VERSION 5.8 ;
BUSBITCHARS "[]" ;
DIVIDERCHAR "/" ;
UNITS
    DATABASE MICRONS 1000 ;
END UNITS

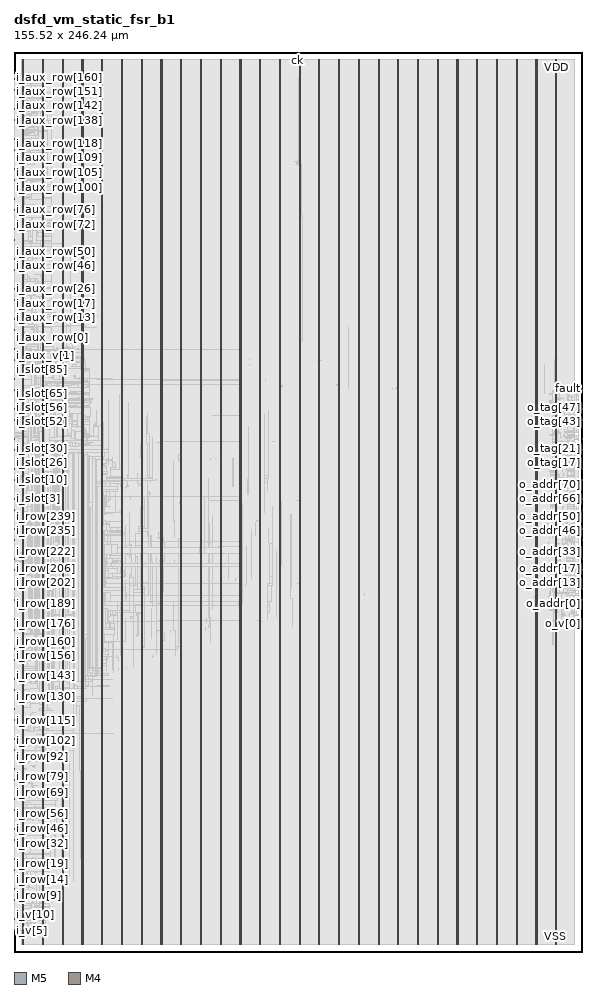
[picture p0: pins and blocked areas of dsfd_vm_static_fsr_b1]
MACRO dsfd_vm_static_fsr_b1
  FOREIGN dsfd_vm_static_fsr_b1 0 0 ;
  CLASS BLOCK ;
  SIZE 155.52 BY 246.24 ;
  PIN ck
    DIRECTION INPUT ;
    USE SIGNAL ;
    PORT
      LAYER M5 ;
        RECT  77.52 246.156 77.544 246.24 ;
    END
  END ck
  PIN fault
    DIRECTION OUTPUT ;
    USE SIGNAL ;
    PORT
      LAYER M4 ;
        RECT  155.436 154.176 155.52 154.2 ;
    END
  END fault
  PIN i_aux_row[0]
    DIRECTION INPUT ;
    USE SIGNAL ;
    PORT
      LAYER M4 ;
        RECT  0 168 0.084 168.024 ;
    END
  END i_aux_row[0]
  PIN i_aux_row[100]
    DIRECTION INPUT ;
    USE SIGNAL ;
    PORT
      LAYER M4 ;
        RECT  0 211.2 0.084 211.224 ;
    END
  END i_aux_row[100]
  PIN i_aux_row[101]
    DIRECTION INPUT ;
    USE SIGNAL ;
    PORT
      LAYER M4 ;
        RECT  0 211.632 0.084 211.656 ;
    END
  END i_aux_row[101]
  PIN i_aux_row[102]
    DIRECTION INPUT ;
    USE SIGNAL ;
    PORT
      LAYER M4 ;
        RECT  0 212.064 0.084 212.088 ;
    END
  END i_aux_row[102]
  PIN i_aux_row[103]
    DIRECTION INPUT ;
    USE SIGNAL ;
    PORT
      LAYER M4 ;
        RECT  0 212.496 0.084 212.52 ;
    END
  END i_aux_row[103]
  PIN i_aux_row[104]
    DIRECTION INPUT ;
    USE SIGNAL ;
    PORT
      LAYER M4 ;
        RECT  0 212.928 0.084 212.952 ;
    END
  END i_aux_row[104]
  PIN i_aux_row[105]
    DIRECTION INPUT ;
    USE SIGNAL ;
    PORT
      LAYER M4 ;
        RECT  0 213.36 0.084 213.384 ;
    END
  END i_aux_row[105]
  PIN i_aux_row[106]
    DIRECTION INPUT ;
    USE SIGNAL ;
    PORT
      LAYER M4 ;
        RECT  0 213.792 0.084 213.816 ;
    END
  END i_aux_row[106]
  PIN i_aux_row[107]
    DIRECTION INPUT ;
    USE SIGNAL ;
    PORT
      LAYER M4 ;
        RECT  0 214.224 0.084 214.248 ;
    END
  END i_aux_row[107]
  PIN i_aux_row[108]
    DIRECTION INPUT ;
    USE SIGNAL ;
    PORT
      LAYER M4 ;
        RECT  0 214.656 0.084 214.68 ;
    END
  END i_aux_row[108]
  PIN i_aux_row[109]
    DIRECTION INPUT ;
    USE SIGNAL ;
    PORT
      LAYER M4 ;
        RECT  0 215.088 0.084 215.112 ;
    END
  END i_aux_row[109]
  PIN i_aux_row[10]
    DIRECTION INPUT ;
    USE SIGNAL ;
    PORT
      LAYER M4 ;
        RECT  0 172.32 0.084 172.344 ;
    END
  END i_aux_row[10]
  PIN i_aux_row[110]
    DIRECTION INPUT ;
    USE SIGNAL ;
    PORT
      LAYER M4 ;
        RECT  0 215.52 0.084 215.544 ;
    END
  END i_aux_row[110]
  PIN i_aux_row[111]
    DIRECTION INPUT ;
    USE SIGNAL ;
    PORT
      LAYER M4 ;
        RECT  0 215.952 0.084 215.976 ;
    END
  END i_aux_row[111]
  PIN i_aux_row[112]
    DIRECTION INPUT ;
    USE SIGNAL ;
    PORT
      LAYER M4 ;
        RECT  0 216.384 0.084 216.408 ;
    END
  END i_aux_row[112]
  PIN i_aux_row[113]
    DIRECTION INPUT ;
    USE SIGNAL ;
    PORT
      LAYER M4 ;
        RECT  0 216.816 0.084 216.84 ;
    END
  END i_aux_row[113]
  PIN i_aux_row[114]
    DIRECTION INPUT ;
    USE SIGNAL ;
    PORT
      LAYER M4 ;
        RECT  0 217.248 0.084 217.272 ;
    END
  END i_aux_row[114]
  PIN i_aux_row[115]
    DIRECTION INPUT ;
    USE SIGNAL ;
    PORT
      LAYER M4 ;
        RECT  0 217.68 0.084 217.704 ;
    END
  END i_aux_row[115]
  PIN i_aux_row[116]
    DIRECTION INPUT ;
    USE SIGNAL ;
    PORT
      LAYER M4 ;
        RECT  0 218.112 0.084 218.136 ;
    END
  END i_aux_row[116]
  PIN i_aux_row[117]
    DIRECTION INPUT ;
    USE SIGNAL ;
    PORT
      LAYER M4 ;
        RECT  0 218.544 0.084 218.568 ;
    END
  END i_aux_row[117]
  PIN i_aux_row[118]
    DIRECTION INPUT ;
    USE SIGNAL ;
    PORT
      LAYER M4 ;
        RECT  0 218.976 0.084 219 ;
    END
  END i_aux_row[118]
  PIN i_aux_row[119]
    DIRECTION INPUT ;
    USE SIGNAL ;
    PORT
      LAYER M4 ;
        RECT  0 219.408 0.084 219.432 ;
    END
  END i_aux_row[119]
  PIN i_aux_row[11]
    DIRECTION INPUT ;
    USE SIGNAL ;
    PORT
      LAYER M4 ;
        RECT  0 172.752 0.084 172.776 ;
    END
  END i_aux_row[11]
  PIN i_aux_row[120]
    DIRECTION INPUT ;
    USE SIGNAL ;
    PORT
      LAYER M4 ;
        RECT  0 219.84 0.084 219.864 ;
    END
  END i_aux_row[120]
  PIN i_aux_row[121]
    DIRECTION INPUT ;
    USE SIGNAL ;
    PORT
      LAYER M4 ;
        RECT  0 220.272 0.084 220.296 ;
    END
  END i_aux_row[121]
  PIN i_aux_row[122]
    DIRECTION INPUT ;
    USE SIGNAL ;
    PORT
      LAYER M4 ;
        RECT  0 220.704 0.084 220.728 ;
    END
  END i_aux_row[122]
  PIN i_aux_row[123]
    DIRECTION INPUT ;
    USE SIGNAL ;
    PORT
      LAYER M4 ;
        RECT  0 221.136 0.084 221.16 ;
    END
  END i_aux_row[123]
  PIN i_aux_row[124]
    DIRECTION INPUT ;
    USE SIGNAL ;
    PORT
      LAYER M4 ;
        RECT  0 221.568 0.084 221.592 ;
    END
  END i_aux_row[124]
  PIN i_aux_row[125]
    DIRECTION INPUT ;
    USE SIGNAL ;
    PORT
      LAYER M4 ;
        RECT  0 222 0.084 222.024 ;
    END
  END i_aux_row[125]
  PIN i_aux_row[126]
    DIRECTION INPUT ;
    USE SIGNAL ;
    PORT
      LAYER M4 ;
        RECT  0 222.432 0.084 222.456 ;
    END
  END i_aux_row[126]
  PIN i_aux_row[127]
    DIRECTION INPUT ;
    USE SIGNAL ;
    PORT
      LAYER M4 ;
        RECT  0 222.864 0.084 222.888 ;
    END
  END i_aux_row[127]
  PIN i_aux_row[128]
    DIRECTION INPUT ;
    USE SIGNAL ;
    PORT
      LAYER M4 ;
        RECT  0 223.296 0.084 223.32 ;
    END
  END i_aux_row[128]
  PIN i_aux_row[129]
    DIRECTION INPUT ;
    USE SIGNAL ;
    PORT
      LAYER M4 ;
        RECT  0 223.728 0.084 223.752 ;
    END
  END i_aux_row[129]
  PIN i_aux_row[12]
    DIRECTION INPUT ;
    USE SIGNAL ;
    PORT
      LAYER M4 ;
        RECT  0 173.184 0.084 173.208 ;
    END
  END i_aux_row[12]
  PIN i_aux_row[130]
    DIRECTION INPUT ;
    USE SIGNAL ;
    PORT
      LAYER M4 ;
        RECT  0 224.16 0.084 224.184 ;
    END
  END i_aux_row[130]
  PIN i_aux_row[131]
    DIRECTION INPUT ;
    USE SIGNAL ;
    PORT
      LAYER M4 ;
        RECT  0 224.592 0.084 224.616 ;
    END
  END i_aux_row[131]
  PIN i_aux_row[132]
    DIRECTION INPUT ;
    USE SIGNAL ;
    PORT
      LAYER M4 ;
        RECT  0 225.024 0.084 225.048 ;
    END
  END i_aux_row[132]
  PIN i_aux_row[133]
    DIRECTION INPUT ;
    USE SIGNAL ;
    PORT
      LAYER M4 ;
        RECT  0 225.456 0.084 225.48 ;
    END
  END i_aux_row[133]
  PIN i_aux_row[134]
    DIRECTION INPUT ;
    USE SIGNAL ;
    PORT
      LAYER M4 ;
        RECT  0 225.888 0.084 225.912 ;
    END
  END i_aux_row[134]
  PIN i_aux_row[135]
    DIRECTION INPUT ;
    USE SIGNAL ;
    PORT
      LAYER M4 ;
        RECT  0 226.32 0.084 226.344 ;
    END
  END i_aux_row[135]
  PIN i_aux_row[136]
    DIRECTION INPUT ;
    USE SIGNAL ;
    PORT
      LAYER M4 ;
        RECT  0 226.752 0.084 226.776 ;
    END
  END i_aux_row[136]
  PIN i_aux_row[137]
    DIRECTION INPUT ;
    USE SIGNAL ;
    PORT
      LAYER M4 ;
        RECT  0 227.184 0.084 227.208 ;
    END
  END i_aux_row[137]
  PIN i_aux_row[138]
    DIRECTION INPUT ;
    USE SIGNAL ;
    PORT
      LAYER M4 ;
        RECT  0 227.616 0.084 227.64 ;
    END
  END i_aux_row[138]
  PIN i_aux_row[139]
    DIRECTION INPUT ;
    USE SIGNAL ;
    PORT
      LAYER M4 ;
        RECT  0 228.048 0.084 228.072 ;
    END
  END i_aux_row[139]
  PIN i_aux_row[13]
    DIRECTION INPUT ;
    USE SIGNAL ;
    PORT
      LAYER M4 ;
        RECT  0 173.616 0.084 173.64 ;
    END
  END i_aux_row[13]
  PIN i_aux_row[140]
    DIRECTION INPUT ;
    USE SIGNAL ;
    PORT
      LAYER M4 ;
        RECT  0 228.48 0.084 228.504 ;
    END
  END i_aux_row[140]
  PIN i_aux_row[141]
    DIRECTION INPUT ;
    USE SIGNAL ;
    PORT
      LAYER M4 ;
        RECT  0 228.912 0.084 228.936 ;
    END
  END i_aux_row[141]
  PIN i_aux_row[142]
    DIRECTION INPUT ;
    USE SIGNAL ;
    PORT
      LAYER M4 ;
        RECT  0 229.344 0.084 229.368 ;
    END
  END i_aux_row[142]
  PIN i_aux_row[143]
    DIRECTION INPUT ;
    USE SIGNAL ;
    PORT
      LAYER M4 ;
        RECT  0 229.776 0.084 229.8 ;
    END
  END i_aux_row[143]
  PIN i_aux_row[144]
    DIRECTION INPUT ;
    USE SIGNAL ;
    PORT
      LAYER M4 ;
        RECT  0 230.208 0.084 230.232 ;
    END
  END i_aux_row[144]
  PIN i_aux_row[145]
    DIRECTION INPUT ;
    USE SIGNAL ;
    PORT
      LAYER M4 ;
        RECT  0 230.64 0.084 230.664 ;
    END
  END i_aux_row[145]
  PIN i_aux_row[146]
    DIRECTION INPUT ;
    USE SIGNAL ;
    PORT
      LAYER M4 ;
        RECT  0 231.072 0.084 231.096 ;
    END
  END i_aux_row[146]
  PIN i_aux_row[147]
    DIRECTION INPUT ;
    USE SIGNAL ;
    PORT
      LAYER M4 ;
        RECT  0 231.504 0.084 231.528 ;
    END
  END i_aux_row[147]
  PIN i_aux_row[148]
    DIRECTION INPUT ;
    USE SIGNAL ;
    PORT
      LAYER M4 ;
        RECT  0 231.936 0.084 231.96 ;
    END
  END i_aux_row[148]
  PIN i_aux_row[149]
    DIRECTION INPUT ;
    USE SIGNAL ;
    PORT
      LAYER M4 ;
        RECT  0 232.368 0.084 232.392 ;
    END
  END i_aux_row[149]
  PIN i_aux_row[14]
    DIRECTION INPUT ;
    USE SIGNAL ;
    PORT
      LAYER M4 ;
        RECT  0 174.048 0.084 174.072 ;
    END
  END i_aux_row[14]
  PIN i_aux_row[150]
    DIRECTION INPUT ;
    USE SIGNAL ;
    PORT
      LAYER M4 ;
        RECT  0 232.8 0.084 232.824 ;
    END
  END i_aux_row[150]
  PIN i_aux_row[151]
    DIRECTION INPUT ;
    USE SIGNAL ;
    PORT
      LAYER M4 ;
        RECT  0 233.232 0.084 233.256 ;
    END
  END i_aux_row[151]
  PIN i_aux_row[152]
    DIRECTION INPUT ;
    USE SIGNAL ;
    PORT
      LAYER M4 ;
        RECT  0 233.664 0.084 233.688 ;
    END
  END i_aux_row[152]
  PIN i_aux_row[153]
    DIRECTION INPUT ;
    USE SIGNAL ;
    PORT
      LAYER M4 ;
        RECT  0 234.096 0.084 234.12 ;
    END
  END i_aux_row[153]
  PIN i_aux_row[154]
    DIRECTION INPUT ;
    USE SIGNAL ;
    PORT
      LAYER M4 ;
        RECT  0 234.528 0.084 234.552 ;
    END
  END i_aux_row[154]
  PIN i_aux_row[155]
    DIRECTION INPUT ;
    USE SIGNAL ;
    PORT
      LAYER M4 ;
        RECT  0 234.96 0.084 234.984 ;
    END
  END i_aux_row[155]
  PIN i_aux_row[156]
    DIRECTION INPUT ;
    USE SIGNAL ;
    PORT
      LAYER M4 ;
        RECT  0 235.392 0.084 235.416 ;
    END
  END i_aux_row[156]
  PIN i_aux_row[157]
    DIRECTION INPUT ;
    USE SIGNAL ;
    PORT
      LAYER M4 ;
        RECT  0 235.824 0.084 235.848 ;
    END
  END i_aux_row[157]
  PIN i_aux_row[158]
    DIRECTION INPUT ;
    USE SIGNAL ;
    PORT
      LAYER M4 ;
        RECT  0 236.256 0.084 236.28 ;
    END
  END i_aux_row[158]
  PIN i_aux_row[159]
    DIRECTION INPUT ;
    USE SIGNAL ;
    PORT
      LAYER M4 ;
        RECT  0 236.688 0.084 236.712 ;
    END
  END i_aux_row[159]
  PIN i_aux_row[15]
    DIRECTION INPUT ;
    USE SIGNAL ;
    PORT
      LAYER M4 ;
        RECT  0 174.48 0.084 174.504 ;
    END
  END i_aux_row[15]
  PIN i_aux_row[160]
    DIRECTION INPUT ;
    USE SIGNAL ;
    PORT
      LAYER M4 ;
        RECT  0 237.12 0.084 237.144 ;
    END
  END i_aux_row[160]
  PIN i_aux_row[161]
    DIRECTION INPUT ;
    USE SIGNAL ;
    PORT
      LAYER M4 ;
        RECT  0 237.552 0.084 237.576 ;
    END
  END i_aux_row[161]
  PIN i_aux_row[162]
    DIRECTION INPUT ;
    USE SIGNAL ;
    PORT
      LAYER M4 ;
        RECT  0 237.984 0.084 238.008 ;
    END
  END i_aux_row[162]
  PIN i_aux_row[163]
    DIRECTION INPUT ;
    USE SIGNAL ;
    PORT
      LAYER M4 ;
        RECT  0 238.416 0.084 238.44 ;
    END
  END i_aux_row[163]
  PIN i_aux_row[164]
    DIRECTION INPUT ;
    USE SIGNAL ;
    PORT
      LAYER M4 ;
        RECT  0 238.848 0.084 238.872 ;
    END
  END i_aux_row[164]
  PIN i_aux_row[165]
    DIRECTION INPUT ;
    USE SIGNAL ;
    PORT
      LAYER M4 ;
        RECT  0 239.28 0.084 239.304 ;
    END
  END i_aux_row[165]
  PIN i_aux_row[166]
    DIRECTION INPUT ;
    USE SIGNAL ;
    PORT
      LAYER M4 ;
        RECT  0 239.712 0.084 239.736 ;
    END
  END i_aux_row[166]
  PIN i_aux_row[167]
    DIRECTION INPUT ;
    USE SIGNAL ;
    PORT
      LAYER M4 ;
        RECT  0 240.144 0.084 240.168 ;
    END
  END i_aux_row[167]
  PIN i_aux_row[16]
    DIRECTION INPUT ;
    USE SIGNAL ;
    PORT
      LAYER M4 ;
        RECT  0 174.912 0.084 174.936 ;
    END
  END i_aux_row[16]
  PIN i_aux_row[17]
    DIRECTION INPUT ;
    USE SIGNAL ;
    PORT
      LAYER M4 ;
        RECT  0 175.344 0.084 175.368 ;
    END
  END i_aux_row[17]
  PIN i_aux_row[18]
    DIRECTION INPUT ;
    USE SIGNAL ;
    PORT
      LAYER M4 ;
        RECT  0 175.776 0.084 175.8 ;
    END
  END i_aux_row[18]
  PIN i_aux_row[19]
    DIRECTION INPUT ;
    USE SIGNAL ;
    PORT
      LAYER M4 ;
        RECT  0 176.208 0.084 176.232 ;
    END
  END i_aux_row[19]
  PIN i_aux_row[1]
    DIRECTION INPUT ;
    USE SIGNAL ;
    PORT
      LAYER M4 ;
        RECT  0 168.432 0.084 168.456 ;
    END
  END i_aux_row[1]
  PIN i_aux_row[20]
    DIRECTION INPUT ;
    USE SIGNAL ;
    PORT
      LAYER M4 ;
        RECT  0 176.64 0.084 176.664 ;
    END
  END i_aux_row[20]
  PIN i_aux_row[21]
    DIRECTION INPUT ;
    USE SIGNAL ;
    PORT
      LAYER M4 ;
        RECT  0 177.072 0.084 177.096 ;
    END
  END i_aux_row[21]
  PIN i_aux_row[22]
    DIRECTION INPUT ;
    USE SIGNAL ;
    PORT
      LAYER M4 ;
        RECT  0 177.504 0.084 177.528 ;
    END
  END i_aux_row[22]
  PIN i_aux_row[23]
    DIRECTION INPUT ;
    USE SIGNAL ;
    PORT
      LAYER M4 ;
        RECT  0 177.936 0.084 177.96 ;
    END
  END i_aux_row[23]
  PIN i_aux_row[24]
    DIRECTION INPUT ;
    USE SIGNAL ;
    PORT
      LAYER M4 ;
        RECT  0 178.368 0.084 178.392 ;
    END
  END i_aux_row[24]
  PIN i_aux_row[25]
    DIRECTION INPUT ;
    USE SIGNAL ;
    PORT
      LAYER M4 ;
        RECT  0 178.8 0.084 178.824 ;
    END
  END i_aux_row[25]
  PIN i_aux_row[26]
    DIRECTION INPUT ;
    USE SIGNAL ;
    PORT
      LAYER M4 ;
        RECT  0 179.232 0.084 179.256 ;
    END
  END i_aux_row[26]
  PIN i_aux_row[27]
    DIRECTION INPUT ;
    USE SIGNAL ;
    PORT
      LAYER M4 ;
        RECT  0 179.664 0.084 179.688 ;
    END
  END i_aux_row[27]
  PIN i_aux_row[28]
    DIRECTION INPUT ;
    USE SIGNAL ;
    PORT
      LAYER M4 ;
        RECT  0 180.096 0.084 180.12 ;
    END
  END i_aux_row[28]
  PIN i_aux_row[29]
    DIRECTION INPUT ;
    USE SIGNAL ;
    PORT
      LAYER M4 ;
        RECT  0 180.528 0.084 180.552 ;
    END
  END i_aux_row[29]
  PIN i_aux_row[2]
    DIRECTION INPUT ;
    USE SIGNAL ;
    PORT
      LAYER M4 ;
        RECT  0 168.864 0.084 168.888 ;
    END
  END i_aux_row[2]
  PIN i_aux_row[30]
    DIRECTION INPUT ;
    USE SIGNAL ;
    PORT
      LAYER M4 ;
        RECT  0 180.96 0.084 180.984 ;
    END
  END i_aux_row[30]
  PIN i_aux_row[31]
    DIRECTION INPUT ;
    USE SIGNAL ;
    PORT
      LAYER M4 ;
        RECT  0 181.392 0.084 181.416 ;
    END
  END i_aux_row[31]
  PIN i_aux_row[32]
    DIRECTION INPUT ;
    USE SIGNAL ;
    PORT
      LAYER M4 ;
        RECT  0 181.824 0.084 181.848 ;
    END
  END i_aux_row[32]
  PIN i_aux_row[33]
    DIRECTION INPUT ;
    USE SIGNAL ;
    PORT
      LAYER M4 ;
        RECT  0 182.256 0.084 182.28 ;
    END
  END i_aux_row[33]
  PIN i_aux_row[34]
    DIRECTION INPUT ;
    USE SIGNAL ;
    PORT
      LAYER M4 ;
        RECT  0 182.688 0.084 182.712 ;
    END
  END i_aux_row[34]
  PIN i_aux_row[35]
    DIRECTION INPUT ;
    USE SIGNAL ;
    PORT
      LAYER M4 ;
        RECT  0 183.12 0.084 183.144 ;
    END
  END i_aux_row[35]
  PIN i_aux_row[36]
    DIRECTION INPUT ;
    USE SIGNAL ;
    PORT
      LAYER M4 ;
        RECT  0 183.552 0.084 183.576 ;
    END
  END i_aux_row[36]
  PIN i_aux_row[37]
    DIRECTION INPUT ;
    USE SIGNAL ;
    PORT
      LAYER M4 ;
        RECT  0 183.984 0.084 184.008 ;
    END
  END i_aux_row[37]
  PIN i_aux_row[38]
    DIRECTION INPUT ;
    USE SIGNAL ;
    PORT
      LAYER M4 ;
        RECT  0 184.416 0.084 184.44 ;
    END
  END i_aux_row[38]
  PIN i_aux_row[39]
    DIRECTION INPUT ;
    USE SIGNAL ;
    PORT
      LAYER M4 ;
        RECT  0 184.848 0.084 184.872 ;
    END
  END i_aux_row[39]
  PIN i_aux_row[3]
    DIRECTION INPUT ;
    USE SIGNAL ;
    PORT
      LAYER M4 ;
        RECT  0 169.296 0.084 169.32 ;
    END
  END i_aux_row[3]
  PIN i_aux_row[40]
    DIRECTION INPUT ;
    USE SIGNAL ;
    PORT
      LAYER M4 ;
        RECT  0 185.28 0.084 185.304 ;
    END
  END i_aux_row[40]
  PIN i_aux_row[41]
    DIRECTION INPUT ;
    USE SIGNAL ;
    PORT
      LAYER M4 ;
        RECT  0 185.712 0.084 185.736 ;
    END
  END i_aux_row[41]
  PIN i_aux_row[42]
    DIRECTION INPUT ;
    USE SIGNAL ;
    PORT
      LAYER M4 ;
        RECT  0 186.144 0.084 186.168 ;
    END
  END i_aux_row[42]
  PIN i_aux_row[43]
    DIRECTION INPUT ;
    USE SIGNAL ;
    PORT
      LAYER M4 ;
        RECT  0 186.576 0.084 186.6 ;
    END
  END i_aux_row[43]
  PIN i_aux_row[44]
    DIRECTION INPUT ;
    USE SIGNAL ;
    PORT
      LAYER M4 ;
        RECT  0 187.008 0.084 187.032 ;
    END
  END i_aux_row[44]
  PIN i_aux_row[45]
    DIRECTION INPUT ;
    USE SIGNAL ;
    PORT
      LAYER M4 ;
        RECT  0 187.44 0.084 187.464 ;
    END
  END i_aux_row[45]
  PIN i_aux_row[46]
    DIRECTION INPUT ;
    USE SIGNAL ;
    PORT
      LAYER M4 ;
        RECT  0 187.872 0.084 187.896 ;
    END
  END i_aux_row[46]
  PIN i_aux_row[47]
    DIRECTION INPUT ;
    USE SIGNAL ;
    PORT
      LAYER M4 ;
        RECT  0 188.304 0.084 188.328 ;
    END
  END i_aux_row[47]
  PIN i_aux_row[48]
    DIRECTION INPUT ;
    USE SIGNAL ;
    PORT
      LAYER M4 ;
        RECT  0 188.736 0.084 188.76 ;
    END
  END i_aux_row[48]
  PIN i_aux_row[49]
    DIRECTION INPUT ;
    USE SIGNAL ;
    PORT
      LAYER M4 ;
        RECT  0 189.168 0.084 189.192 ;
    END
  END i_aux_row[49]
  PIN i_aux_row[4]
    DIRECTION INPUT ;
    USE SIGNAL ;
    PORT
      LAYER M4 ;
        RECT  0 169.728 0.084 169.752 ;
    END
  END i_aux_row[4]
  PIN i_aux_row[50]
    DIRECTION INPUT ;
    USE SIGNAL ;
    PORT
      LAYER M4 ;
        RECT  0 189.6 0.084 189.624 ;
    END
  END i_aux_row[50]
  PIN i_aux_row[51]
    DIRECTION INPUT ;
    USE SIGNAL ;
    PORT
      LAYER M4 ;
        RECT  0 190.032 0.084 190.056 ;
    END
  END i_aux_row[51]
  PIN i_aux_row[52]
    DIRECTION INPUT ;
    USE SIGNAL ;
    PORT
      LAYER M4 ;
        RECT  0 190.464 0.084 190.488 ;
    END
  END i_aux_row[52]
  PIN i_aux_row[53]
    DIRECTION INPUT ;
    USE SIGNAL ;
    PORT
      LAYER M4 ;
        RECT  0 190.896 0.084 190.92 ;
    END
  END i_aux_row[53]
  PIN i_aux_row[54]
    DIRECTION INPUT ;
    USE SIGNAL ;
    PORT
      LAYER M4 ;
        RECT  0 191.328 0.084 191.352 ;
    END
  END i_aux_row[54]
  PIN i_aux_row[55]
    DIRECTION INPUT ;
    USE SIGNAL ;
    PORT
      LAYER M4 ;
        RECT  0 191.76 0.084 191.784 ;
    END
  END i_aux_row[55]
  PIN i_aux_row[56]
    DIRECTION INPUT ;
    USE SIGNAL ;
    PORT
      LAYER M4 ;
        RECT  0 192.192 0.084 192.216 ;
    END
  END i_aux_row[56]
  PIN i_aux_row[57]
    DIRECTION INPUT ;
    USE SIGNAL ;
    PORT
      LAYER M4 ;
        RECT  0 192.624 0.084 192.648 ;
    END
  END i_aux_row[57]
  PIN i_aux_row[58]
    DIRECTION INPUT ;
    USE SIGNAL ;
    PORT
      LAYER M4 ;
        RECT  0 193.056 0.084 193.08 ;
    END
  END i_aux_row[58]
  PIN i_aux_row[59]
    DIRECTION INPUT ;
    USE SIGNAL ;
    PORT
      LAYER M4 ;
        RECT  0 193.488 0.084 193.512 ;
    END
  END i_aux_row[59]
  PIN i_aux_row[5]
    DIRECTION INPUT ;
    USE SIGNAL ;
    PORT
      LAYER M4 ;
        RECT  0 170.16 0.084 170.184 ;
    END
  END i_aux_row[5]
  PIN i_aux_row[60]
    DIRECTION INPUT ;
    USE SIGNAL ;
    PORT
      LAYER M4 ;
        RECT  0 193.92 0.084 193.944 ;
    END
  END i_aux_row[60]
  PIN i_aux_row[61]
    DIRECTION INPUT ;
    USE SIGNAL ;
    PORT
      LAYER M4 ;
        RECT  0 194.352 0.084 194.376 ;
    END
  END i_aux_row[61]
  PIN i_aux_row[62]
    DIRECTION INPUT ;
    USE SIGNAL ;
    PORT
      LAYER M4 ;
        RECT  0 194.784 0.084 194.808 ;
    END
  END i_aux_row[62]
  PIN i_aux_row[63]
    DIRECTION INPUT ;
    USE SIGNAL ;
    PORT
      LAYER M4 ;
        RECT  0 195.216 0.084 195.24 ;
    END
  END i_aux_row[63]
  PIN i_aux_row[64]
    DIRECTION INPUT ;
    USE SIGNAL ;
    PORT
      LAYER M4 ;
        RECT  0 195.648 0.084 195.672 ;
    END
  END i_aux_row[64]
  PIN i_aux_row[65]
    DIRECTION INPUT ;
    USE SIGNAL ;
    PORT
      LAYER M4 ;
        RECT  0 196.08 0.084 196.104 ;
    END
  END i_aux_row[65]
  PIN i_aux_row[66]
    DIRECTION INPUT ;
    USE SIGNAL ;
    PORT
      LAYER M4 ;
        RECT  0 196.512 0.084 196.536 ;
    END
  END i_aux_row[66]
  PIN i_aux_row[67]
    DIRECTION INPUT ;
    USE SIGNAL ;
    PORT
      LAYER M4 ;
        RECT  0 196.944 0.084 196.968 ;
    END
  END i_aux_row[67]
  PIN i_aux_row[68]
    DIRECTION INPUT ;
    USE SIGNAL ;
    PORT
      LAYER M4 ;
        RECT  0 197.376 0.084 197.4 ;
    END
  END i_aux_row[68]
  PIN i_aux_row[69]
    DIRECTION INPUT ;
    USE SIGNAL ;
    PORT
      LAYER M4 ;
        RECT  0 197.808 0.084 197.832 ;
    END
  END i_aux_row[69]
  PIN i_aux_row[6]
    DIRECTION INPUT ;
    USE SIGNAL ;
    PORT
      LAYER M4 ;
        RECT  0 170.592 0.084 170.616 ;
    END
  END i_aux_row[6]
  PIN i_aux_row[70]
    DIRECTION INPUT ;
    USE SIGNAL ;
    PORT
      LAYER M4 ;
        RECT  0 198.24 0.084 198.264 ;
    END
  END i_aux_row[70]
  PIN i_aux_row[71]
    DIRECTION INPUT ;
    USE SIGNAL ;
    PORT
      LAYER M4 ;
        RECT  0 198.672 0.084 198.696 ;
    END
  END i_aux_row[71]
  PIN i_aux_row[72]
    DIRECTION INPUT ;
    USE SIGNAL ;
    PORT
      LAYER M4 ;
        RECT  0 199.104 0.084 199.128 ;
    END
  END i_aux_row[72]
  PIN i_aux_row[73]
    DIRECTION INPUT ;
    USE SIGNAL ;
    PORT
      LAYER M4 ;
        RECT  0 199.536 0.084 199.56 ;
    END
  END i_aux_row[73]
  PIN i_aux_row[74]
    DIRECTION INPUT ;
    USE SIGNAL ;
    PORT
      LAYER M4 ;
        RECT  0 199.968 0.084 199.992 ;
    END
  END i_aux_row[74]
  PIN i_aux_row[75]
    DIRECTION INPUT ;
    USE SIGNAL ;
    PORT
      LAYER M4 ;
        RECT  0 200.4 0.084 200.424 ;
    END
  END i_aux_row[75]
  PIN i_aux_row[76]
    DIRECTION INPUT ;
    USE SIGNAL ;
    PORT
      LAYER M4 ;
        RECT  0 200.832 0.084 200.856 ;
    END
  END i_aux_row[76]
  PIN i_aux_row[77]
    DIRECTION INPUT ;
    USE SIGNAL ;
    PORT
      LAYER M4 ;
        RECT  0 201.264 0.084 201.288 ;
    END
  END i_aux_row[77]
  PIN i_aux_row[78]
    DIRECTION INPUT ;
    USE SIGNAL ;
    PORT
      LAYER M4 ;
        RECT  0 201.696 0.084 201.72 ;
    END
  END i_aux_row[78]
  PIN i_aux_row[79]
    DIRECTION INPUT ;
    USE SIGNAL ;
    PORT
      LAYER M4 ;
        RECT  0 202.128 0.084 202.152 ;
    END
  END i_aux_row[79]
  PIN i_aux_row[7]
    DIRECTION INPUT ;
    USE SIGNAL ;
    PORT
      LAYER M4 ;
        RECT  0 171.024 0.084 171.048 ;
    END
  END i_aux_row[7]
  PIN i_aux_row[80]
    DIRECTION INPUT ;
    USE SIGNAL ;
    PORT
      LAYER M4 ;
        RECT  0 202.56 0.084 202.584 ;
    END
  END i_aux_row[80]
  PIN i_aux_row[81]
    DIRECTION INPUT ;
    USE SIGNAL ;
    PORT
      LAYER M4 ;
        RECT  0 202.992 0.084 203.016 ;
    END
  END i_aux_row[81]
  PIN i_aux_row[82]
    DIRECTION INPUT ;
    USE SIGNAL ;
    PORT
      LAYER M4 ;
        RECT  0 203.424 0.084 203.448 ;
    END
  END i_aux_row[82]
  PIN i_aux_row[83]
    DIRECTION INPUT ;
    USE SIGNAL ;
    PORT
      LAYER M4 ;
        RECT  0 203.856 0.084 203.88 ;
    END
  END i_aux_row[83]
  PIN i_aux_row[84]
    DIRECTION INPUT ;
    USE SIGNAL ;
    PORT
      LAYER M4 ;
        RECT  0 204.288 0.084 204.312 ;
    END
  END i_aux_row[84]
  PIN i_aux_row[85]
    DIRECTION INPUT ;
    USE SIGNAL ;
    PORT
      LAYER M4 ;
        RECT  0 204.72 0.084 204.744 ;
    END
  END i_aux_row[85]
  PIN i_aux_row[86]
    DIRECTION INPUT ;
    USE SIGNAL ;
    PORT
      LAYER M4 ;
        RECT  0 205.152 0.084 205.176 ;
    END
  END i_aux_row[86]
  PIN i_aux_row[87]
    DIRECTION INPUT ;
    USE SIGNAL ;
    PORT
      LAYER M4 ;
        RECT  0 205.584 0.084 205.608 ;
    END
  END i_aux_row[87]
  PIN i_aux_row[88]
    DIRECTION INPUT ;
    USE SIGNAL ;
    PORT
      LAYER M4 ;
        RECT  0 206.016 0.084 206.04 ;
    END
  END i_aux_row[88]
  PIN i_aux_row[89]
    DIRECTION INPUT ;
    USE SIGNAL ;
    PORT
      LAYER M4 ;
        RECT  0 206.448 0.084 206.472 ;
    END
  END i_aux_row[89]
  PIN i_aux_row[8]
    DIRECTION INPUT ;
    USE SIGNAL ;
    PORT
      LAYER M4 ;
        RECT  0 171.456 0.084 171.48 ;
    END
  END i_aux_row[8]
  PIN i_aux_row[90]
    DIRECTION INPUT ;
    USE SIGNAL ;
    PORT
      LAYER M4 ;
        RECT  0 206.88 0.084 206.904 ;
    END
  END i_aux_row[90]
  PIN i_aux_row[91]
    DIRECTION INPUT ;
    USE SIGNAL ;
    PORT
      LAYER M4 ;
        RECT  0 207.312 0.084 207.336 ;
    END
  END i_aux_row[91]
  PIN i_aux_row[92]
    DIRECTION INPUT ;
    USE SIGNAL ;
    PORT
      LAYER M4 ;
        RECT  0 207.744 0.084 207.768 ;
    END
  END i_aux_row[92]
  PIN i_aux_row[93]
    DIRECTION INPUT ;
    USE SIGNAL ;
    PORT
      LAYER M4 ;
        RECT  0 208.176 0.084 208.2 ;
    END
  END i_aux_row[93]
  PIN i_aux_row[94]
    DIRECTION INPUT ;
    USE SIGNAL ;
    PORT
      LAYER M4 ;
        RECT  0 208.608 0.084 208.632 ;
    END
  END i_aux_row[94]
  PIN i_aux_row[95]
    DIRECTION INPUT ;
    USE SIGNAL ;
    PORT
      LAYER M4 ;
        RECT  0 209.04 0.084 209.064 ;
    END
  END i_aux_row[95]
  PIN i_aux_row[96]
    DIRECTION INPUT ;
    USE SIGNAL ;
    PORT
      LAYER M4 ;
        RECT  0 209.472 0.084 209.496 ;
    END
  END i_aux_row[96]
  PIN i_aux_row[97]
    DIRECTION INPUT ;
    USE SIGNAL ;
    PORT
      LAYER M4 ;
        RECT  0 209.904 0.084 209.928 ;
    END
  END i_aux_row[97]
  PIN i_aux_row[98]
    DIRECTION INPUT ;
    USE SIGNAL ;
    PORT
      LAYER M4 ;
        RECT  0 210.336 0.084 210.36 ;
    END
  END i_aux_row[98]
  PIN i_aux_row[99]
    DIRECTION INPUT ;
    USE SIGNAL ;
    PORT
      LAYER M4 ;
        RECT  0 210.768 0.084 210.792 ;
    END
  END i_aux_row[99]
  PIN i_aux_row[9]
    DIRECTION INPUT ;
    USE SIGNAL ;
    PORT
      LAYER M4 ;
        RECT  0 171.888 0.084 171.912 ;
    END
  END i_aux_row[9]
  PIN i_aux_v[0]
    DIRECTION INPUT ;
    USE SIGNAL ;
    PORT
      LAYER M4 ;
        RECT  0 162.816 0.084 162.84 ;
    END
  END i_aux_v[0]
  PIN i_aux_v[10]
    DIRECTION INPUT ;
    USE SIGNAL ;
    PORT
      LAYER M4 ;
        RECT  0 167.136 0.084 167.16 ;
    END
  END i_aux_v[10]
  PIN i_aux_v[11]
    DIRECTION INPUT ;
    USE SIGNAL ;
    PORT
      LAYER M4 ;
        RECT  0 167.568 0.084 167.592 ;
    END
  END i_aux_v[11]
  PIN i_aux_v[1]
    DIRECTION INPUT ;
    USE SIGNAL ;
    PORT
      LAYER M4 ;
        RECT  0 163.248 0.084 163.272 ;
    END
  END i_aux_v[1]
  PIN i_aux_v[2]
    DIRECTION INPUT ;
    USE SIGNAL ;
    PORT
      LAYER M4 ;
        RECT  0 163.68 0.084 163.704 ;
    END
  END i_aux_v[2]
  PIN i_aux_v[3]
    DIRECTION INPUT ;
    USE SIGNAL ;
    PORT
      LAYER M4 ;
        RECT  0 164.112 0.084 164.136 ;
    END
  END i_aux_v[3]
  PIN i_aux_v[4]
    DIRECTION INPUT ;
    USE SIGNAL ;
    PORT
      LAYER M4 ;
        RECT  0 164.544 0.084 164.568 ;
    END
  END i_aux_v[4]
  PIN i_aux_v[5]
    DIRECTION INPUT ;
    USE SIGNAL ;
    PORT
      LAYER M4 ;
        RECT  0 164.976 0.084 165 ;
    END
  END i_aux_v[5]
  PIN i_aux_v[6]
    DIRECTION INPUT ;
    USE SIGNAL ;
    PORT
      LAYER M4 ;
        RECT  0 165.408 0.084 165.432 ;
    END
  END i_aux_v[6]
  PIN i_aux_v[7]
    DIRECTION INPUT ;
    USE SIGNAL ;
    PORT
      LAYER M4 ;
        RECT  0 165.84 0.084 165.864 ;
    END
  END i_aux_v[7]
  PIN i_aux_v[8]
    DIRECTION INPUT ;
    USE SIGNAL ;
    PORT
      LAYER M4 ;
        RECT  0 166.272 0.084 166.296 ;
    END
  END i_aux_v[8]
  PIN i_aux_v[9]
    DIRECTION INPUT ;
    USE SIGNAL ;
    PORT
      LAYER M4 ;
        RECT  0 166.704 0.084 166.728 ;
    END
  END i_aux_v[9]
  PIN i_group[0]
    DIRECTION INPUT ;
    USE SIGNAL ;
    PORT
      LAYER M4 ;
        RECT  0 161.52 0.084 161.544 ;
    END
  END i_group[0]
  PIN i_group[1]
    DIRECTION INPUT ;
    USE SIGNAL ;
    PORT
      LAYER M4 ;
        RECT  0 161.952 0.084 161.976 ;
    END
  END i_group[1]
  PIN i_group[2]
    DIRECTION INPUT ;
    USE SIGNAL ;
    PORT
      LAYER M4 ;
        RECT  0 162.384 0.084 162.408 ;
    END
  END i_group[2]
  PIN i_row[0]
    DIRECTION INPUT ;
    USE SIGNAL ;
    PORT
      LAYER M4 ;
        RECT  0 13.776 0.084 13.8 ;
    END
  END i_row[0]
  PIN i_row[100]
    DIRECTION INPUT ;
    USE SIGNAL ;
    PORT
      LAYER M4 ;
        RECT  0 56.976 0.084 57 ;
    END
  END i_row[100]
  PIN i_row[101]
    DIRECTION INPUT ;
    USE SIGNAL ;
    PORT
      LAYER M4 ;
        RECT  0 57.408 0.084 57.432 ;
    END
  END i_row[101]
  PIN i_row[102]
    DIRECTION INPUT ;
    USE SIGNAL ;
    PORT
      LAYER M4 ;
        RECT  0 57.84 0.084 57.864 ;
    END
  END i_row[102]
  PIN i_row[103]
    DIRECTION INPUT ;
    USE SIGNAL ;
    PORT
      LAYER M4 ;
        RECT  0 58.272 0.084 58.296 ;
    END
  END i_row[103]
  PIN i_row[104]
    DIRECTION INPUT ;
    USE SIGNAL ;
    PORT
      LAYER M4 ;
        RECT  0 58.704 0.084 58.728 ;
    END
  END i_row[104]
  PIN i_row[105]
    DIRECTION INPUT ;
    USE SIGNAL ;
    PORT
      LAYER M4 ;
        RECT  0 59.136 0.084 59.16 ;
    END
  END i_row[105]
  PIN i_row[106]
    DIRECTION INPUT ;
    USE SIGNAL ;
    PORT
      LAYER M4 ;
        RECT  0 59.568 0.084 59.592 ;
    END
  END i_row[106]
  PIN i_row[107]
    DIRECTION INPUT ;
    USE SIGNAL ;
    PORT
      LAYER M4 ;
        RECT  0 60 0.084 60.024 ;
    END
  END i_row[107]
  PIN i_row[108]
    DIRECTION INPUT ;
    USE SIGNAL ;
    PORT
      LAYER M4 ;
        RECT  0 60.432 0.084 60.456 ;
    END
  END i_row[108]
  PIN i_row[109]
    DIRECTION INPUT ;
    USE SIGNAL ;
    PORT
      LAYER M4 ;
        RECT  0 60.864 0.084 60.888 ;
    END
  END i_row[109]
  PIN i_row[10]
    DIRECTION INPUT ;
    USE SIGNAL ;
    PORT
      LAYER M4 ;
        RECT  0 18.096 0.084 18.12 ;
    END
  END i_row[10]
  PIN i_row[110]
    DIRECTION INPUT ;
    USE SIGNAL ;
    PORT
      LAYER M4 ;
        RECT  0 61.296 0.084 61.32 ;
    END
  END i_row[110]
  PIN i_row[111]
    DIRECTION INPUT ;
    USE SIGNAL ;
    PORT
      LAYER M4 ;
        RECT  0 61.728 0.084 61.752 ;
    END
  END i_row[111]
  PIN i_row[112]
    DIRECTION INPUT ;
    USE SIGNAL ;
    PORT
      LAYER M4 ;
        RECT  0 62.16 0.084 62.184 ;
    END
  END i_row[112]
  PIN i_row[113]
    DIRECTION INPUT ;
    USE SIGNAL ;
    PORT
      LAYER M4 ;
        RECT  0 62.592 0.084 62.616 ;
    END
  END i_row[113]
  PIN i_row[114]
    DIRECTION INPUT ;
    USE SIGNAL ;
    PORT
      LAYER M4 ;
        RECT  0 63.024 0.084 63.048 ;
    END
  END i_row[114]
  PIN i_row[115]
    DIRECTION INPUT ;
    USE SIGNAL ;
    PORT
      LAYER M4 ;
        RECT  0 63.456 0.084 63.48 ;
    END
  END i_row[115]
  PIN i_row[116]
    DIRECTION INPUT ;
    USE SIGNAL ;
    PORT
      LAYER M4 ;
        RECT  0 63.888 0.084 63.912 ;
    END
  END i_row[116]
  PIN i_row[117]
    DIRECTION INPUT ;
    USE SIGNAL ;
    PORT
      LAYER M4 ;
        RECT  0 64.32 0.084 64.344 ;
    END
  END i_row[117]
  PIN i_row[118]
    DIRECTION INPUT ;
    USE SIGNAL ;
    PORT
      LAYER M4 ;
        RECT  0 64.752 0.084 64.776 ;
    END
  END i_row[118]
  PIN i_row[119]
    DIRECTION INPUT ;
    USE SIGNAL ;
    PORT
      LAYER M4 ;
        RECT  0 65.184 0.084 65.208 ;
    END
  END i_row[119]
  PIN i_row[11]
    DIRECTION INPUT ;
    USE SIGNAL ;
    PORT
      LAYER M4 ;
        RECT  0 18.528 0.084 18.552 ;
    END
  END i_row[11]
  PIN i_row[120]
    DIRECTION INPUT ;
    USE SIGNAL ;
    PORT
      LAYER M4 ;
        RECT  0 65.616 0.084 65.64 ;
    END
  END i_row[120]
  PIN i_row[121]
    DIRECTION INPUT ;
    USE SIGNAL ;
    PORT
      LAYER M4 ;
        RECT  0 66.048 0.084 66.072 ;
    END
  END i_row[121]
  PIN i_row[122]
    DIRECTION INPUT ;
    USE SIGNAL ;
    PORT
      LAYER M4 ;
        RECT  0 66.48 0.084 66.504 ;
    END
  END i_row[122]
  PIN i_row[123]
    DIRECTION INPUT ;
    USE SIGNAL ;
    PORT
      LAYER M4 ;
        RECT  0 66.912 0.084 66.936 ;
    END
  END i_row[123]
  PIN i_row[124]
    DIRECTION INPUT ;
    USE SIGNAL ;
    PORT
      LAYER M4 ;
        RECT  0 67.344 0.084 67.368 ;
    END
  END i_row[124]
  PIN i_row[125]
    DIRECTION INPUT ;
    USE SIGNAL ;
    PORT
      LAYER M4 ;
        RECT  0 67.776 0.084 67.8 ;
    END
  END i_row[125]
  PIN i_row[126]
    DIRECTION INPUT ;
    USE SIGNAL ;
    PORT
      LAYER M4 ;
        RECT  0 68.208 0.084 68.232 ;
    END
  END i_row[126]
  PIN i_row[127]
    DIRECTION INPUT ;
    USE SIGNAL ;
    PORT
      LAYER M4 ;
        RECT  0 68.64 0.084 68.664 ;
    END
  END i_row[127]
  PIN i_row[128]
    DIRECTION INPUT ;
    USE SIGNAL ;
    PORT
      LAYER M4 ;
        RECT  0 69.072 0.084 69.096 ;
    END
  END i_row[128]
  PIN i_row[129]
    DIRECTION INPUT ;
    USE SIGNAL ;
    PORT
      LAYER M4 ;
        RECT  0 69.504 0.084 69.528 ;
    END
  END i_row[129]
  PIN i_row[12]
    DIRECTION INPUT ;
    USE SIGNAL ;
    PORT
      LAYER M4 ;
        RECT  0 18.96 0.084 18.984 ;
    END
  END i_row[12]
  PIN i_row[130]
    DIRECTION INPUT ;
    USE SIGNAL ;
    PORT
      LAYER M4 ;
        RECT  0 69.936 0.084 69.96 ;
    END
  END i_row[130]
  PIN i_row[131]
    DIRECTION INPUT ;
    USE SIGNAL ;
    PORT
      LAYER M4 ;
        RECT  0 70.368 0.084 70.392 ;
    END
  END i_row[131]
  PIN i_row[132]
    DIRECTION INPUT ;
    USE SIGNAL ;
    PORT
      LAYER M4 ;
        RECT  0 70.8 0.084 70.824 ;
    END
  END i_row[132]
  PIN i_row[133]
    DIRECTION INPUT ;
    USE SIGNAL ;
    PORT
      LAYER M4 ;
        RECT  0 71.232 0.084 71.256 ;
    END
  END i_row[133]
  PIN i_row[134]
    DIRECTION INPUT ;
    USE SIGNAL ;
    PORT
      LAYER M4 ;
        RECT  0 71.664 0.084 71.688 ;
    END
  END i_row[134]
  PIN i_row[135]
    DIRECTION INPUT ;
    USE SIGNAL ;
    PORT
      LAYER M4 ;
        RECT  0 72.096 0.084 72.12 ;
    END
  END i_row[135]
  PIN i_row[136]
    DIRECTION INPUT ;
    USE SIGNAL ;
    PORT
      LAYER M4 ;
        RECT  0 72.528 0.084 72.552 ;
    END
  END i_row[136]
  PIN i_row[137]
    DIRECTION INPUT ;
    USE SIGNAL ;
    PORT
      LAYER M4 ;
        RECT  0 72.96 0.084 72.984 ;
    END
  END i_row[137]
  PIN i_row[138]
    DIRECTION INPUT ;
    USE SIGNAL ;
    PORT
      LAYER M4 ;
        RECT  0 73.392 0.084 73.416 ;
    END
  END i_row[138]
  PIN i_row[139]
    DIRECTION INPUT ;
    USE SIGNAL ;
    PORT
      LAYER M4 ;
        RECT  0 73.824 0.084 73.848 ;
    END
  END i_row[139]
  PIN i_row[13]
    DIRECTION INPUT ;
    USE SIGNAL ;
    PORT
      LAYER M4 ;
        RECT  0 19.392 0.084 19.416 ;
    END
  END i_row[13]
  PIN i_row[140]
    DIRECTION INPUT ;
    USE SIGNAL ;
    PORT
      LAYER M4 ;
        RECT  0 74.256 0.084 74.28 ;
    END
  END i_row[140]
  PIN i_row[141]
    DIRECTION INPUT ;
    USE SIGNAL ;
    PORT
      LAYER M4 ;
        RECT  0 74.688 0.084 74.712 ;
    END
  END i_row[141]
  PIN i_row[142]
    DIRECTION INPUT ;
    USE SIGNAL ;
    PORT
      LAYER M4 ;
        RECT  0 75.12 0.084 75.144 ;
    END
  END i_row[142]
  PIN i_row[143]
    DIRECTION INPUT ;
    USE SIGNAL ;
    PORT
      LAYER M4 ;
        RECT  0 75.552 0.084 75.576 ;
    END
  END i_row[143]
  PIN i_row[144]
    DIRECTION INPUT ;
    USE SIGNAL ;
    PORT
      LAYER M4 ;
        RECT  0 75.984 0.084 76.008 ;
    END
  END i_row[144]
  PIN i_row[145]
    DIRECTION INPUT ;
    USE SIGNAL ;
    PORT
      LAYER M4 ;
        RECT  0 76.416 0.084 76.44 ;
    END
  END i_row[145]
  PIN i_row[146]
    DIRECTION INPUT ;
    USE SIGNAL ;
    PORT
      LAYER M4 ;
        RECT  0 76.848 0.084 76.872 ;
    END
  END i_row[146]
  PIN i_row[147]
    DIRECTION INPUT ;
    USE SIGNAL ;
    PORT
      LAYER M4 ;
        RECT  0 77.28 0.084 77.304 ;
    END
  END i_row[147]
  PIN i_row[148]
    DIRECTION INPUT ;
    USE SIGNAL ;
    PORT
      LAYER M4 ;
        RECT  0 77.712 0.084 77.736 ;
    END
  END i_row[148]
  PIN i_row[149]
    DIRECTION INPUT ;
    USE SIGNAL ;
    PORT
      LAYER M4 ;
        RECT  0 78.144 0.084 78.168 ;
    END
  END i_row[149]
  PIN i_row[14]
    DIRECTION INPUT ;
    USE SIGNAL ;
    PORT
      LAYER M4 ;
        RECT  0 19.824 0.084 19.848 ;
    END
  END i_row[14]
  PIN i_row[150]
    DIRECTION INPUT ;
    USE SIGNAL ;
    PORT
      LAYER M4 ;
        RECT  0 78.576 0.084 78.6 ;
    END
  END i_row[150]
  PIN i_row[151]
    DIRECTION INPUT ;
    USE SIGNAL ;
    PORT
      LAYER M4 ;
        RECT  0 79.008 0.084 79.032 ;
    END
  END i_row[151]
  PIN i_row[152]
    DIRECTION INPUT ;
    USE SIGNAL ;
    PORT
      LAYER M4 ;
        RECT  0 79.44 0.084 79.464 ;
    END
  END i_row[152]
  PIN i_row[153]
    DIRECTION INPUT ;
    USE SIGNAL ;
    PORT
      LAYER M4 ;
        RECT  0 79.872 0.084 79.896 ;
    END
  END i_row[153]
  PIN i_row[154]
    DIRECTION INPUT ;
    USE SIGNAL ;
    PORT
      LAYER M4 ;
        RECT  0 80.304 0.084 80.328 ;
    END
  END i_row[154]
  PIN i_row[155]
    DIRECTION INPUT ;
    USE SIGNAL ;
    PORT
      LAYER M4 ;
        RECT  0 80.736 0.084 80.76 ;
    END
  END i_row[155]
  PIN i_row[156]
    DIRECTION INPUT ;
    USE SIGNAL ;
    PORT
      LAYER M4 ;
        RECT  0 81.168 0.084 81.192 ;
    END
  END i_row[156]
  PIN i_row[157]
    DIRECTION INPUT ;
    USE SIGNAL ;
    PORT
      LAYER M4 ;
        RECT  0 81.6 0.084 81.624 ;
    END
  END i_row[157]
  PIN i_row[158]
    DIRECTION INPUT ;
    USE SIGNAL ;
    PORT
      LAYER M4 ;
        RECT  0 82.032 0.084 82.056 ;
    END
  END i_row[158]
  PIN i_row[159]
    DIRECTION INPUT ;
    USE SIGNAL ;
    PORT
      LAYER M4 ;
        RECT  0 82.464 0.084 82.488 ;
    END
  END i_row[159]
  PIN i_row[15]
    DIRECTION INPUT ;
    USE SIGNAL ;
    PORT
      LAYER M4 ;
        RECT  0 20.256 0.084 20.28 ;
    END
  END i_row[15]
  PIN i_row[160]
    DIRECTION INPUT ;
    USE SIGNAL ;
    PORT
      LAYER M4 ;
        RECT  0 82.896 0.084 82.92 ;
    END
  END i_row[160]
  PIN i_row[161]
    DIRECTION INPUT ;
    USE SIGNAL ;
    PORT
      LAYER M4 ;
        RECT  0 83.328 0.084 83.352 ;
    END
  END i_row[161]
  PIN i_row[162]
    DIRECTION INPUT ;
    USE SIGNAL ;
    PORT
      LAYER M4 ;
        RECT  0 83.76 0.084 83.784 ;
    END
  END i_row[162]
  PIN i_row[163]
    DIRECTION INPUT ;
    USE SIGNAL ;
    PORT
      LAYER M4 ;
        RECT  0 84.192 0.084 84.216 ;
    END
  END i_row[163]
  PIN i_row[164]
    DIRECTION INPUT ;
    USE SIGNAL ;
    PORT
      LAYER M4 ;
        RECT  0 84.624 0.084 84.648 ;
    END
  END i_row[164]
  PIN i_row[165]
    DIRECTION INPUT ;
    USE SIGNAL ;
    PORT
      LAYER M4 ;
        RECT  0 85.056 0.084 85.08 ;
    END
  END i_row[165]
  PIN i_row[166]
    DIRECTION INPUT ;
    USE SIGNAL ;
    PORT
      LAYER M4 ;
        RECT  0 85.488 0.084 85.512 ;
    END
  END i_row[166]
  PIN i_row[167]
    DIRECTION INPUT ;
    USE SIGNAL ;
    PORT
      LAYER M4 ;
        RECT  0 85.92 0.084 85.944 ;
    END
  END i_row[167]
  PIN i_row[168]
    DIRECTION INPUT ;
    USE SIGNAL ;
    PORT
      LAYER M4 ;
        RECT  0 86.352 0.084 86.376 ;
    END
  END i_row[168]
  PIN i_row[169]
    DIRECTION INPUT ;
    USE SIGNAL ;
    PORT
      LAYER M4 ;
        RECT  0 86.784 0.084 86.808 ;
    END
  END i_row[169]
  PIN i_row[16]
    DIRECTION INPUT ;
    USE SIGNAL ;
    PORT
      LAYER M4 ;
        RECT  0 20.688 0.084 20.712 ;
    END
  END i_row[16]
  PIN i_row[170]
    DIRECTION INPUT ;
    USE SIGNAL ;
    PORT
      LAYER M4 ;
        RECT  0 87.216 0.084 87.24 ;
    END
  END i_row[170]
  PIN i_row[171]
    DIRECTION INPUT ;
    USE SIGNAL ;
    PORT
      LAYER M4 ;
        RECT  0 87.648 0.084 87.672 ;
    END
  END i_row[171]
  PIN i_row[172]
    DIRECTION INPUT ;
    USE SIGNAL ;
    PORT
      LAYER M4 ;
        RECT  0 88.08 0.084 88.104 ;
    END
  END i_row[172]
  PIN i_row[173]
    DIRECTION INPUT ;
    USE SIGNAL ;
    PORT
      LAYER M4 ;
        RECT  0 88.512 0.084 88.536 ;
    END
  END i_row[173]
  PIN i_row[174]
    DIRECTION INPUT ;
    USE SIGNAL ;
    PORT
      LAYER M4 ;
        RECT  0 88.944 0.084 88.968 ;
    END
  END i_row[174]
  PIN i_row[175]
    DIRECTION INPUT ;
    USE SIGNAL ;
    PORT
      LAYER M4 ;
        RECT  0 89.376 0.084 89.4 ;
    END
  END i_row[175]
  PIN i_row[176]
    DIRECTION INPUT ;
    USE SIGNAL ;
    PORT
      LAYER M4 ;
        RECT  0 89.808 0.084 89.832 ;
    END
  END i_row[176]
  PIN i_row[177]
    DIRECTION INPUT ;
    USE SIGNAL ;
    PORT
      LAYER M4 ;
        RECT  0 90.24 0.084 90.264 ;
    END
  END i_row[177]
  PIN i_row[178]
    DIRECTION INPUT ;
    USE SIGNAL ;
    PORT
      LAYER M4 ;
        RECT  0 90.672 0.084 90.696 ;
    END
  END i_row[178]
  PIN i_row[179]
    DIRECTION INPUT ;
    USE SIGNAL ;
    PORT
      LAYER M4 ;
        RECT  0 91.104 0.084 91.128 ;
    END
  END i_row[179]
  PIN i_row[17]
    DIRECTION INPUT ;
    USE SIGNAL ;
    PORT
      LAYER M4 ;
        RECT  0 21.12 0.084 21.144 ;
    END
  END i_row[17]
  PIN i_row[180]
    DIRECTION INPUT ;
    USE SIGNAL ;
    PORT
      LAYER M4 ;
        RECT  0 91.536 0.084 91.56 ;
    END
  END i_row[180]
  PIN i_row[181]
    DIRECTION INPUT ;
    USE SIGNAL ;
    PORT
      LAYER M4 ;
        RECT  0 91.968 0.084 91.992 ;
    END
  END i_row[181]
  PIN i_row[182]
    DIRECTION INPUT ;
    USE SIGNAL ;
    PORT
      LAYER M4 ;
        RECT  0 92.4 0.084 92.424 ;
    END
  END i_row[182]
  PIN i_row[183]
    DIRECTION INPUT ;
    USE SIGNAL ;
    PORT
      LAYER M4 ;
        RECT  0 92.832 0.084 92.856 ;
    END
  END i_row[183]
  PIN i_row[184]
    DIRECTION INPUT ;
    USE SIGNAL ;
    PORT
      LAYER M4 ;
        RECT  0 93.264 0.084 93.288 ;
    END
  END i_row[184]
  PIN i_row[185]
    DIRECTION INPUT ;
    USE SIGNAL ;
    PORT
      LAYER M4 ;
        RECT  0 93.696 0.084 93.72 ;
    END
  END i_row[185]
  PIN i_row[186]
    DIRECTION INPUT ;
    USE SIGNAL ;
    PORT
      LAYER M4 ;
        RECT  0 94.128 0.084 94.152 ;
    END
  END i_row[186]
  PIN i_row[187]
    DIRECTION INPUT ;
    USE SIGNAL ;
    PORT
      LAYER M4 ;
        RECT  0 94.56 0.084 94.584 ;
    END
  END i_row[187]
  PIN i_row[188]
    DIRECTION INPUT ;
    USE SIGNAL ;
    PORT
      LAYER M4 ;
        RECT  0 94.992 0.084 95.016 ;
    END
  END i_row[188]
  PIN i_row[189]
    DIRECTION INPUT ;
    USE SIGNAL ;
    PORT
      LAYER M4 ;
        RECT  0 95.424 0.084 95.448 ;
    END
  END i_row[189]
  PIN i_row[18]
    DIRECTION INPUT ;
    USE SIGNAL ;
    PORT
      LAYER M4 ;
        RECT  0 21.552 0.084 21.576 ;
    END
  END i_row[18]
  PIN i_row[190]
    DIRECTION INPUT ;
    USE SIGNAL ;
    PORT
      LAYER M4 ;
        RECT  0 95.856 0.084 95.88 ;
    END
  END i_row[190]
  PIN i_row[191]
    DIRECTION INPUT ;
    USE SIGNAL ;
    PORT
      LAYER M4 ;
        RECT  0 96.288 0.084 96.312 ;
    END
  END i_row[191]
  PIN i_row[192]
    DIRECTION INPUT ;
    USE SIGNAL ;
    PORT
      LAYER M4 ;
        RECT  0 96.72 0.084 96.744 ;
    END
  END i_row[192]
  PIN i_row[193]
    DIRECTION INPUT ;
    USE SIGNAL ;
    PORT
      LAYER M4 ;
        RECT  0 97.152 0.084 97.176 ;
    END
  END i_row[193]
  PIN i_row[194]
    DIRECTION INPUT ;
    USE SIGNAL ;
    PORT
      LAYER M4 ;
        RECT  0 97.584 0.084 97.608 ;
    END
  END i_row[194]
  PIN i_row[195]
    DIRECTION INPUT ;
    USE SIGNAL ;
    PORT
      LAYER M4 ;
        RECT  0 98.016 0.084 98.04 ;
    END
  END i_row[195]
  PIN i_row[196]
    DIRECTION INPUT ;
    USE SIGNAL ;
    PORT
      LAYER M4 ;
        RECT  0 98.448 0.084 98.472 ;
    END
  END i_row[196]
  PIN i_row[197]
    DIRECTION INPUT ;
    USE SIGNAL ;
    PORT
      LAYER M4 ;
        RECT  0 98.88 0.084 98.904 ;
    END
  END i_row[197]
  PIN i_row[198]
    DIRECTION INPUT ;
    USE SIGNAL ;
    PORT
      LAYER M4 ;
        RECT  0 99.312 0.084 99.336 ;
    END
  END i_row[198]
  PIN i_row[199]
    DIRECTION INPUT ;
    USE SIGNAL ;
    PORT
      LAYER M4 ;
        RECT  0 99.744 0.084 99.768 ;
    END
  END i_row[199]
  PIN i_row[19]
    DIRECTION INPUT ;
    USE SIGNAL ;
    PORT
      LAYER M4 ;
        RECT  0 21.984 0.084 22.008 ;
    END
  END i_row[19]
  PIN i_row[1]
    DIRECTION INPUT ;
    USE SIGNAL ;
    PORT
      LAYER M4 ;
        RECT  0 14.208 0.084 14.232 ;
    END
  END i_row[1]
  PIN i_row[200]
    DIRECTION INPUT ;
    USE SIGNAL ;
    PORT
      LAYER M4 ;
        RECT  0 100.176 0.084 100.2 ;
    END
  END i_row[200]
  PIN i_row[201]
    DIRECTION INPUT ;
    USE SIGNAL ;
    PORT
      LAYER M4 ;
        RECT  0 100.608 0.084 100.632 ;
    END
  END i_row[201]
  PIN i_row[202]
    DIRECTION INPUT ;
    USE SIGNAL ;
    PORT
      LAYER M4 ;
        RECT  0 101.04 0.084 101.064 ;
    END
  END i_row[202]
  PIN i_row[203]
    DIRECTION INPUT ;
    USE SIGNAL ;
    PORT
      LAYER M4 ;
        RECT  0 101.472 0.084 101.496 ;
    END
  END i_row[203]
  PIN i_row[204]
    DIRECTION INPUT ;
    USE SIGNAL ;
    PORT
      LAYER M4 ;
        RECT  0 101.904 0.084 101.928 ;
    END
  END i_row[204]
  PIN i_row[205]
    DIRECTION INPUT ;
    USE SIGNAL ;
    PORT
      LAYER M4 ;
        RECT  0 102.336 0.084 102.36 ;
    END
  END i_row[205]
  PIN i_row[206]
    DIRECTION INPUT ;
    USE SIGNAL ;
    PORT
      LAYER M4 ;
        RECT  0 102.768 0.084 102.792 ;
    END
  END i_row[206]
  PIN i_row[207]
    DIRECTION INPUT ;
    USE SIGNAL ;
    PORT
      LAYER M4 ;
        RECT  0 103.2 0.084 103.224 ;
    END
  END i_row[207]
  PIN i_row[208]
    DIRECTION INPUT ;
    USE SIGNAL ;
    PORT
      LAYER M4 ;
        RECT  0 103.632 0.084 103.656 ;
    END
  END i_row[208]
  PIN i_row[209]
    DIRECTION INPUT ;
    USE SIGNAL ;
    PORT
      LAYER M4 ;
        RECT  0 104.064 0.084 104.088 ;
    END
  END i_row[209]
  PIN i_row[20]
    DIRECTION INPUT ;
    USE SIGNAL ;
    PORT
      LAYER M4 ;
        RECT  0 22.416 0.084 22.44 ;
    END
  END i_row[20]
  PIN i_row[210]
    DIRECTION INPUT ;
    USE SIGNAL ;
    PORT
      LAYER M4 ;
        RECT  0 104.496 0.084 104.52 ;
    END
  END i_row[210]
  PIN i_row[211]
    DIRECTION INPUT ;
    USE SIGNAL ;
    PORT
      LAYER M4 ;
        RECT  0 104.928 0.084 104.952 ;
    END
  END i_row[211]
  PIN i_row[212]
    DIRECTION INPUT ;
    USE SIGNAL ;
    PORT
      LAYER M4 ;
        RECT  0 105.36 0.084 105.384 ;
    END
  END i_row[212]
  PIN i_row[213]
    DIRECTION INPUT ;
    USE SIGNAL ;
    PORT
      LAYER M4 ;
        RECT  0 105.792 0.084 105.816 ;
    END
  END i_row[213]
  PIN i_row[214]
    DIRECTION INPUT ;
    USE SIGNAL ;
    PORT
      LAYER M4 ;
        RECT  0 106.224 0.084 106.248 ;
    END
  END i_row[214]
  PIN i_row[215]
    DIRECTION INPUT ;
    USE SIGNAL ;
    PORT
      LAYER M4 ;
        RECT  0 106.656 0.084 106.68 ;
    END
  END i_row[215]
  PIN i_row[216]
    DIRECTION INPUT ;
    USE SIGNAL ;
    PORT
      LAYER M4 ;
        RECT  0 107.088 0.084 107.112 ;
    END
  END i_row[216]
  PIN i_row[217]
    DIRECTION INPUT ;
    USE SIGNAL ;
    PORT
      LAYER M4 ;
        RECT  0 107.52 0.084 107.544 ;
    END
  END i_row[217]
  PIN i_row[218]
    DIRECTION INPUT ;
    USE SIGNAL ;
    PORT
      LAYER M4 ;
        RECT  0 107.952 0.084 107.976 ;
    END
  END i_row[218]
  PIN i_row[219]
    DIRECTION INPUT ;
    USE SIGNAL ;
    PORT
      LAYER M4 ;
        RECT  0 108.384 0.084 108.408 ;
    END
  END i_row[219]
  PIN i_row[21]
    DIRECTION INPUT ;
    USE SIGNAL ;
    PORT
      LAYER M4 ;
        RECT  0 22.848 0.084 22.872 ;
    END
  END i_row[21]
  PIN i_row[220]
    DIRECTION INPUT ;
    USE SIGNAL ;
    PORT
      LAYER M4 ;
        RECT  0 108.816 0.084 108.84 ;
    END
  END i_row[220]
  PIN i_row[221]
    DIRECTION INPUT ;
    USE SIGNAL ;
    PORT
      LAYER M4 ;
        RECT  0 109.248 0.084 109.272 ;
    END
  END i_row[221]
  PIN i_row[222]
    DIRECTION INPUT ;
    USE SIGNAL ;
    PORT
      LAYER M4 ;
        RECT  0 109.68 0.084 109.704 ;
    END
  END i_row[222]
  PIN i_row[223]
    DIRECTION INPUT ;
    USE SIGNAL ;
    PORT
      LAYER M4 ;
        RECT  0 110.112 0.084 110.136 ;
    END
  END i_row[223]
  PIN i_row[224]
    DIRECTION INPUT ;
    USE SIGNAL ;
    PORT
      LAYER M4 ;
        RECT  0 110.544 0.084 110.568 ;
    END
  END i_row[224]
  PIN i_row[225]
    DIRECTION INPUT ;
    USE SIGNAL ;
    PORT
      LAYER M4 ;
        RECT  0 110.976 0.084 111 ;
    END
  END i_row[225]
  PIN i_row[226]
    DIRECTION INPUT ;
    USE SIGNAL ;
    PORT
      LAYER M4 ;
        RECT  0 111.408 0.084 111.432 ;
    END
  END i_row[226]
  PIN i_row[227]
    DIRECTION INPUT ;
    USE SIGNAL ;
    PORT
      LAYER M4 ;
        RECT  0 111.84 0.084 111.864 ;
    END
  END i_row[227]
  PIN i_row[228]
    DIRECTION INPUT ;
    USE SIGNAL ;
    PORT
      LAYER M4 ;
        RECT  0 112.272 0.084 112.296 ;
    END
  END i_row[228]
  PIN i_row[229]
    DIRECTION INPUT ;
    USE SIGNAL ;
    PORT
      LAYER M4 ;
        RECT  0 112.704 0.084 112.728 ;
    END
  END i_row[229]
  PIN i_row[22]
    DIRECTION INPUT ;
    USE SIGNAL ;
    PORT
      LAYER M4 ;
        RECT  0 23.28 0.084 23.304 ;
    END
  END i_row[22]
  PIN i_row[230]
    DIRECTION INPUT ;
    USE SIGNAL ;
    PORT
      LAYER M4 ;
        RECT  0 113.136 0.084 113.16 ;
    END
  END i_row[230]
  PIN i_row[231]
    DIRECTION INPUT ;
    USE SIGNAL ;
    PORT
      LAYER M4 ;
        RECT  0 113.568 0.084 113.592 ;
    END
  END i_row[231]
  PIN i_row[232]
    DIRECTION INPUT ;
    USE SIGNAL ;
    PORT
      LAYER M4 ;
        RECT  0 114 0.084 114.024 ;
    END
  END i_row[232]
  PIN i_row[233]
    DIRECTION INPUT ;
    USE SIGNAL ;
    PORT
      LAYER M4 ;
        RECT  0 114.432 0.084 114.456 ;
    END
  END i_row[233]
  PIN i_row[234]
    DIRECTION INPUT ;
    USE SIGNAL ;
    PORT
      LAYER M4 ;
        RECT  0 114.864 0.084 114.888 ;
    END
  END i_row[234]
  PIN i_row[235]
    DIRECTION INPUT ;
    USE SIGNAL ;
    PORT
      LAYER M4 ;
        RECT  0 115.296 0.084 115.32 ;
    END
  END i_row[235]
  PIN i_row[236]
    DIRECTION INPUT ;
    USE SIGNAL ;
    PORT
      LAYER M4 ;
        RECT  0 115.728 0.084 115.752 ;
    END
  END i_row[236]
  PIN i_row[237]
    DIRECTION INPUT ;
    USE SIGNAL ;
    PORT
      LAYER M4 ;
        RECT  0 116.16 0.084 116.184 ;
    END
  END i_row[237]
  PIN i_row[238]
    DIRECTION INPUT ;
    USE SIGNAL ;
    PORT
      LAYER M4 ;
        RECT  0 116.592 0.084 116.616 ;
    END
  END i_row[238]
  PIN i_row[239]
    DIRECTION INPUT ;
    USE SIGNAL ;
    PORT
      LAYER M4 ;
        RECT  0 117.024 0.084 117.048 ;
    END
  END i_row[239]
  PIN i_row[23]
    DIRECTION INPUT ;
    USE SIGNAL ;
    PORT
      LAYER M4 ;
        RECT  0 23.712 0.084 23.736 ;
    END
  END i_row[23]
  PIN i_row[240]
    DIRECTION INPUT ;
    USE SIGNAL ;
    PORT
      LAYER M4 ;
        RECT  0 117.456 0.084 117.48 ;
    END
  END i_row[240]
  PIN i_row[241]
    DIRECTION INPUT ;
    USE SIGNAL ;
    PORT
      LAYER M4 ;
        RECT  0 117.888 0.084 117.912 ;
    END
  END i_row[241]
  PIN i_row[242]
    DIRECTION INPUT ;
    USE SIGNAL ;
    PORT
      LAYER M4 ;
        RECT  0 118.32 0.084 118.344 ;
    END
  END i_row[242]
  PIN i_row[243]
    DIRECTION INPUT ;
    USE SIGNAL ;
    PORT
      LAYER M4 ;
        RECT  0 118.752 0.084 118.776 ;
    END
  END i_row[243]
  PIN i_row[244]
    DIRECTION INPUT ;
    USE SIGNAL ;
    PORT
      LAYER M4 ;
        RECT  0 119.184 0.084 119.208 ;
    END
  END i_row[244]
  PIN i_row[245]
    DIRECTION INPUT ;
    USE SIGNAL ;
    PORT
      LAYER M4 ;
        RECT  0 119.616 0.084 119.64 ;
    END
  END i_row[245]
  PIN i_row[246]
    DIRECTION INPUT ;
    USE SIGNAL ;
    PORT
      LAYER M4 ;
        RECT  0 120.048 0.084 120.072 ;
    END
  END i_row[246]
  PIN i_row[247]
    DIRECTION INPUT ;
    USE SIGNAL ;
    PORT
      LAYER M4 ;
        RECT  0 120.48 0.084 120.504 ;
    END
  END i_row[247]
  PIN i_row[248]
    DIRECTION INPUT ;
    USE SIGNAL ;
    PORT
      LAYER M4 ;
        RECT  0 120.912 0.084 120.936 ;
    END
  END i_row[248]
  PIN i_row[249]
    DIRECTION INPUT ;
    USE SIGNAL ;
    PORT
      LAYER M4 ;
        RECT  0 121.344 0.084 121.368 ;
    END
  END i_row[249]
  PIN i_row[24]
    DIRECTION INPUT ;
    USE SIGNAL ;
    PORT
      LAYER M4 ;
        RECT  0 24.144 0.084 24.168 ;
    END
  END i_row[24]
  PIN i_row[250]
    DIRECTION INPUT ;
    USE SIGNAL ;
    PORT
      LAYER M4 ;
        RECT  0 121.776 0.084 121.8 ;
    END
  END i_row[250]
  PIN i_row[251]
    DIRECTION INPUT ;
    USE SIGNAL ;
    PORT
      LAYER M4 ;
        RECT  0 122.208 0.084 122.232 ;
    END
  END i_row[251]
  PIN i_row[25]
    DIRECTION INPUT ;
    USE SIGNAL ;
    PORT
      LAYER M4 ;
        RECT  0 24.576 0.084 24.6 ;
    END
  END i_row[25]
  PIN i_row[26]
    DIRECTION INPUT ;
    USE SIGNAL ;
    PORT
      LAYER M4 ;
        RECT  0 25.008 0.084 25.032 ;
    END
  END i_row[26]
  PIN i_row[27]
    DIRECTION INPUT ;
    USE SIGNAL ;
    PORT
      LAYER M4 ;
        RECT  0 25.44 0.084 25.464 ;
    END
  END i_row[27]
  PIN i_row[28]
    DIRECTION INPUT ;
    USE SIGNAL ;
    PORT
      LAYER M4 ;
        RECT  0 25.872 0.084 25.896 ;
    END
  END i_row[28]
  PIN i_row[29]
    DIRECTION INPUT ;
    USE SIGNAL ;
    PORT
      LAYER M4 ;
        RECT  0 26.304 0.084 26.328 ;
    END
  END i_row[29]
  PIN i_row[2]
    DIRECTION INPUT ;
    USE SIGNAL ;
    PORT
      LAYER M4 ;
        RECT  0 14.64 0.084 14.664 ;
    END
  END i_row[2]
  PIN i_row[30]
    DIRECTION INPUT ;
    USE SIGNAL ;
    PORT
      LAYER M4 ;
        RECT  0 26.736 0.084 26.76 ;
    END
  END i_row[30]
  PIN i_row[31]
    DIRECTION INPUT ;
    USE SIGNAL ;
    PORT
      LAYER M4 ;
        RECT  0 27.168 0.084 27.192 ;
    END
  END i_row[31]
  PIN i_row[32]
    DIRECTION INPUT ;
    USE SIGNAL ;
    PORT
      LAYER M4 ;
        RECT  0 27.6 0.084 27.624 ;
    END
  END i_row[32]
  PIN i_row[33]
    DIRECTION INPUT ;
    USE SIGNAL ;
    PORT
      LAYER M4 ;
        RECT  0 28.032 0.084 28.056 ;
    END
  END i_row[33]
  PIN i_row[34]
    DIRECTION INPUT ;
    USE SIGNAL ;
    PORT
      LAYER M4 ;
        RECT  0 28.464 0.084 28.488 ;
    END
  END i_row[34]
  PIN i_row[35]
    DIRECTION INPUT ;
    USE SIGNAL ;
    PORT
      LAYER M4 ;
        RECT  0 28.896 0.084 28.92 ;
    END
  END i_row[35]
  PIN i_row[36]
    DIRECTION INPUT ;
    USE SIGNAL ;
    PORT
      LAYER M4 ;
        RECT  0 29.328 0.084 29.352 ;
    END
  END i_row[36]
  PIN i_row[37]
    DIRECTION INPUT ;
    USE SIGNAL ;
    PORT
      LAYER M4 ;
        RECT  0 29.76 0.084 29.784 ;
    END
  END i_row[37]
  PIN i_row[38]
    DIRECTION INPUT ;
    USE SIGNAL ;
    PORT
      LAYER M4 ;
        RECT  0 30.192 0.084 30.216 ;
    END
  END i_row[38]
  PIN i_row[39]
    DIRECTION INPUT ;
    USE SIGNAL ;
    PORT
      LAYER M4 ;
        RECT  0 30.624 0.084 30.648 ;
    END
  END i_row[39]
  PIN i_row[3]
    DIRECTION INPUT ;
    USE SIGNAL ;
    PORT
      LAYER M4 ;
        RECT  0 15.072 0.084 15.096 ;
    END
  END i_row[3]
  PIN i_row[40]
    DIRECTION INPUT ;
    USE SIGNAL ;
    PORT
      LAYER M4 ;
        RECT  0 31.056 0.084 31.08 ;
    END
  END i_row[40]
  PIN i_row[41]
    DIRECTION INPUT ;
    USE SIGNAL ;
    PORT
      LAYER M4 ;
        RECT  0 31.488 0.084 31.512 ;
    END
  END i_row[41]
  PIN i_row[42]
    DIRECTION INPUT ;
    USE SIGNAL ;
    PORT
      LAYER M4 ;
        RECT  0 31.92 0.084 31.944 ;
    END
  END i_row[42]
  PIN i_row[43]
    DIRECTION INPUT ;
    USE SIGNAL ;
    PORT
      LAYER M4 ;
        RECT  0 32.352 0.084 32.376 ;
    END
  END i_row[43]
  PIN i_row[44]
    DIRECTION INPUT ;
    USE SIGNAL ;
    PORT
      LAYER M4 ;
        RECT  0 32.784 0.084 32.808 ;
    END
  END i_row[44]
  PIN i_row[45]
    DIRECTION INPUT ;
    USE SIGNAL ;
    PORT
      LAYER M4 ;
        RECT  0 33.216 0.084 33.24 ;
    END
  END i_row[45]
  PIN i_row[46]
    DIRECTION INPUT ;
    USE SIGNAL ;
    PORT
      LAYER M4 ;
        RECT  0 33.648 0.084 33.672 ;
    END
  END i_row[46]
  PIN i_row[47]
    DIRECTION INPUT ;
    USE SIGNAL ;
    PORT
      LAYER M4 ;
        RECT  0 34.08 0.084 34.104 ;
    END
  END i_row[47]
  PIN i_row[48]
    DIRECTION INPUT ;
    USE SIGNAL ;
    PORT
      LAYER M4 ;
        RECT  0 34.512 0.084 34.536 ;
    END
  END i_row[48]
  PIN i_row[49]
    DIRECTION INPUT ;
    USE SIGNAL ;
    PORT
      LAYER M4 ;
        RECT  0 34.944 0.084 34.968 ;
    END
  END i_row[49]
  PIN i_row[4]
    DIRECTION INPUT ;
    USE SIGNAL ;
    PORT
      LAYER M4 ;
        RECT  0 15.504 0.084 15.528 ;
    END
  END i_row[4]
  PIN i_row[50]
    DIRECTION INPUT ;
    USE SIGNAL ;
    PORT
      LAYER M4 ;
        RECT  0 35.376 0.084 35.4 ;
    END
  END i_row[50]
  PIN i_row[51]
    DIRECTION INPUT ;
    USE SIGNAL ;
    PORT
      LAYER M4 ;
        RECT  0 35.808 0.084 35.832 ;
    END
  END i_row[51]
  PIN i_row[52]
    DIRECTION INPUT ;
    USE SIGNAL ;
    PORT
      LAYER M4 ;
        RECT  0 36.24 0.084 36.264 ;
    END
  END i_row[52]
  PIN i_row[53]
    DIRECTION INPUT ;
    USE SIGNAL ;
    PORT
      LAYER M4 ;
        RECT  0 36.672 0.084 36.696 ;
    END
  END i_row[53]
  PIN i_row[54]
    DIRECTION INPUT ;
    USE SIGNAL ;
    PORT
      LAYER M4 ;
        RECT  0 37.104 0.084 37.128 ;
    END
  END i_row[54]
  PIN i_row[55]
    DIRECTION INPUT ;
    USE SIGNAL ;
    PORT
      LAYER M4 ;
        RECT  0 37.536 0.084 37.56 ;
    END
  END i_row[55]
  PIN i_row[56]
    DIRECTION INPUT ;
    USE SIGNAL ;
    PORT
      LAYER M4 ;
        RECT  0 37.968 0.084 37.992 ;
    END
  END i_row[56]
  PIN i_row[57]
    DIRECTION INPUT ;
    USE SIGNAL ;
    PORT
      LAYER M4 ;
        RECT  0 38.4 0.084 38.424 ;
    END
  END i_row[57]
  PIN i_row[58]
    DIRECTION INPUT ;
    USE SIGNAL ;
    PORT
      LAYER M4 ;
        RECT  0 38.832 0.084 38.856 ;
    END
  END i_row[58]
  PIN i_row[59]
    DIRECTION INPUT ;
    USE SIGNAL ;
    PORT
      LAYER M4 ;
        RECT  0 39.264 0.084 39.288 ;
    END
  END i_row[59]
  PIN i_row[5]
    DIRECTION INPUT ;
    USE SIGNAL ;
    PORT
      LAYER M4 ;
        RECT  0 15.936 0.084 15.96 ;
    END
  END i_row[5]
  PIN i_row[60]
    DIRECTION INPUT ;
    USE SIGNAL ;
    PORT
      LAYER M4 ;
        RECT  0 39.696 0.084 39.72 ;
    END
  END i_row[60]
  PIN i_row[61]
    DIRECTION INPUT ;
    USE SIGNAL ;
    PORT
      LAYER M4 ;
        RECT  0 40.128 0.084 40.152 ;
    END
  END i_row[61]
  PIN i_row[62]
    DIRECTION INPUT ;
    USE SIGNAL ;
    PORT
      LAYER M4 ;
        RECT  0 40.56 0.084 40.584 ;
    END
  END i_row[62]
  PIN i_row[63]
    DIRECTION INPUT ;
    USE SIGNAL ;
    PORT
      LAYER M4 ;
        RECT  0 40.992 0.084 41.016 ;
    END
  END i_row[63]
  PIN i_row[64]
    DIRECTION INPUT ;
    USE SIGNAL ;
    PORT
      LAYER M4 ;
        RECT  0 41.424 0.084 41.448 ;
    END
  END i_row[64]
  PIN i_row[65]
    DIRECTION INPUT ;
    USE SIGNAL ;
    PORT
      LAYER M4 ;
        RECT  0 41.856 0.084 41.88 ;
    END
  END i_row[65]
  PIN i_row[66]
    DIRECTION INPUT ;
    USE SIGNAL ;
    PORT
      LAYER M4 ;
        RECT  0 42.288 0.084 42.312 ;
    END
  END i_row[66]
  PIN i_row[67]
    DIRECTION INPUT ;
    USE SIGNAL ;
    PORT
      LAYER M4 ;
        RECT  0 42.72 0.084 42.744 ;
    END
  END i_row[67]
  PIN i_row[68]
    DIRECTION INPUT ;
    USE SIGNAL ;
    PORT
      LAYER M4 ;
        RECT  0 43.152 0.084 43.176 ;
    END
  END i_row[68]
  PIN i_row[69]
    DIRECTION INPUT ;
    USE SIGNAL ;
    PORT
      LAYER M4 ;
        RECT  0 43.584 0.084 43.608 ;
    END
  END i_row[69]
  PIN i_row[6]
    DIRECTION INPUT ;
    USE SIGNAL ;
    PORT
      LAYER M4 ;
        RECT  0 16.368 0.084 16.392 ;
    END
  END i_row[6]
  PIN i_row[70]
    DIRECTION INPUT ;
    USE SIGNAL ;
    PORT
      LAYER M4 ;
        RECT  0 44.016 0.084 44.04 ;
    END
  END i_row[70]
  PIN i_row[71]
    DIRECTION INPUT ;
    USE SIGNAL ;
    PORT
      LAYER M4 ;
        RECT  0 44.448 0.084 44.472 ;
    END
  END i_row[71]
  PIN i_row[72]
    DIRECTION INPUT ;
    USE SIGNAL ;
    PORT
      LAYER M4 ;
        RECT  0 44.88 0.084 44.904 ;
    END
  END i_row[72]
  PIN i_row[73]
    DIRECTION INPUT ;
    USE SIGNAL ;
    PORT
      LAYER M4 ;
        RECT  0 45.312 0.084 45.336 ;
    END
  END i_row[73]
  PIN i_row[74]
    DIRECTION INPUT ;
    USE SIGNAL ;
    PORT
      LAYER M4 ;
        RECT  0 45.744 0.084 45.768 ;
    END
  END i_row[74]
  PIN i_row[75]
    DIRECTION INPUT ;
    USE SIGNAL ;
    PORT
      LAYER M4 ;
        RECT  0 46.176 0.084 46.2 ;
    END
  END i_row[75]
  PIN i_row[76]
    DIRECTION INPUT ;
    USE SIGNAL ;
    PORT
      LAYER M4 ;
        RECT  0 46.608 0.084 46.632 ;
    END
  END i_row[76]
  PIN i_row[77]
    DIRECTION INPUT ;
    USE SIGNAL ;
    PORT
      LAYER M4 ;
        RECT  0 47.04 0.084 47.064 ;
    END
  END i_row[77]
  PIN i_row[78]
    DIRECTION INPUT ;
    USE SIGNAL ;
    PORT
      LAYER M4 ;
        RECT  0 47.472 0.084 47.496 ;
    END
  END i_row[78]
  PIN i_row[79]
    DIRECTION INPUT ;
    USE SIGNAL ;
    PORT
      LAYER M4 ;
        RECT  0 47.904 0.084 47.928 ;
    END
  END i_row[79]
  PIN i_row[7]
    DIRECTION INPUT ;
    USE SIGNAL ;
    PORT
      LAYER M4 ;
        RECT  0 16.8 0.084 16.824 ;
    END
  END i_row[7]
  PIN i_row[80]
    DIRECTION INPUT ;
    USE SIGNAL ;
    PORT
      LAYER M4 ;
        RECT  0 48.336 0.084 48.36 ;
    END
  END i_row[80]
  PIN i_row[81]
    DIRECTION INPUT ;
    USE SIGNAL ;
    PORT
      LAYER M4 ;
        RECT  0 48.768 0.084 48.792 ;
    END
  END i_row[81]
  PIN i_row[82]
    DIRECTION INPUT ;
    USE SIGNAL ;
    PORT
      LAYER M4 ;
        RECT  0 49.2 0.084 49.224 ;
    END
  END i_row[82]
  PIN i_row[83]
    DIRECTION INPUT ;
    USE SIGNAL ;
    PORT
      LAYER M4 ;
        RECT  0 49.632 0.084 49.656 ;
    END
  END i_row[83]
  PIN i_row[84]
    DIRECTION INPUT ;
    USE SIGNAL ;
    PORT
      LAYER M4 ;
        RECT  0 50.064 0.084 50.088 ;
    END
  END i_row[84]
  PIN i_row[85]
    DIRECTION INPUT ;
    USE SIGNAL ;
    PORT
      LAYER M4 ;
        RECT  0 50.496 0.084 50.52 ;
    END
  END i_row[85]
  PIN i_row[86]
    DIRECTION INPUT ;
    USE SIGNAL ;
    PORT
      LAYER M4 ;
        RECT  0 50.928 0.084 50.952 ;
    END
  END i_row[86]
  PIN i_row[87]
    DIRECTION INPUT ;
    USE SIGNAL ;
    PORT
      LAYER M4 ;
        RECT  0 51.36 0.084 51.384 ;
    END
  END i_row[87]
  PIN i_row[88]
    DIRECTION INPUT ;
    USE SIGNAL ;
    PORT
      LAYER M4 ;
        RECT  0 51.792 0.084 51.816 ;
    END
  END i_row[88]
  PIN i_row[89]
    DIRECTION INPUT ;
    USE SIGNAL ;
    PORT
      LAYER M4 ;
        RECT  0 52.224 0.084 52.248 ;
    END
  END i_row[89]
  PIN i_row[8]
    DIRECTION INPUT ;
    USE SIGNAL ;
    PORT
      LAYER M4 ;
        RECT  0 17.232 0.084 17.256 ;
    END
  END i_row[8]
  PIN i_row[90]
    DIRECTION INPUT ;
    USE SIGNAL ;
    PORT
      LAYER M4 ;
        RECT  0 52.656 0.084 52.68 ;
    END
  END i_row[90]
  PIN i_row[91]
    DIRECTION INPUT ;
    USE SIGNAL ;
    PORT
      LAYER M4 ;
        RECT  0 53.088 0.084 53.112 ;
    END
  END i_row[91]
  PIN i_row[92]
    DIRECTION INPUT ;
    USE SIGNAL ;
    PORT
      LAYER M4 ;
        RECT  0 53.52 0.084 53.544 ;
    END
  END i_row[92]
  PIN i_row[93]
    DIRECTION INPUT ;
    USE SIGNAL ;
    PORT
      LAYER M4 ;
        RECT  0 53.952 0.084 53.976 ;
    END
  END i_row[93]
  PIN i_row[94]
    DIRECTION INPUT ;
    USE SIGNAL ;
    PORT
      LAYER M4 ;
        RECT  0 54.384 0.084 54.408 ;
    END
  END i_row[94]
  PIN i_row[95]
    DIRECTION INPUT ;
    USE SIGNAL ;
    PORT
      LAYER M4 ;
        RECT  0 54.816 0.084 54.84 ;
    END
  END i_row[95]
  PIN i_row[96]
    DIRECTION INPUT ;
    USE SIGNAL ;
    PORT
      LAYER M4 ;
        RECT  0 55.248 0.084 55.272 ;
    END
  END i_row[96]
  PIN i_row[97]
    DIRECTION INPUT ;
    USE SIGNAL ;
    PORT
      LAYER M4 ;
        RECT  0 55.68 0.084 55.704 ;
    END
  END i_row[97]
  PIN i_row[98]
    DIRECTION INPUT ;
    USE SIGNAL ;
    PORT
      LAYER M4 ;
        RECT  0 56.112 0.084 56.136 ;
    END
  END i_row[98]
  PIN i_row[99]
    DIRECTION INPUT ;
    USE SIGNAL ;
    PORT
      LAYER M4 ;
        RECT  0 56.544 0.084 56.568 ;
    END
  END i_row[99]
  PIN i_row[9]
    DIRECTION INPUT ;
    USE SIGNAL ;
    PORT
      LAYER M4 ;
        RECT  0 17.664 0.084 17.688 ;
    END
  END i_row[9]
  PIN i_slot[0]
    DIRECTION INPUT ;
    USE SIGNAL ;
    PORT
      LAYER M4 ;
        RECT  0 122.64 0.084 122.664 ;
    END
  END i_slot[0]
  PIN i_slot[10]
    DIRECTION INPUT ;
    USE SIGNAL ;
    PORT
      LAYER M4 ;
        RECT  0 126.96 0.084 126.984 ;
    END
  END i_slot[10]
  PIN i_slot[11]
    DIRECTION INPUT ;
    USE SIGNAL ;
    PORT
      LAYER M4 ;
        RECT  0 127.392 0.084 127.416 ;
    END
  END i_slot[11]
  PIN i_slot[12]
    DIRECTION INPUT ;
    USE SIGNAL ;
    PORT
      LAYER M4 ;
        RECT  0 127.824 0.084 127.848 ;
    END
  END i_slot[12]
  PIN i_slot[13]
    DIRECTION INPUT ;
    USE SIGNAL ;
    PORT
      LAYER M4 ;
        RECT  0 128.256 0.084 128.28 ;
    END
  END i_slot[13]
  PIN i_slot[14]
    DIRECTION INPUT ;
    USE SIGNAL ;
    PORT
      LAYER M4 ;
        RECT  0 128.688 0.084 128.712 ;
    END
  END i_slot[14]
  PIN i_slot[15]
    DIRECTION INPUT ;
    USE SIGNAL ;
    PORT
      LAYER M4 ;
        RECT  0 129.12 0.084 129.144 ;
    END
  END i_slot[15]
  PIN i_slot[16]
    DIRECTION INPUT ;
    USE SIGNAL ;
    PORT
      LAYER M4 ;
        RECT  0 129.552 0.084 129.576 ;
    END
  END i_slot[16]
  PIN i_slot[17]
    DIRECTION INPUT ;
    USE SIGNAL ;
    PORT
      LAYER M4 ;
        RECT  0 129.984 0.084 130.008 ;
    END
  END i_slot[17]
  PIN i_slot[18]
    DIRECTION INPUT ;
    USE SIGNAL ;
    PORT
      LAYER M4 ;
        RECT  0 130.416 0.084 130.44 ;
    END
  END i_slot[18]
  PIN i_slot[19]
    DIRECTION INPUT ;
    USE SIGNAL ;
    PORT
      LAYER M4 ;
        RECT  0 130.848 0.084 130.872 ;
    END
  END i_slot[19]
  PIN i_slot[1]
    DIRECTION INPUT ;
    USE SIGNAL ;
    PORT
      LAYER M4 ;
        RECT  0 123.072 0.084 123.096 ;
    END
  END i_slot[1]
  PIN i_slot[20]
    DIRECTION INPUT ;
    USE SIGNAL ;
    PORT
      LAYER M4 ;
        RECT  0 131.28 0.084 131.304 ;
    END
  END i_slot[20]
  PIN i_slot[21]
    DIRECTION INPUT ;
    USE SIGNAL ;
    PORT
      LAYER M4 ;
        RECT  0 131.712 0.084 131.736 ;
    END
  END i_slot[21]
  PIN i_slot[22]
    DIRECTION INPUT ;
    USE SIGNAL ;
    PORT
      LAYER M4 ;
        RECT  0 132.144 0.084 132.168 ;
    END
  END i_slot[22]
  PIN i_slot[23]
    DIRECTION INPUT ;
    USE SIGNAL ;
    PORT
      LAYER M4 ;
        RECT  0 132.576 0.084 132.6 ;
    END
  END i_slot[23]
  PIN i_slot[24]
    DIRECTION INPUT ;
    USE SIGNAL ;
    PORT
      LAYER M4 ;
        RECT  0 133.008 0.084 133.032 ;
    END
  END i_slot[24]
  PIN i_slot[25]
    DIRECTION INPUT ;
    USE SIGNAL ;
    PORT
      LAYER M4 ;
        RECT  0 133.44 0.084 133.464 ;
    END
  END i_slot[25]
  PIN i_slot[26]
    DIRECTION INPUT ;
    USE SIGNAL ;
    PORT
      LAYER M4 ;
        RECT  0 133.872 0.084 133.896 ;
    END
  END i_slot[26]
  PIN i_slot[27]
    DIRECTION INPUT ;
    USE SIGNAL ;
    PORT
      LAYER M4 ;
        RECT  0 134.304 0.084 134.328 ;
    END
  END i_slot[27]
  PIN i_slot[28]
    DIRECTION INPUT ;
    USE SIGNAL ;
    PORT
      LAYER M4 ;
        RECT  0 134.736 0.084 134.76 ;
    END
  END i_slot[28]
  PIN i_slot[29]
    DIRECTION INPUT ;
    USE SIGNAL ;
    PORT
      LAYER M4 ;
        RECT  0 135.168 0.084 135.192 ;
    END
  END i_slot[29]
  PIN i_slot[2]
    DIRECTION INPUT ;
    USE SIGNAL ;
    PORT
      LAYER M4 ;
        RECT  0 123.504 0.084 123.528 ;
    END
  END i_slot[2]
  PIN i_slot[30]
    DIRECTION INPUT ;
    USE SIGNAL ;
    PORT
      LAYER M4 ;
        RECT  0 135.6 0.084 135.624 ;
    END
  END i_slot[30]
  PIN i_slot[31]
    DIRECTION INPUT ;
    USE SIGNAL ;
    PORT
      LAYER M4 ;
        RECT  0 136.032 0.084 136.056 ;
    END
  END i_slot[31]
  PIN i_slot[32]
    DIRECTION INPUT ;
    USE SIGNAL ;
    PORT
      LAYER M4 ;
        RECT  0 136.464 0.084 136.488 ;
    END
  END i_slot[32]
  PIN i_slot[33]
    DIRECTION INPUT ;
    USE SIGNAL ;
    PORT
      LAYER M4 ;
        RECT  0 136.896 0.084 136.92 ;
    END
  END i_slot[33]
  PIN i_slot[34]
    DIRECTION INPUT ;
    USE SIGNAL ;
    PORT
      LAYER M4 ;
        RECT  0 137.328 0.084 137.352 ;
    END
  END i_slot[34]
  PIN i_slot[35]
    DIRECTION INPUT ;
    USE SIGNAL ;
    PORT
      LAYER M4 ;
        RECT  0 137.76 0.084 137.784 ;
    END
  END i_slot[35]
  PIN i_slot[36]
    DIRECTION INPUT ;
    USE SIGNAL ;
    PORT
      LAYER M4 ;
        RECT  0 138.192 0.084 138.216 ;
    END
  END i_slot[36]
  PIN i_slot[37]
    DIRECTION INPUT ;
    USE SIGNAL ;
    PORT
      LAYER M4 ;
        RECT  0 138.624 0.084 138.648 ;
    END
  END i_slot[37]
  PIN i_slot[38]
    DIRECTION INPUT ;
    USE SIGNAL ;
    PORT
      LAYER M4 ;
        RECT  0 139.056 0.084 139.08 ;
    END
  END i_slot[38]
  PIN i_slot[39]
    DIRECTION INPUT ;
    USE SIGNAL ;
    PORT
      LAYER M4 ;
        RECT  0 139.488 0.084 139.512 ;
    END
  END i_slot[39]
  PIN i_slot[3]
    DIRECTION INPUT ;
    USE SIGNAL ;
    PORT
      LAYER M4 ;
        RECT  0 123.936 0.084 123.96 ;
    END
  END i_slot[3]
  PIN i_slot[40]
    DIRECTION INPUT ;
    USE SIGNAL ;
    PORT
      LAYER M4 ;
        RECT  0 139.92 0.084 139.944 ;
    END
  END i_slot[40]
  PIN i_slot[41]
    DIRECTION INPUT ;
    USE SIGNAL ;
    PORT
      LAYER M4 ;
        RECT  0 140.352 0.084 140.376 ;
    END
  END i_slot[41]
  PIN i_slot[42]
    DIRECTION INPUT ;
    USE SIGNAL ;
    PORT
      LAYER M4 ;
        RECT  0 140.784 0.084 140.808 ;
    END
  END i_slot[42]
  PIN i_slot[43]
    DIRECTION INPUT ;
    USE SIGNAL ;
    PORT
      LAYER M4 ;
        RECT  0 141.216 0.084 141.24 ;
    END
  END i_slot[43]
  PIN i_slot[44]
    DIRECTION INPUT ;
    USE SIGNAL ;
    PORT
      LAYER M4 ;
        RECT  0 141.648 0.084 141.672 ;
    END
  END i_slot[44]
  PIN i_slot[45]
    DIRECTION INPUT ;
    USE SIGNAL ;
    PORT
      LAYER M4 ;
        RECT  0 142.08 0.084 142.104 ;
    END
  END i_slot[45]
  PIN i_slot[46]
    DIRECTION INPUT ;
    USE SIGNAL ;
    PORT
      LAYER M4 ;
        RECT  0 142.512 0.084 142.536 ;
    END
  END i_slot[46]
  PIN i_slot[47]
    DIRECTION INPUT ;
    USE SIGNAL ;
    PORT
      LAYER M4 ;
        RECT  0 142.944 0.084 142.968 ;
    END
  END i_slot[47]
  PIN i_slot[48]
    DIRECTION INPUT ;
    USE SIGNAL ;
    PORT
      LAYER M4 ;
        RECT  0 143.376 0.084 143.4 ;
    END
  END i_slot[48]
  PIN i_slot[49]
    DIRECTION INPUT ;
    USE SIGNAL ;
    PORT
      LAYER M4 ;
        RECT  0 143.808 0.084 143.832 ;
    END
  END i_slot[49]
  PIN i_slot[4]
    DIRECTION INPUT ;
    USE SIGNAL ;
    PORT
      LAYER M4 ;
        RECT  0 124.368 0.084 124.392 ;
    END
  END i_slot[4]
  PIN i_slot[50]
    DIRECTION INPUT ;
    USE SIGNAL ;
    PORT
      LAYER M4 ;
        RECT  0 144.24 0.084 144.264 ;
    END
  END i_slot[50]
  PIN i_slot[51]
    DIRECTION INPUT ;
    USE SIGNAL ;
    PORT
      LAYER M4 ;
        RECT  0 144.672 0.084 144.696 ;
    END
  END i_slot[51]
  PIN i_slot[52]
    DIRECTION INPUT ;
    USE SIGNAL ;
    PORT
      LAYER M4 ;
        RECT  0 145.104 0.084 145.128 ;
    END
  END i_slot[52]
  PIN i_slot[53]
    DIRECTION INPUT ;
    USE SIGNAL ;
    PORT
      LAYER M4 ;
        RECT  0 145.536 0.084 145.56 ;
    END
  END i_slot[53]
  PIN i_slot[54]
    DIRECTION INPUT ;
    USE SIGNAL ;
    PORT
      LAYER M4 ;
        RECT  0 145.968 0.084 145.992 ;
    END
  END i_slot[54]
  PIN i_slot[55]
    DIRECTION INPUT ;
    USE SIGNAL ;
    PORT
      LAYER M4 ;
        RECT  0 146.4 0.084 146.424 ;
    END
  END i_slot[55]
  PIN i_slot[56]
    DIRECTION INPUT ;
    USE SIGNAL ;
    PORT
      LAYER M4 ;
        RECT  0 146.832 0.084 146.856 ;
    END
  END i_slot[56]
  PIN i_slot[57]
    DIRECTION INPUT ;
    USE SIGNAL ;
    PORT
      LAYER M4 ;
        RECT  0 147.264 0.084 147.288 ;
    END
  END i_slot[57]
  PIN i_slot[58]
    DIRECTION INPUT ;
    USE SIGNAL ;
    PORT
      LAYER M4 ;
        RECT  0 147.696 0.084 147.72 ;
    END
  END i_slot[58]
  PIN i_slot[59]
    DIRECTION INPUT ;
    USE SIGNAL ;
    PORT
      LAYER M4 ;
        RECT  0 148.128 0.084 148.152 ;
    END
  END i_slot[59]
  PIN i_slot[5]
    DIRECTION INPUT ;
    USE SIGNAL ;
    PORT
      LAYER M4 ;
        RECT  0 124.8 0.084 124.824 ;
    END
  END i_slot[5]
  PIN i_slot[60]
    DIRECTION INPUT ;
    USE SIGNAL ;
    PORT
      LAYER M4 ;
        RECT  0 148.56 0.084 148.584 ;
    END
  END i_slot[60]
  PIN i_slot[61]
    DIRECTION INPUT ;
    USE SIGNAL ;
    PORT
      LAYER M4 ;
        RECT  0 148.992 0.084 149.016 ;
    END
  END i_slot[61]
  PIN i_slot[62]
    DIRECTION INPUT ;
    USE SIGNAL ;
    PORT
      LAYER M4 ;
        RECT  0 149.424 0.084 149.448 ;
    END
  END i_slot[62]
  PIN i_slot[63]
    DIRECTION INPUT ;
    USE SIGNAL ;
    PORT
      LAYER M4 ;
        RECT  0 149.856 0.084 149.88 ;
    END
  END i_slot[63]
  PIN i_slot[64]
    DIRECTION INPUT ;
    USE SIGNAL ;
    PORT
      LAYER M4 ;
        RECT  0 150.288 0.084 150.312 ;
    END
  END i_slot[64]
  PIN i_slot[65]
    DIRECTION INPUT ;
    USE SIGNAL ;
    PORT
      LAYER M4 ;
        RECT  0 150.72 0.084 150.744 ;
    END
  END i_slot[65]
  PIN i_slot[66]
    DIRECTION INPUT ;
    USE SIGNAL ;
    PORT
      LAYER M4 ;
        RECT  0 151.152 0.084 151.176 ;
    END
  END i_slot[66]
  PIN i_slot[67]
    DIRECTION INPUT ;
    USE SIGNAL ;
    PORT
      LAYER M4 ;
        RECT  0 151.584 0.084 151.608 ;
    END
  END i_slot[67]
  PIN i_slot[68]
    DIRECTION INPUT ;
    USE SIGNAL ;
    PORT
      LAYER M4 ;
        RECT  0 152.016 0.084 152.04 ;
    END
  END i_slot[68]
  PIN i_slot[69]
    DIRECTION INPUT ;
    USE SIGNAL ;
    PORT
      LAYER M4 ;
        RECT  0 152.448 0.084 152.472 ;
    END
  END i_slot[69]
  PIN i_slot[6]
    DIRECTION INPUT ;
    USE SIGNAL ;
    PORT
      LAYER M4 ;
        RECT  0 125.232 0.084 125.256 ;
    END
  END i_slot[6]
  PIN i_slot[70]
    DIRECTION INPUT ;
    USE SIGNAL ;
    PORT
      LAYER M4 ;
        RECT  0 152.88 0.084 152.904 ;
    END
  END i_slot[70]
  PIN i_slot[71]
    DIRECTION INPUT ;
    USE SIGNAL ;
    PORT
      LAYER M4 ;
        RECT  0 153.312 0.084 153.336 ;
    END
  END i_slot[71]
  PIN i_slot[72]
    DIRECTION INPUT ;
    USE SIGNAL ;
    PORT
      LAYER M4 ;
        RECT  0 153.744 0.084 153.768 ;
    END
  END i_slot[72]
  PIN i_slot[73]
    DIRECTION INPUT ;
    USE SIGNAL ;
    PORT
      LAYER M4 ;
        RECT  0 154.176 0.084 154.2 ;
    END
  END i_slot[73]
  PIN i_slot[74]
    DIRECTION INPUT ;
    USE SIGNAL ;
    PORT
      LAYER M4 ;
        RECT  0 154.608 0.084 154.632 ;
    END
  END i_slot[74]
  PIN i_slot[75]
    DIRECTION INPUT ;
    USE SIGNAL ;
    PORT
      LAYER M4 ;
        RECT  0 155.04 0.084 155.064 ;
    END
  END i_slot[75]
  PIN i_slot[76]
    DIRECTION INPUT ;
    USE SIGNAL ;
    PORT
      LAYER M4 ;
        RECT  0 155.472 0.084 155.496 ;
    END
  END i_slot[76]
  PIN i_slot[77]
    DIRECTION INPUT ;
    USE SIGNAL ;
    PORT
      LAYER M4 ;
        RECT  0 155.904 0.084 155.928 ;
    END
  END i_slot[77]
  PIN i_slot[78]
    DIRECTION INPUT ;
    USE SIGNAL ;
    PORT
      LAYER M4 ;
        RECT  0 156.336 0.084 156.36 ;
    END
  END i_slot[78]
  PIN i_slot[79]
    DIRECTION INPUT ;
    USE SIGNAL ;
    PORT
      LAYER M4 ;
        RECT  0 156.768 0.084 156.792 ;
    END
  END i_slot[79]
  PIN i_slot[7]
    DIRECTION INPUT ;
    USE SIGNAL ;
    PORT
      LAYER M4 ;
        RECT  0 125.664 0.084 125.688 ;
    END
  END i_slot[7]
  PIN i_slot[80]
    DIRECTION INPUT ;
    USE SIGNAL ;
    PORT
      LAYER M4 ;
        RECT  0 157.2 0.084 157.224 ;
    END
  END i_slot[80]
  PIN i_slot[81]
    DIRECTION INPUT ;
    USE SIGNAL ;
    PORT
      LAYER M4 ;
        RECT  0 157.632 0.084 157.656 ;
    END
  END i_slot[81]
  PIN i_slot[82]
    DIRECTION INPUT ;
    USE SIGNAL ;
    PORT
      LAYER M4 ;
        RECT  0 158.064 0.084 158.088 ;
    END
  END i_slot[82]
  PIN i_slot[83]
    DIRECTION INPUT ;
    USE SIGNAL ;
    PORT
      LAYER M4 ;
        RECT  0 158.496 0.084 158.52 ;
    END
  END i_slot[83]
  PIN i_slot[84]
    DIRECTION INPUT ;
    USE SIGNAL ;
    PORT
      LAYER M4 ;
        RECT  0 158.928 0.084 158.952 ;
    END
  END i_slot[84]
  PIN i_slot[85]
    DIRECTION INPUT ;
    USE SIGNAL ;
    PORT
      LAYER M4 ;
        RECT  0 159.36 0.084 159.384 ;
    END
  END i_slot[85]
  PIN i_slot[86]
    DIRECTION INPUT ;
    USE SIGNAL ;
    PORT
      LAYER M4 ;
        RECT  0 159.792 0.084 159.816 ;
    END
  END i_slot[86]
  PIN i_slot[87]
    DIRECTION INPUT ;
    USE SIGNAL ;
    PORT
      LAYER M4 ;
        RECT  0 160.224 0.084 160.248 ;
    END
  END i_slot[87]
  PIN i_slot[88]
    DIRECTION INPUT ;
    USE SIGNAL ;
    PORT
      LAYER M4 ;
        RECT  0 160.656 0.084 160.68 ;
    END
  END i_slot[88]
  PIN i_slot[89]
    DIRECTION INPUT ;
    USE SIGNAL ;
    PORT
      LAYER M4 ;
        RECT  0 161.088 0.084 161.112 ;
    END
  END i_slot[89]
  PIN i_slot[8]
    DIRECTION INPUT ;
    USE SIGNAL ;
    PORT
      LAYER M4 ;
        RECT  0 126.096 0.084 126.12 ;
    END
  END i_slot[8]
  PIN i_slot[9]
    DIRECTION INPUT ;
    USE SIGNAL ;
    PORT
      LAYER M4 ;
        RECT  0 126.528 0.084 126.552 ;
    END
  END i_slot[9]
  PIN i_v[0]
    DIRECTION INPUT ;
    USE SIGNAL ;
    PORT
      LAYER M4 ;
        RECT  0 6 0.084 6.024 ;
    END
  END i_v[0]
  PIN i_v[10]
    DIRECTION INPUT ;
    USE SIGNAL ;
    PORT
      LAYER M4 ;
        RECT  0 10.32 0.084 10.344 ;
    END
  END i_v[10]
  PIN i_v[11]
    DIRECTION INPUT ;
    USE SIGNAL ;
    PORT
      LAYER M4 ;
        RECT  0 10.752 0.084 10.776 ;
    END
  END i_v[11]
  PIN i_v[12]
    DIRECTION INPUT ;
    USE SIGNAL ;
    PORT
      LAYER M4 ;
        RECT  0 11.184 0.084 11.208 ;
    END
  END i_v[12]
  PIN i_v[13]
    DIRECTION INPUT ;
    USE SIGNAL ;
    PORT
      LAYER M4 ;
        RECT  0 11.616 0.084 11.64 ;
    END
  END i_v[13]
  PIN i_v[14]
    DIRECTION INPUT ;
    USE SIGNAL ;
    PORT
      LAYER M4 ;
        RECT  0 12.048 0.084 12.072 ;
    END
  END i_v[14]
  PIN i_v[15]
    DIRECTION INPUT ;
    USE SIGNAL ;
    PORT
      LAYER M4 ;
        RECT  0 12.48 0.084 12.504 ;
    END
  END i_v[15]
  PIN i_v[16]
    DIRECTION INPUT ;
    USE SIGNAL ;
    PORT
      LAYER M4 ;
        RECT  0 12.912 0.084 12.936 ;
    END
  END i_v[16]
  PIN i_v[17]
    DIRECTION INPUT ;
    USE SIGNAL ;
    PORT
      LAYER M4 ;
        RECT  0 13.344 0.084 13.368 ;
    END
  END i_v[17]
  PIN i_v[1]
    DIRECTION INPUT ;
    USE SIGNAL ;
    PORT
      LAYER M4 ;
        RECT  0 6.432 0.084 6.456 ;
    END
  END i_v[1]
  PIN i_v[2]
    DIRECTION INPUT ;
    USE SIGNAL ;
    PORT
      LAYER M4 ;
        RECT  0 6.864 0.084 6.888 ;
    END
  END i_v[2]
  PIN i_v[3]
    DIRECTION INPUT ;
    USE SIGNAL ;
    PORT
      LAYER M4 ;
        RECT  0 7.296 0.084 7.32 ;
    END
  END i_v[3]
  PIN i_v[4]
    DIRECTION INPUT ;
    USE SIGNAL ;
    PORT
      LAYER M4 ;
        RECT  0 7.728 0.084 7.752 ;
    END
  END i_v[4]
  PIN i_v[5]
    DIRECTION INPUT ;
    USE SIGNAL ;
    PORT
      LAYER M4 ;
        RECT  0 8.16 0.084 8.184 ;
    END
  END i_v[5]
  PIN i_v[6]
    DIRECTION INPUT ;
    USE SIGNAL ;
    PORT
      LAYER M4 ;
        RECT  0 8.592 0.084 8.616 ;
    END
  END i_v[6]
  PIN i_v[7]
    DIRECTION INPUT ;
    USE SIGNAL ;
    PORT
      LAYER M4 ;
        RECT  0 9.024 0.084 9.048 ;
    END
  END i_v[7]
  PIN i_v[8]
    DIRECTION INPUT ;
    USE SIGNAL ;
    PORT
      LAYER M4 ;
        RECT  0 9.456 0.084 9.48 ;
    END
  END i_v[8]
  PIN i_v[9]
    DIRECTION INPUT ;
    USE SIGNAL ;
    PORT
      LAYER M4 ;
        RECT  0 9.888 0.084 9.912 ;
    END
  END i_v[9]
  PIN o_addr[0]
    DIRECTION OUTPUT ;
    USE SIGNAL ;
    PORT
      LAYER M4 ;
        RECT  155.436 95.424 155.52 95.448 ;
    END
  END o_addr[0]
  PIN o_addr[10]
    DIRECTION OUTPUT ;
    USE SIGNAL ;
    PORT
      LAYER M4 ;
        RECT  155.436 99.744 155.52 99.768 ;
    END
  END o_addr[10]
  PIN o_addr[11]
    DIRECTION OUTPUT ;
    USE SIGNAL ;
    PORT
      LAYER M4 ;
        RECT  155.436 100.176 155.52 100.2 ;
    END
  END o_addr[11]
  PIN o_addr[12]
    DIRECTION OUTPUT ;
    USE SIGNAL ;
    PORT
      LAYER M4 ;
        RECT  155.436 100.608 155.52 100.632 ;
    END
  END o_addr[12]
  PIN o_addr[13]
    DIRECTION OUTPUT ;
    USE SIGNAL ;
    PORT
      LAYER M4 ;
        RECT  155.436 101.04 155.52 101.064 ;
    END
  END o_addr[13]
  PIN o_addr[14]
    DIRECTION OUTPUT ;
    USE SIGNAL ;
    PORT
      LAYER M4 ;
        RECT  155.436 101.472 155.52 101.496 ;
    END
  END o_addr[14]
  PIN o_addr[15]
    DIRECTION OUTPUT ;
    USE SIGNAL ;
    PORT
      LAYER M4 ;
        RECT  155.436 101.904 155.52 101.928 ;
    END
  END o_addr[15]
  PIN o_addr[16]
    DIRECTION OUTPUT ;
    USE SIGNAL ;
    PORT
      LAYER M4 ;
        RECT  155.436 102.336 155.52 102.36 ;
    END
  END o_addr[16]
  PIN o_addr[17]
    DIRECTION OUTPUT ;
    USE SIGNAL ;
    PORT
      LAYER M4 ;
        RECT  155.436 102.768 155.52 102.792 ;
    END
  END o_addr[17]
  PIN o_addr[18]
    DIRECTION OUTPUT ;
    USE SIGNAL ;
    PORT
      LAYER M4 ;
        RECT  155.436 103.2 155.52 103.224 ;
    END
  END o_addr[18]
  PIN o_addr[19]
    DIRECTION OUTPUT ;
    USE SIGNAL ;
    PORT
      LAYER M4 ;
        RECT  155.436 103.632 155.52 103.656 ;
    END
  END o_addr[19]
  PIN o_addr[1]
    DIRECTION OUTPUT ;
    USE SIGNAL ;
    PORT
      LAYER M4 ;
        RECT  155.436 95.856 155.52 95.88 ;
    END
  END o_addr[1]
  PIN o_addr[20]
    DIRECTION OUTPUT ;
    USE SIGNAL ;
    PORT
      LAYER M4 ;
        RECT  155.436 104.064 155.52 104.088 ;
    END
  END o_addr[20]
  PIN o_addr[21]
    DIRECTION OUTPUT ;
    USE SIGNAL ;
    PORT
      LAYER M4 ;
        RECT  155.436 104.496 155.52 104.52 ;
    END
  END o_addr[21]
  PIN o_addr[22]
    DIRECTION OUTPUT ;
    USE SIGNAL ;
    PORT
      LAYER M4 ;
        RECT  155.436 104.928 155.52 104.952 ;
    END
  END o_addr[22]
  PIN o_addr[23]
    DIRECTION OUTPUT ;
    USE SIGNAL ;
    PORT
      LAYER M4 ;
        RECT  155.436 105.36 155.52 105.384 ;
    END
  END o_addr[23]
  PIN o_addr[24]
    DIRECTION OUTPUT ;
    USE SIGNAL ;
    PORT
      LAYER M4 ;
        RECT  155.436 105.792 155.52 105.816 ;
    END
  END o_addr[24]
  PIN o_addr[25]
    DIRECTION OUTPUT ;
    USE SIGNAL ;
    PORT
      LAYER M4 ;
        RECT  155.436 106.224 155.52 106.248 ;
    END
  END o_addr[25]
  PIN o_addr[26]
    DIRECTION OUTPUT ;
    USE SIGNAL ;
    PORT
      LAYER M4 ;
        RECT  155.436 106.656 155.52 106.68 ;
    END
  END o_addr[26]
  PIN o_addr[27]
    DIRECTION OUTPUT ;
    USE SIGNAL ;
    PORT
      LAYER M4 ;
        RECT  155.436 107.088 155.52 107.112 ;
    END
  END o_addr[27]
  PIN o_addr[28]
    DIRECTION OUTPUT ;
    USE SIGNAL ;
    PORT
      LAYER M4 ;
        RECT  155.436 107.52 155.52 107.544 ;
    END
  END o_addr[28]
  PIN o_addr[29]
    DIRECTION OUTPUT ;
    USE SIGNAL ;
    PORT
      LAYER M4 ;
        RECT  155.436 107.952 155.52 107.976 ;
    END
  END o_addr[29]
  PIN o_addr[2]
    DIRECTION OUTPUT ;
    USE SIGNAL ;
    PORT
      LAYER M4 ;
        RECT  155.436 96.288 155.52 96.312 ;
    END
  END o_addr[2]
  PIN o_addr[30]
    DIRECTION OUTPUT ;
    USE SIGNAL ;
    PORT
      LAYER M4 ;
        RECT  155.436 108.384 155.52 108.408 ;
    END
  END o_addr[30]
  PIN o_addr[31]
    DIRECTION OUTPUT ;
    USE SIGNAL ;
    PORT
      LAYER M4 ;
        RECT  155.436 108.816 155.52 108.84 ;
    END
  END o_addr[31]
  PIN o_addr[32]
    DIRECTION OUTPUT ;
    USE SIGNAL ;
    PORT
      LAYER M4 ;
        RECT  155.436 109.248 155.52 109.272 ;
    END
  END o_addr[32]
  PIN o_addr[33]
    DIRECTION OUTPUT ;
    USE SIGNAL ;
    PORT
      LAYER M4 ;
        RECT  155.436 109.68 155.52 109.704 ;
    END
  END o_addr[33]
  PIN o_addr[34]
    DIRECTION OUTPUT ;
    USE SIGNAL ;
    PORT
      LAYER M4 ;
        RECT  155.436 110.112 155.52 110.136 ;
    END
  END o_addr[34]
  PIN o_addr[35]
    DIRECTION OUTPUT ;
    USE SIGNAL ;
    PORT
      LAYER M4 ;
        RECT  155.436 110.544 155.52 110.568 ;
    END
  END o_addr[35]
  PIN o_addr[36]
    DIRECTION OUTPUT ;
    USE SIGNAL ;
    PORT
      LAYER M4 ;
        RECT  155.436 110.976 155.52 111 ;
    END
  END o_addr[36]
  PIN o_addr[37]
    DIRECTION OUTPUT ;
    USE SIGNAL ;
    PORT
      LAYER M4 ;
        RECT  155.436 111.408 155.52 111.432 ;
    END
  END o_addr[37]
  PIN o_addr[38]
    DIRECTION OUTPUT ;
    USE SIGNAL ;
    PORT
      LAYER M4 ;
        RECT  155.436 111.84 155.52 111.864 ;
    END
  END o_addr[38]
  PIN o_addr[39]
    DIRECTION OUTPUT ;
    USE SIGNAL ;
    PORT
      LAYER M4 ;
        RECT  155.436 112.272 155.52 112.296 ;
    END
  END o_addr[39]
  PIN o_addr[3]
    DIRECTION OUTPUT ;
    USE SIGNAL ;
    PORT
      LAYER M4 ;
        RECT  155.436 96.72 155.52 96.744 ;
    END
  END o_addr[3]
  PIN o_addr[40]
    DIRECTION OUTPUT ;
    USE SIGNAL ;
    PORT
      LAYER M4 ;
        RECT  155.436 112.704 155.52 112.728 ;
    END
  END o_addr[40]
  PIN o_addr[41]
    DIRECTION OUTPUT ;
    USE SIGNAL ;
    PORT
      LAYER M4 ;
        RECT  155.436 113.136 155.52 113.16 ;
    END
  END o_addr[41]
  PIN o_addr[42]
    DIRECTION OUTPUT ;
    USE SIGNAL ;
    PORT
      LAYER M4 ;
        RECT  155.436 113.568 155.52 113.592 ;
    END
  END o_addr[42]
  PIN o_addr[43]
    DIRECTION OUTPUT ;
    USE SIGNAL ;
    PORT
      LAYER M4 ;
        RECT  155.436 114 155.52 114.024 ;
    END
  END o_addr[43]
  PIN o_addr[44]
    DIRECTION OUTPUT ;
    USE SIGNAL ;
    PORT
      LAYER M4 ;
        RECT  155.436 114.432 155.52 114.456 ;
    END
  END o_addr[44]
  PIN o_addr[45]
    DIRECTION OUTPUT ;
    USE SIGNAL ;
    PORT
      LAYER M4 ;
        RECT  155.436 114.864 155.52 114.888 ;
    END
  END o_addr[45]
  PIN o_addr[46]
    DIRECTION OUTPUT ;
    USE SIGNAL ;
    PORT
      LAYER M4 ;
        RECT  155.436 115.296 155.52 115.32 ;
    END
  END o_addr[46]
  PIN o_addr[47]
    DIRECTION OUTPUT ;
    USE SIGNAL ;
    PORT
      LAYER M4 ;
        RECT  155.436 115.728 155.52 115.752 ;
    END
  END o_addr[47]
  PIN o_addr[48]
    DIRECTION OUTPUT ;
    USE SIGNAL ;
    PORT
      LAYER M4 ;
        RECT  155.436 116.16 155.52 116.184 ;
    END
  END o_addr[48]
  PIN o_addr[49]
    DIRECTION OUTPUT ;
    USE SIGNAL ;
    PORT
      LAYER M4 ;
        RECT  155.436 116.592 155.52 116.616 ;
    END
  END o_addr[49]
  PIN o_addr[4]
    DIRECTION OUTPUT ;
    USE SIGNAL ;
    PORT
      LAYER M4 ;
        RECT  155.436 97.152 155.52 97.176 ;
    END
  END o_addr[4]
  PIN o_addr[50]
    DIRECTION OUTPUT ;
    USE SIGNAL ;
    PORT
      LAYER M4 ;
        RECT  155.436 117.024 155.52 117.048 ;
    END
  END o_addr[50]
  PIN o_addr[51]
    DIRECTION OUTPUT ;
    USE SIGNAL ;
    PORT
      LAYER M4 ;
        RECT  155.436 117.456 155.52 117.48 ;
    END
  END o_addr[51]
  PIN o_addr[52]
    DIRECTION OUTPUT ;
    USE SIGNAL ;
    PORT
      LAYER M4 ;
        RECT  155.436 117.888 155.52 117.912 ;
    END
  END o_addr[52]
  PIN o_addr[53]
    DIRECTION OUTPUT ;
    USE SIGNAL ;
    PORT
      LAYER M4 ;
        RECT  155.436 118.32 155.52 118.344 ;
    END
  END o_addr[53]
  PIN o_addr[54]
    DIRECTION OUTPUT ;
    USE SIGNAL ;
    PORT
      LAYER M4 ;
        RECT  155.436 118.752 155.52 118.776 ;
    END
  END o_addr[54]
  PIN o_addr[55]
    DIRECTION OUTPUT ;
    USE SIGNAL ;
    PORT
      LAYER M4 ;
        RECT  155.436 119.184 155.52 119.208 ;
    END
  END o_addr[55]
  PIN o_addr[56]
    DIRECTION OUTPUT ;
    USE SIGNAL ;
    PORT
      LAYER M4 ;
        RECT  155.436 119.616 155.52 119.64 ;
    END
  END o_addr[56]
  PIN o_addr[57]
    DIRECTION OUTPUT ;
    USE SIGNAL ;
    PORT
      LAYER M4 ;
        RECT  155.436 120.048 155.52 120.072 ;
    END
  END o_addr[57]
  PIN o_addr[58]
    DIRECTION OUTPUT ;
    USE SIGNAL ;
    PORT
      LAYER M4 ;
        RECT  155.436 120.48 155.52 120.504 ;
    END
  END o_addr[58]
  PIN o_addr[59]
    DIRECTION OUTPUT ;
    USE SIGNAL ;
    PORT
      LAYER M4 ;
        RECT  155.436 120.912 155.52 120.936 ;
    END
  END o_addr[59]
  PIN o_addr[5]
    DIRECTION OUTPUT ;
    USE SIGNAL ;
    PORT
      LAYER M4 ;
        RECT  155.436 97.584 155.52 97.608 ;
    END
  END o_addr[5]
  PIN o_addr[60]
    DIRECTION OUTPUT ;
    USE SIGNAL ;
    PORT
      LAYER M4 ;
        RECT  155.436 121.344 155.52 121.368 ;
    END
  END o_addr[60]
  PIN o_addr[61]
    DIRECTION OUTPUT ;
    USE SIGNAL ;
    PORT
      LAYER M4 ;
        RECT  155.436 121.776 155.52 121.8 ;
    END
  END o_addr[61]
  PIN o_addr[62]
    DIRECTION OUTPUT ;
    USE SIGNAL ;
    PORT
      LAYER M4 ;
        RECT  155.436 122.208 155.52 122.232 ;
    END
  END o_addr[62]
  PIN o_addr[63]
    DIRECTION OUTPUT ;
    USE SIGNAL ;
    PORT
      LAYER M4 ;
        RECT  155.436 122.64 155.52 122.664 ;
    END
  END o_addr[63]
  PIN o_addr[64]
    DIRECTION OUTPUT ;
    USE SIGNAL ;
    PORT
      LAYER M4 ;
        RECT  155.436 123.072 155.52 123.096 ;
    END
  END o_addr[64]
  PIN o_addr[65]
    DIRECTION OUTPUT ;
    USE SIGNAL ;
    PORT
      LAYER M4 ;
        RECT  155.436 123.504 155.52 123.528 ;
    END
  END o_addr[65]
  PIN o_addr[66]
    DIRECTION OUTPUT ;
    USE SIGNAL ;
    PORT
      LAYER M4 ;
        RECT  155.436 123.936 155.52 123.96 ;
    END
  END o_addr[66]
  PIN o_addr[67]
    DIRECTION OUTPUT ;
    USE SIGNAL ;
    PORT
      LAYER M4 ;
        RECT  155.436 124.368 155.52 124.392 ;
    END
  END o_addr[67]
  PIN o_addr[68]
    DIRECTION OUTPUT ;
    USE SIGNAL ;
    PORT
      LAYER M4 ;
        RECT  155.436 124.8 155.52 124.824 ;
    END
  END o_addr[68]
  PIN o_addr[69]
    DIRECTION OUTPUT ;
    USE SIGNAL ;
    PORT
      LAYER M4 ;
        RECT  155.436 125.232 155.52 125.256 ;
    END
  END o_addr[69]
  PIN o_addr[6]
    DIRECTION OUTPUT ;
    USE SIGNAL ;
    PORT
      LAYER M4 ;
        RECT  155.436 98.016 155.52 98.04 ;
    END
  END o_addr[6]
  PIN o_addr[70]
    DIRECTION OUTPUT ;
    USE SIGNAL ;
    PORT
      LAYER M4 ;
        RECT  155.436 125.664 155.52 125.688 ;
    END
  END o_addr[70]
  PIN o_addr[71]
    DIRECTION OUTPUT ;
    USE SIGNAL ;
    PORT
      LAYER M4 ;
        RECT  155.436 126.096 155.52 126.12 ;
    END
  END o_addr[71]
  PIN o_addr[7]
    DIRECTION OUTPUT ;
    USE SIGNAL ;
    PORT
      LAYER M4 ;
        RECT  155.436 98.448 155.52 98.472 ;
    END
  END o_addr[7]
  PIN o_addr[8]
    DIRECTION OUTPUT ;
    USE SIGNAL ;
    PORT
      LAYER M4 ;
        RECT  155.436 98.88 155.52 98.904 ;
    END
  END o_addr[8]
  PIN o_addr[9]
    DIRECTION OUTPUT ;
    USE SIGNAL ;
    PORT
      LAYER M4 ;
        RECT  155.436 99.312 155.52 99.336 ;
    END
  END o_addr[9]
  PIN o_tag[0]
    DIRECTION OUTPUT ;
    USE SIGNAL ;
    PORT
      LAYER M4 ;
        RECT  155.436 126.528 155.52 126.552 ;
    END
  END o_tag[0]
  PIN o_tag[10]
    DIRECTION OUTPUT ;
    USE SIGNAL ;
    PORT
      LAYER M4 ;
        RECT  155.436 130.848 155.52 130.872 ;
    END
  END o_tag[10]
  PIN o_tag[11]
    DIRECTION OUTPUT ;
    USE SIGNAL ;
    PORT
      LAYER M4 ;
        RECT  155.436 131.28 155.52 131.304 ;
    END
  END o_tag[11]
  PIN o_tag[12]
    DIRECTION OUTPUT ;
    USE SIGNAL ;
    PORT
      LAYER M4 ;
        RECT  155.436 131.712 155.52 131.736 ;
    END
  END o_tag[12]
  PIN o_tag[13]
    DIRECTION OUTPUT ;
    USE SIGNAL ;
    PORT
      LAYER M4 ;
        RECT  155.436 132.144 155.52 132.168 ;
    END
  END o_tag[13]
  PIN o_tag[14]
    DIRECTION OUTPUT ;
    USE SIGNAL ;
    PORT
      LAYER M4 ;
        RECT  155.436 132.576 155.52 132.6 ;
    END
  END o_tag[14]
  PIN o_tag[15]
    DIRECTION OUTPUT ;
    USE SIGNAL ;
    PORT
      LAYER M4 ;
        RECT  155.436 133.008 155.52 133.032 ;
    END
  END o_tag[15]
  PIN o_tag[16]
    DIRECTION OUTPUT ;
    USE SIGNAL ;
    PORT
      LAYER M4 ;
        RECT  155.436 133.44 155.52 133.464 ;
    END
  END o_tag[16]
  PIN o_tag[17]
    DIRECTION OUTPUT ;
    USE SIGNAL ;
    PORT
      LAYER M4 ;
        RECT  155.436 133.872 155.52 133.896 ;
    END
  END o_tag[17]
  PIN o_tag[18]
    DIRECTION OUTPUT ;
    USE SIGNAL ;
    PORT
      LAYER M4 ;
        RECT  155.436 134.304 155.52 134.328 ;
    END
  END o_tag[18]
  PIN o_tag[19]
    DIRECTION OUTPUT ;
    USE SIGNAL ;
    PORT
      LAYER M4 ;
        RECT  155.436 134.736 155.52 134.76 ;
    END
  END o_tag[19]
  PIN o_tag[1]
    DIRECTION OUTPUT ;
    USE SIGNAL ;
    PORT
      LAYER M4 ;
        RECT  155.436 126.96 155.52 126.984 ;
    END
  END o_tag[1]
  PIN o_tag[20]
    DIRECTION OUTPUT ;
    USE SIGNAL ;
    PORT
      LAYER M4 ;
        RECT  155.436 135.168 155.52 135.192 ;
    END
  END o_tag[20]
  PIN o_tag[21]
    DIRECTION OUTPUT ;
    USE SIGNAL ;
    PORT
      LAYER M4 ;
        RECT  155.436 135.6 155.52 135.624 ;
    END
  END o_tag[21]
  PIN o_tag[22]
    DIRECTION OUTPUT ;
    USE SIGNAL ;
    PORT
      LAYER M4 ;
        RECT  155.436 136.032 155.52 136.056 ;
    END
  END o_tag[22]
  PIN o_tag[23]
    DIRECTION OUTPUT ;
    USE SIGNAL ;
    PORT
      LAYER M4 ;
        RECT  155.436 136.464 155.52 136.488 ;
    END
  END o_tag[23]
  PIN o_tag[24]
    DIRECTION OUTPUT ;
    USE SIGNAL ;
    PORT
      LAYER M4 ;
        RECT  155.436 136.896 155.52 136.92 ;
    END
  END o_tag[24]
  PIN o_tag[25]
    DIRECTION OUTPUT ;
    USE SIGNAL ;
    PORT
      LAYER M4 ;
        RECT  155.436 137.328 155.52 137.352 ;
    END
  END o_tag[25]
  PIN o_tag[26]
    DIRECTION OUTPUT ;
    USE SIGNAL ;
    PORT
      LAYER M4 ;
        RECT  155.436 137.76 155.52 137.784 ;
    END
  END o_tag[26]
  PIN o_tag[27]
    DIRECTION OUTPUT ;
    USE SIGNAL ;
    PORT
      LAYER M4 ;
        RECT  155.436 138.192 155.52 138.216 ;
    END
  END o_tag[27]
  PIN o_tag[28]
    DIRECTION OUTPUT ;
    USE SIGNAL ;
    PORT
      LAYER M4 ;
        RECT  155.436 138.624 155.52 138.648 ;
    END
  END o_tag[28]
  PIN o_tag[29]
    DIRECTION OUTPUT ;
    USE SIGNAL ;
    PORT
      LAYER M4 ;
        RECT  155.436 139.056 155.52 139.08 ;
    END
  END o_tag[29]
  PIN o_tag[2]
    DIRECTION OUTPUT ;
    USE SIGNAL ;
    PORT
      LAYER M4 ;
        RECT  155.436 127.392 155.52 127.416 ;
    END
  END o_tag[2]
  PIN o_tag[30]
    DIRECTION OUTPUT ;
    USE SIGNAL ;
    PORT
      LAYER M4 ;
        RECT  155.436 139.488 155.52 139.512 ;
    END
  END o_tag[30]
  PIN o_tag[31]
    DIRECTION OUTPUT ;
    USE SIGNAL ;
    PORT
      LAYER M4 ;
        RECT  155.436 139.92 155.52 139.944 ;
    END
  END o_tag[31]
  PIN o_tag[32]
    DIRECTION OUTPUT ;
    USE SIGNAL ;
    PORT
      LAYER M4 ;
        RECT  155.436 140.352 155.52 140.376 ;
    END
  END o_tag[32]
  PIN o_tag[33]
    DIRECTION OUTPUT ;
    USE SIGNAL ;
    PORT
      LAYER M4 ;
        RECT  155.436 140.784 155.52 140.808 ;
    END
  END o_tag[33]
  PIN o_tag[34]
    DIRECTION OUTPUT ;
    USE SIGNAL ;
    PORT
      LAYER M4 ;
        RECT  155.436 141.216 155.52 141.24 ;
    END
  END o_tag[34]
  PIN o_tag[35]
    DIRECTION OUTPUT ;
    USE SIGNAL ;
    PORT
      LAYER M4 ;
        RECT  155.436 141.648 155.52 141.672 ;
    END
  END o_tag[35]
  PIN o_tag[36]
    DIRECTION OUTPUT ;
    USE SIGNAL ;
    PORT
      LAYER M4 ;
        RECT  155.436 142.08 155.52 142.104 ;
    END
  END o_tag[36]
  PIN o_tag[37]
    DIRECTION OUTPUT ;
    USE SIGNAL ;
    PORT
      LAYER M4 ;
        RECT  155.436 142.512 155.52 142.536 ;
    END
  END o_tag[37]
  PIN o_tag[38]
    DIRECTION OUTPUT ;
    USE SIGNAL ;
    PORT
      LAYER M4 ;
        RECT  155.436 142.944 155.52 142.968 ;
    END
  END o_tag[38]
  PIN o_tag[39]
    DIRECTION OUTPUT ;
    USE SIGNAL ;
    PORT
      LAYER M4 ;
        RECT  155.436 143.376 155.52 143.4 ;
    END
  END o_tag[39]
  PIN o_tag[3]
    DIRECTION OUTPUT ;
    USE SIGNAL ;
    PORT
      LAYER M4 ;
        RECT  155.436 127.824 155.52 127.848 ;
    END
  END o_tag[3]
  PIN o_tag[40]
    DIRECTION OUTPUT ;
    USE SIGNAL ;
    PORT
      LAYER M4 ;
        RECT  155.436 143.808 155.52 143.832 ;
    END
  END o_tag[40]
  PIN o_tag[41]
    DIRECTION OUTPUT ;
    USE SIGNAL ;
    PORT
      LAYER M4 ;
        RECT  155.436 144.24 155.52 144.264 ;
    END
  END o_tag[41]
  PIN o_tag[42]
    DIRECTION OUTPUT ;
    USE SIGNAL ;
    PORT
      LAYER M4 ;
        RECT  155.436 144.672 155.52 144.696 ;
    END
  END o_tag[42]
  PIN o_tag[43]
    DIRECTION OUTPUT ;
    USE SIGNAL ;
    PORT
      LAYER M4 ;
        RECT  155.436 145.104 155.52 145.128 ;
    END
  END o_tag[43]
  PIN o_tag[44]
    DIRECTION OUTPUT ;
    USE SIGNAL ;
    PORT
      LAYER M4 ;
        RECT  155.436 145.536 155.52 145.56 ;
    END
  END o_tag[44]
  PIN o_tag[45]
    DIRECTION OUTPUT ;
    USE SIGNAL ;
    PORT
      LAYER M4 ;
        RECT  155.436 145.968 155.52 145.992 ;
    END
  END o_tag[45]
  PIN o_tag[46]
    DIRECTION OUTPUT ;
    USE SIGNAL ;
    PORT
      LAYER M4 ;
        RECT  155.436 146.4 155.52 146.424 ;
    END
  END o_tag[46]
  PIN o_tag[47]
    DIRECTION OUTPUT ;
    USE SIGNAL ;
    PORT
      LAYER M4 ;
        RECT  155.436 146.832 155.52 146.856 ;
    END
  END o_tag[47]
  PIN o_tag[48]
    DIRECTION OUTPUT ;
    USE SIGNAL ;
    PORT
      LAYER M4 ;
        RECT  155.436 147.264 155.52 147.288 ;
    END
  END o_tag[48]
  PIN o_tag[49]
    DIRECTION OUTPUT ;
    USE SIGNAL ;
    PORT
      LAYER M4 ;
        RECT  155.436 147.696 155.52 147.72 ;
    END
  END o_tag[49]
  PIN o_tag[4]
    DIRECTION OUTPUT ;
    USE SIGNAL ;
    PORT
      LAYER M4 ;
        RECT  155.436 128.256 155.52 128.28 ;
    END
  END o_tag[4]
  PIN o_tag[50]
    DIRECTION OUTPUT ;
    USE SIGNAL ;
    PORT
      LAYER M4 ;
        RECT  155.436 148.128 155.52 148.152 ;
    END
  END o_tag[50]
  PIN o_tag[51]
    DIRECTION OUTPUT ;
    USE SIGNAL ;
    PORT
      LAYER M4 ;
        RECT  155.436 148.56 155.52 148.584 ;
    END
  END o_tag[51]
  PIN o_tag[52]
    DIRECTION OUTPUT ;
    USE SIGNAL ;
    PORT
      LAYER M4 ;
        RECT  155.436 148.992 155.52 149.016 ;
    END
  END o_tag[52]
  PIN o_tag[53]
    DIRECTION OUTPUT ;
    USE SIGNAL ;
    PORT
      LAYER M4 ;
        RECT  155.436 149.424 155.52 149.448 ;
    END
  END o_tag[53]
  PIN o_tag[54]
    DIRECTION OUTPUT ;
    USE SIGNAL ;
    PORT
      LAYER M4 ;
        RECT  155.436 149.856 155.52 149.88 ;
    END
  END o_tag[54]
  PIN o_tag[55]
    DIRECTION OUTPUT ;
    USE SIGNAL ;
    PORT
      LAYER M4 ;
        RECT  155.436 150.288 155.52 150.312 ;
    END
  END o_tag[55]
  PIN o_tag[56]
    DIRECTION OUTPUT ;
    USE SIGNAL ;
    PORT
      LAYER M4 ;
        RECT  155.436 150.72 155.52 150.744 ;
    END
  END o_tag[56]
  PIN o_tag[57]
    DIRECTION OUTPUT ;
    USE SIGNAL ;
    PORT
      LAYER M4 ;
        RECT  155.436 151.152 155.52 151.176 ;
    END
  END o_tag[57]
  PIN o_tag[58]
    DIRECTION OUTPUT ;
    USE SIGNAL ;
    PORT
      LAYER M4 ;
        RECT  155.436 151.584 155.52 151.608 ;
    END
  END o_tag[58]
  PIN o_tag[59]
    DIRECTION OUTPUT ;
    USE SIGNAL ;
    PORT
      LAYER M4 ;
        RECT  155.436 152.016 155.52 152.04 ;
    END
  END o_tag[59]
  PIN o_tag[5]
    DIRECTION OUTPUT ;
    USE SIGNAL ;
    PORT
      LAYER M4 ;
        RECT  155.436 128.688 155.52 128.712 ;
    END
  END o_tag[5]
  PIN o_tag[60]
    DIRECTION OUTPUT ;
    USE SIGNAL ;
    PORT
      LAYER M4 ;
        RECT  155.436 152.448 155.52 152.472 ;
    END
  END o_tag[60]
  PIN o_tag[61]
    DIRECTION OUTPUT ;
    USE SIGNAL ;
    PORT
      LAYER M4 ;
        RECT  155.436 152.88 155.52 152.904 ;
    END
  END o_tag[61]
  PIN o_tag[62]
    DIRECTION OUTPUT ;
    USE SIGNAL ;
    PORT
      LAYER M4 ;
        RECT  155.436 153.312 155.52 153.336 ;
    END
  END o_tag[62]
  PIN o_tag[63]
    DIRECTION OUTPUT ;
    USE SIGNAL ;
    PORT
      LAYER M4 ;
        RECT  155.436 153.744 155.52 153.768 ;
    END
  END o_tag[63]
  PIN o_tag[6]
    DIRECTION OUTPUT ;
    USE SIGNAL ;
    PORT
      LAYER M4 ;
        RECT  155.436 129.12 155.52 129.144 ;
    END
  END o_tag[6]
  PIN o_tag[7]
    DIRECTION OUTPUT ;
    USE SIGNAL ;
    PORT
      LAYER M4 ;
        RECT  155.436 129.552 155.52 129.576 ;
    END
  END o_tag[7]
  PIN o_tag[8]
    DIRECTION OUTPUT ;
    USE SIGNAL ;
    PORT
      LAYER M4 ;
        RECT  155.436 129.984 155.52 130.008 ;
    END
  END o_tag[8]
  PIN o_tag[9]
    DIRECTION OUTPUT ;
    USE SIGNAL ;
    PORT
      LAYER M4 ;
        RECT  155.436 130.416 155.52 130.44 ;
    END
  END o_tag[9]
  PIN o_v[0]
    DIRECTION OUTPUT ;
    USE SIGNAL ;
    PORT
      LAYER M4 ;
        RECT  155.436 91.968 155.52 91.992 ;
    END
  END o_v[0]
  PIN o_v[1]
    DIRECTION OUTPUT ;
    USE SIGNAL ;
    PORT
      LAYER M4 ;
        RECT  155.436 92.4 155.52 92.424 ;
    END
  END o_v[1]
  PIN o_v[2]
    DIRECTION OUTPUT ;
    USE SIGNAL ;
    PORT
      LAYER M4 ;
        RECT  155.436 92.832 155.52 92.856 ;
    END
  END o_v[2]
  PIN o_v[3]
    DIRECTION OUTPUT ;
    USE SIGNAL ;
    PORT
      LAYER M4 ;
        RECT  155.436 93.264 155.52 93.288 ;
    END
  END o_v[3]
  PIN o_v[4]
    DIRECTION OUTPUT ;
    USE SIGNAL ;
    PORT
      LAYER M4 ;
        RECT  155.436 93.696 155.52 93.72 ;
    END
  END o_v[4]
  PIN o_v[5]
    DIRECTION OUTPUT ;
    USE SIGNAL ;
    PORT
      LAYER M4 ;
        RECT  155.436 94.128 155.52 94.152 ;
    END
  END o_v[5]
  PIN o_v[6]
    DIRECTION OUTPUT ;
    USE SIGNAL ;
    PORT
      LAYER M4 ;
        RECT  155.436 94.56 155.52 94.584 ;
    END
  END o_v[6]
  PIN o_v[7]
    DIRECTION OUTPUT ;
    USE SIGNAL ;
    PORT
      LAYER M4 ;
        RECT  155.436 94.992 155.52 95.016 ;
    END
  END o_v[7]
  PIN rst_n
    DIRECTION INPUT ;
    USE SIGNAL ;
    PORT
      LAYER M5 ;
        RECT  77.952 246.156 77.976 246.24 ;
    END
  END rst_n
  PIN VDD
    DIRECTION INOUT ;
    USE POWER ;
    PORT
      LAYER M5 ;
        RECT  148.392 2.151 148.512 244.089 ;
        RECT  142.992 2.151 143.112 244.089 ;
        RECT  137.592 2.151 137.712 244.089 ;
        RECT  132.192 2.151 132.312 244.089 ;
        RECT  126.792 2.151 126.912 244.089 ;
        RECT  121.392 2.151 121.512 244.089 ;
        RECT  115.992 2.151 116.112 244.089 ;
        RECT  110.592 2.151 110.712 244.089 ;
        RECT  105.192 2.151 105.312 244.089 ;
        RECT  99.792 2.151 99.912 244.089 ;
        RECT  94.392 2.151 94.512 244.089 ;
        RECT  88.992 2.151 89.112 244.089 ;
        RECT  83.592 2.151 83.712 244.089 ;
        RECT  78.192 2.151 78.312 244.089 ;
        RECT  72.792 2.151 72.912 244.089 ;
        RECT  67.392 2.151 67.512 244.089 ;
        RECT  61.992 2.151 62.112 244.089 ;
        RECT  56.592 2.151 56.712 244.089 ;
        RECT  51.192 2.151 51.312 244.089 ;
        RECT  45.792 2.151 45.912 244.089 ;
        RECT  40.392 2.151 40.512 244.089 ;
        RECT  34.992 2.151 35.112 244.089 ;
        RECT  29.592 2.151 29.712 244.089 ;
        RECT  24.192 2.151 24.312 244.089 ;
        RECT  18.792 2.151 18.912 244.089 ;
        RECT  13.392 2.151 13.512 244.089 ;
        RECT  7.992 2.151 8.112 244.089 ;
        RECT  2.592 2.151 2.712 244.089 ;
    END
  END VDD
  PIN VSS
    DIRECTION INOUT ;
    USE GROUND ;
    PORT
      LAYER M5 ;
        RECT  148.2 2.137 148.32 244.103 ;
        RECT  142.8 2.137 142.92 244.103 ;
        RECT  137.4 2.137 137.52 244.103 ;
        RECT  132 2.137 132.12 244.103 ;
        RECT  126.6 2.137 126.72 244.103 ;
        RECT  121.2 2.137 121.32 244.103 ;
        RECT  115.8 2.137 115.92 244.103 ;
        RECT  110.4 2.137 110.52 244.103 ;
        RECT  105 2.137 105.12 244.103 ;
        RECT  99.6 2.137 99.72 244.103 ;
        RECT  94.2 2.137 94.32 244.103 ;
        RECT  88.8 2.137 88.92 244.103 ;
        RECT  83.4 2.137 83.52 244.103 ;
        RECT  78 2.137 78.12 244.103 ;
        RECT  72.6 2.137 72.72 244.103 ;
        RECT  67.2 2.137 67.32 244.103 ;
        RECT  61.8 2.137 61.92 244.103 ;
        RECT  56.4 2.137 56.52 244.103 ;
        RECT  51 2.137 51.12 244.103 ;
        RECT  45.6 2.137 45.72 244.103 ;
        RECT  40.2 2.137 40.32 244.103 ;
        RECT  34.8 2.137 34.92 244.103 ;
        RECT  29.4 2.137 29.52 244.103 ;
        RECT  24 2.137 24.12 244.103 ;
        RECT  18.6 2.137 18.72 244.103 ;
        RECT  13.2 2.137 13.32 244.103 ;
        RECT  7.8 2.137 7.92 244.103 ;
        RECT  2.4 2.137 2.52 244.103 ;
    END
  END VSS
  # OT_OBS_CLOSED layer=M5 d_um=1.536 added=116
  OBS
    LAYER RVTN ;
     RECT  2.16 2.16 153.36 2.295 ;
     RECT  2.16 2.565 153.36 2.835 ;
     RECT  2.16 3.105 153.36 3.375 ;
     RECT  2.16 3.645 153.36 3.915 ;
     RECT  2.16 4.185 153.36 4.455 ;
     RECT  2.16 4.725 153.36 4.995 ;
     RECT  2.16 5.265 153.36 5.535 ;
     RECT  2.16 5.805 153.36 6.075 ;
     RECT  2.16 6.345 153.36 6.615 ;
     RECT  2.16 6.885 153.36 7.155 ;
     RECT  2.16 7.425 153.36 7.695 ;
     RECT  2.16 7.965 153.36 8.235 ;
     RECT  2.16 8.505 153.36 8.775 ;
     RECT  2.16 9.045 153.36 9.315 ;
     RECT  2.16 9.585 153.36 9.855 ;
     RECT  2.16 10.125 153.36 10.395 ;
     RECT  2.16 10.665 153.36 10.935 ;
     RECT  2.16 11.205 153.36 11.475 ;
     RECT  2.16 11.745 153.36 12.015 ;
     RECT  2.16 12.285 153.36 12.555 ;
     RECT  2.16 12.825 153.36 13.095 ;
     RECT  2.16 13.365 153.36 13.635 ;
     RECT  2.16 13.905 153.36 14.175 ;
     RECT  2.16 14.445 153.36 14.715 ;
     RECT  2.16 14.985 153.36 15.255 ;
     RECT  2.16 15.525 153.36 15.795 ;
     RECT  2.16 16.065 153.36 16.335 ;
     RECT  2.16 16.605 153.36 16.875 ;
     RECT  2.16 17.145 153.36 17.415 ;
     RECT  2.16 17.685 153.36 17.955 ;
     RECT  2.16 18.225 153.36 18.495 ;
     RECT  2.16 18.765 153.36 19.035 ;
     RECT  2.16 19.305 153.36 19.575 ;
     RECT  2.16 19.845 153.36 20.115 ;
     RECT  2.16 20.385 153.36 20.655 ;
     RECT  2.16 20.925 153.36 21.195 ;
     RECT  2.16 21.465 153.36 21.735 ;
     RECT  2.16 22.005 153.36 22.275 ;
     RECT  2.16 22.545 153.36 22.815 ;
     RECT  2.16 23.085 153.36 23.355 ;
     RECT  2.16 23.625 153.36 23.895 ;
     RECT  2.16 24.165 153.36 24.435 ;
     RECT  2.16 24.705 153.36 24.975 ;
     RECT  2.16 25.245 153.36 25.515 ;
     RECT  2.16 25.785 153.36 26.055 ;
     RECT  2.16 26.325 153.36 26.595 ;
     RECT  2.16 26.865 153.36 27.135 ;
     RECT  2.16 27.405 153.36 27.675 ;
     RECT  2.16 27.945 153.36 28.215 ;
     RECT  2.16 28.485 153.36 28.755 ;
     RECT  2.16 29.025 153.36 29.295 ;
     RECT  2.16 29.565 153.36 29.835 ;
     RECT  2.16 30.105 153.36 30.375 ;
     RECT  2.16 30.645 153.36 30.915 ;
     RECT  2.16 31.185 153.36 31.455 ;
     RECT  2.16 31.725 153.36 31.995 ;
     RECT  2.16 32.265 153.36 32.535 ;
     RECT  2.16 32.805 153.36 33.075 ;
     RECT  2.16 33.345 153.36 33.615 ;
     RECT  2.16 33.885 153.36 34.155 ;
     RECT  2.16 34.425 153.36 34.695 ;
     RECT  2.16 34.965 153.36 35.235 ;
     RECT  2.16 35.505 153.36 35.775 ;
     RECT  2.16 36.045 153.36 36.315 ;
     RECT  2.16 36.585 153.36 36.855 ;
     RECT  2.16 37.125 153.36 37.395 ;
     RECT  2.16 37.665 153.36 37.935 ;
     RECT  2.16 38.205 153.36 38.475 ;
     RECT  2.16 38.745 153.36 39.015 ;
     RECT  2.16 39.285 153.36 39.555 ;
     RECT  2.16 39.825 153.36 40.095 ;
     RECT  2.16 40.365 153.36 40.635 ;
     RECT  2.16 40.905 153.36 41.175 ;
     RECT  2.16 41.445 153.36 41.715 ;
     RECT  2.16 41.985 153.36 42.255 ;
     RECT  2.16 42.525 153.36 42.795 ;
     RECT  2.16 43.065 153.36 43.335 ;
     RECT  2.16 43.605 153.36 43.875 ;
     RECT  2.16 44.145 153.36 44.415 ;
     RECT  2.16 44.685 153.36 44.955 ;
     RECT  2.16 45.225 153.36 45.495 ;
     RECT  2.16 45.765 153.36 46.035 ;
     RECT  2.16 46.305 153.36 46.575 ;
     RECT  2.16 46.845 153.36 47.115 ;
     RECT  2.16 47.385 153.36 47.655 ;
     RECT  2.16 47.925 153.36 48.195 ;
     RECT  2.16 48.465 153.36 48.735 ;
     RECT  2.16 49.005 153.36 49.275 ;
     RECT  2.16 49.545 153.36 49.815 ;
     RECT  2.16 50.085 153.36 50.355 ;
     RECT  2.16 50.625 153.36 50.895 ;
     RECT  2.16 51.165 153.36 51.435 ;
     RECT  2.16 51.705 153.36 51.975 ;
     RECT  2.16 52.245 153.36 52.515 ;
     RECT  2.16 52.785 153.36 53.055 ;
     RECT  2.16 53.325 153.36 53.595 ;
     RECT  2.16 53.865 153.36 54.135 ;
     RECT  2.16 54.405 153.36 54.675 ;
     RECT  2.16 54.945 153.36 55.215 ;
     RECT  2.16 55.485 153.36 55.755 ;
     RECT  2.16 56.025 153.36 56.295 ;
     RECT  2.16 56.565 153.36 56.835 ;
     RECT  2.16 57.105 153.36 57.375 ;
     RECT  2.16 57.645 153.36 57.915 ;
     RECT  2.16 58.185 153.36 58.455 ;
     RECT  2.16 58.725 153.36 58.995 ;
     RECT  2.16 59.265 153.36 59.535 ;
     RECT  2.16 59.805 153.36 60.075 ;
     RECT  2.16 60.345 153.36 60.615 ;
     RECT  2.16 60.885 153.36 61.155 ;
     RECT  2.16 61.425 153.36 61.695 ;
     RECT  2.16 61.965 153.36 62.235 ;
     RECT  2.16 62.505 153.36 62.775 ;
     RECT  2.16 63.045 153.36 63.315 ;
     RECT  2.16 63.585 153.36 63.855 ;
     RECT  2.16 64.125 153.36 64.395 ;
     RECT  2.16 64.665 153.36 64.935 ;
     RECT  2.16 65.205 153.36 65.475 ;
     RECT  2.16 65.745 153.36 66.015 ;
     RECT  2.16 66.285 153.36 66.555 ;
     RECT  2.16 66.825 153.36 67.095 ;
     RECT  2.16 67.365 153.36 67.635 ;
     RECT  2.16 67.905 153.36 68.175 ;
     RECT  2.16 68.445 153.36 68.715 ;
     RECT  2.16 68.985 153.36 69.255 ;
     RECT  2.16 69.525 153.36 69.795 ;
     RECT  2.16 70.065 153.36 70.335 ;
     RECT  2.16 70.605 153.36 70.875 ;
     RECT  2.16 71.145 153.36 71.415 ;
     RECT  2.16 71.685 153.36 71.955 ;
     RECT  2.16 72.225 153.36 72.495 ;
     RECT  2.16 72.765 153.36 73.035 ;
     RECT  2.16 73.305 153.36 73.575 ;
     RECT  2.16 73.845 153.36 74.115 ;
     RECT  2.16 74.385 153.36 74.655 ;
     RECT  2.16 74.925 153.36 75.195 ;
     RECT  2.16 75.465 153.36 75.735 ;
     RECT  2.16 76.005 153.36 76.275 ;
     RECT  2.16 76.545 153.36 76.815 ;
     RECT  2.16 77.085 153.36 77.355 ;
     RECT  2.16 77.625 153.36 77.895 ;
     RECT  2.16 78.165 153.36 78.435 ;
     RECT  2.16 78.705 153.36 78.975 ;
     RECT  2.16 79.245 153.36 79.515 ;
     RECT  2.16 79.785 153.36 80.055 ;
     RECT  2.16 80.325 153.36 80.595 ;
     RECT  2.16 80.865 153.36 81.135 ;
     RECT  2.16 81.405 153.36 81.675 ;
     RECT  2.16 81.945 153.36 82.215 ;
     RECT  2.16 82.485 153.36 82.755 ;
     RECT  2.16 83.025 153.36 83.295 ;
     RECT  2.16 83.565 153.36 83.835 ;
     RECT  2.16 84.105 153.36 84.375 ;
     RECT  2.16 84.645 153.36 84.915 ;
     RECT  2.16 85.185 153.36 85.455 ;
     RECT  2.16 85.725 153.36 85.995 ;
     RECT  2.16 86.265 153.36 86.535 ;
     RECT  2.16 86.805 153.36 87.075 ;
     RECT  2.16 87.345 153.36 87.615 ;
     RECT  2.16 87.885 153.36 88.155 ;
     RECT  2.16 88.425 153.36 88.695 ;
     RECT  2.16 88.965 153.36 89.235 ;
     RECT  2.16 89.505 153.36 89.775 ;
     RECT  2.16 90.045 153.36 90.315 ;
     RECT  2.16 90.585 153.36 90.855 ;
     RECT  2.16 91.125 153.36 91.395 ;
     RECT  2.16 91.665 153.36 91.935 ;
     RECT  2.16 92.205 153.36 92.475 ;
     RECT  2.16 92.745 153.36 93.015 ;
     RECT  2.16 93.285 153.36 93.555 ;
     RECT  2.16 93.825 153.36 94.095 ;
     RECT  2.16 94.365 153.36 94.635 ;
     RECT  2.16 94.905 153.36 95.175 ;
     RECT  2.16 95.445 153.36 95.715 ;
     RECT  2.16 95.985 153.36 96.255 ;
     RECT  2.16 96.525 153.36 96.795 ;
     RECT  2.16 97.065 153.36 97.335 ;
     RECT  2.16 97.605 153.36 97.875 ;
     RECT  2.16 98.145 153.36 98.415 ;
     RECT  2.16 98.685 153.36 98.955 ;
     RECT  2.16 99.225 153.36 99.495 ;
     RECT  2.16 99.765 153.36 100.035 ;
     RECT  2.16 100.305 153.36 100.575 ;
     RECT  2.16 100.845 153.36 101.115 ;
     RECT  2.16 101.385 153.36 101.655 ;
     RECT  2.16 101.925 153.36 102.195 ;
     RECT  2.16 102.465 153.36 102.735 ;
     RECT  2.16 103.005 153.36 103.275 ;
     RECT  2.16 103.545 153.36 103.815 ;
     RECT  2.16 104.085 153.36 104.355 ;
     RECT  2.16 104.625 153.36 104.895 ;
     RECT  2.16 105.165 153.36 105.435 ;
     RECT  2.16 105.705 153.36 105.975 ;
     RECT  2.16 106.245 153.36 106.515 ;
     RECT  2.16 106.785 153.36 107.055 ;
     RECT  2.16 107.325 153.36 107.595 ;
     RECT  2.16 107.865 153.36 108.135 ;
     RECT  2.16 108.405 153.36 108.675 ;
     RECT  2.16 108.945 153.36 109.215 ;
     RECT  2.16 109.485 153.36 109.755 ;
     RECT  2.16 110.025 153.36 110.295 ;
     RECT  2.16 110.565 153.36 110.835 ;
     RECT  2.16 111.105 153.36 111.375 ;
     RECT  2.16 111.645 153.36 111.915 ;
     RECT  2.16 112.185 153.36 112.455 ;
     RECT  2.16 112.725 153.36 112.995 ;
     RECT  2.16 113.265 153.36 113.535 ;
     RECT  2.16 113.805 153.36 114.075 ;
     RECT  2.16 114.345 153.36 114.615 ;
     RECT  2.16 114.885 153.36 115.155 ;
     RECT  2.16 115.425 153.36 115.695 ;
     RECT  2.16 115.965 153.36 116.235 ;
     RECT  2.16 116.505 153.36 116.775 ;
     RECT  2.16 117.045 153.36 117.315 ;
     RECT  2.16 117.585 153.36 117.855 ;
     RECT  2.16 118.125 153.36 118.395 ;
     RECT  2.16 118.665 153.36 118.935 ;
     RECT  2.16 119.205 153.36 119.475 ;
     RECT  2.16 119.745 153.36 120.015 ;
     RECT  2.16 120.285 153.36 120.555 ;
     RECT  2.16 120.825 153.36 121.095 ;
     RECT  2.16 121.365 153.36 121.635 ;
     RECT  2.16 121.905 153.36 122.175 ;
     RECT  2.16 122.445 153.36 122.715 ;
     RECT  2.16 122.985 153.36 123.255 ;
     RECT  2.16 123.525 153.36 123.795 ;
     RECT  2.16 124.065 153.36 124.335 ;
     RECT  2.16 124.605 153.36 124.875 ;
     RECT  2.16 125.145 153.36 125.415 ;
     RECT  2.16 125.685 153.36 125.955 ;
     RECT  2.16 126.225 153.36 126.495 ;
     RECT  2.16 126.765 153.36 127.035 ;
     RECT  2.16 127.305 153.36 127.575 ;
     RECT  2.16 127.845 153.36 128.115 ;
     RECT  2.16 128.385 153.36 128.655 ;
     RECT  2.16 128.925 153.36 129.195 ;
     RECT  2.16 129.465 153.36 129.735 ;
     RECT  2.16 130.005 153.36 130.275 ;
     RECT  2.16 130.545 153.36 130.815 ;
     RECT  2.16 131.085 153.36 131.355 ;
     RECT  2.16 131.625 153.36 131.895 ;
     RECT  2.16 132.165 153.36 132.435 ;
     RECT  2.16 132.705 153.36 132.975 ;
     RECT  2.16 133.245 153.36 133.515 ;
     RECT  2.16 133.785 153.36 134.055 ;
     RECT  2.16 134.325 153.36 134.595 ;
     RECT  2.16 134.865 153.36 135.135 ;
     RECT  2.16 135.405 153.36 135.675 ;
     RECT  2.16 135.945 153.36 136.215 ;
     RECT  2.16 136.485 153.36 136.755 ;
     RECT  2.16 137.025 153.36 137.295 ;
     RECT  2.16 137.565 153.36 137.835 ;
     RECT  2.16 138.105 153.36 138.375 ;
     RECT  2.16 138.645 153.36 138.915 ;
     RECT  2.16 139.185 153.36 139.455 ;
     RECT  2.16 139.725 153.36 139.995 ;
     RECT  2.16 140.265 153.36 140.535 ;
     RECT  2.16 140.805 153.36 141.075 ;
     RECT  2.16 141.345 153.36 141.615 ;
     RECT  2.16 141.885 153.36 142.155 ;
     RECT  2.16 142.425 153.36 142.695 ;
     RECT  2.16 142.965 153.36 143.235 ;
     RECT  2.16 143.505 153.36 143.775 ;
     RECT  2.16 144.045 153.36 144.315 ;
     RECT  2.16 144.585 153.36 144.855 ;
     RECT  2.16 145.125 153.36 145.395 ;
     RECT  2.16 145.665 153.36 145.935 ;
     RECT  2.16 146.205 153.36 146.475 ;
     RECT  2.16 146.745 153.36 147.015 ;
     RECT  2.16 147.285 153.36 147.555 ;
     RECT  2.16 147.825 153.36 148.095 ;
     RECT  2.16 148.365 153.36 148.635 ;
     RECT  2.16 148.905 153.36 149.175 ;
     RECT  2.16 149.445 153.36 149.715 ;
     RECT  2.16 149.985 153.36 150.255 ;
     RECT  2.16 150.525 153.36 150.795 ;
     RECT  2.16 151.065 153.36 151.335 ;
     RECT  2.16 151.605 153.36 151.875 ;
     RECT  2.16 152.145 153.36 152.415 ;
     RECT  2.16 152.685 153.36 152.955 ;
     RECT  2.16 153.225 153.36 153.495 ;
     RECT  2.16 153.765 153.36 154.035 ;
     RECT  2.16 154.305 153.36 154.575 ;
     RECT  2.16 154.845 153.36 155.115 ;
     RECT  2.16 155.385 153.36 155.655 ;
     RECT  2.16 155.925 153.36 156.195 ;
     RECT  2.16 156.465 153.36 156.735 ;
     RECT  2.16 157.005 153.36 157.275 ;
     RECT  2.16 157.545 153.36 157.815 ;
     RECT  2.16 158.085 153.36 158.355 ;
     RECT  2.16 158.625 153.36 158.895 ;
     RECT  2.16 159.165 153.36 159.435 ;
     RECT  2.16 159.705 153.36 159.975 ;
     RECT  2.16 160.245 153.36 160.515 ;
     RECT  2.16 160.785 153.36 161.055 ;
     RECT  2.16 161.325 153.36 161.595 ;
     RECT  2.16 161.865 153.36 162.135 ;
     RECT  2.16 162.405 153.36 162.675 ;
     RECT  2.16 162.945 153.36 163.215 ;
     RECT  2.16 163.485 153.36 163.755 ;
     RECT  2.16 164.025 153.36 164.295 ;
     RECT  2.16 164.565 153.36 164.835 ;
     RECT  2.16 165.105 153.36 165.375 ;
     RECT  2.16 165.645 153.36 165.915 ;
     RECT  2.16 166.185 153.36 166.455 ;
     RECT  2.16 166.725 153.36 166.995 ;
     RECT  2.16 167.265 153.36 167.535 ;
     RECT  2.16 167.805 153.36 168.075 ;
     RECT  2.16 168.345 153.36 168.615 ;
     RECT  2.16 168.885 153.36 169.155 ;
     RECT  2.16 169.425 153.36 169.695 ;
     RECT  2.16 169.965 153.36 170.235 ;
     RECT  2.16 170.505 153.36 170.775 ;
     RECT  2.16 171.045 153.36 171.315 ;
     RECT  2.16 171.585 153.36 171.855 ;
     RECT  2.16 172.125 153.36 172.395 ;
     RECT  2.16 172.665 153.36 172.935 ;
     RECT  2.16 173.205 153.36 173.475 ;
     RECT  2.16 173.745 153.36 174.015 ;
     RECT  2.16 174.285 153.36 174.555 ;
     RECT  2.16 174.825 153.36 175.095 ;
     RECT  2.16 175.365 153.36 175.635 ;
     RECT  2.16 175.905 153.36 176.175 ;
     RECT  2.16 176.445 153.36 176.715 ;
     RECT  2.16 176.985 153.36 177.255 ;
     RECT  2.16 177.525 153.36 177.795 ;
     RECT  2.16 178.065 153.36 178.335 ;
     RECT  2.16 178.605 153.36 178.875 ;
     RECT  2.16 179.145 153.36 179.415 ;
     RECT  2.16 179.685 153.36 179.955 ;
     RECT  2.16 180.225 153.36 180.495 ;
     RECT  2.16 180.765 153.36 181.035 ;
     RECT  2.16 181.305 153.36 181.575 ;
     RECT  2.16 181.845 153.36 182.115 ;
     RECT  2.16 182.385 153.36 182.655 ;
     RECT  2.16 182.925 153.36 183.195 ;
     RECT  2.16 183.465 153.36 183.735 ;
     RECT  2.16 184.005 153.36 184.275 ;
     RECT  2.16 184.545 153.36 184.815 ;
     RECT  2.16 185.085 153.36 185.355 ;
     RECT  2.16 185.625 153.36 185.895 ;
     RECT  2.16 186.165 153.36 186.435 ;
     RECT  2.16 186.705 153.36 186.975 ;
     RECT  2.16 187.245 153.36 187.515 ;
     RECT  2.16 187.785 153.36 188.055 ;
     RECT  2.16 188.325 153.36 188.595 ;
     RECT  2.16 188.865 153.36 189.135 ;
     RECT  2.16 189.405 153.36 189.675 ;
     RECT  2.16 189.945 153.36 190.215 ;
     RECT  2.16 190.485 153.36 190.755 ;
     RECT  2.16 191.025 153.36 191.295 ;
     RECT  2.16 191.565 153.36 191.835 ;
     RECT  2.16 192.105 153.36 192.375 ;
     RECT  2.16 192.645 153.36 192.915 ;
     RECT  2.16 193.185 153.36 193.455 ;
     RECT  2.16 193.725 153.36 193.995 ;
     RECT  2.16 194.265 153.36 194.535 ;
     RECT  2.16 194.805 153.36 195.075 ;
     RECT  2.16 195.345 153.36 195.615 ;
     RECT  2.16 195.885 153.36 196.155 ;
     RECT  2.16 196.425 153.36 196.695 ;
     RECT  2.16 196.965 153.36 197.235 ;
     RECT  2.16 197.505 153.36 197.775 ;
     RECT  2.16 198.045 153.36 198.315 ;
     RECT  2.16 198.585 153.36 198.855 ;
     RECT  2.16 199.125 153.36 199.395 ;
     RECT  2.16 199.665 153.36 199.935 ;
     RECT  2.16 200.205 153.36 200.475 ;
     RECT  2.16 200.745 153.36 201.015 ;
     RECT  2.16 201.285 153.36 201.555 ;
     RECT  2.16 201.825 153.36 202.095 ;
     RECT  2.16 202.365 153.36 202.635 ;
     RECT  2.16 202.905 153.36 203.175 ;
     RECT  2.16 203.445 153.36 203.715 ;
     RECT  2.16 203.985 153.36 204.255 ;
     RECT  2.16 204.525 153.36 204.795 ;
     RECT  2.16 205.065 153.36 205.335 ;
     RECT  2.16 205.605 153.36 205.875 ;
     RECT  2.16 206.145 153.36 206.415 ;
     RECT  2.16 206.685 153.36 206.955 ;
     RECT  2.16 207.225 153.36 207.495 ;
     RECT  2.16 207.765 153.36 208.035 ;
     RECT  2.16 208.305 153.36 208.575 ;
     RECT  2.16 208.845 153.36 209.115 ;
     RECT  2.16 209.385 153.36 209.655 ;
     RECT  2.16 209.925 153.36 210.195 ;
     RECT  2.16 210.465 153.36 210.735 ;
     RECT  2.16 211.005 153.36 211.275 ;
     RECT  2.16 211.545 153.36 211.815 ;
     RECT  2.16 212.085 153.36 212.355 ;
     RECT  2.16 212.625 153.36 212.895 ;
     RECT  2.16 213.165 153.36 213.435 ;
     RECT  2.16 213.705 153.36 213.975 ;
     RECT  2.16 214.245 153.36 214.515 ;
     RECT  2.16 214.785 153.36 215.055 ;
     RECT  2.16 215.325 153.36 215.595 ;
     RECT  2.16 215.865 153.36 216.135 ;
     RECT  2.16 216.405 153.36 216.675 ;
     RECT  2.16 216.945 153.36 217.215 ;
     RECT  2.16 217.485 153.36 217.755 ;
     RECT  2.16 218.025 153.36 218.295 ;
     RECT  2.16 218.565 153.36 218.835 ;
     RECT  2.16 219.105 153.36 219.375 ;
     RECT  2.16 219.645 153.36 219.915 ;
     RECT  2.16 220.185 153.36 220.455 ;
     RECT  2.16 220.725 153.36 220.995 ;
     RECT  2.16 221.265 153.36 221.535 ;
     RECT  2.16 221.805 153.36 222.075 ;
     RECT  2.16 222.345 153.36 222.615 ;
     RECT  2.16 222.885 153.36 223.155 ;
     RECT  2.16 223.425 153.36 223.695 ;
     RECT  2.16 223.965 153.36 224.235 ;
     RECT  2.16 224.505 153.36 224.775 ;
     RECT  2.16 225.045 153.36 225.315 ;
     RECT  2.16 225.585 153.36 225.855 ;
     RECT  2.16 226.125 153.36 226.395 ;
     RECT  2.16 226.665 153.36 226.935 ;
     RECT  2.16 227.205 153.36 227.475 ;
     RECT  2.16 227.745 153.36 228.015 ;
     RECT  2.16 228.285 153.36 228.555 ;
     RECT  2.16 228.825 153.36 229.095 ;
     RECT  2.16 229.365 153.36 229.635 ;
     RECT  2.16 229.905 153.36 230.175 ;
     RECT  2.16 230.445 153.36 230.715 ;
     RECT  2.16 230.985 153.36 231.255 ;
     RECT  2.16 231.525 153.36 231.795 ;
     RECT  2.16 232.065 153.36 232.335 ;
     RECT  2.16 232.605 153.36 232.875 ;
     RECT  2.16 233.145 153.36 233.415 ;
     RECT  2.16 233.685 153.36 233.955 ;
     RECT  2.16 234.225 153.36 234.495 ;
     RECT  2.16 234.765 153.36 235.035 ;
     RECT  2.16 235.305 153.36 235.575 ;
     RECT  2.16 235.845 153.36 236.115 ;
     RECT  2.16 236.385 153.36 236.655 ;
     RECT  2.16 236.925 153.36 237.195 ;
     RECT  2.16 237.465 153.36 237.735 ;
     RECT  2.16 238.005 153.36 238.275 ;
     RECT  2.16 238.545 153.36 238.815 ;
     RECT  2.16 239.085 153.36 239.355 ;
     RECT  2.16 239.625 153.36 239.895 ;
     RECT  2.16 240.165 153.36 240.435 ;
     RECT  2.16 240.705 153.36 240.975 ;
     RECT  2.16 241.245 153.36 241.515 ;
     RECT  2.16 241.785 153.36 242.055 ;
     RECT  2.16 242.325 153.36 242.595 ;
     RECT  2.16 242.865 153.36 243.135 ;
     RECT  2.16 243.405 153.36 243.675 ;
     RECT  2.16 243.945 153.36 244.08 ;
    LAYER RVTP ;
     RECT  2.16 2.295 153.36 2.565 ;
     RECT  2.16 2.835 153.36 3.105 ;
     RECT  2.16 3.375 153.36 3.645 ;
     RECT  2.16 3.915 153.36 4.185 ;
     RECT  2.16 4.455 153.36 4.725 ;
     RECT  2.16 4.995 153.36 5.265 ;
     RECT  2.16 5.535 153.36 5.805 ;
     RECT  2.16 6.075 153.36 6.345 ;
     RECT  2.16 6.615 153.36 6.885 ;
     RECT  2.16 7.155 153.36 7.425 ;
     RECT  2.16 7.695 153.36 7.965 ;
     RECT  2.16 8.235 153.36 8.505 ;
     RECT  2.16 8.775 153.36 9.045 ;
     RECT  2.16 9.315 153.36 9.585 ;
     RECT  2.16 9.855 153.36 10.125 ;
     RECT  2.16 10.395 153.36 10.665 ;
     RECT  2.16 10.935 153.36 11.205 ;
     RECT  2.16 11.475 153.36 11.745 ;
     RECT  2.16 12.015 153.36 12.285 ;
     RECT  2.16 12.555 153.36 12.825 ;
     RECT  2.16 13.095 153.36 13.365 ;
     RECT  2.16 13.635 153.36 13.905 ;
     RECT  2.16 14.175 153.36 14.445 ;
     RECT  2.16 14.715 153.36 14.985 ;
     RECT  2.16 15.255 153.36 15.525 ;
     RECT  2.16 15.795 153.36 16.065 ;
     RECT  2.16 16.335 153.36 16.605 ;
     RECT  2.16 16.875 153.36 17.145 ;
     RECT  2.16 17.415 153.36 17.685 ;
     RECT  2.16 17.955 153.36 18.225 ;
     RECT  2.16 18.495 153.36 18.765 ;
     RECT  2.16 19.035 153.36 19.305 ;
     RECT  2.16 19.575 153.36 19.845 ;
     RECT  2.16 20.115 153.36 20.385 ;
     RECT  2.16 20.655 153.36 20.925 ;
     RECT  2.16 21.195 153.36 21.465 ;
     RECT  2.16 21.735 153.36 22.005 ;
     RECT  2.16 22.275 153.36 22.545 ;
     RECT  2.16 22.815 153.36 23.085 ;
     RECT  2.16 23.355 153.36 23.625 ;
     RECT  2.16 23.895 153.36 24.165 ;
     RECT  2.16 24.435 153.36 24.705 ;
     RECT  2.16 24.975 153.36 25.245 ;
     RECT  2.16 25.515 153.36 25.785 ;
     RECT  2.16 26.055 153.36 26.325 ;
     RECT  2.16 26.595 153.36 26.865 ;
     RECT  2.16 27.135 153.36 27.405 ;
     RECT  2.16 27.675 153.36 27.945 ;
     RECT  2.16 28.215 153.36 28.485 ;
     RECT  2.16 28.755 153.36 29.025 ;
     RECT  2.16 29.295 153.36 29.565 ;
     RECT  2.16 29.835 153.36 30.105 ;
     RECT  2.16 30.375 153.36 30.645 ;
     RECT  2.16 30.915 153.36 31.185 ;
     RECT  2.16 31.455 153.36 31.725 ;
     RECT  2.16 31.995 153.36 32.265 ;
     RECT  2.16 32.535 153.36 32.805 ;
     RECT  2.16 33.075 153.36 33.345 ;
     RECT  2.16 33.615 153.36 33.885 ;
     RECT  2.16 34.155 153.36 34.425 ;
     RECT  2.16 34.695 153.36 34.965 ;
     RECT  2.16 35.235 153.36 35.505 ;
     RECT  2.16 35.775 153.36 36.045 ;
     RECT  2.16 36.315 153.36 36.585 ;
     RECT  2.16 36.855 153.36 37.125 ;
     RECT  2.16 37.395 153.36 37.665 ;
     RECT  2.16 37.935 153.36 38.205 ;
     RECT  2.16 38.475 153.36 38.745 ;
     RECT  2.16 39.015 153.36 39.285 ;
     RECT  2.16 39.555 153.36 39.825 ;
     RECT  2.16 40.095 153.36 40.365 ;
     RECT  2.16 40.635 153.36 40.905 ;
     RECT  2.16 41.175 153.36 41.445 ;
     RECT  2.16 41.715 153.36 41.985 ;
     RECT  2.16 42.255 153.36 42.525 ;
     RECT  2.16 42.795 153.36 43.065 ;
     RECT  2.16 43.335 153.36 43.605 ;
     RECT  2.16 43.875 153.36 44.145 ;
     RECT  2.16 44.415 153.36 44.685 ;
     RECT  2.16 44.955 153.36 45.225 ;
     RECT  2.16 45.495 153.36 45.765 ;
     RECT  2.16 46.035 153.36 46.305 ;
     RECT  2.16 46.575 153.36 46.845 ;
     RECT  2.16 47.115 153.36 47.385 ;
     RECT  2.16 47.655 153.36 47.925 ;
     RECT  2.16 48.195 153.36 48.465 ;
     RECT  2.16 48.735 153.36 49.005 ;
     RECT  2.16 49.275 153.36 49.545 ;
     RECT  2.16 49.815 153.36 50.085 ;
     RECT  2.16 50.355 153.36 50.625 ;
     RECT  2.16 50.895 153.36 51.165 ;
     RECT  2.16 51.435 153.36 51.705 ;
     RECT  2.16 51.975 153.36 52.245 ;
     RECT  2.16 52.515 153.36 52.785 ;
     RECT  2.16 53.055 153.36 53.325 ;
     RECT  2.16 53.595 153.36 53.865 ;
     RECT  2.16 54.135 153.36 54.405 ;
     RECT  2.16 54.675 153.36 54.945 ;
     RECT  2.16 55.215 153.36 55.485 ;
     RECT  2.16 55.755 153.36 56.025 ;
     RECT  2.16 56.295 153.36 56.565 ;
     RECT  2.16 56.835 153.36 57.105 ;
     RECT  2.16 57.375 153.36 57.645 ;
     RECT  2.16 57.915 153.36 58.185 ;
     RECT  2.16 58.455 153.36 58.725 ;
     RECT  2.16 58.995 153.36 59.265 ;
     RECT  2.16 59.535 153.36 59.805 ;
     RECT  2.16 60.075 153.36 60.345 ;
     RECT  2.16 60.615 153.36 60.885 ;
     RECT  2.16 61.155 153.36 61.425 ;
     RECT  2.16 61.695 153.36 61.965 ;
     RECT  2.16 62.235 153.36 62.505 ;
     RECT  2.16 62.775 153.36 63.045 ;
     RECT  2.16 63.315 153.36 63.585 ;
     RECT  2.16 63.855 153.36 64.125 ;
     RECT  2.16 64.395 153.36 64.665 ;
     RECT  2.16 64.935 153.36 65.205 ;
     RECT  2.16 65.475 153.36 65.745 ;
     RECT  2.16 66.015 153.36 66.285 ;
     RECT  2.16 66.555 153.36 66.825 ;
     RECT  2.16 67.095 153.36 67.365 ;
     RECT  2.16 67.635 153.36 67.905 ;
     RECT  2.16 68.175 153.36 68.445 ;
     RECT  2.16 68.715 153.36 68.985 ;
     RECT  2.16 69.255 153.36 69.525 ;
     RECT  2.16 69.795 153.36 70.065 ;
     RECT  2.16 70.335 153.36 70.605 ;
     RECT  2.16 70.875 153.36 71.145 ;
     RECT  2.16 71.415 153.36 71.685 ;
     RECT  2.16 71.955 153.36 72.225 ;
     RECT  2.16 72.495 153.36 72.765 ;
     RECT  2.16 73.035 153.36 73.305 ;
     RECT  2.16 73.575 153.36 73.845 ;
     RECT  2.16 74.115 153.36 74.385 ;
     RECT  2.16 74.655 153.36 74.925 ;
     RECT  2.16 75.195 153.36 75.465 ;
     RECT  2.16 75.735 153.36 76.005 ;
     RECT  2.16 76.275 153.36 76.545 ;
     RECT  2.16 76.815 153.36 77.085 ;
     RECT  2.16 77.355 153.36 77.625 ;
     RECT  2.16 77.895 153.36 78.165 ;
     RECT  2.16 78.435 153.36 78.705 ;
     RECT  2.16 78.975 153.36 79.245 ;
     RECT  2.16 79.515 153.36 79.785 ;
     RECT  2.16 80.055 153.36 80.325 ;
     RECT  2.16 80.595 153.36 80.865 ;
     RECT  2.16 81.135 153.36 81.405 ;
     RECT  2.16 81.675 153.36 81.945 ;
     RECT  2.16 82.215 153.36 82.485 ;
     RECT  2.16 82.755 153.36 83.025 ;
     RECT  2.16 83.295 153.36 83.565 ;
     RECT  2.16 83.835 153.36 84.105 ;
     RECT  2.16 84.375 153.36 84.645 ;
     RECT  2.16 84.915 153.36 85.185 ;
     RECT  2.16 85.455 153.36 85.725 ;
     RECT  2.16 85.995 153.36 86.265 ;
     RECT  2.16 86.535 153.36 86.805 ;
     RECT  2.16 87.075 153.36 87.345 ;
     RECT  2.16 87.615 153.36 87.885 ;
     RECT  2.16 88.155 153.36 88.425 ;
     RECT  2.16 88.695 153.36 88.965 ;
     RECT  2.16 89.235 153.36 89.505 ;
     RECT  2.16 89.775 153.36 90.045 ;
     RECT  2.16 90.315 153.36 90.585 ;
     RECT  2.16 90.855 153.36 91.125 ;
     RECT  2.16 91.395 153.36 91.665 ;
     RECT  2.16 91.935 153.36 92.205 ;
     RECT  2.16 92.475 153.36 92.745 ;
     RECT  2.16 93.015 153.36 93.285 ;
     RECT  2.16 93.555 153.36 93.825 ;
     RECT  2.16 94.095 153.36 94.365 ;
     RECT  2.16 94.635 153.36 94.905 ;
     RECT  2.16 95.175 153.36 95.445 ;
     RECT  2.16 95.715 153.36 95.985 ;
     RECT  2.16 96.255 153.36 96.525 ;
     RECT  2.16 96.795 153.36 97.065 ;
     RECT  2.16 97.335 153.36 97.605 ;
     RECT  2.16 97.875 153.36 98.145 ;
     RECT  2.16 98.415 153.36 98.685 ;
     RECT  2.16 98.955 153.36 99.225 ;
     RECT  2.16 99.495 153.36 99.765 ;
     RECT  2.16 100.035 153.36 100.305 ;
     RECT  2.16 100.575 153.36 100.845 ;
     RECT  2.16 101.115 153.36 101.385 ;
     RECT  2.16 101.655 153.36 101.925 ;
     RECT  2.16 102.195 153.36 102.465 ;
     RECT  2.16 102.735 153.36 103.005 ;
     RECT  2.16 103.275 153.36 103.545 ;
     RECT  2.16 103.815 153.36 104.085 ;
     RECT  2.16 104.355 153.36 104.625 ;
     RECT  2.16 104.895 153.36 105.165 ;
     RECT  2.16 105.435 153.36 105.705 ;
     RECT  2.16 105.975 153.36 106.245 ;
     RECT  2.16 106.515 153.36 106.785 ;
     RECT  2.16 107.055 153.36 107.325 ;
     RECT  2.16 107.595 153.36 107.865 ;
     RECT  2.16 108.135 153.36 108.405 ;
     RECT  2.16 108.675 153.36 108.945 ;
     RECT  2.16 109.215 153.36 109.485 ;
     RECT  2.16 109.755 153.36 110.025 ;
     RECT  2.16 110.295 153.36 110.565 ;
     RECT  2.16 110.835 153.36 111.105 ;
     RECT  2.16 111.375 153.36 111.645 ;
     RECT  2.16 111.915 153.36 112.185 ;
     RECT  2.16 112.455 153.36 112.725 ;
     RECT  2.16 112.995 153.36 113.265 ;
     RECT  2.16 113.535 153.36 113.805 ;
     RECT  2.16 114.075 153.36 114.345 ;
     RECT  2.16 114.615 153.36 114.885 ;
     RECT  2.16 115.155 153.36 115.425 ;
     RECT  2.16 115.695 153.36 115.965 ;
     RECT  2.16 116.235 153.36 116.505 ;
     RECT  2.16 116.775 153.36 117.045 ;
     RECT  2.16 117.315 153.36 117.585 ;
     RECT  2.16 117.855 153.36 118.125 ;
     RECT  2.16 118.395 153.36 118.665 ;
     RECT  2.16 118.935 153.36 119.205 ;
     RECT  2.16 119.475 153.36 119.745 ;
     RECT  2.16 120.015 153.36 120.285 ;
     RECT  2.16 120.555 153.36 120.825 ;
     RECT  2.16 121.095 153.36 121.365 ;
     RECT  2.16 121.635 153.36 121.905 ;
     RECT  2.16 122.175 153.36 122.445 ;
     RECT  2.16 122.715 153.36 122.985 ;
     RECT  2.16 123.255 153.36 123.525 ;
     RECT  2.16 123.795 153.36 124.065 ;
     RECT  2.16 124.335 153.36 124.605 ;
     RECT  2.16 124.875 153.36 125.145 ;
     RECT  2.16 125.415 153.36 125.685 ;
     RECT  2.16 125.955 153.36 126.225 ;
     RECT  2.16 126.495 153.36 126.765 ;
     RECT  2.16 127.035 153.36 127.305 ;
     RECT  2.16 127.575 153.36 127.845 ;
     RECT  2.16 128.115 153.36 128.385 ;
     RECT  2.16 128.655 153.36 128.925 ;
     RECT  2.16 129.195 153.36 129.465 ;
     RECT  2.16 129.735 153.36 130.005 ;
     RECT  2.16 130.275 153.36 130.545 ;
     RECT  2.16 130.815 153.36 131.085 ;
     RECT  2.16 131.355 153.36 131.625 ;
     RECT  2.16 131.895 153.36 132.165 ;
     RECT  2.16 132.435 153.36 132.705 ;
     RECT  2.16 132.975 153.36 133.245 ;
     RECT  2.16 133.515 153.36 133.785 ;
     RECT  2.16 134.055 153.36 134.325 ;
     RECT  2.16 134.595 153.36 134.865 ;
     RECT  2.16 135.135 153.36 135.405 ;
     RECT  2.16 135.675 153.36 135.945 ;
     RECT  2.16 136.215 153.36 136.485 ;
     RECT  2.16 136.755 153.36 137.025 ;
     RECT  2.16 137.295 153.36 137.565 ;
     RECT  2.16 137.835 153.36 138.105 ;
     RECT  2.16 138.375 153.36 138.645 ;
     RECT  2.16 138.915 153.36 139.185 ;
     RECT  2.16 139.455 153.36 139.725 ;
     RECT  2.16 139.995 153.36 140.265 ;
     RECT  2.16 140.535 153.36 140.805 ;
     RECT  2.16 141.075 153.36 141.345 ;
     RECT  2.16 141.615 153.36 141.885 ;
     RECT  2.16 142.155 153.36 142.425 ;
     RECT  2.16 142.695 153.36 142.965 ;
     RECT  2.16 143.235 153.36 143.505 ;
     RECT  2.16 143.775 153.36 144.045 ;
     RECT  2.16 144.315 153.36 144.585 ;
     RECT  2.16 144.855 153.36 145.125 ;
     RECT  2.16 145.395 153.36 145.665 ;
     RECT  2.16 145.935 153.36 146.205 ;
     RECT  2.16 146.475 153.36 146.745 ;
     RECT  2.16 147.015 153.36 147.285 ;
     RECT  2.16 147.555 153.36 147.825 ;
     RECT  2.16 148.095 153.36 148.365 ;
     RECT  2.16 148.635 153.36 148.905 ;
     RECT  2.16 149.175 153.36 149.445 ;
     RECT  2.16 149.715 153.36 149.985 ;
     RECT  2.16 150.255 153.36 150.525 ;
     RECT  2.16 150.795 153.36 151.065 ;
     RECT  2.16 151.335 153.36 151.605 ;
     RECT  2.16 151.875 153.36 152.145 ;
     RECT  2.16 152.415 153.36 152.685 ;
     RECT  2.16 152.955 153.36 153.225 ;
     RECT  2.16 153.495 153.36 153.765 ;
     RECT  2.16 154.035 153.36 154.305 ;
     RECT  2.16 154.575 153.36 154.845 ;
     RECT  2.16 155.115 153.36 155.385 ;
     RECT  2.16 155.655 153.36 155.925 ;
     RECT  2.16 156.195 153.36 156.465 ;
     RECT  2.16 156.735 153.36 157.005 ;
     RECT  2.16 157.275 153.36 157.545 ;
     RECT  2.16 157.815 153.36 158.085 ;
     RECT  2.16 158.355 153.36 158.625 ;
     RECT  2.16 158.895 153.36 159.165 ;
     RECT  2.16 159.435 153.36 159.705 ;
     RECT  2.16 159.975 153.36 160.245 ;
     RECT  2.16 160.515 153.36 160.785 ;
     RECT  2.16 161.055 153.36 161.325 ;
     RECT  2.16 161.595 153.36 161.865 ;
     RECT  2.16 162.135 153.36 162.405 ;
     RECT  2.16 162.675 153.36 162.945 ;
     RECT  2.16 163.215 153.36 163.485 ;
     RECT  2.16 163.755 153.36 164.025 ;
     RECT  2.16 164.295 153.36 164.565 ;
     RECT  2.16 164.835 153.36 165.105 ;
     RECT  2.16 165.375 153.36 165.645 ;
     RECT  2.16 165.915 153.36 166.185 ;
     RECT  2.16 166.455 153.36 166.725 ;
     RECT  2.16 166.995 153.36 167.265 ;
     RECT  2.16 167.535 153.36 167.805 ;
     RECT  2.16 168.075 153.36 168.345 ;
     RECT  2.16 168.615 153.36 168.885 ;
     RECT  2.16 169.155 153.36 169.425 ;
     RECT  2.16 169.695 153.36 169.965 ;
     RECT  2.16 170.235 153.36 170.505 ;
     RECT  2.16 170.775 153.36 171.045 ;
     RECT  2.16 171.315 153.36 171.585 ;
     RECT  2.16 171.855 153.36 172.125 ;
     RECT  2.16 172.395 153.36 172.665 ;
     RECT  2.16 172.935 153.36 173.205 ;
     RECT  2.16 173.475 153.36 173.745 ;
     RECT  2.16 174.015 153.36 174.285 ;
     RECT  2.16 174.555 153.36 174.825 ;
     RECT  2.16 175.095 153.36 175.365 ;
     RECT  2.16 175.635 153.36 175.905 ;
     RECT  2.16 176.175 153.36 176.445 ;
     RECT  2.16 176.715 153.36 176.985 ;
     RECT  2.16 177.255 153.36 177.525 ;
     RECT  2.16 177.795 153.36 178.065 ;
     RECT  2.16 178.335 153.36 178.605 ;
     RECT  2.16 178.875 153.36 179.145 ;
     RECT  2.16 179.415 153.36 179.685 ;
     RECT  2.16 179.955 153.36 180.225 ;
     RECT  2.16 180.495 153.36 180.765 ;
     RECT  2.16 181.035 153.36 181.305 ;
     RECT  2.16 181.575 153.36 181.845 ;
     RECT  2.16 182.115 153.36 182.385 ;
     RECT  2.16 182.655 153.36 182.925 ;
     RECT  2.16 183.195 153.36 183.465 ;
     RECT  2.16 183.735 153.36 184.005 ;
     RECT  2.16 184.275 153.36 184.545 ;
     RECT  2.16 184.815 153.36 185.085 ;
     RECT  2.16 185.355 153.36 185.625 ;
     RECT  2.16 185.895 153.36 186.165 ;
     RECT  2.16 186.435 153.36 186.705 ;
     RECT  2.16 186.975 153.36 187.245 ;
     RECT  2.16 187.515 153.36 187.785 ;
     RECT  2.16 188.055 153.36 188.325 ;
     RECT  2.16 188.595 153.36 188.865 ;
     RECT  2.16 189.135 153.36 189.405 ;
     RECT  2.16 189.675 153.36 189.945 ;
     RECT  2.16 190.215 153.36 190.485 ;
     RECT  2.16 190.755 153.36 191.025 ;
     RECT  2.16 191.295 153.36 191.565 ;
     RECT  2.16 191.835 153.36 192.105 ;
     RECT  2.16 192.375 153.36 192.645 ;
     RECT  2.16 192.915 153.36 193.185 ;
     RECT  2.16 193.455 153.36 193.725 ;
     RECT  2.16 193.995 153.36 194.265 ;
     RECT  2.16 194.535 153.36 194.805 ;
     RECT  2.16 195.075 153.36 195.345 ;
     RECT  2.16 195.615 153.36 195.885 ;
     RECT  2.16 196.155 153.36 196.425 ;
     RECT  2.16 196.695 153.36 196.965 ;
     RECT  2.16 197.235 153.36 197.505 ;
     RECT  2.16 197.775 153.36 198.045 ;
     RECT  2.16 198.315 153.36 198.585 ;
     RECT  2.16 198.855 153.36 199.125 ;
     RECT  2.16 199.395 153.36 199.665 ;
     RECT  2.16 199.935 153.36 200.205 ;
     RECT  2.16 200.475 153.36 200.745 ;
     RECT  2.16 201.015 153.36 201.285 ;
     RECT  2.16 201.555 153.36 201.825 ;
     RECT  2.16 202.095 153.36 202.365 ;
     RECT  2.16 202.635 153.36 202.905 ;
     RECT  2.16 203.175 153.36 203.445 ;
     RECT  2.16 203.715 153.36 203.985 ;
     RECT  2.16 204.255 153.36 204.525 ;
     RECT  2.16 204.795 153.36 205.065 ;
     RECT  2.16 205.335 153.36 205.605 ;
     RECT  2.16 205.875 153.36 206.145 ;
     RECT  2.16 206.415 153.36 206.685 ;
     RECT  2.16 206.955 153.36 207.225 ;
     RECT  2.16 207.495 153.36 207.765 ;
     RECT  2.16 208.035 153.36 208.305 ;
     RECT  2.16 208.575 153.36 208.845 ;
     RECT  2.16 209.115 153.36 209.385 ;
     RECT  2.16 209.655 153.36 209.925 ;
     RECT  2.16 210.195 153.36 210.465 ;
     RECT  2.16 210.735 153.36 211.005 ;
     RECT  2.16 211.275 153.36 211.545 ;
     RECT  2.16 211.815 153.36 212.085 ;
     RECT  2.16 212.355 153.36 212.625 ;
     RECT  2.16 212.895 153.36 213.165 ;
     RECT  2.16 213.435 153.36 213.705 ;
     RECT  2.16 213.975 153.36 214.245 ;
     RECT  2.16 214.515 153.36 214.785 ;
     RECT  2.16 215.055 153.36 215.325 ;
     RECT  2.16 215.595 153.36 215.865 ;
     RECT  2.16 216.135 153.36 216.405 ;
     RECT  2.16 216.675 153.36 216.945 ;
     RECT  2.16 217.215 153.36 217.485 ;
     RECT  2.16 217.755 153.36 218.025 ;
     RECT  2.16 218.295 153.36 218.565 ;
     RECT  2.16 218.835 153.36 219.105 ;
     RECT  2.16 219.375 153.36 219.645 ;
     RECT  2.16 219.915 153.36 220.185 ;
     RECT  2.16 220.455 153.36 220.725 ;
     RECT  2.16 220.995 153.36 221.265 ;
     RECT  2.16 221.535 153.36 221.805 ;
     RECT  2.16 222.075 153.36 222.345 ;
     RECT  2.16 222.615 153.36 222.885 ;
     RECT  2.16 223.155 153.36 223.425 ;
     RECT  2.16 223.695 153.36 223.965 ;
     RECT  2.16 224.235 153.36 224.505 ;
     RECT  2.16 224.775 153.36 225.045 ;
     RECT  2.16 225.315 153.36 225.585 ;
     RECT  2.16 225.855 153.36 226.125 ;
     RECT  2.16 226.395 153.36 226.665 ;
     RECT  2.16 226.935 153.36 227.205 ;
     RECT  2.16 227.475 153.36 227.745 ;
     RECT  2.16 228.015 153.36 228.285 ;
     RECT  2.16 228.555 153.36 228.825 ;
     RECT  2.16 229.095 153.36 229.365 ;
     RECT  2.16 229.635 153.36 229.905 ;
     RECT  2.16 230.175 153.36 230.445 ;
     RECT  2.16 230.715 153.36 230.985 ;
     RECT  2.16 231.255 153.36 231.525 ;
     RECT  2.16 231.795 153.36 232.065 ;
     RECT  2.16 232.335 153.36 232.605 ;
     RECT  2.16 232.875 153.36 233.145 ;
     RECT  2.16 233.415 153.36 233.685 ;
     RECT  2.16 233.955 153.36 234.225 ;
     RECT  2.16 234.495 153.36 234.765 ;
     RECT  2.16 235.035 153.36 235.305 ;
     RECT  2.16 235.575 153.36 235.845 ;
     RECT  2.16 236.115 153.36 236.385 ;
     RECT  2.16 236.655 153.36 236.925 ;
     RECT  2.16 237.195 153.36 237.465 ;
     RECT  2.16 237.735 153.36 238.005 ;
     RECT  2.16 238.275 153.36 238.545 ;
     RECT  2.16 238.815 153.36 239.085 ;
     RECT  2.16 239.355 153.36 239.625 ;
     RECT  2.16 239.895 153.36 240.165 ;
     RECT  2.16 240.435 153.36 240.705 ;
     RECT  2.16 240.975 153.36 241.245 ;
     RECT  2.16 241.515 153.36 241.785 ;
     RECT  2.16 242.055 153.36 242.325 ;
     RECT  2.16 242.595 153.36 242.865 ;
     RECT  2.16 243.135 153.36 243.405 ;
     RECT  2.16 243.675 153.36 243.945 ;
    LAYER M1 ;
     RECT  2.16 2.151 153.36 244.089 ;
    LAYER M2 ;
     RECT  0.103 111.042 0.319 111.06 ;
     RECT  0.103 150.3 0.319 151.02 ;
     RECT  0.103 141.282 0.355 141.84 ;
     RECT  0.103 132.642 0.391 132.66 ;
     RECT  0.283 134.37 0.427 134.388 ;
     RECT  0.103 85.392 0.463 85.41 ;
     RECT  0.355 154.476 0.463 154.494 ;
     RECT  0.355 156.942 0.463 156.96 ;
     RECT  0.463 154.476 0.491 154.566 ;
     RECT  0.103 107.262 0.535 108.9 ;
     RECT  0.427 133.794 0.535 134.388 ;
     RECT  0.463 156.861 0.535 156.96 ;
     RECT  0.463 212.13 0.535 212.148 ;
     RECT  0.103 227.952 0.535 227.97 ;
     RECT  0.491 154.548 0.563 154.566 ;
     RECT  0.463 210.366 0.563 210.384 ;
     RECT  0.535 212.022 0.563 212.148 ;
     RECT  0.355 141.156 0.715 141.84 ;
     RECT  0.103 128.862 0.787 128.88 ;
     RECT  0.283 92.826 0.859 92.844 ;
     RECT  0.535 156.672 0.859 156.96 ;
     RECT  0.751 94.41 0.895 94.428 ;
     RECT  0.103 181.782 0.931 181.8 ;
     RECT  0.823 143.316 1.039 143.334 ;
     RECT  0.103 144.252 1.039 144.27 ;
     RECT  0.535 133.794 1.075 134.892 ;
     RECT  0.535 227.952 1.075 228.654 ;
     RECT  0.823 105.246 1.111 105.264 ;
     RECT  0.391 132.444 1.147 132.66 ;
     RECT  1.075 133.56 1.147 134.892 ;
     RECT  1.111 105.21 1.327 105.264 ;
     RECT  0.103 106.218 1.327 106.236 ;
     RECT  0.427 95.994 1.363 96.012 ;
     RECT  0.787 98.73 1.399 98.748 ;
     RECT  0.859 92.79 1.435 92.844 ;
     RECT  0.535 107.262 1.471 109.044 ;
     RECT  1.327 136.836 1.471 136.854 ;
     RECT  0.679 97.344 1.507 97.362 ;
     RECT  0.463 113.814 1.543 113.832 ;
     RECT  1.147 132.444 1.543 134.892 ;
     RECT  0.103 47.862 1.579 47.88 ;
     RECT  1.543 132.444 1.723 134.928 ;
     RECT  1.471 136.188 1.723 136.854 ;
     RECT  0.715 140.616 1.723 141.84 ;
     RECT  1.723 140.202 1.867 141.84 ;
     RECT  0.895 94.176 1.903 94.428 ;
     RECT  0.319 111.042 1.903 111.564 ;
     RECT  1.903 93.906 1.939 94.428 ;
     RECT  1.471 107.028 1.939 109.044 ;
     RECT  1.615 154.314 1.939 154.332 ;
     RECT  1.435 92.79 1.975 93.114 ;
     RECT  1.939 93.87 1.975 94.428 ;
     RECT  1.399 127.386 1.975 127.404 ;
     RECT  0.787 128.628 1.975 128.88 ;
     RECT  0.499 131.634 2.011 131.652 ;
     RECT  1.471 74.43 2.083 74.448 ;
     RECT  2.047 180.306 2.083 180.324 ;
     RECT  1.975 158.706 2.155 158.724 ;
     RECT  1.579 159.786 2.155 159.804 ;
     RECT  0.103 6.822 2.16 6.84 ;
     RECT  0.103 17.622 2.16 17.64 ;
     RECT  0.535 20.394 2.16 20.412 ;
     RECT  0.103 22.752 2.16 22.77 ;
     RECT  1.687 26.946 2.16 26.964 ;
     RECT  0.103 33.552 2.16 33.57 ;
     RECT  1.651 39.6 2.16 39.618 ;
     RECT  1.579 47.862 2.16 48.186 ;
     RECT  0.103 52.992 2.16 53.01 ;
     RECT  1.543 60.66 2.16 60.678 ;
     RECT  0.103 63.828 2.16 63.846 ;
     RECT  2.083 74.43 2.16 75.024 ;
     RECT  1.867 82.26 2.16 82.278 ;
     RECT  0.463 84.996 2.16 85.41 ;
     RECT  2.011 86.616 2.16 86.634 ;
     RECT  0.715 87.93 2.16 87.948 ;
     RECT  0.103 88.902 2.16 88.92 ;
     RECT  0.355 90.324 2.16 90.342 ;
     RECT  2.119 91.404 2.16 91.422 ;
     RECT  1.975 92.79 2.16 94.428 ;
     RECT  1.363 95.256 2.16 96.012 ;
     RECT  1.507 97.11 2.16 97.362 ;
     RECT  1.399 98.46 2.16 98.748 ;
     RECT  1.579 103.482 2.16 103.5 ;
     RECT  1.327 105.21 2.16 106.236 ;
     RECT  1.939 107.028 2.16 109.584 ;
     RECT  1.903 110.646 2.16 111.564 ;
     RECT  1.543 113.274 2.16 113.832 ;
     RECT  1.723 115.632 2.16 115.65 ;
     RECT  0.751 117.36 2.16 117.378 ;
     RECT  1.435 124.146 2.16 124.164 ;
     RECT  1.975 127.386 2.16 128.88 ;
     RECT  0.103 129.672 2.16 129.96 ;
     RECT  2.011 130.896 2.16 131.652 ;
     RECT  1.723 132.444 2.16 138.6 ;
     RECT  1.867 139.734 2.16 141.84 ;
     RECT  1.039 143.316 2.16 144.27 ;
     RECT  0.103 145.062 2.16 145.08 ;
     RECT  0.103 149.382 2.16 149.4 ;
     RECT  0.319 150.3 2.16 151.434 ;
     RECT  1.939 153.774 2.16 154.332 ;
     RECT  1.471 155.394 2.16 155.412 ;
     RECT  0.859 156.672 2.16 157.374 ;
     RECT  2.155 158.706 2.16 159.804 ;
     RECT  1.507 166.536 2.16 166.554 ;
     RECT  0.895 167.436 2.16 167.454 ;
     RECT  0.103 170.982 2.16 171 ;
     RECT  2.119 174.096 2.16 174.114 ;
     RECT  2.011 175.176 2.16 175.194 ;
     RECT  0.103 176.112 2.16 176.13 ;
     RECT  0.967 177.336 2.16 177.354 ;
     RECT  2.083 179.73 2.16 180.324 ;
     RECT  0.931 181.782 2.16 182.214 ;
     RECT  0.103 183.51 2.16 183.528 ;
     RECT  1.687 186.516 2.16 186.534 ;
     RECT  1.543 187.524 2.16 187.542 ;
     RECT  1.651 191.916 2.16 191.934 ;
     RECT  0.463 196.362 2.16 196.38 ;
     RECT  0.103 197.748 2.16 197.766 ;
     RECT  0.391 200.286 2.16 200.304 ;
     RECT  0.103 202.842 2.16 202.86 ;
     RECT  1.111 207.576 2.16 207.594 ;
     RECT  0.103 208.584 2.16 208.602 ;
     RECT  0.563 212.022 2.16 212.04 ;
     RECT  0.103 213.714 2.16 213.732 ;
     RECT  0.247 214.596 2.16 214.614 ;
     RECT  0.103 217.152 2.16 217.17 ;
     RECT  0.103 222.858 2.16 222.876 ;
     RECT  0.499 224.01 2.16 224.028 ;
     RECT  1.075 227.214 2.16 228.654 ;
     RECT  1.039 233.766 2.16 233.784 ;
     RECT  1.003 235.116 2.16 235.134 ;
     RECT  0.103 238.788 2.16 238.806 ;
     RECT  2.16 2.151 153.36 244.089 ;
     RECT  153.36 97.506 153.599 105.804 ;
     RECT  153.36 91.98 153.923 96.624 ;
     RECT  153.599 98.856 153.923 105.804 ;
     RECT  153.36 118.836 153.923 124.254 ;
     RECT  153.36 142.056 153.923 145.926 ;
     RECT  153.36 146.916 153.923 149.904 ;
     RECT  153.36 150.696 153.923 152.604 ;
     RECT  153.923 98.856 154.427 105.39 ;
     RECT  153.36 116.136 154.427 118.044 ;
     RECT  153.36 125.316 154.427 128.304 ;
     RECT  153.923 146.916 154.427 148.59 ;
     RECT  153.36 154.206 154.427 154.764 ;
     RECT  153.923 91.98 154.463 92.43 ;
     RECT  153.923 93.726 154.463 94.284 ;
     RECT  153.923 95.346 154.463 96.174 ;
     RECT  153.599 97.506 154.463 98.064 ;
     RECT  154.427 98.856 154.463 99.414 ;
     RECT  154.427 100.206 154.463 105.39 ;
     RECT  153.36 106.686 154.463 108.864 ;
     RECT  153.36 109.926 154.463 111.294 ;
     RECT  153.36 112.086 154.463 115.344 ;
     RECT  154.427 116.136 154.463 116.154 ;
     RECT  154.427 117.018 154.463 118.044 ;
     RECT  153.923 118.836 154.463 121.284 ;
     RECT  153.923 122.076 154.463 122.634 ;
     RECT  153.923 123.426 154.463 124.254 ;
     RECT  154.427 125.586 154.463 128.304 ;
     RECT  153.36 129.096 154.463 134.784 ;
     RECT  153.36 135.846 154.463 137.79 ;
     RECT  153.36 138.546 154.463 139.374 ;
     RECT  153.36 140.166 154.463 141.264 ;
     RECT  153.923 142.056 154.463 142.074 ;
     RECT  153.923 142.866 154.463 145.926 ;
     RECT  154.427 146.916 154.463 146.934 ;
     RECT  154.427 147.726 154.463 148.59 ;
     RECT  153.923 149.616 154.463 149.904 ;
     RECT  153.923 150.696 154.463 151.254 ;
     RECT  153.923 152.046 154.463 152.604 ;
     RECT  153.36 153.396 154.463 153.414 ;
     RECT  154.427 154.746 154.463 154.764 ;
     RECT  154.463 104.256 154.499 104.274 ;
     RECT  154.463 108.684 154.499 108.702 ;
     RECT  154.463 111.114 154.499 111.132 ;
     RECT  154.463 119.106 154.499 119.124 ;
     RECT  154.463 124.146 154.499 124.164 ;
     RECT  154.463 129.366 154.499 129.96 ;
     RECT  154.463 136.764 154.499 136.782 ;
     RECT  154.463 138.996 154.499 139.014 ;
     RECT  154.463 140.706 154.499 140.724 ;
     RECT  154.463 145.908 154.499 145.926 ;
     RECT  154.463 149.796 154.499 149.814 ;
    LAYER M3 ;
     RECT  2.415 2.143 2.505 2.413 ;
     RECT  7.815 2.143 7.905 2.413 ;
     RECT  13.215 2.143 13.305 2.413 ;
     RECT  18.615 2.143 18.705 2.413 ;
     RECT  24.015 2.143 24.105 2.413 ;
     RECT  29.415 2.143 29.505 2.413 ;
     RECT  34.815 2.143 34.905 2.413 ;
     RECT  40.215 2.143 40.305 2.413 ;
     RECT  45.615 2.143 45.705 2.413 ;
     RECT  51.015 2.143 51.105 2.413 ;
     RECT  56.415 2.143 56.505 2.413 ;
     RECT  61.815 2.143 61.905 2.413 ;
     RECT  67.215 2.143 67.305 2.413 ;
     RECT  72.615 2.143 72.705 2.413 ;
     RECT  78.015 2.143 78.105 2.413 ;
     RECT  83.415 2.143 83.505 2.413 ;
     RECT  88.815 2.143 88.905 2.413 ;
     RECT  94.215 2.143 94.305 2.413 ;
     RECT  99.615 2.143 99.705 2.413 ;
     RECT  105.015 2.143 105.105 2.413 ;
     RECT  110.415 2.143 110.505 2.413 ;
     RECT  115.815 2.143 115.905 2.413 ;
     RECT  121.215 2.143 121.305 2.413 ;
     RECT  126.615 2.143 126.705 2.413 ;
     RECT  132.015 2.143 132.105 2.413 ;
     RECT  137.415 2.143 137.505 2.413 ;
     RECT  142.815 2.143 142.905 2.413 ;
     RECT  148.215 2.143 148.305 2.413 ;
     RECT  2.415 2.413 2.697 5.845 ;
     RECT  2.415 5.845 3.258 5.881 ;
     RECT  2.415 5.881 3.474 5.995 ;
     RECT  2.304 5.995 3.474 6.079 ;
     RECT  2.304 6.079 3.834 6.115 ;
     RECT  5.112 6.151 5.13 6.241 ;
     RECT  5.112 6.241 5.634 6.283 ;
     RECT  4.824 6.283 5.634 6.305 ;
     RECT  2.304 6.115 4.086 6.317 ;
     RECT  3.42 6.317 4.086 6.539 ;
     RECT  2.304 6.317 2.697 6.575 ;
     RECT  3.456 6.539 4.086 6.655 ;
     RECT  4.824 6.305 4.842 6.655 ;
     RECT  3.456 6.655 4.842 6.683 ;
     RECT  5.616 6.305 5.634 6.691 ;
     RECT  3.708 6.683 4.842 6.845 ;
     RECT  5.616 6.691 5.706 6.853 ;
     RECT  0.108 6.817 0.126 6.893 ;
     RECT  6.552 6.808 6.57 6.925 ;
     RECT  7.815 2.413 8.097 6.925 ;
     RECT  5.616 6.853 5.814 7.051 ;
     RECT  3.708 6.845 3.906 7.115 ;
     RECT  4.932 7.051 5.814 7.151 ;
     RECT  6.552 6.925 8.097 7.223 ;
     RECT  5.58 7.151 5.814 7.231 ;
     RECT  7.38 7.223 8.097 7.321 ;
     RECT  2.34 6.575 2.697 7.393 ;
     RECT  5.58 7.231 6.498 7.421 ;
     RECT  2.34 7.393 2.898 7.763 ;
     RECT  7.38 7.321 8.406 7.771 ;
     RECT  7.38 7.771 8.73 7.805 ;
     RECT  2.415 7.763 2.898 7.867 ;
     RECT  3.744 7.115 3.906 7.867 ;
     RECT  2.415 7.867 3.906 7.897 ;
     RECT  2.415 7.897 4.086 7.933 ;
     RECT  2.415 7.933 4.734 8.041 ;
     RECT  5.58 7.421 5.814 8.041 ;
     RECT  2.415 8.041 5.814 8.587 ;
     RECT  6.984 8.311 7.002 8.671 ;
     RECT  7.815 7.805 8.73 8.671 ;
     RECT  2.304 8.587 5.814 8.815 ;
     RECT  6.984 8.671 8.73 8.815 ;
     RECT  2.304 8.815 8.73 8.969 ;
     RECT  7.74 8.969 8.73 8.977 ;
     RECT  7.74 8.977 8.91 9.121 ;
     RECT  2.304 8.969 7.002 9.239 ;
     RECT  7.74 9.121 9.378 9.509 ;
     RECT  7.815 9.509 9.378 9.661 ;
     RECT  2.304 9.239 6.246 9.923 ;
     RECT  6.984 9.239 7.002 9.931 ;
     RECT  6.984 9.931 7.038 10.435 ;
     RECT  7.815 9.661 9.81 10.435 ;
     RECT  3.42 9.923 6.246 10.471 ;
     RECT  6.984 10.435 9.81 10.471 ;
     RECT  3.42 10.471 9.81 10.589 ;
     RECT  2.304 9.923 2.697 10.705 ;
     RECT  3.42 10.589 6.138 10.705 ;
     RECT  6.984 10.589 9.81 10.895 ;
     RECT  7.812 10.895 9.81 11.069 ;
     RECT  2.304 10.705 6.138 11.939 ;
     RECT  6.984 10.895 7.002 12.091 ;
     RECT  6.984 12.091 7.038 12.217 ;
     RECT  7.815 11.069 9.81 12.217 ;
     RECT  5.616 11.939 6.138 12.283 ;
     RECT  6.984 12.217 9.81 12.283 ;
     RECT  5.616 12.283 9.81 12.515 ;
     RECT  5.616 12.515 7.002 12.749 ;
     RECT  2.304 11.939 4.446 12.793 ;
     RECT  2.196 12.793 4.446 13.171 ;
     RECT  5.616 12.749 6.138 13.171 ;
     RECT  2.196 13.171 4.518 13.243 ;
     RECT  5.4 13.171 6.138 13.243 ;
     RECT  6.984 12.749 7.002 13.261 ;
     RECT  7.74 12.515 9.81 13.261 ;
     RECT  6.984 13.261 9.81 13.441 ;
     RECT  6.984 13.441 10.494 13.661 ;
     RECT  2.196 13.243 6.138 14.521 ;
     RECT  2.196 14.521 6.246 14.639 ;
     RECT  2.196 14.639 6.138 14.711 ;
     RECT  2.196 14.711 3.654 14.945 ;
     RECT  3.456 14.945 3.654 15.565 ;
     RECT  4.5 14.711 6.138 15.565 ;
     RECT  2.196 14.945 2.697 15.835 ;
     RECT  3.456 15.565 6.138 15.835 ;
     RECT  2.196 15.835 6.138 15.871 ;
     RECT  6.984 13.661 9.81 15.871 ;
     RECT  0.108 15.835 0.126 15.965 ;
     RECT  2.196 15.871 9.81 16.259 ;
     RECT  0.108 17.617 0.126 17.693 ;
     RECT  2.196 16.259 6.138 19.111 ;
     RECT  6.912 16.259 9.81 19.111 ;
     RECT  2.196 19.111 9.81 19.265 ;
     RECT  3.456 19.265 9.81 20.921 ;
     RECT  3.456 20.921 3.654 21.811 ;
     RECT  2.196 19.265 2.697 21.937 ;
     RECT  3.456 21.811 3.762 21.937 ;
     RECT  2.196 21.937 3.762 22.013 ;
     RECT  3.456 22.013 3.762 22.045 ;
     RECT  4.5 20.921 9.81 22.045 ;
     RECT  0.54 20.389 0.558 22.747 ;
     RECT  0.108 22.747 0.558 22.877 ;
     RECT  13.215 2.413 13.497 22.981 ;
     RECT  11.088 23.629 11.106 24.061 ;
     RECT  2.196 22.013 2.697 24.097 ;
     RECT  3.456 22.045 9.81 24.097 ;
     RECT  2.196 24.097 9.81 24.359 ;
     RECT  3.456 24.359 9.81 24.601 ;
     RECT  2.196 24.359 2.697 25.285 ;
     RECT  3.456 24.601 10.026 25.285 ;
     RECT  18.615 2.413 18.897 25.681 ;
     RECT  2.196 25.285 10.026 25.709 ;
     RECT  2.196 25.709 2.697 26.761 ;
     RECT  3.456 25.709 10.026 26.761 ;
     RECT  2.196 26.761 10.026 26.941 ;
     RECT  1.692 26.941 10.026 28.679 ;
     RECT  1.692 28.679 2.697 29.641 ;
     RECT  3.456 28.679 10.026 29.641 ;
     RECT  1.692 29.641 10.026 31.955 ;
     RECT  11.088 24.061 11.394 32.431 ;
     RECT  0.54 22.877 0.558 33.547 ;
     RECT  0.108 33.547 0.558 33.677 ;
     RECT  1.692 31.955 2.697 33.691 ;
     RECT  3.42 31.955 10.026 33.691 ;
     RECT  11.088 32.431 11.682 36.557 ;
     RECT  1.692 33.691 10.026 37.021 ;
     RECT  11.088 36.557 11.394 37.021 ;
     RECT  1.692 37.021 11.394 37.049 ;
     RECT  3.456 37.049 11.394 39.055 ;
     RECT  1.692 37.049 2.697 39.259 ;
     RECT  3.42 39.055 11.394 39.259 ;
     RECT  1.692 39.259 11.394 39.515 ;
     RECT  1.692 39.515 2.697 39.595 ;
     RECT  1.656 39.595 2.697 40.297 ;
     RECT  3.456 39.515 11.394 40.297 ;
     RECT  1.656 40.297 11.394 41.341 ;
     RECT  1.656 41.341 11.934 42.151 ;
     RECT  12.996 22.981 13.497 42.151 ;
     RECT  1.656 42.151 13.497 43.025 ;
     RECT  1.656 43.025 2.697 44.149 ;
     RECT  3.456 43.025 13.497 44.149 ;
     RECT  0.54 33.677 0.558 47.857 ;
     RECT  0.108 47.857 0.558 47.933 ;
     RECT  1.656 44.149 13.497 48.163 ;
     RECT  18.18 25.681 18.897 49.711 ;
     RECT  0.54 47.933 0.558 52.987 ;
     RECT  0.108 52.987 0.558 53.117 ;
     RECT  15.12 20.191 15.138 55.111 ;
     RECT  1.584 48.163 13.497 55.219 ;
     RECT  14.4 55.111 15.138 55.219 ;
     RECT  1.584 55.219 15.138 55.255 ;
     RECT  16.236 19.201 16.254 55.255 ;
     RECT  27.252 59.701 27.27 59.789 ;
     RECT  22.824 59.707 22.842 59.837 ;
     RECT  27.072 59.8 27.09 59.837 ;
     RECT  1.584 55.255 16.254 60.655 ;
     RECT  0.54 53.117 0.558 63.823 ;
     RECT  0.108 63.823 0.558 63.917 ;
     RECT  16.992 63.049 17.01 67.405 ;
     RECT  17.928 49.711 18.897 67.405 ;
     RECT  1.548 60.655 16.254 70.033 ;
     RECT  16.992 67.405 18.897 70.033 ;
     RECT  21.42 70.303 21.438 71.491 ;
     RECT  22.824 72.667 22.842 72.797 ;
     RECT  19.656 72.301 19.674 72.967 ;
     RECT  19.656 72.967 20.286 74.011 ;
     RECT  21.42 71.491 21.582 74.011 ;
     RECT  19.656 74.011 21.582 74.093 ;
     RECT  1.548 70.033 18.897 74.425 ;
     RECT  21.42 74.093 21.582 75.271 ;
     RECT  21.06 75.271 21.582 75.389 ;
     RECT  21.42 75.389 21.582 75.397 ;
     RECT  22.68 75.271 22.698 75.397 ;
     RECT  1.476 74.425 18.897 75.505 ;
     RECT  19.656 74.093 20.286 75.505 ;
     RECT  1.476 75.505 20.286 75.541 ;
     RECT  21.42 75.397 22.698 75.643 ;
     RECT  21.42 75.643 22.842 75.973 ;
     RECT  1.476 75.541 20.538 76.981 ;
     RECT  21.42 75.973 23.202 76.981 ;
     RECT  21.42 76.981 23.274 77.125 ;
     RECT  24.015 2.413 24.297 77.125 ;
     RECT  27.144 76.441 27.162 77.251 ;
     RECT  1.476 76.981 20.646 77.431 ;
     RECT  21.42 77.125 24.297 77.431 ;
     RECT  28.512 77.089 28.53 77.549 ;
     RECT  30.78 77.701 30.798 77.855 ;
     RECT  1.476 77.431 24.297 78.907 ;
     RECT  25.272 76.891 25.29 78.907 ;
     RECT  1.476 78.907 25.29 80.059 ;
     RECT  28.512 79.861 28.53 80.671 ;
     RECT  27.936 80.671 28.53 80.699 ;
     RECT  26.892 77.251 27.162 80.779 ;
     RECT  37.764 80.671 37.782 80.789 ;
     RECT  27.936 80.699 27.954 81.095 ;
     RECT  29.415 2.413 29.697 81.175 ;
     RECT  38.196 80.905 38.214 81.365 ;
     RECT  1.476 80.059 25.686 81.481 ;
     RECT  34.815 2.413 35.097 82.651 ;
     RECT  44.172 81.211 44.19 82.651 ;
     RECT  34.704 82.651 35.097 82.688 ;
     RECT  44.172 82.651 44.226 82.831 ;
     RECT  34.815 82.688 35.097 83.335 ;
     RECT  34.815 83.335 35.586 83.525 ;
     RECT  44.172 82.831 44.766 83.525 ;
     RECT  45.615 2.413 45.897 83.641 ;
     RECT  1.476 81.481 25.938 84.811 ;
     RECT  26.856 80.779 27.162 84.811 ;
     RECT  0.54 63.917 0.558 84.991 ;
     RECT  40.215 2.413 40.497 85.189 ;
     RECT  0.468 84.991 0.558 85.387 ;
     RECT  0.108 85.387 0.558 85.517 ;
     RECT  33.444 86.341 33.462 86.495 ;
     RECT  1.476 84.811 27.162 86.971 ;
     RECT  39.096 81.481 39.114 87.007 ;
     RECT  38.916 87.007 39.114 87.269 ;
     RECT  40.215 85.189 41.202 87.269 ;
     RECT  39.096 87.269 39.114 87.421 ;
     RECT  42.768 87.421 42.786 87.845 ;
     RECT  0.468 85.517 0.558 87.925 ;
     RECT  39.096 87.421 39.366 87.961 ;
     RECT  40.215 87.269 40.497 87.961 ;
     RECT  44.172 83.525 44.19 87.961 ;
     RECT  43.524 87.961 44.19 88.079 ;
     RECT  1.476 86.971 27.378 88.114 ;
     RECT  52.344 88.087 52.362 88.889 ;
     RECT  0.468 87.925 0.738 88.897 ;
     RECT  53.856 84.721 53.874 88.897 ;
     RECT  0.108 88.897 0.738 88.973 ;
     RECT  53.316 88.897 53.874 89.465 ;
     RECT  1.476 88.114 27.414 89.771 ;
     RECT  0.468 88.973 0.738 90.319 ;
     RECT  52.632 90.211 52.65 90.481 ;
     RECT  67.215 2.413 67.497 90.481 ;
     RECT  52.632 90.481 52.722 90.509 ;
     RECT  67.215 90.481 68.058 90.557 ;
     RECT  67.215 90.557 67.497 90.571 ;
     RECT  66.492 90.571 67.497 90.617 ;
     RECT  147.456 84.073 147.474 90.625 ;
     RECT  148.215 2.413 148.497 90.625 ;
     RECT  147.456 90.625 148.497 90.653 ;
     RECT  30.456 84.859 30.474 91.229 ;
     RECT  32.58 77.971 32.598 91.291 ;
     RECT  52.704 90.509 52.722 91.355 ;
     RECT  53.46 89.465 53.874 91.471 ;
     RECT  72.615 2.413 72.897 91.471 ;
     RECT  53.208 91.471 53.874 91.625 ;
     RECT  149.724 89.743 149.742 91.723 ;
     RECT  149.724 91.723 149.778 91.741 ;
     RECT  153.036 91.669 153.054 91.741 ;
     RECT  31.932 91.291 32.598 91.859 ;
     RECT  33.912 86.611 33.93 92.011 ;
     RECT  149.724 91.741 150.282 92.011 ;
     RECT  152.028 91.705 152.046 92.011 ;
     RECT  1.476 89.771 27.162 92.101 ;
     RECT  28.26 85.459 28.278 92.101 ;
     RECT  149.724 92.011 151.002 92.165 ;
     RECT  152.028 92.011 152.118 92.281 ;
     RECT  149.724 92.165 150.822 92.299 ;
     RECT  33.624 92.011 33.93 92.371 ;
     RECT  149.256 92.299 150.822 92.399 ;
     RECT  151.596 92.281 152.118 92.435 ;
     RECT  154.44 91.963 154.458 92.435 ;
     RECT  149.256 92.399 150.534 92.471 ;
     RECT  152.028 92.435 152.118 92.551 ;
     RECT  153 91.741 153.234 92.551 ;
     RECT  152.028 92.551 153.234 92.669 ;
     RECT  149.724 92.471 150.534 92.705 ;
     RECT  152.136 92.669 153.234 92.705 ;
     RECT  149.724 92.705 150.462 92.741 ;
     RECT  33.624 92.371 33.966 92.749 ;
     RECT  34.815 83.525 35.097 92.749 ;
     RECT  0.36 90.319 0.738 92.785 ;
     RECT  1.476 92.101 28.278 92.785 ;
     RECT  0.36 92.785 28.278 92.821 ;
     RECT  152.568 92.705 153.234 92.861 ;
     RECT  69.228 90.931 69.246 92.911 ;
     RECT  33.624 92.749 35.097 92.923 ;
     RECT  149.724 92.741 150.282 92.939 ;
     RECT  147.528 90.653 148.497 93.019 ;
     RECT  152.568 92.861 153.054 93.209 ;
     RECT  147.528 93.019 148.914 93.245 ;
     RECT  153.9 93.091 153.918 93.293 ;
     RECT  45 83.641 45.897 93.325 ;
     RECT  147.528 93.245 148.662 93.451 ;
     RECT  145.62 93.325 145.638 93.479 ;
     RECT  152.568 93.209 152.766 93.479 ;
     RECT  145.44 93.499 145.458 93.551 ;
     RECT  147.06 93.451 148.662 93.559 ;
     RECT  146.592 93.559 148.662 93.595 ;
     RECT  146.412 93.595 148.662 93.749 ;
     RECT  146.592 93.749 148.662 93.785 ;
     RECT  152.532 93.865 152.55 93.991 ;
     RECT  37.512 85.765 37.53 94.019 ;
     RECT  151.02 93.901 151.038 94.099 ;
     RECT  152.136 93.991 152.55 94.099 ;
     RECT  151.02 94.099 152.55 94.135 ;
     RECT  149.724 92.939 150.03 94.171 ;
     RECT  150.84 94.135 152.55 94.171 ;
     RECT  37.62 94.171 37.638 94.325 ;
     RECT  147.528 93.785 148.662 94.363 ;
     RECT  149.724 94.171 152.55 94.363 ;
     RECT  147.528 94.363 152.55 94.405 ;
     RECT  147.528 94.405 153.018 94.901 ;
     RECT  32.58 91.859 32.598 94.945 ;
     RECT  33.336 92.923 35.097 94.945 ;
     RECT  146.592 93.785 146.61 94.945 ;
     RECT  154.44 93.691 154.458 94.981 ;
     RECT  153.9 94.981 154.458 95.021 ;
     RECT  59.688 94.981 59.706 95.099 ;
     RECT  61.815 2.413 62.097 95.143 ;
     RECT  146.196 94.945 146.61 95.215 ;
     RECT  147.528 94.901 148.497 95.215 ;
     RECT  39.096 87.961 40.497 95.369 ;
     RECT  146.052 95.215 148.497 95.369 ;
     RECT  149.22 94.901 153.018 95.369 ;
     RECT  147.456 95.369 148.497 95.405 ;
     RECT  146.052 95.369 146.502 95.477 ;
     RECT  43.524 88.079 43.542 95.549 ;
     RECT  61.416 95.143 62.097 95.611 ;
     RECT  149.22 95.369 151.83 95.645 ;
     RECT  61.416 95.611 62.406 95.675 ;
     RECT  146.052 95.477 146.07 95.741 ;
     RECT  37.872 94.405 37.89 95.755 ;
     RECT  37.332 95.755 37.89 95.945 ;
     RECT  151.02 95.645 151.83 95.945 ;
     RECT  69.228 92.911 69.966 95.995 ;
     RECT  152.784 95.369 153.018 96.061 ;
     RECT  152.784 96.061 153.054 96.151 ;
     RECT  154.44 95.021 154.458 96.179 ;
     RECT  151.524 95.945 151.83 96.295 ;
     RECT  152.676 96.151 153.054 96.295 ;
     RECT  76.068 89.131 76.086 96.601 ;
     RECT  75.564 96.601 76.086 96.629 ;
     RECT  153.9 96.283 153.918 96.749 ;
     RECT  147.528 95.405 148.497 96.907 ;
     RECT  149.22 95.645 149.742 96.907 ;
     RECT  146.7 96.601 146.718 96.955 ;
     RECT  142.815 2.413 143.097 96.961 ;
     RECT  30.456 96.715 30.474 97.033 ;
     RECT  151.524 96.295 153.054 97.099 ;
     RECT  142.524 96.961 143.097 97.133 ;
     RECT  146.268 96.955 146.718 97.181 ;
     RECT  0.288 92.821 28.278 97.387 ;
     RECT  29.232 81.175 29.697 97.387 ;
     RECT  151.164 97.099 153.054 97.565 ;
     RECT  152.568 97.565 153.054 97.579 ;
     RECT  110.415 2.413 110.697 97.765 ;
     RECT  99.615 2.413 99.897 97.771 ;
     RECT  121.215 2.413 121.497 97.771 ;
     RECT  132.015 2.413 132.297 97.771 ;
     RECT  110.304 97.765 110.697 97.805 ;
     RECT  99.504 97.771 99.897 97.808 ;
     RECT  121.104 97.771 121.497 97.808 ;
     RECT  131.904 97.771 132.297 97.808 ;
     RECT  142.704 97.133 143.097 97.808 ;
     RECT  151.164 97.565 151.758 97.951 ;
     RECT  95.904 97.645 95.922 98.059 ;
     RECT  95.868 98.059 95.922 98.105 ;
     RECT  95.904 98.105 95.922 98.189 ;
     RECT  147.528 96.907 149.742 98.221 ;
     RECT  150.624 97.951 151.758 98.221 ;
     RECT  147.528 98.221 151.758 98.339 ;
     RECT  30.456 97.033 30.798 98.375 ;
     RECT  147.528 98.339 150.462 98.375 ;
     RECT  152.568 97.579 153.594 98.411 ;
     RECT  152.568 98.411 153.054 98.483 ;
     RECT  32.58 94.945 35.097 98.491 ;
     RECT  35.82 83.641 35.838 98.491 ;
     RECT  151.524 98.339 151.758 98.491 ;
     RECT  152.568 98.483 152.982 98.491 ;
     RECT  146.484 97.181 146.718 98.519 ;
     RECT  147.528 98.375 148.497 98.581 ;
     RECT  147.456 98.581 148.497 98.609 ;
     RECT  40.215 95.369 40.497 98.761 ;
     RECT  154.44 97.147 154.458 98.875 ;
     RECT  0.288 97.387 29.697 98.887 ;
     RECT  30.456 98.375 30.474 98.887 ;
     RECT  151.524 98.491 152.982 98.915 ;
     RECT  32.58 98.491 35.838 99.149 ;
     RECT  34.668 99.149 35.838 99.329 ;
     RECT  75.564 96.629 75.582 99.419 ;
     RECT  154.404 98.875 154.458 99.419 ;
     RECT  149.22 98.375 150.462 99.571 ;
     RECT  151.524 98.915 152.874 99.571 ;
     RECT  0.288 98.887 30.474 99.689 ;
     RECT  146.7 98.519 146.718 99.739 ;
     RECT  149.22 99.571 152.874 99.739 ;
     RECT  34.668 99.329 35.622 100.031 ;
     RECT  154.404 99.419 154.422 100.067 ;
     RECT  149.22 99.739 153.522 100.139 ;
     RECT  32.58 99.149 33.786 100.229 ;
     RECT  146.556 99.739 146.718 100.229 ;
     RECT  31.608 93.307 31.626 100.237 ;
     RECT  32.58 100.229 32.598 100.237 ;
     RECT  69.228 95.995 70.398 100.381 ;
     RECT  147.456 98.609 147.474 100.381 ;
     RECT  148.215 98.609 148.497 100.381 ;
     RECT  147.456 100.381 148.497 100.535 ;
     RECT  148.215 100.535 148.497 100.579 ;
     RECT  149.22 100.139 153.054 100.579 ;
     RECT  63.288 100.273 63.306 100.607 ;
     RECT  78.015 2.413 78.297 100.741 ;
     RECT  148.215 100.579 153.054 100.769 ;
     RECT  77.544 100.741 78.297 100.781 ;
     RECT  146.484 100.777 146.502 100.877 ;
     RECT  34.668 100.031 35.097 100.885 ;
     RECT  69.228 100.381 70.614 100.913 ;
     RECT  34.668 100.885 35.694 101.039 ;
     RECT  152.28 100.769 153.054 101.039 ;
     RECT  36.684 97.411 36.702 101.047 ;
     RECT  36.288 101.047 36.702 101.219 ;
     RECT  148.215 100.769 151.542 101.309 ;
     RECT  152.28 101.039 153.018 101.309 ;
     RECT  148.215 101.309 149.778 101.345 ;
     RECT  30.456 99.689 30.474 101.759 ;
     RECT  147.456 100.535 147.474 101.821 ;
     RECT  147.312 101.821 147.474 101.849 ;
     RECT  148.215 101.345 149.742 101.849 ;
     RECT  147.312 101.849 147.33 101.885 ;
     RECT  148.215 101.849 149.562 101.885 ;
     RECT  150.912 101.309 151.542 102.091 ;
     RECT  60.66 101.551 60.678 102.119 ;
     RECT  0.288 99.689 29.697 102.155 ;
     RECT  150.912 102.091 152.154 102.199 ;
     RECT  58.716 102.127 58.734 102.227 ;
     RECT  60.732 102.127 60.75 102.227 ;
     RECT  31.608 100.237 32.598 102.389 ;
     RECT  150.48 102.199 152.154 102.389 ;
     RECT  152.928 101.309 153.018 102.389 ;
     RECT  150.84 102.389 152.154 102.505 ;
     RECT  152.928 102.389 152.946 102.505 ;
     RECT  150.84 102.505 152.946 102.557 ;
     RECT  69.948 100.913 70.614 102.811 ;
     RECT  148.215 101.885 149.238 102.859 ;
     RECT  150.048 102.811 150.066 102.859 ;
     RECT  148.215 102.859 150.066 102.929 ;
     RECT  150.912 102.557 152.946 102.929 ;
     RECT  29.268 102.155 29.697 103.009 ;
     RECT  30.456 102.715 30.474 103.009 ;
     RECT  146.484 102.271 146.502 103.037 ;
     RECT  31.608 102.389 32.238 103.379 ;
     RECT  146.988 103.351 147.15 103.469 ;
     RECT  150.912 102.929 152.262 103.469 ;
     RECT  29.268 103.009 30.474 103.585 ;
     RECT  146.988 103.469 147.006 103.661 ;
     RECT  149.22 102.929 149.994 103.739 ;
     RECT  149.22 103.739 149.778 103.775 ;
     RECT  29.052 103.585 30.474 104.009 ;
     RECT  150.912 103.469 151.758 104.251 ;
     RECT  154.44 100.171 154.458 104.251 ;
     RECT  29.268 104.009 30.474 104.279 ;
     RECT  150.696 104.251 151.758 104.315 ;
     RECT  152.496 104.125 152.55 104.395 ;
     RECT  154.44 104.251 154.494 104.525 ;
     RECT  152.496 104.395 153.054 104.549 ;
     RECT  0.288 102.155 28.206 104.819 ;
     RECT  153.036 104.549 153.054 104.819 ;
     RECT  148.215 102.929 148.497 104.827 ;
     RECT  149.22 103.775 149.238 104.827 ;
     RECT  150.156 104.899 150.174 104.971 ;
     RECT  150.912 104.315 151.758 105.205 ;
     RECT  148.215 104.827 149.238 105.241 ;
     RECT  150.048 104.971 150.174 105.241 ;
     RECT  148.215 105.241 150.174 105.307 ;
     RECT  147.78 105.307 150.174 105.331 ;
     RECT  147.636 105.331 150.174 105.389 ;
     RECT  148.215 105.389 150.174 105.395 ;
     RECT  154.44 104.525 154.458 105.395 ;
     RECT  146.484 105.307 146.502 105.437 ;
     RECT  150.912 105.205 152.01 105.475 ;
     RECT  152.784 105.403 153.018 105.475 ;
     RECT  148.215 105.395 149.49 105.665 ;
     RECT  146.7 105.745 146.718 105.821 ;
     RECT  153.9 105.781 153.918 105.821 ;
     RECT  150.912 105.475 153.018 105.883 ;
     RECT  150.732 105.883 153.018 105.899 ;
     RECT  150.732 105.899 150.75 105.935 ;
     RECT  0.288 104.819 25.758 106.043 ;
     RECT  72.615 91.471 73.026 106.051 ;
     RECT  26.856 104.819 28.206 106.141 ;
     RECT  149.22 105.665 149.49 106.141 ;
     RECT  0.288 106.043 25.686 106.213 ;
     RECT  0.108 106.213 25.686 106.253 ;
     RECT  149.22 106.141 149.634 106.253 ;
     RECT  26.712 106.141 28.206 106.475 ;
     RECT  150.408 106.321 150.426 106.475 ;
     RECT  148.215 105.665 148.497 106.603 ;
     RECT  149.22 106.253 149.562 106.603 ;
     RECT  151.524 105.899 153.018 106.651 ;
     RECT  26.856 106.475 28.206 106.825 ;
     RECT  151.524 106.651 153.522 106.861 ;
     RECT  0.288 106.253 25.686 106.889 ;
     RECT  37.476 95.945 37.89 106.889 ;
     RECT  151.128 106.861 153.522 106.889 ;
     RECT  40.215 98.761 40.95 106.951 ;
     RECT  146.484 106.861 146.574 106.979 ;
     RECT  151.128 106.889 153.054 106.979 ;
     RECT  148.215 106.603 149.562 107.015 ;
     RECT  146.556 106.979 146.574 107.051 ;
     RECT  148.215 107.015 149.526 107.051 ;
     RECT  0.288 106.889 25.434 107.083 ;
     RECT  39.888 106.951 40.95 107.123 ;
     RECT  40.215 107.123 40.95 107.131 ;
     RECT  26.856 106.825 28.494 107.221 ;
     RECT  29.268 104.279 29.697 107.221 ;
     RECT  43.884 106.555 43.902 107.249 ;
     RECT  26.856 107.221 29.697 107.635 ;
     RECT  151.164 106.979 153.054 107.789 ;
     RECT  151.164 107.789 152.982 107.825 ;
     RECT  32.184 103.379 32.238 108.031 ;
     RECT  39.096 95.369 39.114 108.059 ;
     RECT  33.336 100.229 33.786 108.095 ;
     RECT  149.22 107.051 149.526 108.095 ;
     RECT  151.164 107.825 151.542 108.211 ;
     RECT  150.948 108.211 151.542 108.365 ;
     RECT  154.44 106.219 154.458 108.379 ;
     RECT  148.215 107.051 148.497 108.481 ;
     RECT  149.22 108.095 149.238 108.481 ;
     RECT  151.524 108.365 151.542 108.571 ;
     RECT  152.316 107.825 152.982 108.571 ;
     RECT  31.608 108.031 32.238 108.599 ;
     RECT  26.496 107.635 29.697 108.607 ;
     RECT  153.9 108.379 154.458 108.679 ;
     RECT  30.456 104.279 30.474 108.715 ;
     RECT  31.608 108.599 32.202 108.715 ;
     RECT  151.524 108.571 152.982 108.715 ;
     RECT  148.215 108.481 149.238 108.749 ;
     RECT  153.9 108.679 154.494 108.779 ;
     RECT  154.44 108.779 154.494 108.869 ;
     RECT  0.108 107.083 25.434 108.905 ;
     RECT  150.192 108.751 150.534 108.905 ;
     RECT  0.288 108.905 25.434 108.907 ;
     RECT  26.244 108.607 29.697 108.989 ;
     RECT  151.524 108.715 153.054 109.021 ;
     RECT  151.524 109.021 153.234 109.139 ;
     RECT  148.215 108.749 148.497 109.147 ;
     RECT  53.208 91.625 53.478 109.243 ;
     RECT  154.476 108.869 154.494 109.277 ;
     RECT  54.324 93.631 54.342 109.291 ;
     RECT  53.172 109.243 53.478 109.319 ;
     RECT  26.496 108.989 29.697 109.381 ;
     RECT  30.456 108.715 32.202 109.381 ;
     RECT  150.264 108.905 150.534 109.387 ;
     RECT  151.524 109.139 153.054 109.387 ;
     RECT  26.496 109.381 32.202 109.421 ;
     RECT  54.288 109.291 54.342 109.421 ;
     RECT  150.264 109.387 153.054 109.589 ;
     RECT  71.712 91.741 71.73 109.679 ;
     RECT  151.38 109.589 153.054 109.679 ;
     RECT  58.788 102.271 58.806 109.751 ;
     RECT  147.636 109.147 148.497 109.997 ;
     RECT  151.38 109.679 152.91 110.021 ;
     RECT  151.38 110.021 152.442 110.219 ;
     RECT  150.264 109.589 150.282 110.251 ;
     RECT  63.648 100.843 63.666 110.461 ;
     RECT  63.648 110.461 63.738 110.489 ;
     RECT  51.015 2.413 51.297 110.635 ;
     RECT  0.288 108.907 25.47 110.641 ;
     RECT  26.496 109.421 29.697 110.641 ;
     RECT  146.664 110.587 146.682 110.641 ;
     RECT  56.415 2.413 56.697 110.731 ;
     RECT  0.288 110.641 29.697 110.759 ;
     RECT  146.664 110.641 146.826 110.759 ;
     RECT  50.724 110.635 51.297 110.813 ;
     RECT  148.215 109.997 148.497 110.911 ;
     RECT  149.22 108.749 149.238 110.911 ;
     RECT  150.012 110.251 150.282 110.911 ;
     RECT  63.72 110.489 63.738 110.939 ;
     RECT  0.288 110.759 25.686 110.971 ;
     RECT  151.524 110.219 151.542 111.001 ;
     RECT  0.108 110.971 25.686 111.029 ;
     RECT  55.872 110.731 56.697 111.029 ;
     RECT  149.22 110.911 150.282 111.029 ;
     RECT  0.108 111.029 25.47 111.065 ;
     RECT  57.528 111.019 57.546 111.065 ;
     RECT  147.6 110.911 148.497 111.065 ;
     RECT  154.44 109.675 154.458 111.109 ;
     RECT  146.484 110.911 146.502 111.137 ;
     RECT  150.084 111.029 150.282 111.145 ;
     RECT  153 111.109 153.018 111.145 ;
     RECT  33.336 108.095 33.354 111.181 ;
     RECT  34.668 101.039 35.097 111.181 ;
     RECT  30.456 109.421 32.202 111.209 ;
     RECT  151.524 111.001 151.686 111.335 ;
     RECT  150.084 111.145 150.318 111.379 ;
     RECT  31.608 111.209 32.202 111.407 ;
     RECT  154.44 111.109 154.494 111.437 ;
     RECT  150.084 111.379 150.57 111.685 ;
     RECT  151.524 111.335 151.542 111.685 ;
     RECT  150.084 111.685 151.542 111.725 ;
     RECT  148.215 111.065 148.497 111.835 ;
     RECT  149.22 111.029 149.238 111.835 ;
     RECT  69.948 102.811 70.722 111.839 ;
     RECT  148.215 111.835 149.238 111.839 ;
     RECT  148.215 111.839 149.094 111.875 ;
     RECT  146.232 111.739 146.25 111.991 ;
     RECT  150.084 111.725 150.102 111.991 ;
     RECT  152.532 111.145 153.018 111.991 ;
     RECT  40.215 107.131 41.31 112.019 ;
     RECT  152.496 111.991 153.018 112.081 ;
     RECT  146.232 111.991 146.394 112.109 ;
     RECT  53.208 109.319 53.478 112.153 ;
     RECT  52.992 112.153 53.478 112.205 ;
     RECT  150.948 111.725 151.542 112.225 ;
     RECT  152.28 112.081 153.018 112.225 ;
     RECT  150.948 112.225 153.018 112.451 ;
     RECT  150.012 111.991 150.102 112.843 ;
     RECT  150.948 112.451 152.91 112.843 ;
     RECT  150.012 112.843 152.91 112.955 ;
     RECT  44.892 93.325 45.897 113.189 ;
     RECT  150.84 112.955 152.91 113.225 ;
     RECT  40.215 112.019 40.95 113.269 ;
     RECT  146.484 113.161 146.502 113.297 ;
     RECT  152.568 113.225 152.91 113.305 ;
     RECT  150.012 112.955 150.066 113.419 ;
     RECT  39.636 113.269 40.95 113.459 ;
     RECT  149.328 113.419 150.066 113.459 ;
     RECT  152.568 113.305 153.054 113.459 ;
     RECT  148.215 111.875 148.497 113.611 ;
     RECT  148.176 113.611 148.497 113.765 ;
     RECT  36.684 101.219 36.702 113.809 ;
     RECT  26.496 110.759 29.697 113.881 ;
     RECT  36.648 113.809 36.702 113.881 ;
     RECT  147.312 113.467 147.33 113.881 ;
     RECT  37.476 106.889 37.494 113.909 ;
     RECT  150.84 113.225 151.722 113.971 ;
     RECT  152.568 113.459 153.018 113.971 ;
     RECT  147.312 113.881 147.474 113.999 ;
     RECT  148.215 113.765 148.497 114.151 ;
     RECT  36.576 113.881 36.702 114.179 ;
     RECT  148.215 114.151 148.878 114.269 ;
     RECT  26.352 113.881 29.697 114.283 ;
     RECT  30.456 111.209 30.474 114.283 ;
     RECT  148.215 114.269 148.554 114.305 ;
     RECT  146.484 114.151 146.502 114.449 ;
     RECT  150.012 113.459 150.03 114.523 ;
     RECT  33.336 111.181 35.097 114.539 ;
     RECT  150.84 113.971 153.018 114.611 ;
     RECT  26.352 114.283 30.474 114.719 ;
     RECT  39.636 113.459 40.497 114.809 ;
     RECT  150.84 114.611 152.946 114.881 ;
     RECT  26.352 114.719 29.697 114.925 ;
     RECT  36.648 114.179 36.702 114.925 ;
     RECT  33.984 114.539 35.097 114.961 ;
     RECT  35.928 114.925 36.702 114.961 ;
     RECT  149.616 114.523 150.03 114.961 ;
     RECT  150.84 114.881 151.902 114.961 ;
     RECT  149.616 114.961 151.902 114.989 ;
     RECT  0.288 111.065 25.47 115.187 ;
     RECT  26.208 114.925 29.697 115.349 ;
     RECT  26.352 115.349 29.697 115.373 ;
     RECT  152.784 114.881 152.946 115.465 ;
     RECT  64.872 102.271 64.89 115.619 ;
     RECT  148.215 114.305 148.497 115.663 ;
     RECT  150.012 114.989 151.902 115.699 ;
     RECT  152.784 115.465 153.018 115.699 ;
     RECT  148.215 115.663 149.13 115.709 ;
     RECT  150.012 115.699 153.018 115.771 ;
     RECT  33.984 114.961 36.702 115.799 ;
     RECT  146.16 115.771 146.178 115.889 ;
     RECT  149.652 115.771 153.018 115.889 ;
     RECT  69.732 111.955 69.75 115.997 ;
     RECT  150.012 115.889 153.018 116.041 ;
     RECT  154.44 111.437 154.458 116.155 ;
     RECT  154.404 116.155 154.458 116.159 ;
     RECT  26.352 115.373 28.206 116.167 ;
     RECT  26.208 116.167 28.206 116.239 ;
     RECT  29.415 115.373 29.697 116.239 ;
     RECT  150.012 116.041 153.054 116.285 ;
     RECT  33.984 115.799 35.622 116.429 ;
     RECT  154.404 116.159 154.422 116.429 ;
     RECT  151.236 116.285 153.054 116.587 ;
     RECT  30.456 114.719 30.474 116.699 ;
     RECT  151.236 116.587 153.486 116.771 ;
     RECT  150.012 116.285 150.282 116.861 ;
     RECT  151.236 116.771 153.018 116.969 ;
     RECT  150.012 116.861 150.03 117.049 ;
     RECT  146.016 116.041 146.034 117.121 ;
     RECT  53.208 112.205 53.478 117.149 ;
     RECT  146.016 117.121 146.178 117.239 ;
     RECT  149.4 117.049 150.03 117.239 ;
     RECT  152.496 116.969 153.018 117.239 ;
     RECT  151.236 116.969 151.542 117.391 ;
     RECT  146.016 117.239 146.034 117.437 ;
     RECT  149.256 117.391 149.274 117.437 ;
     RECT  66.132 113.845 66.15 117.509 ;
     RECT  0.288 115.187 25.434 117.661 ;
     RECT  26.208 116.239 29.697 117.661 ;
     RECT  38.772 117.751 38.79 117.851 ;
     RECT  43.848 113.341 43.866 117.895 ;
     RECT  43.704 117.895 43.866 117.923 ;
     RECT  150.012 117.239 150.03 117.979 ;
     RECT  66.384 117.661 66.402 118.021 ;
     RECT  67.215 90.617 67.497 118.021 ;
     RECT  147.204 116.401 147.222 118.021 ;
     RECT  66.384 118.021 67.497 118.085 ;
     RECT  70.596 111.839 70.722 118.157 ;
     RECT  146.484 118.021 147.222 118.157 ;
     RECT  149.364 117.979 150.03 118.165 ;
     RECT  150.912 117.391 151.542 118.165 ;
     RECT  152.964 117.239 152.982 118.165 ;
     RECT  66.636 118.085 67.497 118.193 ;
     RECT  149.364 118.165 151.542 118.201 ;
     RECT  152.964 118.165 153.018 118.201 ;
     RECT  148.215 115.709 148.497 118.555 ;
     RECT  149.364 118.201 151.794 118.555 ;
     RECT  148.215 118.555 151.794 118.589 ;
     RECT  152.568 118.201 153.018 118.661 ;
     RECT  151.524 118.589 151.794 118.741 ;
     RECT  152.568 118.661 152.874 118.741 ;
     RECT  154.44 117.013 154.458 118.747 ;
     RECT  53.208 117.149 53.226 118.769 ;
     RECT  148.215 118.589 148.914 118.859 ;
     RECT  151.524 118.741 152.874 118.859 ;
     RECT  148.215 118.859 148.77 118.895 ;
     RECT  152.46 118.859 152.874 118.895 ;
     RECT  153.9 118.747 154.458 118.967 ;
     RECT  154.44 118.967 154.458 119.101 ;
     RECT  150.012 118.589 150.714 119.129 ;
     RECT  152.532 118.895 152.874 119.129 ;
     RECT  147.204 118.157 147.222 119.131 ;
     RECT  154.44 119.101 154.494 119.213 ;
     RECT  54.324 109.421 54.342 119.399 ;
     RECT  152.568 119.129 152.874 119.515 ;
     RECT  151.524 118.859 151.542 119.641 ;
     RECT  75.78 99.571 75.798 119.669 ;
     RECT  147.024 119.131 147.222 120.019 ;
     RECT  148.215 118.895 148.497 120.043 ;
     RECT  149.22 120.019 149.238 120.043 ;
     RECT  150.012 119.129 150.282 120.091 ;
     RECT  31.608 111.407 31.626 120.119 ;
     RECT  146.484 120.019 147.222 120.119 ;
     RECT  146.808 120.119 147.222 120.181 ;
     RECT  147.996 120.043 149.238 120.181 ;
     RECT  0.288 117.661 29.697 120.209 ;
     RECT  146.808 120.181 149.238 120.209 ;
     RECT  146.808 120.209 149.094 120.245 ;
     RECT  152.568 119.515 153.018 120.325 ;
     RECT  146.808 120.245 148.497 120.353 ;
     RECT  150.012 120.091 150.498 120.479 ;
     RECT  152.568 120.325 153.054 120.479 ;
     RECT  28.764 120.209 29.697 120.551 ;
     RECT  151.524 119.641 151.65 120.595 ;
     RECT  152.568 120.479 152.802 120.595 ;
     RECT  154.44 119.213 154.458 120.907 ;
     RECT  146.808 120.353 147.366 121.055 ;
     RECT  153.9 120.907 154.458 121.397 ;
     RECT  151.524 120.595 152.802 121.405 ;
     RECT  150.012 120.479 150.03 121.483 ;
     RECT  34.668 116.429 35.622 121.559 ;
     RECT  146.808 121.055 147.222 121.801 ;
     RECT  148.215 120.353 148.497 121.801 ;
     RECT  70.704 118.157 70.722 121.829 ;
     RECT  151.524 121.405 153.09 121.829 ;
     RECT  150.012 121.483 150.39 121.865 ;
     RECT  146.808 121.801 148.497 122.251 ;
     RECT  146.808 122.251 148.59 122.369 ;
     RECT  151.524 121.829 153.018 122.441 ;
     RECT  146.808 122.369 148.497 122.587 ;
     RECT  145.08 122.587 145.098 122.635 ;
     RECT  154.44 121.397 154.458 122.635 ;
     RECT  146.556 122.587 148.497 122.639 ;
     RECT  146.808 122.639 148.497 122.675 ;
     RECT  144.9 122.635 145.098 122.683 ;
     RECT  61.815 95.675 62.406 122.711 ;
     RECT  45.615 113.189 45.897 122.791 ;
     RECT  144.792 122.683 145.098 122.819 ;
     RECT  153.9 122.635 154.458 122.819 ;
     RECT  144.9 122.819 145.098 122.909 ;
     RECT  45.18 122.791 45.897 123.179 ;
     RECT  150.012 121.865 150.03 123.331 ;
     RECT  151.524 122.441 151.866 123.331 ;
     RECT  152.676 122.441 153.018 123.331 ;
     RECT  72.615 106.051 73.134 123.359 ;
     RECT  78.015 100.781 78.297 123.403 ;
     RECT  77.292 123.403 78.297 123.449 ;
     RECT  149.22 123.331 150.03 123.449 ;
     RECT  151.056 123.331 153.054 123.449 ;
     RECT  152.352 123.449 153.054 123.485 ;
     RECT  74.664 123.403 74.682 123.533 ;
     RECT  148.215 122.675 148.497 123.565 ;
     RECT  76.968 123.529 76.986 123.581 ;
     RECT  151.056 123.449 151.542 123.601 ;
     RECT  148.215 123.565 149.094 123.629 ;
     RECT  45.432 123.179 45.897 123.755 ;
     RECT  150.948 123.601 151.542 123.755 ;
     RECT  149.904 123.449 150.03 123.989 ;
     RECT  34.815 121.559 35.622 124.097 ;
     RECT  154.44 122.819 154.458 124.141 ;
     RECT  151.056 123.755 151.542 124.231 ;
     RECT  152.352 123.485 152.874 124.231 ;
     RECT  31.932 123.763 31.95 124.295 ;
     RECT  154.44 124.141 154.494 124.397 ;
     RECT  36.648 115.799 36.702 124.411 ;
     RECT  146.808 122.675 147.222 124.411 ;
     RECT  148.215 123.629 148.497 124.411 ;
     RECT  52.128 110.779 52.146 124.439 ;
     RECT  151.056 124.231 152.874 124.501 ;
     RECT  146.808 124.411 148.626 124.529 ;
     RECT  0.288 120.209 27.846 124.565 ;
     RECT  151.056 124.501 153.018 124.651 ;
     RECT  36.504 124.411 36.702 124.681 ;
     RECT  149.904 123.989 149.958 124.795 ;
     RECT  150.948 124.651 153.018 124.795 ;
     RECT  146.808 124.529 147.366 124.829 ;
     RECT  150.804 124.795 153.018 124.835 ;
     RECT  149.688 124.795 149.958 124.871 ;
     RECT  36.504 124.681 37.026 125.221 ;
     RECT  154.44 124.397 154.458 125.227 ;
     RECT  149.76 124.871 149.958 125.339 ;
     RECT  154.404 125.227 154.458 125.339 ;
     RECT  148.215 124.529 148.554 125.347 ;
     RECT  149.76 125.339 149.778 125.375 ;
     RECT  36.504 125.221 37.278 125.609 ;
     RECT  151.272 124.835 153.018 125.609 ;
     RECT  152.316 125.609 153.018 125.681 ;
     RECT  151.272 125.609 151.542 125.761 ;
     RECT  148.215 125.347 148.662 125.851 ;
     RECT  150.912 125.761 151.542 125.879 ;
     RECT  152.316 125.681 152.982 125.879 ;
     RECT  146.808 124.829 147.33 125.887 ;
     RECT  26.208 124.565 27.846 125.899 ;
     RECT  36.504 125.609 37.062 125.915 ;
     RECT  149.58 125.761 149.598 125.915 ;
     RECT  151.272 125.879 151.542 125.915 ;
     RECT  146.592 125.887 147.33 125.933 ;
     RECT  152.82 125.879 152.982 125.951 ;
     RECT  148.14 125.851 148.662 125.995 ;
     RECT  148.14 125.995 149.31 126.029 ;
     RECT  149.256 126.029 149.31 126.419 ;
     RECT  0.288 124.565 25.362 126.427 ;
     RECT  26.208 125.899 28.206 126.427 ;
     RECT  148.14 126.029 148.497 126.455 ;
     RECT  149.292 126.419 149.31 126.509 ;
     RECT  0.288 126.427 28.206 126.523 ;
     RECT  0.108 126.523 28.206 126.653 ;
     RECT  155.412 126.523 155.43 126.653 ;
     RECT  152.964 125.951 152.982 126.805 ;
     RECT  151.524 125.915 151.542 126.841 ;
     RECT  152.964 126.805 153.018 126.841 ;
     RECT  150.444 126.283 150.462 126.893 ;
     RECT  30.42 126.769 30.438 126.959 ;
     RECT  151.38 126.841 153.018 126.995 ;
     RECT  0.288 126.653 28.206 127.229 ;
     RECT  29.415 120.551 29.697 127.309 ;
     RECT  0.288 127.229 25.362 127.337 ;
     RECT  30.852 127.075 30.87 127.381 ;
     RECT  150.624 127.345 150.642 127.381 ;
     RECT  151.38 126.995 152.262 127.381 ;
     RECT  26.208 127.229 28.206 127.471 ;
     RECT  30.852 127.381 31.194 127.535 ;
     RECT  146.808 125.933 147.33 127.579 ;
     RECT  31.068 127.535 31.194 127.607 ;
     RECT  146.808 127.579 147.438 127.675 ;
     RECT  34.815 124.097 35.097 127.741 ;
     RECT  150.624 127.381 152.262 127.769 ;
     RECT  149.832 127.885 149.85 127.921 ;
     RECT  151.524 127.769 152.262 127.921 ;
     RECT  153 126.995 153.018 127.921 ;
     RECT  149.832 127.921 150.498 127.949 ;
     RECT  150.48 127.949 150.498 128.039 ;
     RECT  151.524 127.921 153.018 128.039 ;
     RECT  146.268 127.675 147.438 128.075 ;
     RECT  153 128.039 153.018 128.111 ;
     RECT  34.092 127.741 35.097 128.155 ;
     RECT  0.288 127.337 25.074 128.191 ;
     RECT  26.208 127.471 28.35 128.191 ;
     RECT  29.124 127.309 29.697 128.191 ;
     RECT  146.808 128.075 147.438 128.191 ;
     RECT  148.215 126.455 148.497 128.191 ;
     RECT  33.768 128.155 35.097 128.309 ;
     RECT  68.436 120.361 68.454 128.345 ;
     RECT  33.768 128.309 33.858 128.461 ;
     RECT  69.264 126.229 69.282 128.461 ;
     RECT  33.66 128.461 33.858 128.579 ;
     RECT  0.288 128.191 25.362 128.659 ;
     RECT  26.208 128.191 29.697 128.659 ;
     RECT  0.288 128.659 29.697 128.683 ;
     RECT  151.524 128.039 152.154 128.731 ;
     RECT  38.196 128.875 38.214 128.921 ;
     RECT  146.808 128.191 148.662 128.965 ;
     RECT  36.504 125.915 36.522 128.971 ;
     RECT  37.44 128.587 37.458 128.971 ;
     RECT  146.808 128.965 148.986 129.001 ;
     RECT  150.12 128.725 150.138 129.001 ;
     RECT  151.344 128.731 152.154 129.001 ;
     RECT  153.036 129.001 153.054 129.115 ;
     RECT  31.068 127.607 31.122 129.119 ;
     RECT  151.056 129.001 152.154 129.119 ;
     RECT  154.44 125.339 154.458 129.119 ;
     RECT  64.008 125.113 64.026 129.155 ;
     RECT  151.524 129.119 152.154 129.235 ;
     RECT  153.036 129.115 153.558 129.235 ;
     RECT  31.104 129.119 31.122 129.271 ;
     RECT  146.808 129.001 149.058 129.271 ;
     RECT  149.904 129.001 150.138 129.271 ;
     RECT  151.524 129.235 153.558 129.299 ;
     RECT  38.844 129.001 38.862 129.389 ;
     RECT  53.28 118.831 53.298 129.425 ;
     RECT  146.808 129.271 150.498 129.425 ;
     RECT  36.504 128.971 37.458 129.451 ;
     RECT  68.58 128.461 69.282 129.541 ;
     RECT  0.108 128.683 29.697 129.767 ;
     RECT  36.504 129.451 37.998 129.929 ;
     RECT  146.808 129.425 150.282 129.929 ;
     RECT  26.208 129.767 29.697 129.965 ;
     RECT  0.108 129.767 25.362 130.013 ;
     RECT  154.476 129.361 154.494 130.013 ;
     RECT  151.524 129.299 153.018 130.045 ;
     RECT  36.504 129.929 37.206 130.307 ;
     RECT  31.104 129.271 31.194 130.351 ;
     RECT  151.524 130.045 153.054 130.351 ;
     RECT  45.576 123.755 45.897 130.379 ;
     RECT  146.808 129.929 149.382 130.379 ;
     RECT  146.808 130.379 149.31 130.469 ;
     RECT  151.2 130.351 153.054 130.469 ;
     RECT  68.58 129.541 69.57 130.505 ;
     RECT  151.2 130.469 151.542 130.505 ;
     RECT  31.104 130.351 31.338 130.739 ;
     RECT  146.808 130.469 149.13 130.775 ;
     RECT  0.288 130.013 25.362 130.783 ;
     RECT  33.66 128.579 33.678 130.811 ;
     RECT  150.264 129.929 150.282 130.891 ;
     RECT  150.084 130.891 150.57 131.009 ;
     RECT  150.084 131.009 150.102 131.045 ;
     RECT  146.808 130.775 148.662 131.227 ;
     RECT  0.288 130.783 25.686 131.459 ;
     RECT  146.664 131.227 148.662 131.521 ;
     RECT  151.524 130.505 151.542 131.521 ;
     RECT  152.568 130.469 153.018 131.521 ;
     RECT  146.484 131.521 148.662 131.657 ;
     RECT  151.524 131.521 153.018 131.701 ;
     RECT  149.976 131.521 149.994 131.935 ;
     RECT  151.164 131.701 153.018 132.089 ;
     RECT  149.868 131.935 149.994 132.097 ;
     RECT  26.496 129.965 29.697 132.125 ;
     RECT  151.164 132.089 152.154 132.511 ;
     RECT  26.496 132.125 27.666 132.539 ;
     RECT  0.288 131.459 25.362 132.571 ;
     RECT  0.108 132.571 25.362 132.665 ;
     RECT  149.868 132.097 150.174 132.811 ;
     RECT  150.948 132.511 152.154 132.811 ;
     RECT  147.204 131.657 148.662 132.901 ;
     RECT  147.204 132.901 148.698 133.051 ;
     RECT  149.868 132.811 152.154 133.051 ;
     RECT  0.288 132.665 25.362 133.079 ;
     RECT  149.652 133.051 152.154 133.141 ;
     RECT  153 132.089 153.018 133.141 ;
     RECT  149.652 133.141 153.018 133.169 ;
     RECT  149.652 133.169 152.91 133.205 ;
     RECT  149.76 133.205 152.91 133.241 ;
     RECT  146.484 133.051 148.698 133.313 ;
     RECT  149.76 133.241 152.154 133.313 ;
     RECT  147.204 133.313 148.698 133.321 ;
     RECT  150.912 133.313 152.154 133.349 ;
     RECT  147.204 133.321 148.806 133.387 ;
     RECT  147.204 133.387 148.986 133.439 ;
     RECT  0.288 133.079 24.714 133.483 ;
     RECT  27.036 132.539 27.666 134.015 ;
     RECT  151.524 133.349 152.154 134.095 ;
     RECT  152.892 133.241 152.91 134.095 ;
     RECT  149.76 133.313 149.886 134.131 ;
     RECT  151.524 134.095 152.91 134.131 ;
     RECT  150.66 134.131 152.91 134.249 ;
     RECT  149.724 134.131 149.886 134.285 ;
     RECT  150.66 134.249 152.154 134.285 ;
     RECT  45.615 130.379 45.897 134.365 ;
     RECT  43.704 117.923 43.722 134.393 ;
     RECT  149.76 134.285 149.886 134.519 ;
     RECT  149.76 134.519 149.778 134.525 ;
     RECT  153 134.365 153.018 134.635 ;
     RECT  153 134.635 153.054 134.671 ;
     RECT  154.44 130.351 154.458 134.789 ;
     RECT  0.252 133.483 24.714 134.825 ;
     RECT  59.904 127.381 59.922 134.969 ;
     RECT  53.712 134.539 53.73 135.059 ;
     RECT  150.768 134.285 152.154 135.061 ;
     RECT  150.732 135.061 152.154 135.101 ;
     RECT  55.26 135.067 55.278 135.104 ;
     RECT  153 134.671 153.234 135.197 ;
     RECT  150.84 135.101 152.154 135.211 ;
     RECT  153 135.197 153.054 135.211 ;
     RECT  34.815 128.309 35.097 135.373 ;
     RECT  27.036 134.015 27.054 135.401 ;
     RECT  150.84 135.211 153.054 135.599 ;
     RECT  150.84 135.599 152.586 135.635 ;
     RECT  0.252 134.825 24.534 135.643 ;
     RECT  150.84 135.635 152.442 135.905 ;
     RECT  147.204 133.439 148.626 136.021 ;
     RECT  147.204 136.021 148.77 136.139 ;
     RECT  45.108 134.365 45.897 136.175 ;
     RECT  45.36 136.175 45.897 136.211 ;
     RECT  150.048 135.595 150.066 136.219 ;
     RECT  150.048 136.219 150.534 136.291 ;
     RECT  149.976 136.291 150.534 136.409 ;
     RECT  150.048 136.409 150.066 136.445 ;
     RECT  154.44 135.595 154.458 136.493 ;
     RECT  151.524 135.905 152.442 136.561 ;
     RECT  0.252 135.643 24.714 136.759 ;
     RECT  25.92 133.321 25.938 136.759 ;
     RECT  151.524 136.561 152.55 136.795 ;
     RECT  147.204 136.139 148.698 136.921 ;
     RECT  154.476 136.759 154.494 136.925 ;
     RECT  151.524 136.795 153.054 137.065 ;
     RECT  146.484 136.921 148.698 137.461 ;
     RECT  149.904 137.371 150.066 137.489 ;
     RECT  150.84 137.065 153.054 137.489 ;
     RECT  146.484 137.461 148.842 137.501 ;
     RECT  149.904 137.489 149.922 137.501 ;
     RECT  0.252 136.759 25.938 137.525 ;
     RECT  25.488 137.525 25.938 137.669 ;
     RECT  146.484 137.501 148.698 137.669 ;
     RECT  149.76 137.641 149.778 137.795 ;
     RECT  150.84 137.489 152.946 137.795 ;
     RECT  151.128 137.795 152.946 137.831 ;
     RECT  151.128 137.831 151.542 137.867 ;
     RECT  152.568 137.831 152.946 138.029 ;
     RECT  147.204 137.669 148.698 138.451 ;
     RECT  0.252 137.525 24.534 138.541 ;
     RECT  151.524 137.867 151.542 138.685 ;
     RECT  150.84 138.685 151.542 138.721 ;
     RECT  147.204 138.451 149.418 138.749 ;
     RECT  152.568 138.029 152.874 138.955 ;
     RECT  150.84 138.721 151.83 138.991 ;
     RECT  152.568 138.955 153.054 138.991 ;
     RECT  154.44 137.323 154.458 138.991 ;
     RECT  154.44 138.991 154.494 139.051 ;
     RECT  150.84 138.991 153.054 139.109 ;
     RECT  154.404 139.051 154.494 139.109 ;
     RECT  34.74 135.373 35.097 139.145 ;
     RECT  36.504 130.307 37.062 139.261 ;
     RECT  40.215 114.809 40.497 139.483 ;
     RECT  154.44 139.109 154.494 139.517 ;
     RECT  147.204 138.749 148.698 139.531 ;
     RECT  150.84 139.109 151.83 139.531 ;
     RECT  147.204 139.531 149.274 139.621 ;
     RECT  150.588 139.531 151.83 139.621 ;
     RECT  147.204 139.621 151.83 139.649 ;
     RECT  40.215 139.483 40.59 139.661 ;
     RECT  70.704 139.621 71.262 139.661 ;
     RECT  147.204 139.649 150.606 139.661 ;
     RECT  149.832 139.661 150.606 139.685 ;
     RECT  152.568 139.109 153.054 139.721 ;
     RECT  0.252 138.541 24.606 139.919 ;
     RECT  149.832 139.685 149.922 139.919 ;
     RECT  152.856 139.721 153.054 139.919 ;
     RECT  149.904 139.919 149.922 139.955 ;
     RECT  151.524 139.649 151.83 140.071 ;
     RECT  147.204 139.661 148.77 140.189 ;
     RECT  147.204 140.189 148.626 140.225 ;
     RECT  154.44 139.517 154.458 140.347 ;
     RECT  153.9 140.347 154.458 140.531 ;
     RECT  151.524 140.071 152.01 140.575 ;
     RECT  151.524 140.575 152.622 140.611 ;
     RECT  37.98 129.929 37.998 140.639 ;
     RECT  154.44 140.531 154.458 140.701 ;
     RECT  151.02 140.611 152.622 140.728 ;
     RECT  150.84 140.728 152.622 140.737 ;
     RECT  154.44 140.701 154.494 140.813 ;
     RECT  24.015 139.919 24.606 140.837 ;
     RECT  149.76 140.731 149.778 140.845 ;
     RECT  149.4 140.845 149.778 140.873 ;
     RECT  0.252 139.919 23.094 140.909 ;
     RECT  150.84 140.737 152.982 141.035 ;
     RECT  0.252 140.909 21.114 141.211 ;
     RECT  0.108 141.211 21.114 141.269 ;
     RECT  150.336 141.151 150.642 141.269 ;
     RECT  151.416 141.035 152.982 141.269 ;
     RECT  150.336 141.269 150.498 141.305 ;
     RECT  151.524 141.269 152.982 141.385 ;
     RECT  0.108 141.269 20.97 141.413 ;
     RECT  147.204 140.225 148.59 141.421 ;
     RECT  151.524 141.385 153.054 141.539 ;
     RECT  146.7 141.421 148.59 141.643 ;
     RECT  146.556 141.643 148.59 141.719 ;
     RECT  147.204 141.719 148.59 141.739 ;
     RECT  149.4 140.873 149.418 141.739 ;
     RECT  150.48 141.305 150.498 141.809 ;
     RECT  0.108 141.413 20.538 141.845 ;
     RECT  147.204 141.739 149.418 141.961 ;
     RECT  36.18 139.261 37.062 141.989 ;
     RECT  154.44 140.813 154.458 142.075 ;
     RECT  147.204 141.961 149.49 142.079 ;
     RECT  151.524 141.539 153.018 142.195 ;
     RECT  147.204 142.079 149.346 142.493 ;
     RECT  150.516 142.195 153.018 142.493 ;
     RECT  151.488 142.493 153.018 142.771 ;
     RECT  150.516 142.493 150.714 142.889 ;
     RECT  150.516 142.889 150.534 142.925 ;
     RECT  149.904 143.041 149.922 143.195 ;
     RECT  153.9 142.075 154.458 143.267 ;
     RECT  147.204 142.493 148.842 143.401 ;
     RECT  64.152 129.271 64.17 143.699 ;
     RECT  151.488 142.771 153.054 143.699 ;
     RECT  144.792 143.671 144.81 143.807 ;
     RECT  151.488 143.699 152.586 143.815 ;
     RECT  21.852 140.909 23.094 143.879 ;
     RECT  21.852 143.879 22.806 143.969 ;
     RECT  147.204 143.401 149.67 143.969 ;
     RECT  150.84 143.815 152.586 143.969 ;
     RECT  22.068 143.969 22.806 144.005 ;
     RECT  150.84 143.969 151.614 144.005 ;
     RECT  24.015 140.837 24.534 144.121 ;
     RECT  150.84 144.005 151.578 144.121 ;
     RECT  147.204 143.969 149.526 144.221 ;
     RECT  0.252 141.845 20.538 144.235 ;
     RECT  150.624 144.121 151.578 144.239 ;
     RECT  0.108 144.235 20.538 144.275 ;
     RECT  22.068 144.005 22.59 144.275 ;
     RECT  150.624 144.239 150.642 144.275 ;
     RECT  23.616 144.121 24.534 144.419 ;
     RECT  152.496 143.969 152.586 144.481 ;
     RECT  147.204 144.221 148.986 144.509 ;
     RECT  152.496 144.481 153.018 144.509 ;
     RECT  150.264 144.661 150.282 144.815 ;
     RECT  147.204 144.509 148.806 144.845 ;
     RECT  22.32 144.275 22.59 144.923 ;
     RECT  24.015 144.419 24.534 144.959 ;
     RECT  151.524 144.239 151.542 145.021 ;
     RECT  147.204 144.845 148.734 145.049 ;
     RECT  0.252 144.275 20.538 145.057 ;
     RECT  0.108 145.057 20.538 145.133 ;
     RECT  151.524 145.021 151.722 145.291 ;
     RECT  153 144.509 153.018 145.291 ;
     RECT  154.44 143.267 154.458 145.589 ;
     RECT  0.252 145.133 20.538 145.705 ;
     RECT  0.252 145.705 20.574 145.741 ;
     RECT  69.516 130.505 69.57 145.769 ;
     RECT  150.696 145.741 150.714 145.867 ;
     RECT  150.516 145.867 150.714 145.904 ;
     RECT  154.476 145.903 154.494 145.997 ;
     RECT  151.524 145.291 153.018 146.173 ;
     RECT  36.18 141.989 36.522 146.201 ;
     RECT  0.252 145.741 20.718 146.209 ;
     RECT  148.215 145.049 148.734 146.245 ;
     RECT  148.215 146.245 148.842 146.281 ;
     RECT  0.252 146.209 20.754 146.479 ;
     RECT  148.215 146.281 149.526 146.491 ;
     RECT  147.204 145.049 147.438 146.821 ;
     RECT  148.215 146.491 149.634 146.821 ;
     RECT  150.84 146.173 153.018 146.821 ;
     RECT  154.44 146.395 154.458 146.827 ;
     RECT  147.204 146.821 149.634 146.939 ;
     RECT  150.552 146.821 153.054 146.975 ;
     RECT  36.504 146.201 36.522 147.353 ;
     RECT  68.58 130.505 68.598 147.389 ;
     RECT  148.215 146.939 149.634 147.479 ;
     RECT  150.552 146.975 153.018 147.595 ;
     RECT  148.215 147.479 149.022 147.629 ;
     RECT  154.404 146.827 154.458 147.691 ;
     RECT  149.832 147.595 153.018 147.785 ;
     RECT  153.9 147.691 154.458 147.857 ;
     RECT  69.516 145.769 69.534 148.019 ;
     RECT  149.832 147.785 149.85 148.205 ;
     RECT  22.572 144.923 22.59 148.289 ;
     RECT  147.204 146.939 147.438 148.405 ;
     RECT  148.215 147.629 148.77 148.405 ;
     RECT  154.44 147.857 154.458 148.595 ;
     RECT  150.876 147.785 152.874 148.675 ;
     RECT  0.252 146.479 20.826 148.901 ;
     RECT  150.876 148.675 152.91 148.945 ;
     RECT  153.9 148.981 153.918 149.021 ;
     RECT  150.876 148.945 153.054 149.131 ;
     RECT  150.228 149.131 153.054 149.171 ;
     RECT  151.164 149.171 153.054 149.369 ;
     RECT  0.252 148.901 20.754 149.377 ;
     RECT  0.108 149.377 20.754 149.453 ;
     RECT  147.204 148.405 148.77 149.755 ;
     RECT  150.228 149.171 150.246 149.791 ;
     RECT  154.44 149.419 154.458 149.791 ;
     RECT  154.44 149.791 154.494 149.909 ;
     RECT  147.204 149.755 148.842 150.061 ;
     RECT  149.652 149.791 150.246 150.061 ;
     RECT  151.164 149.369 153.018 150.061 ;
     RECT  151.02 150.061 153.018 150.179 ;
     RECT  146.484 150.061 150.246 150.259 ;
     RECT  151.02 150.179 152.982 150.259 ;
     RECT  0.252 149.453 20.754 150.283 ;
     RECT  154.476 149.909 154.494 150.317 ;
     RECT  146.484 150.259 152.982 150.359 ;
     RECT  31.32 130.739 31.338 150.449 ;
     RECT  146.484 150.359 149.67 150.449 ;
     RECT  150.444 150.359 152.982 150.449 ;
     RECT  148.215 150.449 149.67 150.461 ;
     RECT  0.108 150.283 20.754 150.475 ;
     RECT  146.484 150.449 147.366 150.485 ;
     RECT  150.84 150.449 152.982 150.485 ;
     RECT  25.92 137.669 25.938 150.791 ;
     RECT  146.484 150.485 147.222 150.863 ;
     RECT  151.524 150.485 152.982 150.989 ;
     RECT  0.108 150.475 21.042 151.025 ;
     RECT  0.252 151.025 21.042 151.141 ;
     RECT  148.215 150.461 149.346 151.267 ;
     RECT  0.252 151.141 21.438 151.367 ;
     RECT  21.42 151.367 21.438 151.411 ;
     RECT  148.215 151.267 149.49 151.411 ;
     RECT  21.42 151.411 21.69 151.529 ;
     RECT  21.42 151.529 21.438 151.565 ;
     RECT  148.215 151.411 150.426 151.565 ;
     RECT  148.215 151.565 149.49 151.799 ;
     RECT  152.424 150.989 152.442 151.807 ;
     RECT  148.215 151.799 149.346 151.835 ;
     RECT  152.424 151.807 152.838 151.879 ;
     RECT  154.44 150.691 154.458 151.951 ;
     RECT  153.9 151.951 154.458 152.045 ;
     RECT  151.524 150.989 151.65 152.077 ;
     RECT  152.424 151.879 152.91 152.077 ;
     RECT  151.524 152.077 152.91 152.105 ;
     RECT  151.524 152.105 152.226 152.339 ;
     RECT  148.215 151.835 149.31 152.455 ;
     RECT  0.252 151.367 20.682 152.491 ;
     RECT  147.204 150.863 147.222 152.581 ;
     RECT  28.836 132.125 29.697 152.609 ;
     RECT  148.212 152.455 149.31 152.609 ;
     RECT  148.212 152.609 149.166 152.645 ;
     RECT  146.484 152.581 147.222 152.717 ;
     RECT  0.252 152.491 20.754 152.725 ;
     RECT  149.904 152.731 149.922 152.761 ;
     RECT  151.524 152.339 151.794 152.761 ;
     RECT  153.036 152.725 153.054 152.851 ;
     RECT  154.44 152.045 154.458 152.875 ;
     RECT  152.568 152.851 153.054 152.879 ;
     RECT  151.164 152.761 151.794 152.959 ;
     RECT  149.904 152.761 150.246 153.031 ;
     RECT  151.056 152.959 151.794 153.031 ;
     RECT  147.204 152.717 147.222 153.115 ;
     RECT  0.252 152.725 20.79 153.149 ;
     RECT  147.204 153.115 147.294 153.157 ;
     RECT  148.212 152.645 148.842 153.157 ;
     RECT  147.204 153.157 148.842 153.257 ;
     RECT  149.904 153.031 151.794 153.329 ;
     RECT  147.348 153.257 148.806 153.419 ;
     RECT  153.864 152.875 154.458 153.419 ;
     RECT  149.904 153.329 150.534 153.571 ;
     RECT  152.568 152.879 152.91 153.571 ;
     RECT  149.544 153.571 150.534 153.689 ;
     RECT  147.348 153.419 148.626 153.725 ;
     RECT  149.544 153.689 149.562 153.725 ;
     RECT  147.348 153.725 148.497 153.731 ;
     RECT  151.524 153.329 151.794 153.841 ;
     RECT  152.532 153.571 152.91 153.841 ;
     RECT  103.464 153.883 103.482 154.075 ;
     RECT  105.015 2.413 105.297 154.111 ;
     RECT  146.484 154.039 146.502 154.111 ;
     RECT  150.516 153.689 150.534 154.111 ;
     RECT  151.524 153.841 152.91 154.111 ;
     RECT  146.484 154.111 146.574 154.139 ;
     RECT  153.864 153.419 154.422 154.171 ;
     RECT  103.464 154.075 103.626 154.229 ;
     RECT  104.4 154.111 105.297 154.265 ;
     RECT  146.556 154.139 146.574 154.265 ;
     RECT  150.516 154.111 152.91 154.265 ;
     RECT  103.608 154.229 103.626 154.301 ;
     RECT  128.808 154.237 128.826 154.301 ;
     RECT  150.696 154.265 150.714 154.301 ;
     RECT  151.452 154.265 152.91 154.301 ;
     RECT  104.724 154.265 105.297 154.409 ;
     RECT  0.252 153.149 20.754 154.499 ;
     RECT  151.884 154.301 152.91 154.499 ;
     RECT  153.864 154.171 154.458 154.499 ;
     RECT  72.615 123.359 72.897 154.501 ;
     RECT  99.615 97.808 99.897 154.507 ;
     RECT  151.884 154.499 152.766 154.535 ;
     RECT  101.736 154.471 101.754 154.541 ;
     RECT  99.615 154.507 100.206 154.544 ;
     RECT  152.46 154.535 152.766 154.571 ;
     RECT  72.615 154.501 73.206 154.651 ;
     RECT  152.46 154.571 152.478 154.769 ;
     RECT  154.44 154.499 154.458 154.769 ;
     RECT  72.615 154.651 73.53 155.021 ;
     RECT  88.815 2.413 89.097 155.035 ;
     RECT  88.164 155.035 89.097 155.309 ;
     RECT  88.344 155.309 89.097 155.357 ;
     RECT  0.252 154.499 20.646 155.695 ;
     RECT  0.252 155.695 20.754 156.119 ;
     RECT  40.215 139.661 40.497 156.475 ;
     RECT  67.215 118.193 67.497 156.475 ;
     RECT  40.14 156.475 40.497 156.631 ;
     RECT  40.14 156.631 40.518 156.659 ;
     RECT  67.104 156.475 67.497 156.659 ;
     RECT  68.76 156.187 68.778 156.659 ;
     RECT  40.215 156.659 40.518 156.701 ;
     RECT  0.252 156.119 20.538 159.701 ;
     RECT  0.252 159.701 19.854 159.773 ;
     RECT  145.044 152.851 145.062 160.709 ;
     RECT  64.44 160.591 64.458 160.745 ;
     RECT  0.252 159.773 19.602 161.429 ;
     RECT  83.415 2.413 83.697 161.761 ;
     RECT  82.98 161.761 83.697 161.797 ;
     RECT  63.396 161.761 63.414 161.837 ;
     RECT  82.98 161.797 84.114 161.837 ;
     RECT  147.888 153.731 148.497 162.059 ;
     RECT  64.44 162.175 64.458 162.437 ;
     RECT  0.252 161.429 19.386 162.779 ;
     RECT  0.252 162.779 18.99 162.811 ;
     RECT  0.108 162.811 18.99 162.941 ;
     RECT  0.252 162.941 18.99 164.219 ;
     RECT  0.252 164.219 18.897 164.489 ;
     RECT  34.815 139.145 35.097 164.725 ;
     RECT  24.015 144.959 24.297 164.731 ;
     RECT  45.615 136.211 45.897 164.731 ;
     RECT  56.415 111.029 56.697 164.731 ;
     RECT  67.215 156.659 67.497 164.731 ;
     RECT  34.704 164.725 35.097 164.765 ;
     RECT  23.904 164.731 24.297 164.768 ;
     RECT  45.504 164.731 45.897 164.768 ;
     RECT  56.304 164.731 56.697 164.768 ;
     RECT  67.104 164.731 67.497 164.768 ;
     RECT  0.252 164.489 17.73 164.861 ;
     RECT  70.704 164.731 70.722 164.861 ;
     RECT  11.556 164.861 17.73 164.903 ;
     RECT  11.556 164.903 16.542 165.029 ;
     RECT  17.316 164.903 17.73 165.029 ;
     RECT  11.556 165.029 11.862 165.101 ;
     RECT  17.316 165.029 17.55 165.173 ;
     RECT  11.628 165.101 11.862 165.209 ;
     RECT  12.744 165.029 16.542 165.209 ;
     RECT  11.628 165.209 11.79 165.299 ;
     RECT  13.176 165.209 16.542 165.299 ;
     RECT  11.772 165.299 11.79 165.479 ;
     RECT  13.215 165.299 15.03 165.479 ;
     RECT  0.252 164.861 10.782 165.713 ;
     RECT  14.436 165.479 15.03 165.713 ;
     RECT  15.912 165.299 15.93 166.423 ;
     RECT  0.252 165.713 10.422 166.451 ;
     RECT  15.444 166.423 15.93 166.451 ;
     RECT  78.015 123.449 78.297 167.431 ;
     RECT  74.664 167.467 74.682 167.567 ;
     RECT  91.62 154.273 91.638 170.969 ;
     RECT  18.615 164.489 18.897 170.971 ;
     RECT  0.252 166.451 10.314 170.977 ;
     RECT  104.796 154.409 105.297 171.005 ;
     RECT  0.108 170.977 10.314 171.053 ;
     RECT  13.215 165.479 13.497 171.211 ;
     RECT  14.436 165.713 14.454 171.211 ;
     RECT  15.444 166.451 15.462 171.211 ;
     RECT  13.104 171.211 13.497 171.248 ;
     RECT  14.436 171.211 15.462 171.341 ;
     RECT  18.615 170.971 19.53 171.341 ;
     RECT  14.436 171.341 14.454 171.779 ;
     RECT  22.392 173.851 22.41 173.911 ;
     RECT  22.392 173.911 22.842 173.939 ;
     RECT  22.824 173.939 22.842 173.981 ;
     RECT  0.252 171.053 10.314 174.551 ;
     RECT  0.252 174.551 10.278 176.107 ;
     RECT  0.108 176.107 10.278 176.237 ;
     RECT  0.252 176.237 10.278 181.483 ;
     RECT  0.252 181.483 10.818 181.613 ;
     RECT  0.252 181.613 10.278 181.777 ;
     RECT  0.108 181.777 10.278 181.853 ;
     RECT  0.252 181.853 10.278 183.505 ;
     RECT  0.108 183.505 10.278 183.581 ;
     RECT  78.015 167.431 78.93 187.439 ;
     RECT  0.252 183.581 10.278 191.939 ;
     RECT  15.444 171.341 15.462 192.569 ;
     RECT  2.304 191.939 10.278 193.145 ;
     RECT  2.34 193.145 10.278 193.915 ;
     RECT  2.304 193.915 10.278 194.495 ;
     RECT  2.34 194.495 10.278 194.621 ;
     RECT  2.412 194.621 10.278 195.643 ;
     RECT  2.304 195.643 10.278 195.683 ;
     RECT  2.376 195.683 10.278 196.465 ;
     RECT  2.304 196.465 10.278 196.541 ;
     RECT  2.415 196.541 10.278 197.371 ;
     RECT  2.304 197.371 10.278 197.465 ;
     RECT  0.252 191.939 1.134 197.743 ;
     RECT  0.108 197.743 1.134 197.837 ;
     RECT  2.415 197.465 10.278 198.625 ;
     RECT  2.304 198.625 10.278 198.701 ;
     RECT  2.412 198.701 10.278 199.531 ;
     RECT  2.304 199.531 10.278 200.003 ;
     RECT  2.412 200.003 10.278 200.827 ;
     RECT  78.015 187.439 78.822 201.217 ;
     RECT  78.015 201.217 78.966 201.749 ;
     RECT  2.304 200.827 10.278 202.349 ;
     RECT  2.34 202.349 10.278 202.637 ;
     RECT  0.252 197.837 1.134 202.837 ;
     RECT  0.108 202.837 1.134 203.021 ;
     RECT  2.415 202.637 10.278 203.851 ;
     RECT  2.304 203.851 10.278 206.155 ;
     RECT  2.268 206.155 10.278 206.375 ;
     RECT  2.34 206.375 10.278 207.307 ;
     RECT  0.252 203.021 1.134 207.599 ;
     RECT  2.304 207.307 10.278 208.265 ;
     RECT  0.252 207.599 1.098 208.579 ;
     RECT  0.108 208.579 1.098 208.637 ;
     RECT  2.34 208.265 10.278 209.467 ;
     RECT  2.304 209.467 10.278 209.933 ;
     RECT  2.34 209.933 10.278 211.195 ;
     RECT  2.304 211.195 10.278 211.469 ;
     RECT  2.304 211.469 9.234 211.661 ;
     RECT  2.34 211.661 9.234 212.549 ;
     RECT  2.34 212.549 9.198 213.355 ;
     RECT  2.304 213.355 9.198 213.395 ;
     RECT  0.252 208.637 1.098 213.709 ;
     RECT  0.108 213.709 1.098 213.821 ;
     RECT  2.34 213.395 9.198 214.177 ;
     RECT  2.304 214.177 9.198 214.315 ;
     RECT  0.252 213.821 1.098 214.619 ;
     RECT  78.015 201.749 78.786 215.221 ;
     RECT  77.904 215.221 78.786 215.401 ;
     RECT  77.832 215.401 78.786 215.491 ;
     RECT  77.256 215.491 78.786 215.789 ;
     RECT  2.232 214.315 9.198 216.095 ;
     RECT  77.256 215.789 78.39 216.095 ;
     RECT  77.256 216.095 78.354 216.211 ;
     RECT  3.456 216.095 9.198 216.329 ;
     RECT  76.86 216.211 78.354 216.329 ;
     RECT  76.716 216.331 76.734 216.371 ;
     RECT  77.58 216.329 78.354 216.599 ;
     RECT  77.904 216.599 78.354 216.869 ;
     RECT  2.232 216.095 2.697 216.985 ;
     RECT  3.456 216.329 6.678 216.985 ;
     RECT  0.504 214.619 1.098 217.147 ;
     RECT  0.108 217.147 1.098 217.277 ;
     RECT  2.232 216.985 6.678 218.605 ;
     RECT  2.232 218.605 6.786 218.641 ;
     RECT  7.524 216.329 9.198 218.641 ;
     RECT  2.232 218.641 9.198 219.299 ;
     RECT  2.232 219.299 6.678 220.123 ;
     RECT  7.524 219.299 9.198 220.123 ;
     RECT  2.232 220.123 9.198 220.205 ;
     RECT  2.304 220.205 9.198 220.919 ;
     RECT  2.304 220.919 9.162 221.729 ;
     RECT  2.304 221.729 6.678 222.575 ;
     RECT  0.504 217.277 1.098 222.853 ;
     RECT  0.108 222.853 1.098 222.893 ;
     RECT  2.412 222.575 6.678 223.349 ;
     RECT  2.412 223.349 5.742 223.385 ;
     RECT  0.504 222.893 1.098 224.033 ;
     RECT  2.415 223.385 5.742 224.155 ;
     RECT  6.48 223.349 6.678 224.545 ;
     RECT  7.524 221.729 9.162 224.545 ;
     RECT  2.412 224.155 5.742 224.587 ;
     RECT  6.48 224.545 9.162 224.699 ;
     RECT  2.304 224.587 5.742 224.851 ;
     RECT  6.48 224.699 6.678 224.851 ;
     RECT  2.304 224.851 6.678 224.969 ;
     RECT  2.304 224.969 5.742 225.545 ;
     RECT  2.412 225.545 5.742 225.751 ;
     RECT  6.48 224.969 6.678 225.751 ;
     RECT  2.412 225.751 6.678 225.923 ;
     RECT  2.415 225.923 6.678 226.021 ;
     RECT  7.524 224.699 9.162 226.021 ;
     RECT  2.415 226.021 9.162 226.589 ;
     RECT  2.415 226.589 6.498 226.747 ;
     RECT  2.304 226.747 6.498 226.859 ;
     RECT  0.54 224.033 1.098 227.237 ;
     RECT  2.304 226.859 2.697 227.705 ;
     RECT  2.415 227.705 2.697 227.851 ;
     RECT  3.456 226.859 6.498 227.851 ;
     RECT  7.344 226.589 9.162 227.851 ;
     RECT  2.415 227.851 9.162 227.939 ;
     RECT  0.54 227.237 1.062 227.947 ;
     RECT  0.108 227.947 1.062 228.077 ;
     RECT  2.415 227.939 6.57 228.557 ;
     RECT  0.54 228.077 1.062 228.659 ;
     RECT  2.415 228.557 6.498 228.907 ;
     RECT  2.304 228.907 6.498 229.325 ;
     RECT  3.456 229.325 6.498 229.945 ;
     RECT  7.344 227.939 9.162 229.945 ;
     RECT  2.304 229.325 2.697 230.485 ;
     RECT  3.456 229.945 9.162 230.485 ;
     RECT  2.304 230.485 9.162 230.909 ;
     RECT  2.304 230.909 8.586 231.719 ;
     RECT  77.904 216.869 78.297 231.827 ;
     RECT  2.304 231.719 6.498 231.989 ;
     RECT  2.304 231.989 5.598 232.025 ;
     RECT  6.48 231.989 6.498 232.537 ;
     RECT  7.815 231.719 8.586 232.537 ;
     RECT  10.26 211.469 10.278 232.565 ;
     RECT  6.48 232.537 8.586 232.795 ;
     RECT  2.415 232.025 5.598 233.105 ;
     RECT  2.415 233.105 2.697 233.227 ;
     RECT  3.492 233.105 5.598 233.491 ;
     RECT  6.336 232.795 8.586 233.491 ;
     RECT  3.492 233.491 8.586 233.609 ;
     RECT  1.008 228.659 1.062 233.789 ;
     RECT  2.304 233.227 2.697 233.851 ;
     RECT  3.492 233.609 8.097 233.851 ;
     RECT  2.304 233.851 8.097 234.149 ;
     RECT  2.304 234.149 5.598 234.185 ;
     RECT  3.492 234.185 5.598 234.455 ;
     RECT  3.636 234.455 5.598 234.491 ;
     RECT  3.96 234.491 5.598 235.075 ;
     RECT  6.48 234.149 8.097 235.075 ;
     RECT  1.008 233.789 1.026 235.139 ;
     RECT  2.304 234.185 2.697 235.421 ;
     RECT  3.96 235.075 8.097 235.535 ;
     RECT  2.34 235.421 2.697 235.615 ;
     RECT  2.34 235.615 3.438 236.251 ;
     RECT  2.304 236.251 3.438 236.345 ;
     RECT  2.415 236.345 3.438 236.461 ;
     RECT  4.176 235.535 8.097 236.461 ;
     RECT  2.415 236.461 8.097 237.115 ;
     RECT  2.412 237.115 8.097 237.547 ;
     RECT  2.304 237.547 8.097 237.659 ;
     RECT  2.304 237.659 4.626 238.235 ;
     RECT  2.304 238.235 2.697 238.505 ;
     RECT  3.6 238.235 4.626 238.621 ;
     RECT  5.364 237.659 5.706 238.621 ;
     RECT  3.6 238.621 5.706 238.699 ;
     RECT  6.48 237.659 8.097 238.699 ;
     RECT  3.6 238.699 8.097 238.739 ;
     RECT  5.364 238.739 6.498 238.775 ;
     RECT  0.108 238.783 0.126 238.877 ;
     RECT  5.364 238.775 5.706 239.009 ;
     RECT  77.94 231.827 78.297 239.117 ;
     RECT  2.415 238.505 2.697 239.161 ;
     RECT  3.6 238.739 4.626 239.161 ;
     RECT  77.976 239.117 78.297 239.165 ;
     RECT  2.415 239.161 4.626 239.585 ;
     RECT  2.415 239.585 2.898 239.707 ;
     RECT  5.472 239.009 5.706 239.819 ;
     RECT  6.48 238.775 6.498 239.819 ;
     RECT  2.304 239.707 2.898 239.855 ;
     RECT  5.58 239.819 5.706 239.855 ;
     RECT  3.636 239.585 4.626 239.971 ;
     RECT  2.415 239.855 2.898 240.089 ;
     RECT  5.688 239.855 5.706 240.089 ;
     RECT  3.636 239.971 4.698 240.125 ;
     RECT  3.852 240.125 4.698 240.197 ;
     RECT  3.852 240.197 4.194 240.395 ;
     RECT  3.996 240.395 4.194 240.629 ;
     RECT  3.996 240.629 4.014 240.665 ;
     RECT  78.015 239.165 78.297 242.779 ;
     RECT  78.012 242.779 78.297 242.825 ;
     RECT  2.415 240.089 2.697 243.827 ;
     RECT  7.815 238.739 8.097 243.827 ;
     RECT  13.215 171.248 13.497 243.827 ;
     RECT  18.615 171.341 18.897 243.827 ;
     RECT  24.015 164.768 24.297 243.827 ;
     RECT  29.415 152.609 29.697 243.827 ;
     RECT  34.815 164.765 35.097 243.827 ;
     RECT  40.215 156.701 40.497 243.827 ;
     RECT  45.615 164.768 45.897 243.827 ;
     RECT  51.015 110.813 51.297 243.827 ;
     RECT  56.415 164.768 56.697 243.827 ;
     RECT  61.815 122.711 62.097 243.827 ;
     RECT  67.215 164.768 67.497 243.827 ;
     RECT  72.615 155.021 72.897 243.827 ;
     RECT  78.015 242.825 78.297 243.827 ;
     RECT  83.415 161.837 83.697 243.827 ;
     RECT  88.815 155.357 89.097 243.827 ;
     RECT  94.215 2.413 94.497 243.827 ;
     RECT  99.615 154.544 99.897 243.827 ;
     RECT  105.015 171.005 105.297 243.827 ;
     RECT  110.415 97.805 110.697 243.827 ;
     RECT  115.815 2.413 116.097 243.827 ;
     RECT  121.215 97.808 121.497 243.827 ;
     RECT  126.615 2.413 126.897 243.827 ;
     RECT  132.015 97.808 132.297 243.827 ;
     RECT  137.415 2.413 137.697 243.827 ;
     RECT  142.815 97.808 143.097 243.827 ;
     RECT  148.215 162.059 148.497 243.827 ;
     RECT  2.415 243.827 2.505 244.097 ;
     RECT  7.815 243.827 7.905 244.097 ;
     RECT  13.215 243.827 13.305 244.097 ;
     RECT  18.615 243.827 18.705 244.097 ;
     RECT  24.015 243.827 24.105 244.097 ;
     RECT  29.415 243.827 29.505 244.097 ;
     RECT  34.815 243.827 34.905 244.097 ;
     RECT  40.215 243.827 40.305 244.097 ;
     RECT  45.615 243.827 45.705 244.097 ;
     RECT  51.015 243.827 51.105 244.097 ;
     RECT  56.415 243.827 56.505 244.097 ;
     RECT  61.815 243.827 61.905 244.097 ;
     RECT  67.215 243.827 67.305 244.097 ;
     RECT  72.615 243.827 72.705 244.097 ;
     RECT  78.015 243.827 78.105 244.097 ;
     RECT  83.415 243.827 83.505 244.097 ;
     RECT  88.815 243.827 88.905 244.097 ;
     RECT  94.215 243.827 94.305 244.097 ;
     RECT  99.615 243.827 99.705 244.097 ;
     RECT  105.015 243.827 105.105 244.097 ;
     RECT  110.415 243.827 110.505 244.097 ;
     RECT  115.815 243.827 115.905 244.097 ;
     RECT  121.215 243.827 121.305 244.097 ;
     RECT  126.615 243.827 126.705 244.097 ;
     RECT  132.015 243.827 132.105 244.097 ;
     RECT  137.415 243.827 137.505 244.097 ;
     RECT  142.815 243.827 142.905 244.097 ;
     RECT  148.215 243.827 148.305 244.097 ;
    LAYER M4 ;
     RECT  0.06 6 0.137 240.168 ;
     RECT  0.137 130.416 1.181 140.808 ;
     RECT  0.137 6 2.408 106.68 ;
     RECT  0.137 109.2 2.408 129.144 ;
     RECT  1.181 130.416 2.408 140.376 ;
     RECT  0.137 142.08 2.408 240.168 ;
     RECT  2.408 2.148 2.512 244.092 ;
     RECT  2.512 2.418 2.704 243.822 ;
     RECT  2.704 54.384 2.765 54.648 ;
     RECT  2.704 72.96 2.765 72.984 ;
     RECT  2.704 204.576 2.765 208.488 ;
     RECT  2.704 227.856 2.765 228.504 ;
     RECT  2.704 7.872 2.801 9.528 ;
     RECT  2.704 31.92 2.801 31.944 ;
     RECT  2.704 52.224 2.801 52.248 ;
     RECT  2.704 71.664 2.801 71.832 ;
     RECT  2.704 168.384 2.801 169.752 ;
     RECT  2.704 174.048 2.801 174.12 ;
     RECT  2.704 212.928 2.801 213.624 ;
     RECT  2.704 236.688 2.801 238.008 ;
     RECT  2.704 171.936 2.819 172.68 ;
     RECT  2.704 175.488 2.819 176.088 ;
     RECT  2.704 21.984 2.837 22.008 ;
     RECT  2.704 24.144 2.837 24.168 ;
     RECT  2.704 40.992 2.837 41.448 ;
     RECT  2.704 84.624 2.837 85.752 ;
     RECT  2.704 184.08 2.837 187.512 ;
     RECT  2.704 189.264 2.837 191.544 ;
     RECT  2.704 223.68 2.837 223.944 ;
     RECT  2.704 230.832 2.837 231.528 ;
     RECT  2.801 237.648 2.837 238.008 ;
     RECT  2.704 142.464 2.845 144.264 ;
     RECT  2.819 175.488 2.845 175.992 ;
     RECT  2.765 206.16 2.867 208.488 ;
     RECT  2.837 85.392 2.873 85.752 ;
     RECT  2.837 190.896 2.873 191.544 ;
     RECT  2.867 206.4 2.873 208.488 ;
     RECT  2.765 227.856 2.873 227.976 ;
     RECT  2.704 39.264 2.909 39.288 ;
     RECT  2.837 186.384 2.915 187.512 ;
     RECT  2.704 210.912 2.915 211.512 ;
     RECT  2.915 186.384 2.917 187.416 ;
     RECT  2.704 34.08 2.981 34.344 ;
     RECT  2.915 210.912 2.981 211.464 ;
     RECT  2.704 42.576 3.017 42.744 ;
     RECT  2.704 162.912 3.017 166.776 ;
     RECT  3.017 163.536 3.089 166.776 ;
     RECT  2.704 13.248 3.125 14.232 ;
     RECT  2.704 15.84 3.125 15.864 ;
     RECT  2.704 47.28 3.169 47.88 ;
     RECT  2.801 7.872 3.34 7.896 ;
     RECT  2.801 9.12 3.34 9.528 ;
     RECT  2.704 50.064 3.341 50.088 ;
     RECT  2.704 209.664 3.349 209.784 ;
     RECT  2.704 49.008 3.395 49.032 ;
     RECT  2.704 123.888 3.395 127.896 ;
     RECT  2.704 180.576 3.443 182.76 ;
     RECT  2.765 204.576 3.443 204.648 ;
     RECT  2.873 207.936 3.443 208.488 ;
     RECT  3.349 209.76 3.443 209.784 ;
     RECT  2.981 210.912 3.449 210.936 ;
     RECT  3.089 165.072 3.539 166.776 ;
     RECT  3.443 208.464 3.557 208.488 ;
     RECT  2.837 184.08 3.565 185.304 ;
     RECT  2.704 35.904 3.593 36.408 ;
     RECT  3.443 180.576 3.629 180.792 ;
     RECT  2.704 139.104 3.635 140.76 ;
     RECT  2.704 157.728 3.635 158.232 ;
     RECT  2.704 17.664 3.685 17.688 ;
     RECT  2.704 119.664 3.685 120.408 ;
     RECT  2.704 121.776 3.685 121.8 ;
     RECT  2.704 146.112 3.685 146.328 ;
     RECT  2.704 60.96 3.733 60.984 ;
     RECT  2.704 104.784 3.733 106.296 ;
     RECT  2.704 107.424 3.733 115.608 ;
     RECT  2.704 116.88 3.733 117.144 ;
     RECT  2.704 118.32 3.733 118.344 ;
     RECT  2.704 160.752 3.733 160.776 ;
     RECT  2.704 232.848 3.769 232.872 ;
     RECT  3.443 181.776 3.773 182.76 ;
     RECT  3.685 119.664 3.779 121.992 ;
     RECT  3.395 126.336 3.781 127.896 ;
     RECT  3.733 159.36 3.781 161.256 ;
     RECT  2.704 78.144 3.805 79.56 ;
     RECT  3.635 157.872 3.805 158.232 ;
     RECT  3.781 159.36 3.805 161.304 ;
     RECT  3.565 184.08 3.805 184.728 ;
     RECT  2.704 199.296 3.805 199.512 ;
     RECT  2.704 233.856 3.805 233.976 ;
     RECT  3.805 78.096 3.829 79.56 ;
     RECT  3.805 233.856 3.829 234.264 ;
     RECT  2.704 90.576 3.841 100.68 ;
     RECT  3.769 232.512 3.853 232.872 ;
     RECT  3.829 233.856 3.868 234.36 ;
     RECT  3.805 52.464 3.877 52.488 ;
     RECT  2.765 54.624 3.877 54.648 ;
     RECT  3.733 75.264 3.877 75.288 ;
     RECT  2.837 223.728 3.877 223.944 ;
     RECT  2.704 194.592 3.889 197.256 ;
     RECT  2.704 62.496 3.913 63.24 ;
     RECT  2.704 130.896 3.913 138.12 ;
     RECT  3.877 51.504 3.923 52.488 ;
     RECT  3.733 116.88 3.925 118.584 ;
     RECT  3.805 178.368 3.925 178.392 ;
     RECT  2.704 82.512 3.949 83.112 ;
     RECT  3.733 104.784 3.949 115.704 ;
     RECT  3.925 116.88 3.949 118.92 ;
     RECT  3.781 126.336 3.949 128.76 ;
     RECT  3.635 139.392 3.949 140.76 ;
     RECT  2.704 149.76 3.949 151.08 ;
     RECT  3.877 54.624 3.961 54.744 ;
     RECT  3.877 223.44 3.961 223.944 ;
     RECT  3.923 51.504 3.964 52.2 ;
     RECT  3.685 17.664 3.973 18.216 ;
     RECT  3.733 60.384 3.973 60.984 ;
     RECT  3.913 62.016 3.973 63.24 ;
     RECT  3.685 145.248 3.973 146.328 ;
     RECT  2.704 147.312 3.973 148.44 ;
     RECT  2.837 189.264 3.973 189.864 ;
     RECT  2.845 142.512 3.98 144.264 ;
     RECT  3.973 145.248 3.98 148.536 ;
     RECT  2.704 152.928 3.985 152.952 ;
     RECT  2.819 171.936 3.985 172.152 ;
     RECT  2.704 225.216 3.985 226.056 ;
     RECT  3.985 225.216 4.019 226.296 ;
     RECT  2.704 101.856 4.021 101.88 ;
     RECT  2.704 103.056 4.021 103.176 ;
     RECT  3.98 142.512 4.021 148.536 ;
     RECT  3.985 171.696 4.021 172.152 ;
     RECT  2.801 174.096 4.021 174.12 ;
     RECT  2.845 175.632 4.021 175.992 ;
     RECT  2.873 227.856 4.021 227.88 ;
     RECT  3.949 126.336 4.057 129.432 ;
     RECT  3.913 130.896 4.057 138.36 ;
     RECT  3.949 139.392 4.057 140.808 ;
     RECT  4.021 141.936 4.057 148.536 ;
     RECT  4.019 225.744 4.06 226.296 ;
     RECT  3.973 17.088 4.061 18.216 ;
     RECT  4.057 139.392 4.069 148.536 ;
     RECT  4.021 103.056 4.093 103.272 ;
     RECT  2.704 177.216 4.093 177.24 ;
     RECT  3.985 152.928 4.117 153.336 ;
     RECT  2.873 206.4 4.117 206.616 ;
     RECT  3.841 90.24 4.165 100.68 ;
     RECT  4.021 101.712 4.165 101.88 ;
     RECT  4.021 173.52 4.169 174.456 ;
     RECT  4.165 90.24 4.201 101.88 ;
     RECT  2.704 69.6 4.213 69.624 ;
     RECT  3.805 157.872 4.237 161.304 ;
     RECT  4.061 17.568 4.241 18.216 ;
     RECT  2.801 71.808 4.259 71.832 ;
     RECT  3.913 219.024 4.261 219.048 ;
     RECT  2.704 220.176 4.261 220.392 ;
     RECT  4.261 219.024 4.273 220.584 ;
     RECT  4.268 23.232 4.309 23.256 ;
     RECT  3.697 25.632 4.309 25.656 ;
     RECT  2.704 179.568 4.309 179.592 ;
     RECT  4.213 69.6 4.345 70.248 ;
     RECT  3.877 75.264 4.345 75.816 ;
     RECT  2.704 76.944 4.345 76.968 ;
     RECT  3.949 104.784 4.345 118.92 ;
     RECT  3.889 194.592 4.345 194.616 ;
     RECT  4.273 219.024 4.348 220.632 ;
     RECT  4.309 23.232 4.355 24.072 ;
     RECT  3.805 183.552 4.355 184.728 ;
     RECT  4.345 194.208 4.405 194.616 ;
     RECT  2.704 87.216 4.412 87.24 ;
     RECT  3.017 42.576 4.453 42.6 ;
     RECT  4.412 87.216 4.453 87.432 ;
     RECT  2.704 88.56 4.453 88.68 ;
     RECT  4.201 90.048 4.453 101.88 ;
     RECT  4.069 139.392 4.453 148.68 ;
     RECT  4.117 152.784 4.453 153.576 ;
     RECT  4.348 220.56 4.453 220.632 ;
     RECT  2.837 237.648 4.453 237.672 ;
     RECT  4.069 73.824 4.489 73.848 ;
     RECT  3.395 124.032 4.489 125.064 ;
     RECT  2.837 40.992 4.493 41.016 ;
     RECT  4.412 18.912 4.499 18.936 ;
     RECT  4.237 27.312 4.501 27.336 ;
     RECT  4.481 28.512 4.501 28.536 ;
     RECT  4.345 56.496 4.501 56.52 ;
     RECT  3.973 60.384 4.501 63.24 ;
     RECT  3.781 64.272 4.501 64.296 ;
     RECT  4.093 103.056 4.501 103.368 ;
     RECT  4.345 104.688 4.501 118.92 ;
     RECT  3.539 166.176 4.501 166.776 ;
     RECT  2.801 168.384 4.501 169.32 ;
     RECT  3.913 211.92 4.501 211.944 ;
     RECT  2.801 213.168 4.501 213.624 ;
     RECT  3.961 54.624 4.508 54.648 ;
     RECT  2.704 217.152 4.517 217.416 ;
     RECT  4.501 27.312 4.525 28.536 ;
     RECT  2.704 29.808 4.525 30.744 ;
     RECT  3.733 229.104 4.525 229.128 ;
     RECT  4.525 27.312 4.547 30.744 ;
     RECT  3.593 36.384 4.549 36.408 ;
     RECT  2.704 66.96 4.549 68.376 ;
     RECT  4.345 69.552 4.549 70.248 ;
     RECT  4.237 157.872 4.549 162.264 ;
     RECT  3.089 163.536 4.549 163.752 ;
     RECT  4.348 219.024 4.549 219.048 ;
     RECT  2.873 85.392 4.561 85.656 ;
     RECT  4.453 90.048 4.561 101.976 ;
     RECT  3.949 149.76 4.561 151.608 ;
     RECT  4.453 152.784 4.561 153.864 ;
     RECT  3.925 178.368 4.561 178.488 ;
     RECT  4.309 179.52 4.561 179.592 ;
     RECT  3.889 195.792 4.561 197.256 ;
     RECT  4.525 198.288 4.561 198.312 ;
     RECT  2.704 215.424 4.561 215.448 ;
     RECT  4.517 217.152 4.561 217.752 ;
     RECT  4.547 27.744 4.565 30.744 ;
     RECT  4.549 66.96 4.565 70.248 ;
     RECT  4.453 139.392 4.565 148.776 ;
     RECT  4.355 183.552 4.565 184.344 ;
     RECT  3.868 233.952 4.565 234.36 ;
     RECT  4.501 56.496 4.588 58.632 ;
     RECT  4.501 60.384 4.588 65.304 ;
     RECT  4.501 211.92 4.588 213.624 ;
     RECT  4.508 53.952 4.595 54.648 ;
     RECT  4.565 144.768 4.595 148.776 ;
     RECT  2.704 201.744 4.595 203.544 ;
     RECT  4.549 218.832 4.595 219.048 ;
     RECT  4.489 124.032 4.597 125.256 ;
     RECT  4.453 208.608 4.597 208.632 ;
     RECT  4.561 215.424 4.601 217.752 ;
     RECT  4.453 220.56 4.601 221.208 ;
     RECT  3.961 223.872 4.633 223.944 ;
     RECT  4.565 27.744 4.637 27.768 ;
     RECT  4.117 205.824 4.669 206.616 ;
     RECT  4.021 227.376 4.669 227.88 ;
     RECT  4.549 157.872 4.673 163.752 ;
     RECT  4.633 223.872 4.673 224.424 ;
     RECT  3.853 232.848 4.673 232.872 ;
     RECT  4.673 160.752 4.691 163.752 ;
     RECT  2.704 222.24 4.7 222.264 ;
     RECT  4.561 90.048 4.705 102.024 ;
     RECT  4.597 123.984 4.705 125.256 ;
     RECT  4.057 126.336 4.705 138.36 ;
     RECT  4.561 149.76 4.705 153.864 ;
     RECT  2.704 154.992 4.705 156.648 ;
     RECT  4.405 193.824 4.705 194.616 ;
     RECT  2.837 230.832 4.705 231.192 ;
     RECT  4.489 73.392 4.709 74.136 ;
     RECT  4.669 227.376 4.709 227.976 ;
     RECT  4.093 177.168 4.733 177.24 ;
     RECT  4.561 178.368 4.733 179.592 ;
     RECT  4.588 58.608 4.741 58.632 ;
     RECT  4.705 149.76 4.741 156.648 ;
     RECT  2.917 186.384 4.741 186.792 ;
     RECT  4.709 227.856 4.741 227.976 ;
     RECT  4.525 229.104 4.741 229.512 ;
     RECT  4.453 237.12 4.741 237.672 ;
     RECT  4.021 175.536 4.748 175.992 ;
     RECT  2.704 81.504 4.777 81.528 ;
     RECT  4.169 173.952 4.777 174.456 ;
     RECT  4.748 175.536 4.777 176.136 ;
     RECT  4.741 236.544 4.777 237.672 ;
     RECT  4.741 58.608 4.781 58.728 ;
     RECT  4.597 208.08 4.781 208.632 ;
     RECT  4.777 235.968 4.781 237.672 ;
     RECT  4.733 177.168 4.787 179.592 ;
     RECT  4.601 220.608 4.787 221.208 ;
     RECT  4.7 222.24 4.787 222.792 ;
     RECT  4.673 223.92 4.787 224.424 ;
     RECT  4.741 227.856 4.787 229.752 ;
     RECT  2.704 11.184 4.789 11.208 ;
     RECT  3.125 13.248 4.789 13.368 ;
     RECT  4.705 193.248 4.789 194.616 ;
     RECT  4.06 225.84 4.789 226.296 ;
     RECT  3.985 46.224 4.799 46.248 ;
     RECT  3.805 199.296 4.799 200.04 ;
     RECT  4.705 230.832 4.809 231.432 ;
     RECT  3.949 82.512 4.813 83.352 ;
     RECT  4.561 84.96 4.813 85.656 ;
     RECT  4.453 87.216 4.813 88.68 ;
     RECT  4.705 89.952 4.813 102.024 ;
     RECT  3.779 119.952 4.813 121.992 ;
     RECT  4.705 123.984 4.813 138.36 ;
     RECT  4.588 56.496 4.817 57.288 ;
     RECT  3.34 9.12 4.837 9.144 ;
     RECT  4.691 161.088 4.844 163.752 ;
     RECT  4.021 171.696 4.844 172.344 ;
     RECT  4.781 208.608 4.844 208.632 ;
     RECT  4.837 8.352 4.849 10.008 ;
     RECT  4.789 11.184 4.849 13.368 ;
     RECT  4.781 235.968 4.849 236.568 ;
     RECT  2.704 6.288 4.853 6.312 ;
     RECT  4.565 139.392 4.853 143.688 ;
     RECT  3.539 165.072 4.853 165.096 ;
     RECT  4.849 235.2 4.861 236.568 ;
     RECT  4.849 8.352 4.876 13.368 ;
     RECT  4.876 8.352 4.883 11.208 ;
     RECT  4.781 237.648 4.883 237.672 ;
     RECT  4.799 45.36 4.885 46.248 ;
     RECT  3.169 47.856 4.885 47.88 ;
     RECT  4.813 87.216 4.885 102.024 ;
     RECT  4.501 103.056 4.885 118.92 ;
     RECT  4.813 119.952 4.885 122.424 ;
     RECT  4.741 149.76 4.885 156.744 ;
     RECT  4.673 157.872 4.885 159.72 ;
     RECT  4.844 161.088 4.885 163.896 ;
     RECT  4.844 171.696 4.885 172.632 ;
     RECT  4.669 205.776 4.885 206.616 ;
     RECT  4.837 209.808 4.885 209.832 ;
     RECT  4.44 210.816 4.885 210.84 ;
     RECT  4.876 12.288 4.889 13.368 ;
     RECT  4.885 149.76 4.889 159.72 ;
     RECT  4.889 13.344 4.921 13.368 ;
     RECT  4.883 8.352 4.924 8.52 ;
     RECT  4.883 9.552 4.931 11.208 ;
     RECT  4.885 45.36 4.931 47.88 ;
     RECT  4.885 171.552 4.931 172.632 ;
     RECT  4.787 220.608 4.931 220.632 ;
     RECT  4.931 9.552 4.933 10.248 ;
     RECT  4.453 42.192 4.933 42.6 ;
     RECT  4.556 50.976 4.933 51 ;
     RECT  4.885 87.216 4.957 122.424 ;
     RECT  4.241 17.568 4.961 17.592 ;
     RECT  4.355 23.952 4.961 24.072 ;
     RECT  4.885 209.808 4.969 210.84 ;
     RECT  4.588 65.28 4.993 65.304 ;
     RECT  4.789 193.824 4.993 194.616 ;
     RECT  4.561 195.792 4.993 198.312 ;
     RECT  4.565 67.872 5.029 70.248 ;
     RECT  4.813 82.512 5.029 85.656 ;
     RECT  4.957 87.216 5.029 122.76 ;
     RECT  4.813 123.84 5.029 138.36 ;
     RECT  4.993 65.28 5.033 65.592 ;
     RECT  4.931 45.36 5.065 47.592 ;
     RECT  4.595 202.032 5.065 203.544 ;
     RECT  3.443 204.624 5.065 204.648 ;
     RECT  3.629 180.72 5.069 180.792 ;
     RECT  4.799 199.296 5.075 200.664 ;
     RECT  4.777 80.832 5.077 81.528 ;
     RECT  5.029 82.512 5.077 86.184 ;
     RECT  4.777 173.952 5.077 176.136 ;
     RECT  4.787 177.168 5.077 178.488 ;
     RECT  3.973 189.264 5.077 189.912 ;
     RECT  2.873 190.896 5.077 190.92 ;
     RECT  4.844 208.608 5.077 208.728 ;
     RECT  4.969 209.808 5.077 209.832 ;
     RECT  5.065 44.448 5.105 47.592 ;
     RECT  4.933 42.192 5.123 42.792 ;
     RECT  4.889 149.76 5.123 153.912 ;
     RECT  5.077 173.952 5.123 178.488 ;
     RECT  4.525 187.968 5.125 187.992 ;
     RECT  5.077 189.264 5.125 190.92 ;
     RECT  4.993 193.824 5.125 198.312 ;
     RECT  5.075 199.296 5.125 200.04 ;
     RECT  4.921 13.344 5.132 13.656 ;
     RECT  4.309 25.488 5.137 25.656 ;
     RECT  4.924 8.496 5.141 8.52 ;
     RECT  5.123 175.056 5.141 177.288 ;
     RECT  5.123 151.536 5.149 153.912 ;
     RECT  5.125 187.968 5.171 190.92 ;
     RECT  5.125 193.824 5.171 200.04 ;
     RECT  5.132 13.344 5.173 14.232 ;
     RECT  4.525 15.36 5.173 15.384 ;
     RECT  4.931 171.552 5.177 171.72 ;
     RECT  4.789 225.84 5.177 226.872 ;
     RECT  4.565 233.952 5.177 233.976 ;
     RECT  4.549 36.384 5.18 36.504 ;
     RECT  5.077 208.608 5.213 209.832 ;
     RECT  5.173 13.344 5.219 15.384 ;
     RECT  4.853 140.64 5.219 143.688 ;
     RECT  4.961 23.952 5.221 23.976 ;
     RECT  4.345 75.264 5.245 76.968 ;
     RECT  5.137 25.488 5.267 25.896 ;
     RECT  5.18 35.856 5.267 36.504 ;
     RECT  5.105 44.448 5.267 45.672 ;
     RECT  4.565 28.944 5.281 30.744 ;
     RECT  5.123 42.192 5.285 42.6 ;
     RECT  4.588 60.384 5.285 63.288 ;
     RECT  5.123 178.272 5.285 178.488 ;
     RECT  4.809 231.168 5.321 231.432 ;
     RECT  4.933 50.688 5.413 51 ;
     RECT  5.219 14.496 5.425 15.384 ;
     RECT  4.787 179.52 5.425 179.592 ;
     RECT  5.285 60.96 5.459 63.288 ;
     RECT  2.981 34.32 5.461 34.344 ;
     RECT  4.501 166.176 5.461 169.32 ;
     RECT  4.741 170.448 5.461 170.472 ;
     RECT  5.425 14.496 5.465 16.008 ;
     RECT  4.781 58.704 5.465 58.728 ;
     RECT  5.413 50.4 5.5 51 ;
     RECT  5.029 67.872 5.501 70.632 ;
     RECT  5.065 202.032 5.501 204.648 ;
     RECT  4.601 215.424 5.501 216.36 ;
     RECT  4.933 9.552 5.507 9.96 ;
     RECT  5.135 17.28 5.507 17.304 ;
     RECT  5.459 61.008 5.507 63.288 ;
     RECT  4.309 22.08 5.533 22.104 ;
     RECT  5.533 21.648 5.573 22.104 ;
     RECT  5.461 166.176 5.573 170.472 ;
     RECT  3.773 181.776 5.605 181.944 ;
     RECT  4.741 186.336 5.605 186.792 ;
     RECT  5.171 187.968 5.605 188.808 ;
     RECT  4.453 239.808 5.609 239.832 ;
     RECT  5.507 61.008 5.645 61.368 ;
     RECT  4.889 154.944 5.645 159.72 ;
     RECT  4.885 161.088 5.645 164.712 ;
     RECT  5.605 186.336 5.651 188.808 ;
     RECT  4.853 139.392 5.653 139.416 ;
     RECT  5.573 168.384 5.653 170.472 ;
     RECT  5.177 171.552 5.653 171.576 ;
     RECT  4.565 183.552 5.677 184.2 ;
     RECT  5.171 198.672 5.699 200.04 ;
     RECT  5.267 25.488 5.701 25.704 ;
     RECT  4.525 39.36 5.701 39.384 ;
     RECT  5.077 80.832 5.701 86.184 ;
     RECT  5.029 87.216 5.701 138.36 ;
     RECT  4.595 144.768 5.708 148.728 ;
     RECT  5.123 149.76 5.708 150.456 ;
     RECT  5.645 155.376 5.708 159.72 ;
     RECT  5.645 161.088 5.708 161.304 ;
     RECT  4.709 73.392 5.713 73.896 ;
     RECT  5.245 75.264 5.713 77.016 ;
     RECT  5.219 141.936 5.713 143.688 ;
     RECT  5.708 144.768 5.713 150.456 ;
     RECT  5.653 139.344 5.74 139.416 ;
     RECT  5.701 38.688 5.747 39.912 ;
     RECT  5.713 73.392 5.749 77.016 ;
     RECT  3.829 78.096 5.749 79.8 ;
     RECT  5.285 42.192 5.753 42.216 ;
     RECT  5.507 62.352 5.753 63.288 ;
     RECT  5.033 65.568 5.753 65.592 ;
     RECT  5.645 162.624 5.753 164.712 ;
     RECT  5.141 175.056 5.753 176.76 ;
     RECT  4.861 236.544 5.777 236.568 ;
     RECT  4.595 54.144 5.785 54.648 ;
     RECT  5.701 25.056 5.788 25.704 ;
     RECT  5.321 231.408 5.789 231.432 ;
     RECT  5.708 155.376 5.795 161.304 ;
     RECT  5.785 53.808 5.797 54.648 ;
     RECT  4.817 56.496 5.797 56.52 ;
     RECT  5.281 28.944 5.821 30.84 ;
     RECT  5.605 181.248 5.821 181.944 ;
     RECT  5.677 183.456 5.821 184.2 ;
     RECT  5.651 186.768 5.825 188.808 ;
     RECT  5.177 225.84 5.825 226.344 ;
     RECT  5.753 164.688 5.852 164.712 ;
     RECT  5.813 221.712 5.852 221.736 ;
     RECT  5.813 222.864 5.852 222.888 ;
     RECT  5.777 236.544 5.861 237.144 ;
     RECT  5.797 53.808 5.884 56.52 ;
     RECT  5.821 28.464 5.891 30.84 ;
     RECT  5.713 141.936 5.891 150.456 ;
     RECT  5.852 220.896 5.893 221.736 ;
     RECT  4.861 235.2 5.893 235.224 ;
     RECT  5.425 179.52 5.897 180.024 ;
     RECT  5.501 202.032 5.897 204.072 ;
     RECT  5.893 219.984 5.897 221.736 ;
     RECT  5.852 222.864 5.897 223.224 ;
     RECT  5.891 28.464 5.905 28.488 ;
     RECT  5.171 189.84 5.921 190.92 ;
     RECT  5.747 38.688 5.929 38.76 ;
     RECT  5.753 62.448 5.929 63.288 ;
     RECT  4.588 64.272 5.929 64.296 ;
     RECT  5.747 39.888 5.933 39.912 ;
     RECT  5.821 181.248 5.939 184.2 ;
     RECT  5.897 219.984 5.939 220.92 ;
     RECT  5.897 223.2 5.939 223.224 ;
     RECT  5.861 236.544 5.941 236.568 ;
     RECT  5.149 151.584 5.948 153.912 ;
     RECT  5.701 80.832 5.965 138.36 ;
     RECT  4.588 212.592 5.969 213.192 ;
     RECT  5.825 226.032 5.969 226.344 ;
     RECT  5.893 224.88 5.98 224.904 ;
     RECT  5.969 212.592 5.987 213 ;
     RECT  5.857 214.32 5.987 214.344 ;
     RECT  5.893 235.104 5.987 235.224 ;
     RECT  5.219 140.64 6.001 140.904 ;
     RECT  5.921 189.84 6.005 190.968 ;
     RECT  5.987 212.976 6.028 213 ;
     RECT  5.948 151.584 6.035 154.248 ;
     RECT  5.795 155.376 6.035 159.672 ;
     RECT  5.465 15.984 6.041 16.008 ;
     RECT  5.573 21.648 6.041 21.672 ;
     RECT  5.753 175.056 6.041 175.08 ;
     RECT  5.753 176.688 6.041 176.712 ;
     RECT  5.825 186.96 6.041 188.808 ;
     RECT  5.171 193.824 6.041 197.448 ;
     RECT  5.699 199.2 6.041 199.224 ;
     RECT  5.897 202.032 6.041 203.544 ;
     RECT  5.213 208.608 6.041 209.448 ;
     RECT  5.501 216.336 6.041 216.36 ;
     RECT  5.5 50.976 6.077 51 ;
     RECT  6.035 151.584 6.077 153.912 ;
     RECT  6.041 202.032 6.077 202.968 ;
     RECT  4.601 217.392 6.077 217.416 ;
     RECT  5.749 73.392 6.085 79.8 ;
     RECT  5.965 80.832 6.085 138.456 ;
     RECT  5.465 14.496 6.113 14.52 ;
     RECT  5.653 168.384 6.113 171.576 ;
     RECT  4.787 229.728 6.113 229.752 ;
     RECT  6.077 152.304 6.131 153.912 ;
     RECT  6.001 172.704 6.131 172.728 ;
     RECT  5.461 34.32 6.133 34.824 ;
     RECT  4.417 32.976 6.14 33 ;
     RECT  6.133 34.32 6.14 34.872 ;
     RECT  5.753 162.624 6.149 163.704 ;
     RECT  4.785 238.704 6.149 238.728 ;
     RECT  6.113 169.296 6.172 171.576 ;
     RECT  5.105 47.424 6.179 47.592 ;
     RECT  5.788 25.056 6.185 25.08 ;
     RECT  5.929 62.448 6.185 64.296 ;
     RECT  6.133 49.152 6.22 49.176 ;
     RECT  5.891 29.808 6.227 30.744 ;
     RECT  6.14 31.872 6.227 31.896 ;
     RECT  6.14 32.976 6.227 34.872 ;
     RECT  5.929 38.544 6.227 38.76 ;
     RECT  6.085 73.392 6.227 138.456 ;
     RECT  6.227 85.344 6.229 138.456 ;
     RECT  6.227 34.752 6.275 34.872 ;
     RECT  6.227 38.64 6.275 38.76 ;
     RECT  5.891 146.016 6.277 150.456 ;
     RECT  6.275 34.752 6.293 34.776 ;
     RECT  5.267 45.648 6.293 45.672 ;
     RECT  4.969 210.816 6.293 210.84 ;
     RECT  5.941 236.256 6.293 236.568 ;
     RECT  6.131 152.304 6.323 153.864 ;
     RECT  5.891 141.936 6.325 144.744 ;
     RECT  5.389 233.616 6.325 233.64 ;
     RECT  5.939 182.928 6.329 184.2 ;
     RECT  4.489 72.048 6.361 72.072 ;
     RECT  6.227 73.392 6.361 84.36 ;
     RECT  5.852 164.688 6.361 164.76 ;
     RECT  5.573 166.176 6.361 166.776 ;
     RECT  5.795 160.704 6.365 161.304 ;
     RECT  6.005 189.84 6.365 190.728 ;
     RECT  6.172 169.296 6.401 171.24 ;
     RECT  5.507 9.552 6.421 9.72 ;
     RECT  6.041 195.792 6.437 197.448 ;
     RECT  6.421 8.832 6.467 9.72 ;
     RECT  6.467 8.832 6.508 9 ;
     RECT  6.469 7.392 6.541 7.416 ;
     RECT  5.884 53.808 6.545 54.648 ;
     RECT  6.229 85.392 6.545 138.456 ;
     RECT  6.323 152.64 6.545 153.864 ;
     RECT  5.939 219.984 6.545 220.008 ;
     RECT  6.277 146.016 6.581 151.032 ;
     RECT  4.787 227.856 6.581 228.552 ;
     RECT  6.325 232.8 6.581 233.64 ;
     RECT  5.267 36.48 6.613 36.504 ;
     RECT  5.501 70.512 6.613 70.632 ;
     RECT  6.001 140.208 6.613 140.904 ;
     RECT  6.325 141.888 6.613 144.744 ;
     RECT  6.035 158.304 6.617 159.672 ;
     RECT  6.541 6.816 6.625 7.416 ;
     RECT  4.525 192.096 6.653 192.12 ;
     RECT  6.035 155.376 6.707 157.272 ;
     RECT  6.545 87.024 6.721 138.456 ;
     RECT  6.649 189.264 6.733 189.288 ;
     RECT  6.361 164.688 6.749 166.776 ;
     RECT  6.613 36.48 6.757 37.032 ;
     RECT  4.345 20.016 6.761 20.04 ;
     RECT  5.939 181.248 6.764 181.944 ;
     RECT  5.267 44.448 6.797 44.472 ;
     RECT  6.077 202.944 6.797 202.968 ;
     RECT  4.595 218.832 6.797 218.856 ;
     RECT  6.613 140.208 6.803 144.744 ;
     RECT  6.757 35.856 6.805 37.032 ;
     RECT  6.749 164.688 6.833 168.12 ;
     RECT  5.884 55.92 6.853 56.52 ;
     RECT  5.645 61.344 6.853 61.368 ;
     RECT  6.721 87.024 6.853 138.936 ;
     RECT  6.803 140.208 6.853 142.488 ;
     RECT  6.853 60.816 6.901 61.368 ;
     RECT  6.185 62.448 6.901 63.048 ;
     RECT  5.285 178.272 6.937 178.296 ;
     RECT  6.217 179.376 6.937 179.4 ;
     RECT  6.041 186.96 6.937 186.984 ;
     RECT  6.613 70.512 7.037 70.824 ;
     RECT  6.361 72.048 7.037 84.36 ;
     RECT  6.793 65.952 7.045 65.976 ;
     RECT  6.937 186.384 7.081 186.984 ;
     RECT  6.041 187.968 7.081 187.992 ;
     RECT  5.501 67.872 7.093 69.528 ;
     RECT  5.677 185.232 7.117 185.256 ;
     RECT  6.149 162.624 7.153 162.648 ;
     RECT  6.185 64.224 7.189 64.296 ;
     RECT  6.803 143.472 7.189 144.744 ;
     RECT  6.365 161.088 7.225 161.304 ;
     RECT  6.041 193.824 7.325 194.616 ;
     RECT  5.969 226.032 7.333 226.056 ;
     RECT  6.707 155.376 7.369 157.176 ;
     RECT  7.153 162.48 7.369 162.648 ;
     RECT  6.149 163.68 7.369 163.704 ;
     RECT  6.833 164.688 7.369 166.776 ;
     RECT  6.581 146.688 7.397 151.032 ;
     RECT  6.625 7.392 7.429 7.416 ;
     RECT  7.037 70.512 7.436 84.36 ;
     RECT  6.545 85.392 7.436 86.04 ;
     RECT  6.545 53.808 7.513 53.832 ;
     RECT  6.329 182.928 7.513 183.528 ;
     RECT  7.117 184.704 7.513 185.256 ;
     RECT  6.853 55.92 7.621 57.96 ;
     RECT  6.545 152.784 7.628 153.864 ;
     RECT  7.397 146.688 7.657 151.08 ;
     RECT  6.179 47.568 7.693 47.592 ;
     RECT  7.429 7.392 7.729 7.8 ;
     RECT  7.436 70.512 7.729 86.04 ;
     RECT  6.853 87.024 7.729 142.488 ;
     RECT  7.729 7.344 7.808 7.8 ;
     RECT  6.508 8.976 7.808 9 ;
     RECT  6.229 11.04 7.808 11.064 ;
     RECT  4.889 12.288 7.808 12.312 ;
     RECT  5.219 13.344 7.808 13.368 ;
     RECT  6.227 29.808 7.808 30.216 ;
     RECT  6.805 35.856 7.808 37.08 ;
     RECT  6.275 38.64 7.808 38.664 ;
     RECT  6.853 43.872 7.808 43.896 ;
     RECT  7.693 47.568 7.808 47.688 ;
     RECT  3.964 52.176 7.808 52.2 ;
     RECT  7.513 53.808 7.808 54.552 ;
     RECT  7.621 55.68 7.808 57.96 ;
     RECT  6.037 59.424 7.808 59.448 ;
     RECT  6.901 60.816 7.808 63.048 ;
     RECT  7.189 64.224 7.808 64.488 ;
     RECT  7.045 65.952 7.808 66.744 ;
     RECT  7.093 67.824 7.808 69.528 ;
     RECT  7.729 70.512 7.808 142.488 ;
     RECT  7.189 143.472 7.808 145.32 ;
     RECT  7.657 146.448 7.808 151.08 ;
     RECT  7.628 152.784 7.808 153.912 ;
     RECT  7.369 155.04 7.808 157.176 ;
     RECT  6.617 158.304 7.808 159.24 ;
     RECT  7.225 161.088 7.808 161.352 ;
     RECT  7.369 162.48 7.808 166.776 ;
     RECT  6.833 168.096 7.808 168.12 ;
     RECT  6.401 169.872 7.808 171.24 ;
     RECT  6.541 172.32 7.808 172.344 ;
     RECT  5.123 173.952 7.808 173.976 ;
     RECT  6.973 176.64 7.808 176.664 ;
     RECT  6.937 178.272 7.808 179.4 ;
     RECT  6.764 180.384 7.808 181.944 ;
     RECT  7.513 182.928 7.808 185.256 ;
     RECT  7.081 186.384 7.808 187.992 ;
     RECT  6.365 190.704 7.808 190.728 ;
     RECT  7.325 193.248 7.808 194.616 ;
     RECT  6.437 195.792 7.808 196.92 ;
     RECT  4.885 205.776 7.808 207.432 ;
     RECT  6.041 208.608 7.808 208.632 ;
     RECT  7.369 220.128 7.808 220.152 ;
     RECT  7.333 226.032 7.808 226.632 ;
     RECT  6.581 227.856 7.808 227.88 ;
     RECT  6.581 232.8 7.808 232.824 ;
     RECT  5.987 235.104 7.808 235.128 ;
     RECT  6.293 236.544 7.808 236.568 ;
     RECT  7.808 2.148 7.912 244.092 ;
     RECT  7.912 2.418 8.104 243.822 ;
     RECT  8.104 162.624 8.165 167.592 ;
     RECT  8.104 138.912 8.237 144.84 ;
     RECT  8.165 166.176 8.237 167.592 ;
     RECT  8.104 11.136 8.243 11.16 ;
     RECT  8.104 12.288 8.243 12.312 ;
     RECT  8.104 22.752 8.243 22.776 ;
     RECT  8.104 76.464 8.243 131.592 ;
     RECT  8.104 206.448 8.243 206.952 ;
     RECT  8.165 162.624 8.273 164.76 ;
     RECT  8.237 167.04 8.291 167.592 ;
     RECT  8.104 52.992 8.309 53.832 ;
     RECT  8.104 61.008 8.309 64.968 ;
     RECT  8.104 65.952 8.309 68.76 ;
     RECT  8.104 54.912 8.453 59.88 ;
     RECT  8.453 55.44 8.489 55.752 ;
     RECT  8.104 25.056 8.579 25.08 ;
     RECT  8.104 179.376 8.579 179.4 ;
     RECT  8.489 55.44 8.627 55.464 ;
     RECT  8.104 154.896 8.633 156.216 ;
     RECT  8.104 157.488 8.723 161.16 ;
     RECT  8.104 47.664 8.813 47.688 ;
     RECT  8.633 154.896 8.819 156.12 ;
     RECT  8.104 171.216 8.867 172.344 ;
     RECT  8.309 62.4 8.908 64.968 ;
     RECT  8.453 56.976 8.957 59.88 ;
     RECT  8.908 62.448 8.963 64.968 ;
     RECT  8.309 61.008 8.993 61.416 ;
     RECT  8.243 76.512 9.037 131.592 ;
     RECT  8.104 152.928 9.097 153.768 ;
     RECT  8.104 146.448 9.133 151.32 ;
     RECT  8.723 157.488 9.133 158.424 ;
     RECT  8.309 65.952 9.137 68.712 ;
     RECT  8.291 167.04 9.137 167.064 ;
     RECT  8.104 7.344 9.155 7.368 ;
     RECT  8.957 56.976 9.155 59.256 ;
     RECT  8.104 132.816 9.173 137.784 ;
     RECT  9.155 56.976 9.209 57.048 ;
     RECT  9.133 157.344 9.217 158.424 ;
     RECT  8.819 154.896 9.251 155.592 ;
     RECT  8.104 232.8 9.251 232.824 ;
     RECT  9.133 146.256 9.26 151.32 ;
     RECT  9.097 152.928 9.26 153.816 ;
     RECT  8.993 61.008 9.277 61.368 ;
     RECT  9.26 146.256 9.347 153.816 ;
     RECT  9.037 100.032 9.353 131.592 ;
     RECT  9.173 132.816 9.353 137.544 ;
     RECT  8.963 62.448 9.395 64.392 ;
     RECT  8.104 226.32 9.395 227.448 ;
     RECT  8.104 70.224 9.421 75.432 ;
     RECT  9.037 76.512 9.421 98.904 ;
     RECT  9.277 60.96 9.425 61.368 ;
     RECT  9.209 57.024 9.436 57.048 ;
     RECT  9.421 70.224 9.457 98.904 ;
     RECT  9.137 67.872 9.461 68.712 ;
     RECT  8.723 159.408 9.539 161.016 ;
     RECT  8.309 53.808 9.541 53.832 ;
     RECT  9.493 157.296 9.601 157.32 ;
     RECT  9.529 11.376 9.613 11.4 ;
     RECT  9.347 146.256 9.641 151.464 ;
     RECT  8.237 138.912 9.644 144.552 ;
     RECT  9.457 69.888 9.677 98.904 ;
     RECT  9.541 53.04 9.683 53.832 ;
     RECT  8.104 195.936 9.731 195.96 ;
     RECT  9.677 70.416 9.749 98.904 ;
     RECT  9.353 132.96 9.749 137.544 ;
     RECT  9.644 138.912 9.781 145.224 ;
     RECT  9.781 138.528 9.821 145.32 ;
     RECT  9.395 62.448 9.827 63.048 ;
     RECT  9.601 157.152 9.889 157.32 ;
     RECT  8.273 162.624 9.889 163.704 ;
     RECT  9.395 64.08 9.893 64.392 ;
     RECT  9.641 146.4 10.001 151.464 ;
     RECT  9.347 152.928 10.001 153.816 ;
     RECT  9.137 65.952 10.037 66.696 ;
     RECT  9.539 159.408 10.037 159.912 ;
     RECT  9.155 58.416 10.067 59.256 ;
     RECT  9.827 62.496 10.073 63.048 ;
     RECT  9.217 158.304 10.105 158.424 ;
     RECT  10.037 159.408 10.105 159.72 ;
     RECT  9.353 100.032 10.109 129.24 ;
     RECT  9.893 64.08 10.115 64.104 ;
     RECT  9.889 157.056 10.177 157.32 ;
     RECT  10.067 58.944 10.181 59.256 ;
     RECT  10.073 62.736 10.211 62.904 ;
     RECT  8.104 220.128 10.211 220.152 ;
     RECT  10.211 62.736 10.253 62.76 ;
     RECT  9.425 61.344 10.289 61.368 ;
     RECT  9.749 70.416 10.289 98.76 ;
     RECT  10.001 146.4 10.289 151.032 ;
     RECT  9.395 226.608 10.307 227.448 ;
     RECT  10.109 100.032 10.321 118.152 ;
     RECT  9.251 154.992 10.321 155.592 ;
     RECT  10.181 59.04 10.325 59.256 ;
     RECT  8.104 186.96 10.355 186.984 ;
     RECT  10.321 154.992 10.361 155.688 ;
     RECT  9.461 68.16 10.397 68.712 ;
     RECT  10.289 75.216 10.469 98.76 ;
     RECT  9.749 133.152 10.501 137.544 ;
     RECT  9.821 138.528 10.501 139.368 ;
     RECT  10.177 157.008 10.501 157.32 ;
     RECT  10.105 158.304 10.501 159.72 ;
     RECT  10.421 13.632 10.505 13.656 ;
     RECT  10.289 70.416 10.541 74.088 ;
     RECT  10.109 119.184 10.549 129.24 ;
     RECT  9.353 130.32 10.549 131.592 ;
     RECT  10.321 99.744 10.685 118.152 ;
     RECT  10.289 146.4 10.721 150.456 ;
     RECT  10.469 75.6 10.753 98.76 ;
     RECT  10.685 99.744 10.753 107.16 ;
     RECT  10.753 75.6 10.754 107.16 ;
     RECT  10.325 59.232 10.789 59.256 ;
     RECT  10.397 68.592 10.789 68.712 ;
     RECT  8.104 181.584 10.789 181.608 ;
     RECT  9.539 160.992 10.825 161.016 ;
     RECT  9.889 162.048 10.825 163.704 ;
     RECT  8.273 164.736 10.825 164.76 ;
     RECT  10.789 68.592 10.829 68.952 ;
     RECT  10.501 157.008 10.829 159.72 ;
     RECT  10.789 181.488 10.829 181.608 ;
     RECT  10.789 59.232 10.835 59.736 ;
     RECT  10.829 157.008 10.861 159.432 ;
     RECT  10.037 65.952 10.865 65.976 ;
     RECT  10.541 70.848 10.865 74.088 ;
     RECT  10.825 164.736 10.865 164.856 ;
     RECT  8.104 235.104 10.883 235.128 ;
     RECT  10.501 133.152 10.897 139.368 ;
     RECT  10.685 108.288 10.901 118.152 ;
     RECT  10.861 156.768 10.901 159.432 ;
     RECT  8.243 206.928 10.931 206.952 ;
     RECT  10.549 119.184 10.933 131.592 ;
     RECT  10.897 132.672 10.933 139.368 ;
     RECT  10.829 68.64 10.937 68.952 ;
     RECT  10.754 75.6 10.937 91.32 ;
     RECT  9.821 140.688 10.969 145.32 ;
     RECT  10.721 146.4 10.969 150.264 ;
     RECT  10.537 57.6 10.979 57.624 ;
     RECT  10.865 73.968 11.009 74.088 ;
     RECT  10.969 140.688 11.009 150.264 ;
     RECT  10.901 108.288 11.027 111.336 ;
     RECT  8.104 187.968 11.027 187.992 ;
     RECT  10.933 119.184 11.041 139.368 ;
     RECT  11.009 140.688 11.045 145.08 ;
     RECT  10.829 181.488 11.075 181.512 ;
     RECT  10.001 153.168 11.077 153.816 ;
     RECT  10.361 155.04 11.081 155.688 ;
     RECT  10.937 76.224 11.117 91.32 ;
     RECT  11.009 146.064 11.117 150.264 ;
     RECT  11.027 108.384 11.123 111.336 ;
     RECT  11.041 119.184 11.149 139.512 ;
     RECT  11.117 146.352 11.189 150.264 ;
     RECT  10.754 92.304 11.261 107.16 ;
     RECT  11.261 92.304 11.333 107.064 ;
     RECT  11.189 146.352 11.369 148.2 ;
     RECT  10.901 112.368 11.437 118.152 ;
     RECT  11.149 119.184 11.437 139.56 ;
     RECT  8.104 175.008 11.459 175.032 ;
     RECT  10.825 160.992 11.461 163.704 ;
     RECT  10.865 70.848 11.477 72.552 ;
     RECT  11.461 160.752 11.513 163.704 ;
     RECT  11.045 140.688 11.549 144.792 ;
     RECT  11.437 112.368 11.689 139.56 ;
     RECT  11.189 149.328 11.693 150.264 ;
     RECT  11.617 66.096 11.747 66.12 ;
     RECT  11.477 70.848 11.761 70.968 ;
     RECT  11.077 152.208 11.761 153.816 ;
     RECT  11.081 155.04 11.761 155.592 ;
     RECT  11.549 140.976 11.788 144.792 ;
     RECT  11.513 162.384 11.833 163.704 ;
     RECT  10.865 164.832 11.833 164.856 ;
     RECT  11.761 152.208 11.843 155.592 ;
     RECT  11.833 162.384 11.873 164.856 ;
     RECT  11.009 74.016 11.905 74.088 ;
     RECT  11.689 112.368 11.905 139.992 ;
     RECT  11.477 72.048 11.941 72.552 ;
     RECT  11.905 74.016 11.977 74.232 ;
     RECT  11.612 75.216 11.977 75.24 ;
     RECT  8.104 199.296 12.035 199.32 ;
     RECT  10.307 226.608 12.083 226.632 ;
     RECT  11.693 149.472 12.121 150.264 ;
     RECT  11.369 146.448 12.125 148.2 ;
     RECT  11.905 112.32 12.161 139.992 ;
     RECT  11.873 162.624 12.197 164.856 ;
     RECT  11.761 70.704 12.233 70.968 ;
     RECT  11.843 153.168 12.233 155.592 ;
     RECT  11.123 108.432 12.277 111.336 ;
     RECT  12.161 112.32 12.277 138.072 ;
     RECT  12.233 70.704 12.337 70.872 ;
     RECT  11.977 74.016 12.337 75.24 ;
     RECT  11.117 76.272 12.337 91.32 ;
     RECT  11.941 72.048 12.373 72.6 ;
     RECT  12.337 74.016 12.373 91.32 ;
     RECT  11.333 92.352 12.373 107.064 ;
     RECT  11.513 160.752 12.373 161.016 ;
     RECT  10.937 68.64 12.481 68.664 ;
     RECT  12.373 72.048 12.517 72.936 ;
     RECT  12.373 74.016 12.517 107.064 ;
     RECT  12.277 108.432 12.517 138.072 ;
     RECT  10.901 156.768 12.517 159.192 ;
     RECT  12.337 70.608 12.625 70.872 ;
     RECT  12.121 149.472 12.733 150.504 ;
     RECT  12.733 149.184 12.913 150.504 ;
     RECT  12.373 160.704 13.057 161.016 ;
     RECT  12.197 162.624 13.057 163.704 ;
     RECT  12.913 149.184 13.093 151.368 ;
     RECT  11.653 36.528 13.208 36.552 ;
     RECT  9.683 53.808 13.208 53.832 ;
     RECT  10.835 59.712 13.208 59.736 ;
     RECT  12.481 68.64 13.208 68.952 ;
     RECT  12.625 70.464 13.208 70.872 ;
     RECT  12.517 72.048 13.208 138.072 ;
     RECT  12.161 139.344 13.208 139.992 ;
     RECT  11.788 140.976 13.208 143.976 ;
     RECT  12.157 145.344 13.208 145.368 ;
     RECT  12.125 146.448 13.208 147.336 ;
     RECT  13.093 149.184 13.208 152.184 ;
     RECT  12.233 153.168 13.208 153.912 ;
     RECT  12.233 155.04 13.208 155.592 ;
     RECT  12.517 156.672 13.208 159.192 ;
     RECT  13.057 160.704 13.208 163.704 ;
     RECT  12.197 164.832 13.208 164.856 ;
     RECT  8.867 171.216 13.208 171.24 ;
     RECT  8.867 172.32 13.208 172.344 ;
     RECT  8.104 173.952 13.208 173.976 ;
     RECT  8.104 176.64 13.208 176.664 ;
     RECT  8.104 178.272 13.208 178.296 ;
     RECT  8.104 193.92 13.208 193.944 ;
     RECT  13.208 2.148 13.312 244.092 ;
     RECT  13.312 2.418 13.504 243.822 ;
     RECT  13.504 73.872 13.619 130.824 ;
     RECT  13.504 152.928 13.619 153.768 ;
     RECT  13.504 131.808 13.637 139.56 ;
     RECT  13.504 157.872 13.637 159.192 ;
     RECT  13.637 139.056 13.66 139.56 ;
     RECT  13.619 152.928 13.673 153.624 ;
     RECT  13.673 153.168 13.708 153.624 ;
     RECT  13.637 157.872 13.745 157.896 ;
     RECT  13.504 36.528 13.859 36.552 ;
     RECT  13.504 178.272 13.955 178.296 ;
     RECT  13.504 156.672 13.997 156.696 ;
     RECT  13.637 159.12 14.213 159.192 ;
     RECT  13.619 74.016 14.221 130.824 ;
     RECT  13.504 146.448 14.249 148.008 ;
     RECT  13.504 160.848 14.249 163.704 ;
     RECT  13.504 145.344 14.291 145.368 ;
     RECT  13.504 164.736 14.501 165.048 ;
     RECT  13.637 131.808 14.509 137.592 ;
     RECT  13.504 141.216 14.533 143.736 ;
     RECT  14.497 144.72 14.533 144.744 ;
     RECT  13.504 149.616 14.537 150.6 ;
     RECT  13.504 72.144 14.569 72.36 ;
     RECT  14.221 92.4 14.605 130.824 ;
     RECT  14.509 131.808 14.605 136.488 ;
     RECT  14.537 149.616 14.609 150.504 ;
     RECT  13.504 155.04 14.641 155.496 ;
     RECT  14.533 141.216 14.681 144.744 ;
     RECT  14.249 161.808 14.717 163.704 ;
     RECT  14.221 74.016 14.749 91.224 ;
     RECT  14.509 137.568 14.789 137.592 ;
     RECT  13.504 171.216 14.821 171.24 ;
     RECT  14.605 92.4 14.825 136.488 ;
     RECT  14.609 149.952 14.825 150.504 ;
     RECT  14.213 159.12 14.861 159.144 ;
     RECT  14.821 171.216 14.861 171.336 ;
     RECT  14.857 160.752 14.969 160.776 ;
     RECT  13.708 153.168 15.107 153.192 ;
     RECT  13.66 139.392 15.149 139.512 ;
     RECT  14.569 72.096 15.181 72.36 ;
     RECT  14.749 73.344 15.181 91.224 ;
     RECT  14.249 146.544 15.181 148.008 ;
     RECT  14.501 164.736 15.217 164.76 ;
     RECT  15.181 146.544 15.265 148.248 ;
     RECT  15.181 72.096 15.293 91.224 ;
     RECT  15.149 139.392 15.361 139.416 ;
     RECT  15.265 146.544 15.397 147.336 ;
     RECT  15.361 139.152 15.505 139.416 ;
     RECT  15.397 146.496 15.613 147.336 ;
     RECT  14.641 155.04 15.617 155.544 ;
     RECT  14.681 141.936 15.731 144.648 ;
     RECT  15.433 140.496 15.757 140.52 ;
     RECT  15.731 141.936 15.757 142.68 ;
     RECT  15.731 143.712 15.901 144.648 ;
     RECT  15.613 145.776 15.901 147.336 ;
     RECT  14.717 161.856 15.971 163.704 ;
     RECT  15.971 163.68 15.973 163.704 ;
     RECT  15.217 164.688 15.973 164.76 ;
     RECT  15.829 160.176 16.009 160.2 ;
     RECT  15.505 138.336 16.013 139.416 ;
     RECT  15.973 163.68 16.013 164.76 ;
     RECT  15.901 143.712 16.049 147.336 ;
     RECT  14.825 92.448 16.081 136.488 ;
     RECT  15.617 155.136 16.121 155.544 ;
     RECT  15.293 72.144 16.213 91.224 ;
     RECT  16.081 92.448 16.213 136.584 ;
     RECT  14.825 149.952 16.337 150.312 ;
     RECT  16.225 157.392 16.441 157.8 ;
     RECT  16.121 155.136 16.451 155.448 ;
     RECT  15.757 140.496 16.481 142.68 ;
     RECT  16.213 72.144 16.589 136.584 ;
     RECT  15.901 148.896 16.661 148.968 ;
     RECT  16.013 138.432 16.697 139.416 ;
     RECT  16.441 157.008 16.697 157.8 ;
     RECT  15.971 161.856 16.769 162.648 ;
     RECT  16.481 140.496 16.801 142.488 ;
     RECT  16.337 149.952 16.981 149.976 ;
     RECT  16.009 160.176 17.089 160.776 ;
     RECT  16.049 143.712 17.125 144.312 ;
     RECT  17.125 143.568 17.305 144.312 ;
     RECT  16.049 145.536 17.305 147.336 ;
     RECT  17.305 143.568 17.309 147.336 ;
     RECT  15.505 153.312 17.413 153.336 ;
     RECT  16.589 72.144 17.459 72.984 ;
     RECT  16.769 162.384 17.485 162.648 ;
     RECT  16.589 74.016 17.557 136.584 ;
     RECT  16.451 155.232 17.621 155.448 ;
     RECT  16.697 138.432 17.633 139.224 ;
     RECT  17.557 74.016 17.641 136.824 ;
     RECT  16.697 157.008 17.701 157.032 ;
     RECT  17.485 162.384 17.701 162.792 ;
     RECT  17.701 156.528 17.845 157.032 ;
     RECT  17.317 151.632 18.053 151.656 ;
     RECT  17.089 160.176 18.097 161.304 ;
     RECT  17.701 162.384 18.097 162.936 ;
     RECT  18.097 160.176 18.229 162.936 ;
     RECT  17.413 152.928 18.565 153.336 ;
     RECT  13.504 59.712 18.608 59.736 ;
     RECT  13.504 68.64 18.608 69.48 ;
     RECT  17.459 72.144 18.608 72.696 ;
     RECT  17.641 74.016 18.608 136.488 ;
     RECT  17.633 139.152 18.608 139.224 ;
     RECT  16.801 140.304 18.608 142.488 ;
     RECT  17.309 143.712 18.608 147.336 ;
     RECT  16.981 149.136 18.608 149.976 ;
     RECT  18.053 151.056 18.608 151.656 ;
     RECT  18.565 152.88 18.608 153.336 ;
     RECT  17.621 154.464 18.608 155.448 ;
     RECT  17.845 156.528 18.608 157.224 ;
     RECT  18.229 159.408 18.608 162.936 ;
     RECT  16.013 163.968 18.608 164.76 ;
     RECT  14.861 171.312 18.608 171.336 ;
     RECT  13.504 173.952 18.608 173.976 ;
     RECT  18.608 2.148 18.712 244.092 ;
     RECT  18.712 2.418 18.904 243.822 ;
     RECT  18.904 152.88 19.001 153.192 ;
     RECT  18.904 74.016 19.037 136.488 ;
     RECT  18.904 150.48 19.043 150.792 ;
     RECT  18.904 138.528 19.081 139.224 ;
     RECT  18.904 161.28 19.091 161.592 ;
     RECT  19.043 150.48 19.109 150.552 ;
     RECT  18.904 145.344 19.145 146.76 ;
     RECT  19.081 138.912 19.181 139.224 ;
     RECT  19.109 150.528 19.181 150.552 ;
     RECT  18.904 140.736 19.187 143.736 ;
     RECT  19.037 74.016 19.217 136.248 ;
     RECT  19.217 74.016 19.427 85.704 ;
     RECT  19.145 145.68 19.427 146.76 ;
     RECT  18.904 158.832 19.469 159.432 ;
     RECT  19.427 74.016 19.475 74.664 ;
     RECT  19.187 140.736 19.541 143.304 ;
     RECT  19.001 153.168 19.541 153.192 ;
     RECT  18.904 170.976 19.541 171.336 ;
     RECT  19.469 159.168 19.613 159.432 ;
     RECT  19.541 140.736 19.721 142.632 ;
     RECT  18.904 72.144 19.811 72.696 ;
     RECT  18.904 68.64 19.859 69.48 ;
     RECT  19.721 140.736 19.901 142.488 ;
     RECT  19.181 138.96 19.933 139.224 ;
     RECT  19.901 140.736 19.933 141.576 ;
     RECT  19.217 86.736 20.005 136.248 ;
     RECT  18.904 156.432 20.009 157.032 ;
     RECT  19.933 138.96 20.017 141.576 ;
     RECT  20.005 86.736 20.092 136.44 ;
     RECT  18.904 154.512 20.101 155.352 ;
     RECT  19.427 145.68 20.117 146.424 ;
     RECT  20.117 145.824 20.147 146.424 ;
     RECT  19.427 75.648 20.153 85.704 ;
     RECT  20.153 77.616 20.185 85.704 ;
     RECT  20.092 86.736 20.185 135.96 ;
     RECT  20.017 138.96 20.261 139.368 ;
     RECT  20.101 154.464 20.291 155.352 ;
     RECT  19.613 159.168 20.291 159.336 ;
     RECT  20.291 155.328 20.3 155.352 ;
     RECT  20.017 140.736 20.387 141.576 ;
     RECT  20.147 146.4 20.387 146.424 ;
     RECT  20.3 155.328 20.387 155.496 ;
     RECT  20.291 159.312 20.387 159.336 ;
     RECT  20.185 77.616 20.483 135.96 ;
     RECT  20.483 77.616 20.549 121.896 ;
     RECT  20.387 140.736 20.549 140.76 ;
     RECT  20.483 122.928 20.765 135.96 ;
     RECT  20.261 139.2 20.801 139.368 ;
     RECT  20.153 75.648 20.819 76.584 ;
     RECT  20.549 77.616 21.053 121.656 ;
     RECT  21.013 150.48 21.097 150.504 ;
     RECT  19.475 74.016 21.305 74.616 ;
     RECT  21.053 77.904 21.541 121.656 ;
     RECT  20.765 122.928 21.541 135.672 ;
     RECT  21.541 77.904 21.557 135.672 ;
     RECT  20.801 139.344 21.737 139.368 ;
     RECT  21.557 77.904 22.169 135.144 ;
     RECT  20.819 75.648 22.201 76.248 ;
     RECT  22.169 77.904 22.201 134.616 ;
     RECT  18.904 173.952 22.381 173.976 ;
     RECT  20.009 157.008 22.453 157.032 ;
     RECT  19.541 170.976 22.499 171 ;
     RECT  22.381 173.856 22.499 173.976 ;
     RECT  22.201 75.648 22.691 134.616 ;
     RECT  18.904 59.712 22.811 59.784 ;
     RECT  19.811 72.672 22.813 72.696 ;
     RECT  22.811 59.712 22.853 59.832 ;
     RECT  22.813 72.672 22.853 72.792 ;
     RECT  22.691 75.648 22.853 127.368 ;
     RECT  22.499 173.952 22.853 173.976 ;
     RECT  22.853 75.744 22.925 127.368 ;
     RECT  22.853 59.76 24.008 59.832 ;
     RECT  19.859 69.456 24.008 69.48 ;
     RECT  22.853 72.768 24.008 72.792 ;
     RECT  21.305 74.592 24.008 74.616 ;
     RECT  22.925 75.744 24.008 76.296 ;
     RECT  22.925 77.712 24.008 127.368 ;
     RECT  22.691 128.784 24.008 134.616 ;
     RECT  20.387 155.328 24.008 155.352 ;
     RECT  22.453 156.672 24.008 157.032 ;
     RECT  18.904 164.736 24.008 164.76 ;
     RECT  24.008 2.148 24.112 244.092 ;
     RECT  24.112 2.418 24.304 243.822 ;
     RECT  24.304 82.32 24.419 98.424 ;
     RECT  24.304 116.736 24.437 125.928 ;
     RECT  24.419 84.048 24.467 98.424 ;
     RECT  24.304 99.696 24.473 115.416 ;
     RECT  24.467 88.128 24.509 98.424 ;
     RECT  24.437 117.024 24.509 125.928 ;
     RECT  24.467 84.144 24.515 87.048 ;
     RECT  24.509 117.024 24.515 118.728 ;
     RECT  24.509 119.712 24.515 125.928 ;
     RECT  24.304 78.432 24.563 78.504 ;
     RECT  24.515 117.024 24.581 118.632 ;
     RECT  24.473 99.696 24.617 115.368 ;
     RECT  24.617 112.416 24.624 115.368 ;
     RECT  24.509 94.848 24.653 98.424 ;
     RECT  24.515 84.624 24.755 87.048 ;
     RECT  24.624 112.416 24.761 114.168 ;
     RECT  24.515 119.712 24.761 124.824 ;
     RECT  24.755 84.624 24.803 87 ;
     RECT  24.761 119.712 24.833 120.936 ;
     RECT  24.803 84.624 24.851 85.704 ;
     RECT  24.617 99.696 24.869 111.432 ;
     RECT  24.419 82.32 24.899 83.064 ;
     RECT  24.869 99.696 24.941 107.592 ;
     RECT  24.851 84.624 24.947 84.888 ;
     RECT  24.653 96 24.947 98.424 ;
     RECT  24.509 88.128 24.995 93.864 ;
     RECT  24.941 100.752 24.995 107.592 ;
     RECT  24.833 119.712 25.049 120.072 ;
     RECT  24.761 121.968 25.049 124.824 ;
     RECT  24.899 82.32 25.139 82.68 ;
     RECT  24.995 100.752 25.139 104.424 ;
     RECT  24.581 117.024 25.165 117.96 ;
     RECT  25.049 121.968 25.187 124.68 ;
     RECT  25.139 100.752 25.193 101.448 ;
     RECT  24.304 132.432 25.235 132.456 ;
     RECT  24.563 78.432 25.283 78.456 ;
     RECT  24.304 133.776 25.283 134.616 ;
     RECT  24.995 105.408 25.301 107.592 ;
     RECT  24.304 80.016 25.331 80.808 ;
     RECT  24.304 128.88 25.331 130.776 ;
     RECT  25.193 100.752 25.379 101.112 ;
     RECT  25.331 130.752 25.379 130.776 ;
     RECT  25.331 80.064 25.697 80.808 ;
     RECT  24.995 90 25.715 93.864 ;
     RECT  24.304 75.744 25.763 76.296 ;
     RECT  25.165 117.024 25.763 117.336 ;
     RECT  25.139 82.512 25.811 82.68 ;
     RECT  25.139 102.48 25.811 104.424 ;
     RECT  24.304 127.344 25.811 127.368 ;
     RECT  25.715 90 25.859 93.48 ;
     RECT  25.811 102.48 25.859 104.328 ;
     RECT  25.763 76.272 25.907 76.296 ;
     RECT  25.187 123.216 25.907 124.68 ;
     RECT  24.995 88.128 26.233 88.68 ;
     RECT  25.859 90 26.233 90.552 ;
     RECT  24.304 72.768 26.243 72.792 ;
     RECT  25.763 117.312 26.243 117.336 ;
     RECT  25.907 123.84 26.273 124.68 ;
     RECT  26.233 88.128 26.317 90.552 ;
     RECT  26.317 90 26.339 90.552 ;
     RECT  24.947 96 26.339 98.232 ;
     RECT  24.941 99.696 26.339 99.72 ;
     RECT  25.187 121.968 26.339 121.992 ;
     RECT  25.859 91.92 26.387 93.48 ;
     RECT  26.339 96 26.387 98.088 ;
     RECT  25.301 105.408 26.629 106.2 ;
     RECT  24.761 113.856 26.773 114.168 ;
     RECT  24.869 108.864 26.777 111.432 ;
     RECT  26.387 92.208 26.813 93.48 ;
     RECT  25.049 120.048 26.813 120.072 ;
     RECT  24.304 69.456 26.819 69.48 ;
     RECT  24.304 156.672 26.819 157.032 ;
     RECT  25.859 102.48 26.849 103.512 ;
     RECT  24.304 74.592 26.867 74.616 ;
     RECT  25.283 134.592 26.867 134.616 ;
     RECT  25.697 80.784 26.885 80.808 ;
     RECT  24.304 59.76 27.101 59.832 ;
     RECT  26.317 88.128 27.137 88.68 ;
     RECT  27.101 59.76 27.281 59.784 ;
     RECT  24.803 86.976 27.389 87 ;
     RECT  27.137 88.128 27.425 88.152 ;
     RECT  25.301 107.568 27.461 107.592 ;
     RECT  26.813 92.208 27.641 93.336 ;
     RECT  26.273 124.608 27.749 124.68 ;
     RECT  26.773 113.856 27.857 114.312 ;
     RECT  26.777 109.152 28.217 111.432 ;
     RECT  24.515 125.904 28.217 125.928 ;
     RECT  25.811 82.656 29.408 82.68 ;
     RECT  24.947 84.864 29.408 84.888 ;
     RECT  26.339 90.528 29.408 90.552 ;
     RECT  27.641 92.928 29.408 93.336 ;
     RECT  24.653 94.848 29.408 94.872 ;
     RECT  26.387 96 29.408 97.56 ;
     RECT  25.379 100.752 29.408 100.872 ;
     RECT  26.849 102.72 29.408 103.512 ;
     RECT  26.629 105.408 29.408 106.248 ;
     RECT  28.217 109.152 29.408 110.664 ;
     RECT  24.761 112.416 29.408 112.44 ;
     RECT  27.857 114.288 29.408 114.312 ;
     RECT  24.624 115.344 29.408 115.368 ;
     RECT  27.749 124.656 29.408 124.68 ;
     RECT  25.331 128.88 29.408 129.48 ;
     RECT  24.304 155.328 29.408 155.352 ;
     RECT  26.819 156.672 29.408 156.696 ;
     RECT  24.304 164.736 29.408 164.76 ;
     RECT  29.408 2.148 29.512 244.092 ;
     RECT  29.512 2.418 29.704 243.822 ;
     RECT  29.704 102.72 30.233 103.512 ;
     RECT  29.704 114.288 30.233 114.312 ;
     RECT  29.704 84.864 30.485 84.888 ;
     RECT  29.704 96 30.485 97.56 ;
     RECT  30.233 102.72 30.485 102.744 ;
     RECT  29.704 92.928 31.637 93.336 ;
     RECT  29.704 109.152 31.813 110.664 ;
     RECT  31.637 92.928 33.365 92.952 ;
     RECT  29.704 82.656 34.808 82.68 ;
     RECT  29.704 90.528 34.808 90.552 ;
     RECT  29.704 94.848 34.808 94.872 ;
     RECT  30.485 96 34.808 96.024 ;
     RECT  30.485 97.536 34.808 97.56 ;
     RECT  29.704 100.752 34.808 100.872 ;
     RECT  29.704 105.408 34.808 106.248 ;
     RECT  31.813 109.152 34.808 110.76 ;
     RECT  29.704 112.416 34.808 112.44 ;
     RECT  29.704 124.656 34.808 124.68 ;
     RECT  29.704 128.88 34.808 129.48 ;
     RECT  29.704 155.328 34.808 155.352 ;
     RECT  29.704 156.672 34.808 156.696 ;
     RECT  29.704 164.736 34.808 164.76 ;
     RECT  34.808 2.148 34.912 244.092 ;
     RECT  34.912 2.418 35.104 243.822 ;
     RECT  35.104 128.88 37.757 129.48 ;
     RECT  37.757 128.88 38.225 128.904 ;
     RECT  38.833 129.36 38.917 129.384 ;
     RECT  35.104 90.528 39.481 90.552 ;
     RECT  35.104 156.672 40.129 156.696 ;
     RECT  35.104 82.656 40.208 82.68 ;
     RECT  39.481 90.528 40.208 90.6 ;
     RECT  35.104 94.848 40.208 94.872 ;
     RECT  35.104 96 40.208 96.024 ;
     RECT  35.104 97.536 40.208 97.56 ;
     RECT  35.104 100.752 40.208 100.872 ;
     RECT  35.104 105.408 40.208 106.248 ;
     RECT  35.104 109.152 40.208 110.76 ;
     RECT  35.104 112.416 40.208 112.44 ;
     RECT  35.104 124.656 40.208 124.68 ;
     RECT  38.869 139.488 40.208 139.512 ;
     RECT  35.104 155.328 40.208 155.352 ;
     RECT  40.129 156.48 40.208 156.696 ;
     RECT  35.104 164.736 40.208 164.76 ;
     RECT  40.208 2.148 40.312 244.092 ;
     RECT  40.312 2.418 40.504 243.822 ;
     RECT  40.504 156.48 40.529 156.696 ;
     RECT  40.504 139.488 40.601 139.656 ;
     RECT  40.504 82.656 44.237 82.68 ;
     RECT  40.504 90.576 45.608 90.6 ;
     RECT  40.504 94.848 45.608 94.872 ;
     RECT  40.504 96 45.608 96.024 ;
     RECT  40.504 97.536 45.608 97.56 ;
     RECT  40.504 100.752 45.608 100.872 ;
     RECT  40.504 105.408 45.608 106.248 ;
     RECT  40.504 109.152 45.608 110.76 ;
     RECT  40.504 112.416 45.608 112.44 ;
     RECT  40.504 124.656 45.608 124.68 ;
     RECT  40.601 139.632 45.608 139.656 ;
     RECT  40.504 155.328 45.608 155.352 ;
     RECT  40.529 156.48 45.608 156.504 ;
     RECT  40.504 164.736 45.608 164.76 ;
     RECT  45.608 2.148 45.712 244.092 ;
     RECT  45.712 2.418 45.904 243.822 ;
     RECT  45.904 109.152 50.713 110.76 ;
     RECT  45.904 90.576 51.008 90.6 ;
     RECT  45.904 94.848 51.008 94.872 ;
     RECT  45.904 96 51.008 96.024 ;
     RECT  45.904 97.536 51.008 97.56 ;
     RECT  45.904 100.752 51.008 100.872 ;
     RECT  45.904 105.408 51.008 106.248 ;
     RECT  50.713 109.152 51.008 110.808 ;
     RECT  45.904 112.416 51.008 112.44 ;
     RECT  45.904 124.656 51.008 124.68 ;
     RECT  45.904 139.632 51.008 139.656 ;
     RECT  45.904 155.328 51.008 155.352 ;
     RECT  45.904 156.48 51.008 156.504 ;
     RECT  45.904 164.736 51.008 164.76 ;
     RECT  51.008 2.148 51.112 244.092 ;
     RECT  51.112 2.418 51.304 243.822 ;
     RECT  51.304 109.152 52.157 110.808 ;
     RECT  51.304 112.416 52.981 112.44 ;
     RECT  52.981 112.176 53.305 112.44 ;
     RECT  53.305 111.744 53.389 112.44 ;
     RECT  53.701 134.544 53.785 134.568 ;
     RECT  53.701 123.648 53.797 123.672 ;
     RECT  53.389 112.176 53.843 112.44 ;
     RECT  53.797 123.504 53.843 123.672 ;
     RECT  55.205 135.072 55.289 135.096 ;
     RECT  51.304 90.576 56.408 90.6 ;
     RECT  51.304 94.848 56.408 94.872 ;
     RECT  51.304 96 56.408 96.024 ;
     RECT  51.304 97.536 56.408 97.56 ;
     RECT  51.304 100.752 56.408 100.872 ;
     RECT  51.304 105.408 56.408 106.248 ;
     RECT  52.157 109.152 56.408 110.76 ;
     RECT  53.843 112.416 56.408 112.44 ;
     RECT  53.843 123.504 56.408 123.528 ;
     RECT  51.304 124.656 56.408 124.68 ;
     RECT  51.304 139.632 56.408 139.656 ;
     RECT  54.277 146.688 56.408 146.712 ;
     RECT  51.304 155.328 56.408 155.352 ;
     RECT  51.304 156.48 56.408 156.504 ;
     RECT  51.304 164.736 56.408 164.76 ;
     RECT  56.408 2.148 56.512 244.092 ;
     RECT  56.512 2.418 56.704 243.822 ;
     RECT  56.704 90.576 61.808 90.6 ;
     RECT  56.704 94.848 61.808 94.872 ;
     RECT  56.704 96 61.808 96.024 ;
     RECT  56.704 97.536 61.808 97.56 ;
     RECT  56.704 100.752 61.808 100.872 ;
     RECT  56.704 105.408 61.808 106.248 ;
     RECT  56.704 109.152 61.808 111.048 ;
     RECT  56.704 112.416 61.808 112.44 ;
     RECT  56.704 123.504 61.808 123.528 ;
     RECT  56.704 124.656 61.808 124.68 ;
     RECT  56.704 139.632 61.808 139.656 ;
     RECT  56.704 146.688 61.808 146.712 ;
     RECT  56.704 155.328 61.808 155.352 ;
     RECT  56.704 156.48 61.808 156.504 ;
     RECT  56.704 164.736 61.808 164.76 ;
     RECT  61.808 2.148 61.912 244.092 ;
     RECT  61.912 2.418 62.104 243.822 ;
     RECT  62.104 100.752 63.677 100.872 ;
     RECT  62.104 90.576 67.208 90.6 ;
     RECT  62.104 94.848 67.208 94.872 ;
     RECT  62.104 96 67.208 96.024 ;
     RECT  62.104 97.536 67.208 97.56 ;
     RECT  63.677 100.752 67.208 100.776 ;
     RECT  62.104 105.408 67.208 106.248 ;
     RECT  62.104 109.152 67.208 111.048 ;
     RECT  62.104 112.416 67.208 112.44 ;
     RECT  62.104 123.504 67.208 123.528 ;
     RECT  62.104 124.656 67.208 124.68 ;
     RECT  62.104 139.632 67.208 139.656 ;
     RECT  62.104 146.688 67.208 146.712 ;
     RECT  62.104 155.328 67.208 155.352 ;
     RECT  62.104 156.48 67.208 156.504 ;
     RECT  63.385 161.808 67.208 161.832 ;
     RECT  62.104 164.736 67.208 164.76 ;
     RECT  67.208 2.148 67.312 244.092 ;
     RECT  67.312 2.418 67.504 243.822 ;
     RECT  67.504 155.328 68.749 155.352 ;
     RECT  68.749 155.328 68.917 156.216 ;
     RECT  68.917 154.512 68.963 156.216 ;
     RECT  67.504 96 70.409 96.024 ;
     RECT  67.504 164.736 70.693 164.76 ;
     RECT  70.693 164.736 70.733 164.856 ;
     RECT  68.963 154.512 71.269 155.352 ;
     RECT  67.504 139.632 71.317 139.656 ;
     RECT  67.504 90.528 72.608 90.552 ;
     RECT  67.504 94.848 72.608 94.872 ;
     RECT  67.504 97.536 72.608 97.56 ;
     RECT  67.504 100.752 72.608 100.776 ;
     RECT  67.504 105.408 72.608 106.248 ;
     RECT  67.504 109.152 72.608 111.048 ;
     RECT  67.504 112.416 72.608 112.44 ;
     RECT  67.504 123.504 72.608 123.528 ;
     RECT  67.504 124.656 72.608 124.68 ;
     RECT  67.504 146.688 72.608 146.712 ;
     RECT  71.269 154.08 72.608 155.352 ;
     RECT  67.504 161.808 72.608 161.832 ;
     RECT  70.733 164.832 72.608 164.856 ;
     RECT  72.608 2.148 72.712 244.092 ;
     RECT  72.712 2.418 72.904 243.822 ;
     RECT  72.904 164.736 73.235 164.856 ;
     RECT  73.235 164.736 73.523 164.76 ;
     RECT  72.904 123.504 74.653 123.528 ;
     RECT  74.653 123.408 74.693 123.528 ;
     RECT  72.904 215.52 76.705 215.544 ;
     RECT  74.693 123.408 76.957 123.432 ;
     RECT  77.797 242.544 77.845 242.568 ;
     RECT  77.845 246.096 77.987 246.12 ;
     RECT  72.904 90.528 78.008 90.552 ;
     RECT  72.904 94.848 78.008 94.872 ;
     RECT  72.904 97.536 78.008 97.56 ;
     RECT  72.904 100.752 78.008 100.776 ;
     RECT  72.904 105.408 78.008 106.248 ;
     RECT  72.904 109.152 78.008 111.048 ;
     RECT  72.904 112.416 78.008 112.44 ;
     RECT  76.957 123.408 78.008 123.576 ;
     RECT  72.904 124.656 78.008 124.68 ;
     RECT  72.904 146.688 78.008 146.712 ;
     RECT  72.904 154.08 78.008 155.352 ;
     RECT  72.904 161.808 78.008 161.832 ;
     RECT  76.705 215.52 78.008 216.36 ;
     RECT  77.797 239.136 78.008 239.16 ;
     RECT  77.845 242.544 78.008 242.808 ;
     RECT  78.008 2.148 78.112 244.092 ;
     RECT  78.112 2.418 78.304 243.822 ;
     RECT  78.304 90.528 83.408 90.552 ;
     RECT  78.304 94.848 83.408 94.872 ;
     RECT  78.304 97.536 83.408 97.56 ;
     RECT  78.304 105.408 83.408 106.248 ;
     RECT  78.304 109.152 83.408 111.048 ;
     RECT  78.304 112.416 83.408 112.44 ;
     RECT  78.304 124.656 83.408 124.68 ;
     RECT  78.304 146.688 83.408 146.712 ;
     RECT  78.304 154.08 83.408 155.352 ;
     RECT  78.304 161.808 83.408 161.832 ;
     RECT  83.408 2.148 83.512 244.092 ;
     RECT  83.512 2.418 83.704 243.822 ;
     RECT  83.704 90.528 88.808 90.552 ;
     RECT  83.704 94.848 88.808 94.872 ;
     RECT  83.704 97.536 88.808 97.56 ;
     RECT  83.704 105.408 88.808 106.248 ;
     RECT  83.704 109.152 88.808 111.048 ;
     RECT  83.704 112.416 88.808 112.44 ;
     RECT  83.704 124.656 88.808 124.68 ;
     RECT  83.704 146.688 88.808 146.712 ;
     RECT  83.704 154.08 88.808 155.352 ;
     RECT  83.704 161.808 88.808 161.832 ;
     RECT  88.808 2.148 88.912 244.092 ;
     RECT  88.912 2.418 89.104 243.822 ;
     RECT  89.104 97.536 94.069 97.56 ;
     RECT  89.104 90.528 94.208 90.552 ;
     RECT  89.104 94.848 94.208 94.872 ;
     RECT  94.069 97.488 94.208 97.56 ;
     RECT  89.104 105.408 94.208 106.248 ;
     RECT  89.104 109.152 94.208 111.048 ;
     RECT  89.104 112.416 94.208 112.44 ;
     RECT  89.104 124.656 94.208 124.68 ;
     RECT  89.104 146.688 94.208 146.712 ;
     RECT  89.104 154.08 94.208 154.536 ;
     RECT  89.104 161.808 94.208 161.832 ;
     RECT  94.208 2.148 94.312 244.092 ;
     RECT  94.312 2.418 94.504 243.822 ;
     RECT  94.504 97.776 95.852 97.8 ;
     RECT  95.852 97.776 95.893 98.088 ;
     RECT  95.893 97.776 95.977 98.184 ;
     RECT  94.504 94.848 99.608 94.872 ;
     RECT  95.977 97.776 99.608 97.8 ;
     RECT  94.504 105.408 99.608 106.248 ;
     RECT  94.504 109.152 99.608 111.048 ;
     RECT  94.504 112.416 99.608 112.44 ;
     RECT  94.504 124.656 99.608 124.68 ;
     RECT  94.504 146.688 99.608 146.712 ;
     RECT  94.504 154.08 99.608 154.536 ;
     RECT  94.504 161.808 99.608 161.832 ;
     RECT  99.608 2.148 99.712 244.092 ;
     RECT  99.712 2.418 99.904 243.822 ;
     RECT  99.904 154.08 100.217 154.536 ;
     RECT  100.217 154.08 101.725 154.344 ;
     RECT  101.725 154.08 103.453 154.536 ;
     RECT  103.453 153.888 103.537 154.536 ;
     RECT  103.537 154.08 103.637 154.536 ;
     RECT  99.904 94.848 105.008 94.872 ;
     RECT  99.904 97.776 105.008 97.8 ;
     RECT  99.904 105.408 105.008 106.248 ;
     RECT  99.904 109.152 105.008 111.048 ;
     RECT  99.904 112.416 105.008 112.44 ;
     RECT  103.477 122.64 105.008 122.664 ;
     RECT  99.904 124.656 105.008 124.68 ;
     RECT  99.904 146.688 105.008 146.712 ;
     RECT  103.637 154.272 105.008 154.536 ;
     RECT  99.904 161.808 105.008 161.832 ;
     RECT  105.008 2.148 105.112 244.092 ;
     RECT  105.112 2.418 105.304 243.822 ;
     RECT  105.304 94.848 110.408 94.872 ;
     RECT  105.304 97.776 110.408 97.8 ;
     RECT  105.304 105.408 110.408 106.248 ;
     RECT  105.304 109.152 110.408 111.048 ;
     RECT  105.304 112.416 110.408 112.44 ;
     RECT  105.304 122.64 110.408 122.664 ;
     RECT  105.304 124.656 110.408 124.68 ;
     RECT  105.304 146.688 110.408 146.712 ;
     RECT  105.304 154.272 110.408 154.536 ;
     RECT  105.304 161.808 110.408 161.832 ;
     RECT  110.408 2.148 110.512 244.092 ;
     RECT  110.512 2.418 110.704 243.822 ;
     RECT  110.704 94.848 115.808 94.872 ;
     RECT  110.704 97.776 115.808 97.8 ;
     RECT  110.704 105.408 115.808 106.248 ;
     RECT  110.704 109.152 115.808 111.048 ;
     RECT  110.704 112.416 115.808 112.44 ;
     RECT  110.704 122.64 115.808 122.664 ;
     RECT  110.704 124.656 115.808 124.68 ;
     RECT  110.704 146.688 115.808 146.712 ;
     RECT  110.704 154.272 115.808 154.536 ;
     RECT  110.704 161.808 115.808 161.832 ;
     RECT  115.808 2.148 115.912 244.092 ;
     RECT  115.912 2.418 116.104 243.822 ;
     RECT  116.104 94.848 121.208 94.872 ;
     RECT  116.104 97.776 121.208 97.8 ;
     RECT  116.104 105.408 121.208 106.248 ;
     RECT  116.104 109.152 121.208 111.048 ;
     RECT  116.104 112.416 121.208 112.44 ;
     RECT  116.104 122.64 121.208 122.664 ;
     RECT  116.104 124.656 121.208 124.68 ;
     RECT  116.104 146.688 121.208 146.712 ;
     RECT  116.104 154.272 121.208 154.536 ;
     RECT  116.104 161.808 121.208 161.832 ;
     RECT  121.208 2.148 121.312 244.092 ;
     RECT  121.312 2.418 121.504 243.822 ;
     RECT  121.504 94.848 126.608 94.872 ;
     RECT  121.504 97.776 126.608 97.8 ;
     RECT  121.504 105.408 126.608 106.248 ;
     RECT  121.504 109.152 126.608 111.048 ;
     RECT  121.504 112.416 126.608 112.44 ;
     RECT  121.504 122.64 126.608 122.664 ;
     RECT  121.504 124.656 126.608 124.68 ;
     RECT  121.504 146.688 126.608 146.712 ;
     RECT  121.504 154.272 126.608 154.536 ;
     RECT  121.504 161.808 126.608 161.832 ;
     RECT  126.608 2.148 126.712 244.092 ;
     RECT  126.712 2.418 126.904 243.822 ;
     RECT  126.904 94.848 132.008 94.872 ;
     RECT  126.904 97.776 132.008 97.8 ;
     RECT  126.904 105.408 132.008 106.248 ;
     RECT  126.904 109.152 132.008 111.048 ;
     RECT  126.904 112.416 132.008 112.44 ;
     RECT  126.904 122.64 132.008 122.664 ;
     RECT  126.904 124.656 132.008 124.68 ;
     RECT  126.904 146.688 132.008 146.712 ;
     RECT  126.904 154.272 132.008 154.536 ;
     RECT  126.904 161.808 132.008 161.832 ;
     RECT  132.008 2.148 132.112 244.092 ;
     RECT  132.112 2.418 132.304 243.822 ;
     RECT  132.304 94.848 137.408 94.872 ;
     RECT  132.304 97.776 137.408 97.8 ;
     RECT  132.304 105.408 137.408 106.248 ;
     RECT  132.304 109.152 137.408 111.048 ;
     RECT  132.304 112.416 137.408 112.44 ;
     RECT  132.304 122.64 137.408 122.664 ;
     RECT  132.304 124.656 137.408 124.68 ;
     RECT  132.304 146.688 137.408 146.712 ;
     RECT  132.304 154.272 137.408 154.536 ;
     RECT  132.304 161.808 137.408 161.832 ;
     RECT  137.408 2.148 137.512 244.092 ;
     RECT  137.512 2.418 137.704 243.822 ;
     RECT  137.704 94.848 142.808 94.872 ;
     RECT  137.704 97.776 142.808 97.8 ;
     RECT  137.704 105.408 142.808 106.248 ;
     RECT  137.704 109.152 142.808 111.048 ;
     RECT  137.704 112.416 142.808 112.44 ;
     RECT  137.704 122.64 142.808 122.664 ;
     RECT  137.704 124.656 142.808 124.68 ;
     RECT  137.704 146.688 142.808 146.712 ;
     RECT  137.704 154.272 142.808 154.536 ;
     RECT  137.704 161.808 142.808 161.832 ;
     RECT  142.808 2.148 142.912 244.092 ;
     RECT  142.912 2.418 143.104 243.822 ;
     RECT  143.104 122.64 145.069 122.664 ;
     RECT  143.104 94.848 146.041 94.872 ;
     RECT  143.104 109.152 146.221 111.048 ;
     RECT  143.104 112.416 146.221 112.44 ;
     RECT  143.104 97.776 146.245 97.8 ;
     RECT  146.041 94.848 146.291 95.736 ;
     RECT  146.245 96.96 146.332 97.8 ;
     RECT  146.257 127.68 146.341 127.704 ;
     RECT  143.104 105.408 146.473 106.248 ;
     RECT  146.332 97.152 146.581 97.8 ;
     RECT  146.581 97.152 146.627 98.376 ;
     RECT  146.545 99.744 146.629 99.768 ;
     RECT  146.221 109.152 146.771 112.44 ;
     RECT  146.965 119.136 146.972 119.16 ;
     RECT  146.005 117.408 147.011 117.432 ;
     RECT  146.972 119.136 147.013 119.544 ;
     RECT  146.965 103.632 147.052 103.656 ;
     RECT  147.013 119.136 147.053 120.072 ;
     RECT  147.053 119.52 147.059 120.072 ;
     RECT  143.104 146.688 147.201 146.712 ;
     RECT  147.253 150.144 147.265 150.168 ;
     RECT  147.265 136.128 147.273 136.152 ;
     RECT  143.104 124.656 147.293 124.68 ;
     RECT  147.212 129.936 147.308 129.96 ;
     RECT  147.253 132.864 147.308 132.888 ;
     RECT  147.288 133.968 147.308 133.992 ;
     RECT  147.059 120.048 147.337 120.072 ;
     RECT  147.201 146.64 147.337 146.712 ;
     RECT  147.26 153.12 147.337 153.144 ;
     RECT  143.104 154.272 147.337 154.536 ;
     RECT  145.429 93.504 147.589 93.528 ;
     RECT  146.291 94.848 147.589 94.872 ;
     RECT  145.069 122.592 147.596 122.664 ;
     RECT  147.637 139.824 147.644 139.848 ;
     RECT  147.644 139.824 147.685 139.944 ;
     RECT  147.337 153.12 148.201 154.536 ;
     RECT  147.589 93.504 148.208 94.872 ;
     RECT  147.973 96.288 148.208 96.312 ;
     RECT  146.627 97.392 148.208 98.376 ;
     RECT  147.301 101.856 148.208 101.88 ;
     RECT  146.473 105.312 148.208 106.248 ;
     RECT  146.771 109.152 148.208 111.048 ;
     RECT  146.771 112.416 148.208 112.44 ;
     RECT  147.301 113.856 148.208 113.88 ;
     RECT  147.337 120.048 148.208 121.032 ;
     RECT  147.596 122.064 148.208 122.664 ;
     RECT  147.293 124.656 148.208 124.824 ;
     RECT  146.293 125.904 148.208 125.928 ;
     RECT  147.308 129.792 148.208 129.96 ;
     RECT  146.653 131.232 148.208 131.256 ;
     RECT  147.308 132.864 148.208 133.992 ;
     RECT  147.26 134.976 148.208 135 ;
     RECT  147.273 136.128 148.208 136.2 ;
     RECT  147.553 138.48 148.208 138.504 ;
     RECT  147.685 139.488 148.208 139.944 ;
     RECT  146.545 141.648 148.208 141.672 ;
     RECT  147.637 143.088 148.208 143.112 ;
     RECT  147.517 144.816 148.208 144.84 ;
     RECT  147.337 146.64 148.208 147.048 ;
     RECT  147.265 150.144 148.208 150.456 ;
     RECT  148.201 152.736 148.208 154.536 ;
     RECT  143.104 161.808 148.208 161.832 ;
     RECT  148.208 2.148 148.312 244.092 ;
     RECT  148.312 2.418 148.504 243.822 ;
     RECT  148.504 136.176 148.601 136.2 ;
     RECT  148.504 101.232 148.637 101.88 ;
     RECT  148.504 108.72 148.643 112.44 ;
     RECT  148.504 132.096 148.643 133.416 ;
     RECT  148.504 152.736 148.643 154.536 ;
     RECT  148.504 96.912 148.673 97.56 ;
     RECT  148.504 125.904 148.673 126.504 ;
     RECT  148.673 96.912 148.717 96.984 ;
     RECT  148.504 144.192 148.817 144.84 ;
     RECT  148.637 101.232 148.835 101.784 ;
     RECT  148.504 146.448 148.853 147.624 ;
     RECT  148.835 101.232 148.876 101.256 ;
     RECT  148.643 108.72 149.02 110.28 ;
     RECT  148.504 128.976 149.02 129.96 ;
     RECT  148.504 120.048 149.105 120.216 ;
     RECT  149.02 129.936 149.177 129.96 ;
     RECT  148.504 151.584 149.213 151.608 ;
     RECT  148.504 94.368 149.249 94.872 ;
     RECT  148.673 126 149.285 126.504 ;
     RECT  148.504 122.64 149.315 123.624 ;
     RECT  148.643 132.912 149.315 133.416 ;
     RECT  148.504 149.904 149.315 150.312 ;
     RECT  148.643 154.272 149.315 154.536 ;
     RECT  149.285 126.288 149.321 126.504 ;
     RECT  148.504 113.424 149.357 115.704 ;
     RECT  149.315 150.192 149.357 150.312 ;
     RECT  149.357 113.856 149.363 115.704 ;
     RECT  148.504 116.832 149.363 118.584 ;
     RECT  149.363 117.984 149.393 118.584 ;
     RECT  148.504 139.056 149.411 139.656 ;
     RECT  148.504 140.976 149.429 142.488 ;
     RECT  149.429 140.976 149.452 141 ;
     RECT  148.504 105.024 149.507 107.592 ;
     RECT  149.507 105.024 149.645 106.248 ;
     RECT  149.363 114.528 149.645 114.984 ;
     RECT  148.853 146.496 149.645 147.624 ;
     RECT  148.504 124.656 149.677 124.68 ;
     RECT  149.677 124.656 149.749 124.824 ;
     RECT  148.504 91.728 149.789 92.328 ;
     RECT  149.645 147.6 149.804 147.624 ;
     RECT  148.504 102.864 149.821 102.888 ;
     RECT  149.645 146.496 149.845 146.52 ;
     RECT  149.804 147.6 149.845 148.2 ;
     RECT  149.315 123.6 149.852 123.624 ;
     RECT  149.749 124.656 149.852 124.872 ;
     RECT  149.845 145.872 149.891 146.52 ;
     RECT  149.845 147.6 149.891 149.16 ;
     RECT  149.605 99.696 149.893 99.72 ;
     RECT  148.504 137.472 149.893 137.496 ;
     RECT  149.852 123.6 149.933 124.872 ;
     RECT  149.893 137.376 149.933 137.496 ;
     RECT  148.643 152.736 149.933 152.76 ;
     RECT  149.249 94.368 149.939 94.584 ;
     RECT  149.893 99.696 149.939 100.344 ;
     RECT  149.933 124.176 149.939 124.872 ;
     RECT  149.315 132.912 149.965 132.936 ;
     RECT  149.965 132.816 150.005 132.936 ;
     RECT  149.02 109.44 150.041 110.28 ;
     RECT  149.821 127.92 150.092 127.944 ;
     RECT  150.092 127.92 150.133 128.76 ;
     RECT  150.133 127.392 150.179 128.76 ;
     RECT  149.315 154.272 150.229 154.296 ;
     RECT  149.105 120.192 150.236 120.216 ;
     RECT  148.643 111.84 150.245 112.44 ;
     RECT  149.363 116.832 150.253 116.856 ;
     RECT  150.188 152.784 150.275 152.808 ;
     RECT  150.245 111.84 150.277 112.872 ;
     RECT  149.789 92.304 150.293 92.328 ;
     RECT  150.041 109.44 150.293 109.464 ;
     RECT  150.253 116.256 150.293 116.856 ;
     RECT  150.133 129.984 150.293 130.008 ;
     RECT  150.236 119.664 150.323 120.216 ;
     RECT  150.277 111.696 150.329 112.872 ;
     RECT  150.329 111.696 150.364 112.44 ;
     RECT  149.321 126.288 150.389 126.312 ;
     RECT  150.179 127.392 150.389 127.416 ;
     RECT  150.109 121.488 150.401 121.512 ;
     RECT  148.717 96.96 150.421 96.984 ;
     RECT  150.421 96.96 150.467 97.128 ;
     RECT  149.645 105.024 150.469 105.912 ;
     RECT  149.749 134.496 150.469 134.52 ;
     RECT  150.037 135.6 150.469 135.624 ;
     RECT  149.852 95.616 150.473 95.64 ;
     RECT  150.389 98.64 150.473 98.664 ;
     RECT  150.389 126.288 150.473 127.416 ;
     RECT  150.469 104.256 150.515 105.912 ;
     RECT  150.469 134.496 150.515 135.624 ;
     RECT  149.891 145.872 150.545 145.896 ;
     RECT  150.229 153.888 150.545 154.296 ;
     RECT  150.473 127.392 150.653 127.416 ;
     RECT  149.821 102.864 150.709 102.936 ;
     RECT  149.393 118.512 150.725 118.536 ;
     RECT  150.545 154.272 150.725 154.296 ;
     RECT  150.709 102.528 150.755 102.936 ;
     RECT  150.515 104.256 150.755 104.28 ;
     RECT  150.515 105.888 150.761 105.912 ;
     RECT  150.515 134.496 150.761 135.096 ;
     RECT  149.891 149.136 150.761 149.16 ;
     RECT  149.939 94.512 150.797 94.584 ;
     RECT  150.761 134.496 150.797 134.52 ;
     RECT  149.939 124.656 150.833 124.824 ;
     RECT  150.005 132.816 150.833 132.84 ;
     RECT  150.797 94.56 150.869 94.584 ;
     RECT  149.939 100.32 150.869 100.344 ;
     RECT  150.755 102.528 150.869 102.552 ;
     RECT  150.433 109.392 150.869 109.416 ;
     RECT  149.645 114.528 150.869 114.552 ;
     RECT  150.293 116.256 150.869 116.28 ;
     RECT  149.933 137.376 150.869 137.4 ;
     RECT  149.411 139.056 150.869 139.08 ;
     RECT  149.749 140.736 150.869 140.76 ;
     RECT  148.817 144.192 150.869 144.216 ;
     RECT  149.641 150.432 150.869 150.456 ;
     RECT  150.833 124.656 150.977 124.68 ;
     RECT  149.891 147.6 151.049 147.624 ;
     RECT  150.364 112.416 151.085 112.44 ;
     RECT  150.467 97.104 151.193 97.128 ;
     RECT  149.507 107.568 151.193 107.592 ;
     RECT  149.429 142.464 151.193 142.488 ;
     RECT  153.205 92.832 153.889 92.856 ;
     RECT  153.565 97.584 153.889 97.608 ;
     RECT  153.493 106.656 153.889 106.68 ;
     RECT  153.853 152.88 153.889 152.904 ;
     RECT  153.493 99.744 154.393 99.768 ;
     RECT  153.457 116.592 154.393 116.616 ;
     RECT  153.889 147.696 154.393 147.72 ;
     RECT  153.889 152.016 154.393 152.904 ;
     RECT  153.889 92.832 154.429 93.288 ;
     RECT  153.889 94.992 154.429 95.016 ;
     RECT  153.889 96.288 154.429 97.608 ;
     RECT  154.393 98.88 154.429 99.768 ;
     RECT  153.889 105.792 154.429 106.68 ;
     RECT  153.889 108.384 154.429 108.408 ;
     RECT  154.393 116.16 154.429 116.616 ;
     RECT  153.889 118.752 154.429 118.776 ;
     RECT  153.889 120.912 154.429 120.936 ;
     RECT  153.889 122.64 154.429 122.664 ;
     RECT  154.393 125.232 154.429 125.256 ;
     RECT  153.529 129.12 154.429 129.144 ;
     RECT  153.205 135.168 154.429 135.192 ;
     RECT  154.393 139.056 154.429 139.08 ;
     RECT  153.889 140.352 154.429 140.376 ;
     RECT  153.889 142.08 154.429 142.968 ;
     RECT  154.393 146.832 154.429 147.72 ;
     RECT  153.889 148.992 154.429 149.016 ;
     RECT  154.393 152.016 154.429 153.768 ;
     RECT  154.429 91.968 154.465 129.144 ;
     RECT  154.429 130.416 154.465 154.2 ;
     RECT  154.465 91.968 155.484 154.2 ;
    LAYER M5 ;
     RECT  2.4 2.137 2.52 2.151 ;
     RECT  7.8 2.137 7.92 2.151 ;
     RECT  13.2 2.137 13.32 2.151 ;
     RECT  18.6 2.137 18.72 2.151 ;
     RECT  24 2.137 24.12 2.151 ;
     RECT  29.4 2.137 29.52 2.151 ;
     RECT  34.8 2.137 34.92 2.151 ;
     RECT  40.2 2.137 40.32 2.151 ;
     RECT  45.6 2.137 45.72 2.151 ;
     RECT  51 2.137 51.12 2.151 ;
     RECT  56.4 2.137 56.52 2.151 ;
     RECT  61.8 2.137 61.92 2.151 ;
     RECT  67.2 2.137 67.32 2.151 ;
     RECT  72.6 2.137 72.72 2.151 ;
     RECT  78 2.137 78.12 2.151 ;
     RECT  83.4 2.137 83.52 2.151 ;
     RECT  88.8 2.137 88.92 2.151 ;
     RECT  94.2 2.137 94.32 2.151 ;
     RECT  99.6 2.137 99.72 2.151 ;
     RECT  105 2.137 105.12 2.151 ;
     RECT  110.4 2.137 110.52 2.151 ;
     RECT  115.8 2.137 115.92 2.151 ;
     RECT  121.2 2.137 121.32 2.151 ;
     RECT  126.6 2.137 126.72 2.151 ;
     RECT  132 2.137 132.12 2.151 ;
     RECT  137.4 2.137 137.52 2.151 ;
     RECT  142.8 2.137 142.92 2.151 ;
     RECT  148.2 2.137 148.32 2.151 ;
     RECT  2.4 2.151 2.712 6.277 ;
     RECT  6.576 6.805 6.6 7.381 ;
     RECT  7.8 2.151 8.112 7.381 ;
     RECT  4.848 8.341 4.872 8.485 ;
     RECT  6.576 7.381 8.112 8.821 ;
     RECT  6.432 8.821 8.112 9.011 ;
     RECT  2.4 6.277 3.288 9.539 ;
     RECT  6.432 9.011 6.6 9.731 ;
     RECT  4.848 8.485 5.064 9.925 ;
     RECT  4.848 9.925 5.496 10.019 ;
     RECT  4.896 10.019 5.496 11.029 ;
     RECT  6.576 9.731 6.6 11.029 ;
     RECT  7.8 9.011 8.112 11.125 ;
     RECT  9.12 7.333 9.144 11.125 ;
     RECT  4.896 11.029 6.6 11.173 ;
     RECT  7.8 11.125 9.144 11.365 ;
     RECT  7.8 11.365 9.576 12.323 ;
     RECT  4.8 11.173 6.6 13.283 ;
     RECT  2.4 9.539 2.712 13.333 ;
     RECT  2.4 13.333 2.808 13.621 ;
     RECT  9.12 12.323 9.576 13.621 ;
     RECT  2.304 13.621 2.808 13.667 ;
     RECT  4.944 13.283 6.6 17.077 ;
     RECT  3.984 17.077 6.6 17.315 ;
     RECT  3.984 17.315 5.208 18.181 ;
     RECT  3.696 18.181 5.208 20.051 ;
     RECT  3.696 20.051 3.72 22.069 ;
     RECT  4.944 20.051 5.208 22.069 ;
     RECT  7.8 12.323 8.112 22.741 ;
     RECT  9.12 13.621 10.488 22.741 ;
     RECT  3.696 22.069 5.208 23.987 ;
     RECT  3.696 23.987 5.064 25.045 ;
     RECT  6.24 17.315 6.6 25.045 ;
     RECT  3.696 25.045 6.6 25.667 ;
     RECT  4.944 25.667 6.6 25.715 ;
     RECT  3.696 25.667 3.72 27.301 ;
     RECT  4.944 25.715 5.256 27.301 ;
     RECT  3.696 27.301 5.256 28.453 ;
     RECT  6.24 25.715 6.6 28.453 ;
     RECT  3.696 28.453 6.6 28.547 ;
     RECT  2.304 13.667 2.712 29.797 ;
     RECT  3.696 28.547 3.72 29.797 ;
     RECT  2.304 29.797 3.72 29.891 ;
     RECT  4.944 28.547 6.6 30.133 ;
     RECT  7.8 22.741 10.488 30.133 ;
     RECT  2.4 29.891 3.72 36.373 ;
     RECT  4.944 30.133 10.488 36.373 ;
     RECT  2.4 36.373 10.488 36.515 ;
     RECT  13.2 2.151 13.512 36.517 ;
     RECT  4.944 36.515 10.488 39.923 ;
     RECT  2.4 36.515 3.72 42.565 ;
     RECT  4.944 39.923 5.256 42.803 ;
     RECT  5.04 42.803 5.256 45.349 ;
     RECT  4.848 45.349 5.256 45.395 ;
     RECT  2.304 42.565 3.72 46.787 ;
     RECT  6.24 39.923 10.488 47.413 ;
     RECT  6.144 47.413 10.488 49.187 ;
     RECT  4.848 45.395 5.112 50.389 ;
     RECT  6.24 49.187 10.488 50.389 ;
     RECT  2.4 46.787 3.72 50.965 ;
     RECT  4.848 50.389 10.488 50.965 ;
     RECT  2.4 50.965 10.488 51.011 ;
     RECT  2.4 51.011 5.064 52.499 ;
     RECT  13.2 36.517 13.848 53.797 ;
     RECT  2.4 52.499 3.72 53.941 ;
     RECT  4.848 52.499 5.064 53.941 ;
     RECT  2.4 53.941 5.064 54.133 ;
     RECT  2.4 54.133 5.112 54.613 ;
     RECT  6.24 51.011 10.488 54.613 ;
     RECT  2.4 54.613 10.488 54.659 ;
     RECT  2.4 54.659 3.912 54.755 ;
     RECT  2.4 54.755 3.72 56.485 ;
     RECT  4.944 54.659 10.488 56.485 ;
     RECT  2.4 56.485 10.488 56.531 ;
     RECT  6.24 56.531 10.488 57.589 ;
     RECT  2.4 56.531 5.112 58.643 ;
     RECT  18.6 2.151 18.912 59.749 ;
     RECT  2.4 58.643 3.72 60.373 ;
     RECT  4.944 58.643 5.112 60.373 ;
     RECT  2.4 60.373 5.112 60.949 ;
     RECT  6.24 57.589 10.968 60.949 ;
     RECT  2.4 60.949 10.968 62.485 ;
     RECT  1.632 62.485 10.968 66.085 ;
     RECT  12.24 53.797 13.848 66.085 ;
     RECT  18.6 59.749 19.032 68.629 ;
     RECT  1.632 66.085 13.848 72.325 ;
     RECT  26.784 69.445 26.808 72.757 ;
     RECT  18.6 68.629 19.848 74.053 ;
     RECT  26.208 72.757 26.808 74.581 ;
     RECT  1.632 72.325 14.376 75.397 ;
     RECT  1.632 75.397 14.76 75.539 ;
     RECT  26.208 74.581 26.856 75.733 ;
     RECT  15.936 75.397 15.96 75.829 ;
     RECT  15.936 75.829 16.2 75.877 ;
     RECT  17.424 72.949 17.448 75.877 ;
     RECT  24 2.151 24.312 76.213 ;
     RECT  25.728 75.733 26.856 76.213 ;
     RECT  18.6 74.053 20.808 76.741 ;
     RECT  1.632 75.539 14.424 76.837 ;
     RECT  15.936 75.877 17.448 76.837 ;
     RECT  18.48 76.741 20.808 76.837 ;
     RECT  24 76.213 26.856 77.701 ;
     RECT  23.328 77.701 26.856 78.133 ;
     RECT  1.632 76.837 20.808 78.277 ;
     RECT  1.632 78.277 21.672 78.901 ;
     RECT  22.656 78.133 26.856 78.901 ;
     RECT  1.632 78.901 26.856 78.949 ;
     RECT  1.536 78.949 26.856 79.525 ;
     RECT  94.2 2.151 94.512 90.517 ;
     RECT  148.2 2.151 148.512 91.717 ;
     RECT  0.96 79.525 26.856 94.837 ;
     RECT  148.2 91.717 148.68 96.277 ;
     RECT  147.984 96.277 148.68 96.947 ;
     RECT  149.904 94.357 149.928 96.949 ;
     RECT  146.256 95.701 146.28 96.995 ;
     RECT  149.904 96.949 150.456 96.995 ;
     RECT  147.984 96.947 148.512 97.427 ;
     RECT  94.08 90.517 94.512 97.523 ;
     RECT  150.432 96.995 150.456 98.675 ;
     RECT  146.592 97.141 146.616 99.779 ;
     RECT  149.904 99.685 149.928 100.355 ;
     RECT  148.2 97.427 148.512 101.221 ;
     RECT  148.2 101.221 148.824 102.899 ;
     RECT  150.72 102.517 150.744 104.245 ;
     RECT  150.48 104.245 150.744 104.291 ;
     RECT  148.2 102.899 148.512 105.253 ;
     RECT  146.976 103.621 147 105.349 ;
     RECT  146.736 105.349 147 105.395 ;
     RECT  150.48 104.291 150.504 105.923 ;
     RECT  95.904 97.765 95.928 106.021 ;
     RECT  95.76 106.021 95.928 106.067 ;
     RECT  95.76 106.067 95.784 106.211 ;
     RECT  148.2 105.253 149.304 106.597 ;
     RECT  148.2 106.597 149.496 107.603 ;
     RECT  53.328 90.565 53.352 109.381 ;
     RECT  146.736 105.395 146.76 109.957 ;
     RECT  146.736 109.957 147.048 110.627 ;
     RECT  53.328 109.381 54.312 111.779 ;
     RECT  146.736 110.627 146.76 111.779 ;
     RECT  150.288 111.685 150.312 112.883 ;
     RECT  148.2 107.603 149.304 113.845 ;
     RECT  148.2 113.845 149.352 118.019 ;
     RECT  146.976 117.397 147 119.171 ;
     RECT  147.024 119.509 147.048 120.037 ;
     RECT  148.2 118.019 149.304 120.037 ;
     RECT  147.024 120.037 149.304 120.083 ;
     RECT  150.288 118.501 150.312 121.523 ;
     RECT  147.648 120.083 149.304 122.099 ;
     RECT  148.2 122.099 149.304 122.675 ;
     RECT  0.48 94.837 26.856 123.251 ;
     RECT  78 2.151 78.312 123.541 ;
     RECT  53.808 111.779 54.312 123.637 ;
     RECT  148.2 122.675 148.632 124.789 ;
     RECT  149.904 124.165 149.928 124.883 ;
     RECT  147.312 124.789 148.632 125.939 ;
     RECT  148.2 125.939 148.632 126.469 ;
     RECT  154.464 126.517 154.488 126.659 ;
     RECT  0.48 123.251 25.8 127.379 ;
     RECT  148.2 126.469 149.304 127.381 ;
     RECT  150.432 126.853 150.456 127.381 ;
     RECT  148.2 127.381 150.456 127.427 ;
     RECT  146.304 125.893 146.328 127.715 ;
     RECT  148.2 127.427 150.168 129.781 ;
     RECT  147.36 129.781 150.168 129.925 ;
     RECT  147.264 129.925 150.168 130.019 ;
     RECT  0.48 127.379 25.368 130.787 ;
     RECT  0.48 130.787 25.272 131.603 ;
     RECT  147.264 130.019 149.304 132.899 ;
     RECT  23.088 131.603 25.272 133.283 ;
     RECT  23.472 133.283 25.272 133.427 ;
     RECT  147.36 132.899 149.304 133.427 ;
     RECT  24 133.427 25.272 133.811 ;
     RECT  0.48 131.603 21.768 133.907 ;
     RECT  147.36 133.427 149.016 134.003 ;
     RECT  53.712 123.637 54.312 134.579 ;
     RECT  26.784 123.251 26.856 134.627 ;
     RECT  147.456 134.003 149.016 134.965 ;
     RECT  54.288 134.579 54.312 135.061 ;
     RECT  0.48 133.907 21.672 135.155 ;
     RECT  0.48 135.155 21.048 135.683 ;
     RECT  147.312 134.965 149.016 136.211 ;
     RECT  0.48 135.683 20.04 136.259 ;
     RECT  17.424 136.259 20.04 136.451 ;
     RECT  150.48 132.805 150.504 137.411 ;
     RECT  147.792 136.211 149.016 138.469 ;
     RECT  147.696 138.469 149.016 139.045 ;
     RECT  38.88 129.349 38.904 139.523 ;
     RECT  17.424 136.451 19.416 139.813 ;
     RECT  147.696 139.045 149.4 139.813 ;
     RECT  147.648 139.813 149.4 141.011 ;
     RECT  0.48 136.259 16.44 141.539 ;
     RECT  17.424 139.813 19.992 141.541 ;
     RECT  21.024 135.683 21.048 141.541 ;
     RECT  0.48 141.539 16.248 145.379 ;
     RECT  16.224 145.379 16.248 145.811 ;
     RECT  147.648 141.011 149.16 145.861 ;
     RECT  147.648 145.861 149.88 146.531 ;
     RECT  147.648 146.531 149.16 146.629 ;
     RECT  54.288 135.061 55.272 146.723 ;
     RECT  17.424 141.541 21.048 146.771 ;
     RECT  17.424 146.771 18.912 147.347 ;
     RECT  147.264 146.629 149.16 148.165 ;
     RECT  15.072 145.379 15.24 148.259 ;
     RECT  17.424 147.347 17.592 149.125 ;
     RECT  18.6 147.347 18.912 149.125 ;
     RECT  147.264 148.165 149.88 149.171 ;
     RECT  17.424 149.125 18.912 149.461 ;
     RECT  147.264 149.171 149.304 150.179 ;
     RECT  17.328 149.461 18.912 150.469 ;
     RECT  20.112 146.771 21.048 150.515 ;
     RECT  17.328 150.469 19.032 150.803 ;
     RECT  17.328 150.803 18.912 151.667 ;
     RECT  147.312 150.179 149.304 152.773 ;
     RECT  15.072 148.259 15.096 153.203 ;
     RECT  103.488 122.629 103.512 153.923 ;
     RECT  147.312 152.773 150.264 153.923 ;
     RECT  71.28 139.621 71.304 154.115 ;
     RECT  88.8 2.151 89.112 154.309 ;
     RECT  17.664 151.667 18.912 154.499 ;
     RECT  20.112 150.515 20.376 154.499 ;
     RECT  147.312 153.923 149.304 154.547 ;
     RECT  72.6 2.151 72.912 154.981 ;
     RECT  88.32 154.309 89.112 155.075 ;
     RECT  16.416 155.125 16.44 155.221 ;
     RECT  16.32 155.221 16.44 155.267 ;
     RECT  16.32 155.267 16.344 155.363 ;
     RECT  68.928 154.501 68.952 156.227 ;
     RECT  55.248 146.723 55.272 156.515 ;
     RECT  17.712 154.499 18.912 156.563 ;
     RECT  18.144 156.563 18.912 156.995 ;
     RECT  26.784 134.627 26.808 157.043 ;
     RECT  18.6 156.995 18.912 159.157 ;
     RECT  20.256 154.499 20.376 159.203 ;
     RECT  20.352 159.203 20.376 159.347 ;
     RECT  18.6 159.157 19.08 159.397 ;
     RECT  18.24 159.397 19.08 161.603 ;
     RECT  147.312 154.547 148.512 161.843 ;
     RECT  16.512 160.741 16.536 162.373 ;
     RECT  18.24 161.603 18.912 162.707 ;
     RECT  15.936 162.373 16.536 162.995 ;
     RECT  0.48 145.379 13.992 163.187 ;
     RECT  0.48 163.187 13.944 163.669 ;
     RECT  16.512 162.995 16.536 164.003 ;
     RECT  0.144 163.669 13.944 164.291 ;
     RECT  72.6 154.981 73.512 164.771 ;
     RECT  0.48 164.291 13.944 168.419 ;
     RECT  22.464 156.661 22.488 173.891 ;
     RECT  0.528 168.419 13.944 178.307 ;
     RECT  0.528 178.307 13.512 179.411 ;
     RECT  9.216 179.411 13.512 181.523 ;
     RECT  9.216 181.523 11.016 188.003 ;
     RECT  12 181.523 13.512 193.955 ;
     RECT  0.528 179.411 8.232 195.827 ;
     RECT  12 193.955 12.072 199.331 ;
     RECT  0.528 195.827 6.744 203.555 ;
     RECT  0.528 203.555 2.856 204.565 ;
     RECT  3.888 203.555 6.744 204.565 ;
     RECT  7.8 195.827 8.232 206.483 ;
     RECT  9.216 188.003 10.92 206.963 ;
     RECT  0.528 204.565 6.744 209.843 ;
     RECT  0.528 209.843 3.912 210.805 ;
     RECT  4.896 209.843 6.744 210.805 ;
     RECT  0.528 210.805 6.744 210.947 ;
     RECT  0.528 210.947 2.904 213.203 ;
     RECT  3.888 210.947 6.744 213.635 ;
     RECT  72.6 164.771 73.224 215.555 ;
     RECT  3.888 213.635 3.912 217.717 ;
     RECT  4.896 213.635 6.744 217.717 ;
     RECT  3.888 217.717 6.744 220.643 ;
     RECT  3.888 220.643 4.824 223.475 ;
     RECT  0.528 213.203 2.856 223.715 ;
     RECT  4.752 223.475 4.824 225.205 ;
     RECT  3.984 225.205 4.824 225.779 ;
     RECT  9.216 206.963 10.872 226.355 ;
     RECT  12.048 199.331 12.072 226.643 ;
     RECT  4.032 225.779 4.824 227.411 ;
     RECT  10.272 226.355 10.872 227.459 ;
     RECT  4.8 227.411 4.824 227.941 ;
     RECT  5.808 220.643 6.744 227.941 ;
     RECT  4.8 227.941 6.744 228.517 ;
     RECT  4.752 228.517 6.744 228.563 ;
     RECT  4.752 228.563 4.824 230.867 ;
     RECT  0.528 223.715 0.552 231.059 ;
     RECT  1.632 223.715 2.856 232.501 ;
     RECT  9.216 226.355 9.24 232.835 ;
     RECT  1.632 232.501 3.816 232.883 ;
     RECT  2.4 232.883 3.816 233.891 ;
     RECT  4.8 230.867 4.824 234.229 ;
     RECT  3.84 234.229 4.824 234.371 ;
     RECT  10.848 227.459 10.872 235.139 ;
     RECT  4.8 234.371 4.824 236.003 ;
     RECT  5.808 228.563 6.744 236.579 ;
     RECT  5.808 236.579 5.832 237.155 ;
     RECT  4.848 237.637 4.872 238.739 ;
     RECT  2.4 233.891 2.712 244.089 ;
     RECT  7.8 206.483 8.112 244.089 ;
     RECT  13.2 193.955 13.512 244.089 ;
     RECT  18.6 162.707 18.912 244.089 ;
     RECT  24 133.811 24.312 244.089 ;
     RECT  29.4 2.151 29.712 244.089 ;
     RECT  34.8 2.151 35.112 244.089 ;
     RECT  40.2 2.151 40.512 244.089 ;
     RECT  45.6 2.151 45.912 244.089 ;
     RECT  51 2.151 51.312 244.089 ;
     RECT  56.4 2.151 56.712 244.089 ;
     RECT  61.8 2.151 62.112 244.089 ;
     RECT  67.2 2.151 67.512 244.089 ;
     RECT  72.6 215.555 72.912 244.089 ;
     RECT  77.52 123.541 78.312 244.089 ;
     RECT  83.4 2.151 83.712 244.089 ;
     RECT  88.8 155.075 89.112 244.089 ;
     RECT  94.2 97.523 94.512 244.089 ;
     RECT  99.6 2.151 99.912 244.089 ;
     RECT  105 2.151 105.312 244.089 ;
     RECT  110.4 2.151 110.712 244.089 ;
     RECT  115.8 2.151 116.112 244.089 ;
     RECT  121.2 2.151 121.512 244.089 ;
     RECT  126.6 2.151 126.912 244.089 ;
     RECT  132 2.151 132.312 244.089 ;
     RECT  137.4 2.151 137.712 244.089 ;
     RECT  142.8 2.151 143.112 244.089 ;
     RECT  148.2 161.843 148.512 244.089 ;
     RECT  2.4 244.089 2.52 244.103 ;
     RECT  7.8 244.089 7.92 244.103 ;
     RECT  13.2 244.089 13.32 244.103 ;
     RECT  18.6 244.089 18.72 244.103 ;
     RECT  24 244.089 24.12 244.103 ;
     RECT  29.4 244.089 29.52 244.103 ;
     RECT  34.8 244.089 34.92 244.103 ;
     RECT  40.2 244.089 40.32 244.103 ;
     RECT  45.6 244.089 45.72 244.103 ;
     RECT  51 244.089 51.12 244.103 ;
     RECT  56.4 244.089 56.52 244.103 ;
     RECT  61.8 244.089 61.92 244.103 ;
     RECT  67.2 244.089 67.32 244.103 ;
     RECT  72.6 244.089 72.72 244.103 ;
     RECT  77.52 244.089 78.12 244.103 ;
     RECT  83.4 244.089 83.52 244.103 ;
     RECT  88.8 244.089 88.92 244.103 ;
     RECT  94.2 244.089 94.32 244.103 ;
     RECT  99.6 244.089 99.72 244.103 ;
     RECT  105 244.089 105.12 244.103 ;
     RECT  110.4 244.089 110.52 244.103 ;
     RECT  115.8 244.089 115.92 244.103 ;
     RECT  121.2 244.089 121.32 244.103 ;
     RECT  126.6 244.089 126.72 244.103 ;
     RECT  132 244.089 132.12 244.103 ;
     RECT  137.4 244.089 137.52 244.103 ;
     RECT  142.8 244.089 142.92 244.103 ;
     RECT  148.2 244.089 148.32 244.103 ;
     RECT  77.52 244.103 77.88 246.085 ;
     RECT  77.52 246.085 77.976 246.224 ;
     RECT  6.6 6.805 7.8 7.381 ;
     RECT  8.112 7.333 9.12 11.125 ;
     RECT  5.064 8.485 6.576 8.821 ;
     RECT  5.064 8.821 6.432 9.731 ;
     RECT  6.6 9.011 7.8 30.133 ;
     RECT  5.064 9.731 6.576 9.925 ;
     RECT  5.496 9.925 6.576 11.029 ;
     RECT  4.848 10.019 4.896 11.173 ;
     RECT  8.112 12.323 9.12 22.741 ;
     RECT  2.712 17.077 3.984 18.181 ;
     RECT  5.208 17.315 6.24 23.987 ;
     RECT  2.712 18.181 3.696 29.797 ;
     RECT  3.72 20.051 4.944 22.069 ;
     RECT  5.064 23.987 6.24 25.045 ;
     RECT  3.72 25.667 4.944 27.301 ;
     RECT  5.256 25.715 6.24 28.453 ;
     RECT  3.72 28.547 4.944 36.373 ;
     RECT  3.72 36.515 4.944 42.803 ;
     RECT  5.256 39.923 6.24 45.395 ;
     RECT  3.72 42.803 5.04 45.349 ;
     RECT  3.72 45.349 4.848 50.965 ;
     RECT  5.112 45.395 6.24 47.413 ;
     RECT  5.112 47.413 6.144 49.187 ;
     RECT  5.112 49.187 6.24 50.389 ;
     RECT  5.064 51.011 6.24 54.133 ;
     RECT  3.72 52.499 4.848 53.941 ;
     RECT  5.112 54.133 6.24 54.613 ;
     RECT  3.912 54.659 4.944 54.755 ;
     RECT  3.72 54.755 4.944 56.485 ;
     RECT  5.112 56.531 6.24 60.949 ;
     RECT  10.968 57.589 12.24 66.085 ;
     RECT  3.72 58.643 4.944 60.373 ;
     RECT  17.448 72.949 18.6 76.741 ;
     RECT  14.76 75.397 15.936 75.539 ;
     RECT  15.96 75.397 17.424 75.829 ;
     RECT  14.424 75.539 15.936 76.837 ;
     RECT  24.312 75.733 25.728 76.213 ;
     RECT  16.2 75.829 17.424 75.877 ;
     RECT  17.448 76.741 18.48 76.837 ;
     RECT  21.672 78.277 22.656 78.901 ;
     RECT  148.68 94.357 149.904 96.947 ;
     RECT  148.512 96.947 149.904 96.995 ;
     RECT  146.616 97.141 147.984 97.427 ;
     RECT  94.512 97.765 95.904 106.021 ;
     RECT  148.512 99.685 149.904 100.355 ;
     RECT  148.512 100.355 148.824 101.221 ;
     RECT  147 103.621 148.2 105.395 ;
     RECT  149.304 105.253 150.48 105.923 ;
     RECT  146.76 105.395 148.2 109.957 ;
     RECT  149.304 105.923 149.496 106.597 ;
     RECT  94.512 106.021 95.76 106.211 ;
     RECT  147.048 109.957 148.2 110.627 ;
     RECT  146.76 110.627 148.2 111.779 ;
     RECT  149.304 111.685 150.288 112.883 ;
     RECT  149.304 112.883 149.352 113.845 ;
     RECT  147 117.397 148.2 119.171 ;
     RECT  149.304 118.019 149.352 118.501 ;
     RECT  149.304 118.501 150.288 121.523 ;
     RECT  147.024 119.171 148.2 119.509 ;
     RECT  147.048 119.509 148.2 120.037 ;
     RECT  103.512 122.629 105 153.923 ;
     RECT  148.632 122.675 149.304 124.165 ;
     RECT  25.8 123.251 26.784 127.379 ;
     RECT  148.632 124.165 149.904 124.883 ;
     RECT  146.328 125.893 147.312 125.939 ;
     RECT  149.304 126.853 150.432 127.381 ;
     RECT  25.368 127.379 26.784 130.787 ;
     RECT  38.904 129.349 40.2 139.523 ;
     RECT  25.272 130.787 26.784 133.811 ;
     RECT  21.768 131.603 23.088 133.283 ;
     RECT  149.304 132.805 150.48 133.427 ;
     RECT  149.016 133.427 150.48 137.411 ;
     RECT  147.36 134.003 147.456 134.965 ;
     RECT  55.272 135.061 56.4 156.515 ;
     RECT  20.04 135.683 21.024 136.451 ;
     RECT  16.44 136.259 17.424 141.539 ;
     RECT  71.304 139.621 72.6 154.115 ;
     RECT  19.992 139.813 21.024 141.541 ;
     RECT  16.248 141.539 17.424 145.811 ;
     RECT  13.992 145.379 15.072 153.203 ;
     RECT  15.24 145.379 16.224 145.811 ;
     RECT  18.912 146.771 20.112 150.469 ;
     RECT  17.592 147.347 18.6 149.125 ;
     RECT  19.032 150.469 20.112 150.803 ;
     RECT  18.912 150.803 20.112 154.499 ;
     RECT  17.664 154.499 17.712 155.125 ;
     RECT  18.912 154.499 20.256 159.157 ;
     RECT  67.512 154.501 68.928 156.227 ;
     RECT  16.44 155.125 17.712 155.267 ;
     RECT  16.344 155.267 17.712 155.363 ;
     RECT  22.488 156.661 24 173.891 ;
     RECT  19.08 159.157 20.256 159.203 ;
     RECT  19.08 159.203 20.352 159.347 ;
     RECT  8.232 179.411 9.216 206.483 ;
     RECT  11.016 181.523 12 188.003 ;
     RECT  10.92 188.003 12 199.331 ;
     RECT  12.072 193.955 13.2 226.643 ;
     RECT  6.744 195.827 7.8 236.579 ;
     RECT  10.92 199.331 12.048 206.963 ;
     RECT  2.856 203.555 3.888 204.565 ;
     RECT  8.112 206.483 9.216 232.835 ;
     RECT  10.872 206.963 12.048 226.643 ;
     RECT  3.912 209.843 4.896 210.805 ;
     RECT  2.904 210.947 3.888 213.203 ;
     RECT  2.856 213.203 3.888 223.475 ;
     RECT  3.912 213.635 4.896 217.717 ;
     RECT  4.824 220.643 5.808 227.941 ;
     RECT  0.552 223.715 1.632 231.059 ;
     RECT  2.856 225.205 3.984 225.779 ;
     RECT  2.856 225.779 4.032 227.411 ;
     RECT  9.24 226.355 10.272 227.459 ;
     RECT  4.752 227.411 4.8 228.517 ;
     RECT  4.824 228.563 5.808 236.003 ;
     RECT  3.816 232.501 4.8 233.891 ;
     RECT  2.712 233.891 4.8 234.229 ;
     RECT  2.712 234.229 3.84 234.371 ;
  END
END dsfd_vm_static_fsr_b1
END LIBRARY
